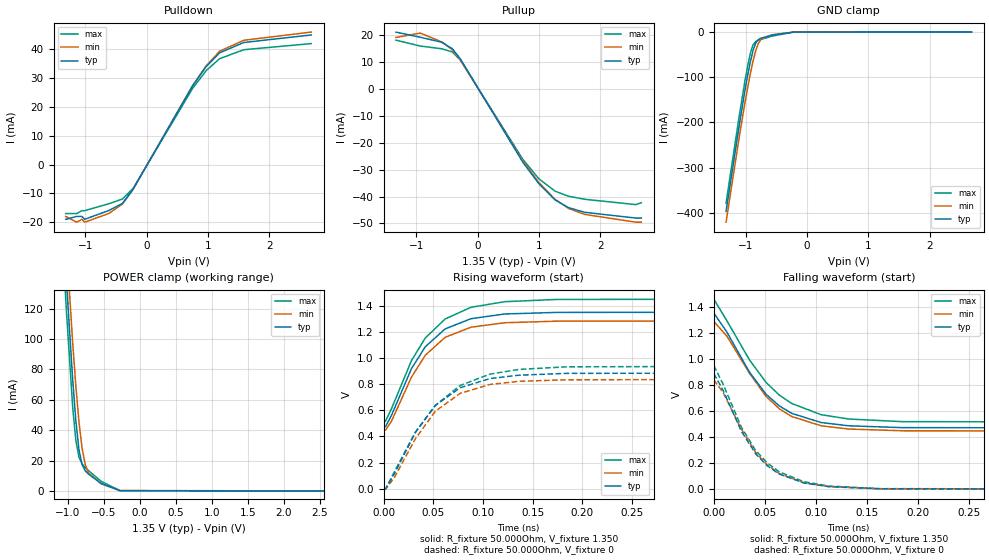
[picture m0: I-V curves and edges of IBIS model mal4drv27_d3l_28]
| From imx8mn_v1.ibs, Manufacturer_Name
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[Model] mal4drv27_d3l_28
Model_type   I/O
Polarity   Non-Inverting
Enable   Active-High
C_comp   1.534pF   1.526pF   1.541pF
C_comp_pullup   672.952fF   657.747fF   679.061fF
C_comp_pulldown 805.206fF   796.471fF   820.214fF
Vinh = 805.000mV
Vinl = 545.000mV
Vmeas = 675.000mV
Vref = 675.000mV
Rref = 50Ohms
Cref = 0pF
[Model Spec]
Vinh   805.000mV   772.000mV   855.000mV
Vinl   545.000mV   512.000mV   595.000mV
Vmeas   675.000mV   642.000mV   725.000mV
Vref   675.000mV   642.000mV   725.000mV
D_overshoot_ampl_h 0.4 NA   NA
D_overshoot_ampl_l 0.4 NA   NA
D_overshoot_area_l 110.000m NA   NA
D_overshoot_area_h 110.000m NA   NA
|[Receiver Thresholds]
|Vth = 675.000mV
|Vth_min = 642.000mV
|Vth_max = 725.000mV
|Vinh_ac = 150.000mV
|Vinh_dc = 100.000mV
|Vinl_ac = -150.000mV
|Vinl_dc = -100.000mV
|Tslew_ac = 5.000ns
|Threshold_sensitivity = 0.5
|Reference_supply Pullup_ref
[Temperature Range]   25.000   125.000   -40.000
[Voltage Range]   1.350V   1.283V   1.450V
[GND Clamp Reference]   0.00V   0.00V   0.00V
|[C Comp Corner]
|| variable   typ   min   max
|C_comp 1.541pF   1.526pF   1.534pF
|C_comp_pullup 679.061fF   657.747fF   672.952fF
|C_comp_pulldown 805.206fF   820.214fF   796.471fF
[Pulldown Reference]   0.00V   0.00V   0.00V
[POWER Clamp Reference]   1.350V   1.283V   1.450V
[Pullup Reference]   1.350V   1.283V   1.450V
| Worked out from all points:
|   slope of the pulldown table from 0 to 0.203 V, typ, clamps not added: 26.2 ohm
|   slope of the pullup table from 0 to 0.203 V, typ, clamps not added: 25.8 ohm
|   GND clamp passes 1 mA (typ) near -0.34 V on its own axis
|   POWER clamp passes 1 mA (typ) near -0.37 V on its own axis
|   rising waveform, R_fixture 50.000Ohm, V_fixture 1.350: 20-80 % time 40.8ps typ, 40.3ps min, 43.2ps max; typ from 0.465 V to 1.35 V
|   rising waveform, R_fixture 50.000Ohm, V_fixture 0: 20-80 % time 48ps typ, 46.9ps min, 54.3ps max; typ from 0 V to 0.885 V
|   falling waveform, R_fixture 50.000Ohm, V_fixture 1.350: 20-80 % time 47.9ps typ, 47.3ps min, 52.8ps max; typ from 1.35 V to 0.469 V
|   falling waveform, R_fixture 50.000Ohm, V_fixture 0: 20-80 % time 40.7ps typ, 41.3ps min, 42.4ps max; typ from 0.887 V to 0 V
[GND Clamp]
-1.318V   -397mA     -421mA     -379mA
-1.099V   -203mA     -229mA     -182mA
-1.011V   -130mA     -157mA     -109mA
-966.7mV  -96.76mA   -124mA     -75.62mA
-922.7mV  -66.15mA   -92.44mA   -47.23mA
-878.8mV  -40.87mA   -64.33mA   -28.32mA
-834.8mV  -24.17mA   -41.16mA   -20.75mA
-790.9mV  -16.5mA    -24.84mA   -17.97mA
-747mV    -13.39mA   -15.69mA   -16.02mA
-571.2mV  -6.876mA   -6.005mA   -9.023mA
-219.7mV  -49.34uA   -80.18uA   -119uA
2.68V     51.21nA    1.31uA     23.01nA
[Power Clamp]
-1.33V    409mA      430mA      393.3mA
-1.111V   214mA      236.6mA    194.7mA
-1.023V   140mA      164.6mA    120.2mA
-934.8mV  73.93mA    98.06mA    55.78mA
-890.9mV  46.71mA    69.56mA    33.54mA
-847mV    27.2mA     45.54mA    22.2mA
-803mV    17.25mA    27.9mA     17.76mA
-759.1mV  13.27mA    17.3mA     15.42mA
-715.2mV  11.13mA    11.9mA     13.45mA
-539.4mV  4.955mA    4.74mA     6.349mA
-275.8mV  101uA      270.7uA    142.8uA
2.668V    -162nA     -1.898uA   -65.08nA
[Pulldown]
-1.318V   -19mA      -18mA      -17mA
-1.142V   -18mA      -20mA      -17mA
-1.054V   -18mA      -19mA      -16mA
-1.011V   -19mA      -20mA      -16mA
-615.2mV  -15.94mA   -16.96mA   -13.59mA
-395.5mV  -13.48mA   -13.72mA   -11.96mA
-219.7mV  -8.487mA   -8.449mA   -8.219mA
747mV     27.29mA    27.39mA    26.42mA
966.7mV   33.95mA    34.22mA    32.56mA
1.186V    38.77mA    39.33mA    36.76mA
1.582V    42.39mA    43.16mA    39.88mA
2.68V     45mA       46mA       42mA
[Pullup]
-1.33V    21mA       19mA       18mA
-934.8mV  19.09mA    20.63mA    15.83mA
-583.3mV  17.23mA    17.37mA    14.8mA
-407.6mV  14.77mA    14.35mA    13.61mA
-275.8mV  10.89mA    10.56mA    10.47mA
734.8mV   -27.19mA   -26.69mA   -26.12mA
998.5mV   -35.28mA   -34.76mA   -33.41mA
1.262V    -41.24mA   -41.05mA   -38.01mA
1.482V    -44.12mA   -44.44mA   -39.9mA
1.746V    -45.85mA   -46.64mA   -41.02mA
2.58V     -48mA      -49.52mA   -43mA
2.668V    -48mA      -49.52mA   -42.28mA
[Ramp]
R_load=50.000Ohm
dV/dt_r   529.800mV/45.500ps  502.199mV/45.000ps  562.200mV/49.500ps
dV/dt_f   529.800mV/45.500ps  502.199mV/45.000ps  562.200mV/49.000ps
[Rising waveform]
R_fixture=50.000Ohm
V_fixture=1.350
V_fixture_min=1.283
V_fixture_max=1.450
0s        465mV      441mV      506mV
2ps       476mV      450mV      518mV
8ps       563mV      518mV      614mV
28ps      918mV      853mV      979mV
42ps      1.086V     1.021V     1.153V
62ps      1.222V     1.158V     1.298V
88ps      1.3V       1.235V     1.387V
122ps     1.336V     1.269V     1.43V
174ps     1.348V     1.281V     1.447V
470ps     1.35V      1.283V     1.45V
[Rising waveform]
R_fixture=50.000Ohm
V_fixture=0
0s        -21.58uV   -3.15mV    -739.6uV
2ps       -21.58uV   -3.15mV    -739.6uV
11ps      117mV      88.59mV    133mV
32ps      431mV      383mV      433mV
52ps      636mV      592mV      637mV
77ps      772mV      729mV      789mV
107ps     842mV      797mV      876mV
136ps     868mV      821mV      912mV
184ps     882mV      833mV      932mV
471ps     885mV      836mV      938mV
[Falling waveform]
R_fixture=50.000Ohm
V_fixture=1.350
V_fixture_min=1.283
V_fixture_max=1.450
0s        1.352V     1.287V     1.458V
13ps      1.202V     1.172V     1.289V
35ps      896mV      888mV      990mV
51ps      729mV      713mV      820mV
64ps      639mV      617mV      722mV
76ps      582mV      558mV      658mV
105ps     511mV      486mV      571mV
132ps     486mV      461mV      538mV
184ps     472mV      448mV      518mV
470ps     469mV      445mV      514mV
[Falling waveform]
R_fixture=50.000Ohm
V_fixture=0
0s        887mV      838mV      948mV
9ps       759mV      743mV      807mV
27ps      444mV      461mV      475mV
41ps      271mV      282mV      296mV
52ps      181mV      188mV      203mV
64ps      116mV      120mV      133mV
88ps      48.2mV     48.41mV    57.09mV
113ps     19.14mV    19.14mV    23.73mV
162ps     3.15mV     3.058mV    4.146mV
469ps     14.03uV    17.61uV    15.29uV
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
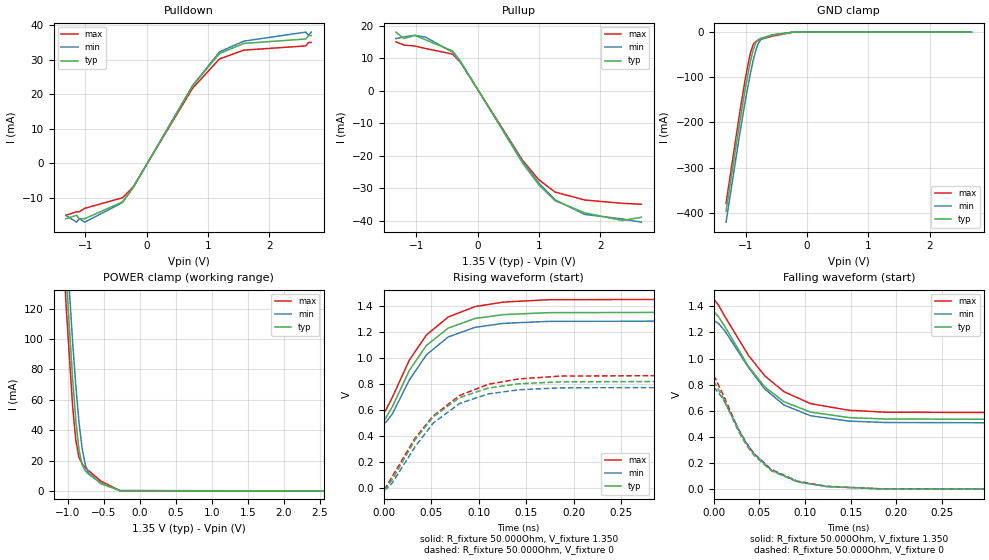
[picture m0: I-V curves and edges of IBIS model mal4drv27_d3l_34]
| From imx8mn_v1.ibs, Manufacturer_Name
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[Model] mal4drv27_d3l_34
Model_type   I/O
Polarity   Non-Inverting
Enable   Active-High
C_comp   1.534pF   1.526pF   1.541pF
C_comp_pullup   672.952fF   657.747fF   679.061fF
C_comp_pulldown 805.206fF   796.471fF   820.214fF
Vinh = 805.000mV
Vinl = 545.000mV
Vmeas = 675.000mV
Vref = 675.000mV
Rref = 50Ohms
Cref = 0pF
[Model Spec]
Vinh   805.000mV   772.000mV   855.000mV
Vinl   545.000mV   512.000mV   595.000mV
Vmeas   675.000mV   642.000mV   725.000mV
Vref   675.000mV   642.000mV   725.000mV
D_overshoot_ampl_h 0.4 NA   NA
D_overshoot_ampl_l 0.4 NA   NA
D_overshoot_area_l 110.000m NA   NA
D_overshoot_area_h 110.000m NA   NA
|[Receiver Thresholds]
|Vth = 675.000mV
|Vth_min = 642.000mV
|Vth_max = 725.000mV
|Vinh_ac = 150.000mV
|Vinh_dc = 100.000mV
|Vinl_ac = -150.000mV
|Vinl_dc = -100.000mV
|Tslew_ac = 5.000ns
|Threshold_sensitivity = 0.5
|Reference_supply Pullup_ref
[Temperature Range]   25.000   125.000   -40.000
[Voltage Range]   1.350V   1.283V   1.450V
[GND Clamp Reference]   0.00V   0.00V   0.00V
|[C Comp Corner]
|| variable   typ   min   max
|C_comp 1.541pF   1.526pF   1.534pF
|C_comp_pullup 679.061fF   657.747fF   672.952fF
|C_comp_pulldown 805.206fF   820.214fF   796.471fF
[Pulldown Reference]   0.00V   0.00V   0.00V
[POWER Clamp Reference]   1.350V   1.283V   1.450V
[Pullup Reference]   1.350V   1.283V   1.450V
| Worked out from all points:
|   slope of the pulldown table from 0 to 0.203 V, typ, clamps not added: 31.9 ohm
|   slope of the pullup table from 0 to 0.203 V, typ, clamps not added: 31.3 ohm
|   GND clamp passes 1 mA (typ) near -0.34 V on its own axis
|   POWER clamp passes 1 mA (typ) near -0.37 V on its own axis
|   rising waveform, R_fixture 50.000Ohm, V_fixture 1.350: 20-80 % time 45.5ps typ, 45.3ps min, 47.7ps max; typ from 0.527 V to 1.35 V
|   rising waveform, R_fixture 50.000Ohm, V_fixture 0: 20-80 % time 54.1ps typ, 52.9ps min, 60.7ps max; typ from -0.004 V to 0.822 V
|   falling waveform, R_fixture 50.000Ohm, V_fixture 1.350: 20-80 % time 54.1ps typ, 53ps min, 58.7ps max; typ from 1.36 V to 0.532 V
|   falling waveform, R_fixture 50.000Ohm, V_fixture 0: 20-80 % time 45.5ps typ, 46ps min, 46.7ps max; typ from 0.826 V to 0 V
[GND Clamp]
-1.318V   -397mA     -421mA     -379mA
-1.099V   -203mA     -229mA     -182mA
-1.011V   -130mA     -157mA     -109mA
-966.7mV  -96.76mA   -124mA     -75.62mA
-922.7mV  -66.15mA   -92.44mA   -47.23mA
-878.8mV  -40.87mA   -64.33mA   -28.32mA
-834.8mV  -24.17mA   -41.16mA   -20.75mA
-790.9mV  -16.5mA    -24.84mA   -17.97mA
-747mV    -13.39mA   -15.69mA   -16.02mA
-571.2mV  -6.876mA   -6.005mA   -9.023mA
-219.7mV  -49.34uA   -80.18uA   -119uA
2.68V     51.21nA    1.31uA     23.01nA
[Power Clamp]
-1.33V    409mA      430mA      393.3mA
-1.111V   214mA      236.6mA    194.7mA
-1.023V   140mA      164.6mA    120.2mA
-934.8mV  73.93mA    98.06mA    55.78mA
-890.9mV  46.71mA    69.56mA    33.54mA
-847mV    27.2mA     45.54mA    22.2mA
-803mV    17.25mA    27.9mA     17.76mA
-759.1mV  13.27mA    17.3mA     15.42mA
-715.2mV  11.13mA    11.9mA     13.45mA
-539.4mV  4.955mA    4.74mA     6.349mA
-275.8mV  101uA      270.7uA    142.8uA
2.668V    -162nA     -1.898uA   -65.08nA
[Pulldown]
-1.318V   -16mA      -15mA      -15mA
-1.142V   -15mA      -17mA      -14mA
-1.099V   -16mA      -16mA      -14mA
-1.011V   -16mA      -17mA      -13mA
-395.5mV  -11.14mA   -11.34mA   -9.931mA
-219.7mV  -6.979mA   -6.949mA   -6.77mA
747mV     22.43mA    22.51mA    21.75mA
1.186V    31.8mA     32.28mA    30.23mA
1.582V    34.72mA    35.38mA    32.78mA
2.592V    36mA       38mA       34mA
2.636V    37mA       37mA       35mA
2.68V     37mA       38mA       35mA
[Pullup]
-1.33V    18mA       16mA       15mA
-1.199V   16mA       16.52mA    14mA
-1.023V   17mA       17mA       13.72mA
-847mV    15.61mA    16.44mA    12.94mA
-407.6mV  12.19mA    11.82mA    11.23mA
-275.8mV  8.959mA    8.681mA    8.62mA
734.8mV   -22.36mA   -21.89mA   -21.49mA
998.5mV   -29mA      -28.5mA    -27.48mA
1.262V    -33.89mA   -33.62mA   -31.24mA
1.746V    -37.65mA   -38.14mA   -33.69mA
2.361V    -40mA      -39.52mA   -34.72mA
2.668V    -39mA      -40.52mA   -35mA
[Ramp]
R_load=50.000Ohm
dV/dt_r   492.000mV/50.500ps  465.898mV/50.000ps  520.800mV/55.500ps
dV/dt_f   492.000mV/51.000ps  465.899mV/50.500ps  520.800mV/53.500ps
[Rising waveform]
R_fixture=50.000Ohm
V_fixture=1.350
V_fixture_min=1.283
V_fixture_max=1.450
0s        527mV      503mV      582mV
2ps       536mV      503mV      594mV
9ps       623mV      568mV      695mV
27ps      903mV      830mV      982mV
45ps      1.095V     1.023V     1.175V
68ps      1.228V     1.16V      1.313V
96ps      1.301V     1.233V     1.392V
126ps     1.331V     1.264V     1.427V
174ps     1.346V     1.279V     1.445V
470ps     1.35V      1.283V     1.45V
[Rising waveform]
R_fixture=50.000Ohm
V_fixture=0
0s        -3.876mV   -3.515mV   -6.368mV
3ps       3.836mV    -3.515mV   14.72mV
9ps       66.86mV    40.56mV    90.27mV
33ps      371mV      318mV      384mV
52ps      547mV      499mV      554mV
80ps      696mV      651mV      712mV
110ps     768mV      723mV      797mV
142ps     801mV      755mV      838mV
186ps     816mV      770mV      860mV
471ps     822mV      775mV      869mV
[Falling waveform]
R_fixture=50.000Ohm
V_fixture=1.350
V_fixture_min=1.283
V_fixture_max=1.450
0s        1.357V     1.288V     1.455V
5ps       1.322V     1.27V      1.41V
12ps      1.246V     1.213V     1.324V
38ps      940mV      932mV      1.024V
56ps      782mV      766mV      867mV
77ps      669mV      644mV      746mV
106ps     590mV      562mV      655mV
148ps     548mV      521mV      604mV
189ps     537mV      510mV      589mV
470ps     532mV      505mV      583mV
[Falling waveform]
R_fixture=50.000Ohm
V_fixture=0
0s        826mV      781mV      872mV
10ps      702mV      694mV      727mV
27ps      443mV      462mV      457mV
36ps      335mV      352mV      349mV
44ps      260mV      273mV      273mV
63ps      141mV      147mV      151mV
92ps      54.91mV    56.83mV    60.65mV
124ps     19.38mV    19.7mV     21.96mV
181ps     3.038mV    2.943mV    3.504mV
469ps     13.3uV     16.64uV    14.35uV
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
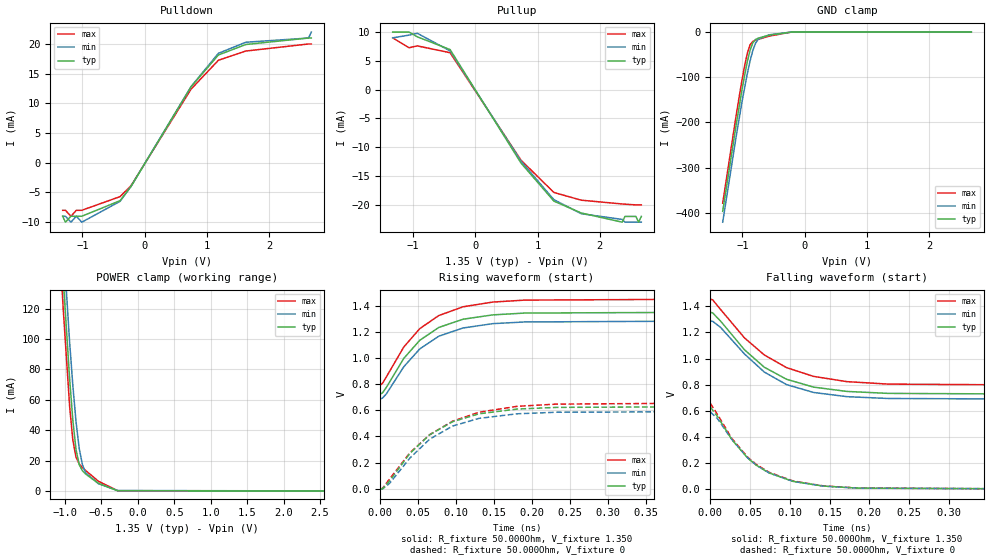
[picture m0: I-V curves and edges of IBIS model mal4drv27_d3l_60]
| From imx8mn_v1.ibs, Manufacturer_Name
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[Model] mal4drv27_d3l_60
Model_type   I/O
Polarity   Non-Inverting
Enable   Active-High
C_comp   1.534pF   1.526pF   1.541pF
C_comp_pullup   672.952fF   657.747fF   679.061fF
C_comp_pulldown 805.206fF   796.471fF   820.214fF
Vinh = 805.000mV
Vinl = 545.000mV
Vmeas = 675.000mV
Vref = 675.000mV
Rref = 50Ohms
Cref = 0pF
[Model Spec]
Vinh   805.000mV   772.000mV   855.000mV
Vinl   545.000mV   512.000mV   595.000mV
Vmeas   675.000mV   642.000mV   725.000mV
Vref   675.000mV   642.000mV   725.000mV
D_overshoot_ampl_h 0.4 NA   NA
D_overshoot_ampl_l 0.4 NA   NA
D_overshoot_area_l 110.000m NA   NA
D_overshoot_area_h 110.000m NA   NA
|[Receiver Thresholds]
|Vth = 675.000mV
|Vth_min = 642.000mV
|Vth_max = 725.000mV
|Vinh_ac = 150.000mV
|Vinh_dc = 100.000mV
|Vinl_ac = -150.000mV
|Vinl_dc = -100.000mV
|Tslew_ac = 5.000ns
|Threshold_sensitivity = 0.5
|Reference_supply Pullup_ref
[Temperature Range]   25.000   125.000   -40.000
[Voltage Range]   1.350V   1.283V   1.450V
[GND Clamp Reference]   0.00V   0.00V   0.00V
|[C Comp Corner]
|| variable   typ   min   max
|C_comp 1.541pF   1.526pF   1.534pF
|C_comp_pullup 679.061fF   657.747fF   672.952fF
|C_comp_pulldown 805.206fF   820.214fF   796.471fF
[Pulldown Reference]   0.00V   0.00V   0.00V
[POWER Clamp Reference]   1.350V   1.283V   1.450V
[Pullup Reference]   1.350V   1.283V   1.450V
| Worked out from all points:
|   slope of the pulldown table from 0 to 0.203 V, typ, clamps not added: 55.9 ohm
|   slope of the pullup table from 0 to 0.203 V, typ, clamps not added: 54.9 ohm
|   GND clamp passes 1 mA (typ) near -0.34 V on its own axis
|   POWER clamp passes 1 mA (typ) near -0.37 V on its own axis
|   rising waveform, R_fixture 50.000Ohm, V_fixture 1.350: 20-80 % time 59.4ps typ, 59.4ps min, 60.8ps max; typ from 0.723 V to 1.35 V
|   rising waveform, R_fixture 50.000Ohm, V_fixture 0: 20-80 % time 71ps typ, 69.2ps min, 79.1ps max; typ from -0.001 V to 0.628 V
|   falling waveform, R_fixture 50.000Ohm, V_fixture 1.350: 20-80 % time 71.1ps typ, 69.1ps min, 77.3ps max; typ from 1.35 V to 0.726 V
|   falling waveform, R_fixture 50.000Ohm, V_fixture 0: 20-80 % time 59.1ps typ, 59.1ps min, 60.2ps max; typ from 0.629 V to 0 V
[GND Clamp]
-1.318V   -397mA     -421mA     -379mA
-1.099V   -203mA     -229mA     -182mA
-1.011V   -130mA     -157mA     -109mA
-966.7mV  -96.76mA   -124mA     -75.62mA
-922.7mV  -66.15mA   -92.44mA   -47.23mA
-878.8mV  -40.87mA   -64.33mA   -28.32mA
-834.8mV  -24.17mA   -41.16mA   -20.75mA
-790.9mV  -16.5mA    -24.84mA   -17.97mA
-747mV    -13.39mA   -15.69mA   -16.02mA
-571.2mV  -6.876mA   -6.005mA   -9.023mA
-219.7mV  -49.34uA   -80.18uA   -119uA
2.68V     51.21nA    1.31uA     23.01nA
[Power Clamp]
-1.33V    409mA      430mA      393.3mA
-1.111V   214mA      236.6mA    194.7mA
-1.023V   140mA      164.6mA    120.2mA
-934.8mV  73.93mA    98.06mA    55.78mA
-890.9mV  46.71mA    69.56mA    33.54mA
-847mV    27.2mA     45.54mA    22.2mA
-803mV    17.25mA    27.9mA     17.76mA
-759.1mV  13.27mA    17.3mA     15.42mA
-715.2mV  11.13mA    11.9mA     13.45mA
-539.4mV  4.955mA    4.74mA     6.349mA
-275.8mV  101uA      270.7uA    142.8uA
2.668V    -162nA     -1.898uA   -65.08nA
[Pulldown]
-1.318V   -9mA       -9mA       -8mA
-1.274V   -10mA      -9mA       -8mA
-1.186V   -9mA       -10mA      -9mA
-1.099V   -9mA       -9mA       -8mA
-1.011V   -9mA       -10mA      -8mA
-395.5mV  -6.38mA    -6.489mA   -5.695mA
-219.7mV  -3.981mA   -3.966mA   -3.865mA
747mV     12.79mA    12.84mA    12.41mA
1.186V    18.15mA    18.43mA    17.26mA
1.626V    19.91mA    20.29mA    18.81mA
2.636V    21mA       21mA       20mA
2.68V     21mA       22mA       20mA
[Pullup]
-1.33V    10mA       9mA        9mA
-1.067V   10mA       9.476mA    7.277mA
-934.8mV  9.18mA     9.795mA    7.605mA
-407.6mV  6.966mA    6.74mA     6.42mA
734.8mV   -12.75mA   -12.45mA   -12.26mA
1.262V    -19.34mA   -19.09mA   -17.84mA
1.702V    -21.4mA    -21.53mA   -19.18mA
2.361V    -23mA      -22.52mA   -19.84mA
2.405V    -22mA      -23mA      -19.87mA
2.58V     -22mA      -23mA      -20mA
2.624V    -23mA      -23mA      -20mA
2.668V    -22mA      -23mA      -20mA
[Ramp]
R_load=50.000Ohm
dV/dt_r   375.600mV/66.000ps  355.498mV/65.500ps  393.300mV/71.000ps
dV/dt_f   375.600mV/66.000ps  355.498mV/65.000ps  393.300mV/69.500ps
[Rising waveform]
R_fixture=50.000Ohm
V_fixture=1.350
V_fixture_min=1.283
V_fixture_max=1.450
0s        723mV      685mV      792mV
3ps       734mV      694mV      807mV
8ps       775mV      725mV      855mV
31ps      997mV      933mV      1.084V
52ps      1.135V     1.069V     1.224V
77ps      1.233V     1.166V     1.324V
109ps     1.296V     1.229V     1.391V
148ps     1.329V     1.262V     1.427V
190ps     1.343V     1.275V     1.442V
470ps     1.35V      1.283V     1.45V
[Rising waveform]
R_fixture=50.000Ohm
V_fixture=0
0s        -959.1uV   -806uV     -3.165mV
3ps       -959.1uV   -806uV     3.463mV
12ps      58.2mV     39.59mV    73.09mV
39ps      270mV      235mV      275mV
65ps      413mV      379mV      413mV
95ps      512mV      479mV      516mV
130ps     573mV      538mV      585mV
180ps     609mV      573mV      630mV
232ps     622mV      585mV      647mV
472ps     628mV      590mV      656mV
[Falling waveform]
R_fixture=50.000Ohm
V_fixture=1.350
V_fixture_min=1.283
V_fixture_max=1.450
0s        1.354V     1.285V     1.455V
3ps       1.349V     1.285V     1.449V
13ps      1.286V     1.238V     1.375V
43ps      1.067V     1.035V     1.158V
68ps      933mV      896mV      1.027V
96ps      841mV      800mV      930mV
130ps     781mV      740mV      863mV
172ps     748mV      708mV      823mV
224ps     733mV      694mV      804mV
471ps     726mV      688mV      795mV
[Falling waveform]
R_fixture=50.000Ohm
V_fixture=0
0s        629mV      591mV      658mV
9ps       557mV      540mV      572mV
27ps      381mV      381mV      389mV
47ps      238mV      239mV      245mV
58ps      183mV      183mV      189mV
74ps      124mV      124mV      129mV
104ps     59.82mV    59.49mV    63.03mV
142ps     23.94mV    23.33mV    25.22mV
185ps     8.191mV    7.985mV    8.853mV
469ps     19.34uV    22.16uV    19.89uV
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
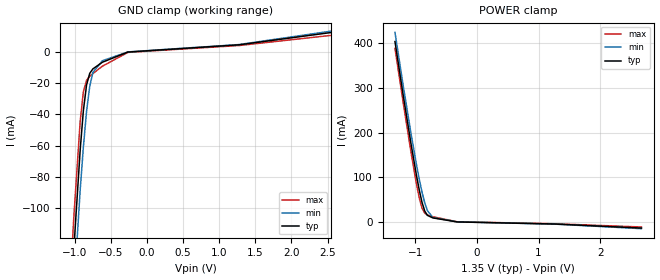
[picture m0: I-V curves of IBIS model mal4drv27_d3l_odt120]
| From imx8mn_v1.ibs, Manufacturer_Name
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[Model] mal4drv27_d3l_odt120
Model_type   Input
Polarity   Non-Inverting
Enable   Active-High
C_comp   1.576pF   1.527pF   1.608pF
C_comp_power_clamp   705.785fF   664.403fF   721.358fF
C_comp_gnd_clamp 804.044fF   799.743fF   804.337fF
Vinh = 805.000mV
Vinl = 545.000mV
[Model Spec]
D_overshoot_ampl_h 0.4 NA   NA
D_overshoot_ampl_l 0.4 NA   NA
D_overshoot_area_l 110.000m NA   NA
D_overshoot_area_h 110.000m NA   NA
|[Receiver Thresholds]
|Vth = 675.000mV
|Vth_min = 642.000mV
|Vth_max = 725.000mV
|Vinh_ac = 150.000mV
|Vinh_dc = 100.000mV
|Vinl_ac = -150.000mV
|Vinl_dc = -100.000mV
|Tslew_ac = 5.000ns
|Threshold_sensitivity = 0.5
|Reference_supply Power_clamp_ref
[Temperature Range]   25.000   125.000   -40.000
[Voltage Range]   1.350V   1.283V   1.450V
[GND Clamp Reference]   0.00V   0.00V   0.00V
|[C Comp Corner]
|| variable   typ   min   max
|C_comp 1.576pF   1.527pF   1.608pF
|C_comp_pullup 705.785fF   664.403fF   721.358fF
|C_comp_pulldown 799.743fF   804.337fF   804.044fF
[POWER Clamp Reference]   1.350V   1.283V   1.450V
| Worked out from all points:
|   GND clamp passes 1 mA (typ) near -0.38 V on its own axis
|   POWER clamp passes 1 mA (typ) near -0.41 V on its own axis
[GND Clamp]
-1.318V   -391.2mA   -414.4mA   -374.1mA
-1.099V   -198.7mA   -224mA     -178.3mA
-1.011V   -126.3mA   -153.6mA   -105.8mA
-922.7mV  -62.55mA   -88.29mA   -44.18mA
-878.8mV  -37.54mA   -60.91mA   -25.48mA
-834.8mV  -21.09mA   -38.03mA   -18.12mA
-790.9mV  -13.68mA   -21.98mA   -15.54mA
-747mV    -10.82mA   -13.11mA   -13.8mA
-615.2mV  -6.544mA   -5.581mA   -9.094mA
-263.6mV  -42.75uA   49.31uA    -264.2uA
1.274V    4.587mA    4.769mA    4.143mA
2.68V     13.28mA    14.23mA    11.3mA
[Power Clamp]
-1.33V    403.7mA    424.2mA    388.5mA
-1.199V   285.6mA    307.2mA    268.9mA
-1.067V   172.4mA    195.6mA    153.1mA
-978.8mV  102mA      126.3mA    82.8mA
-934.8mV  70.53mA    94.75mA    52.8mA
-890.9mV  43.56mA    66.34mA    30.78mA
-847mV    24.3mA     42.58mA    19.65mA
-803mV    14.61mA    25.2mA     15.42mA
-715.2mV  8.99mA     9.7mA      11.56mA
-319.7mV  -27.07uA   139.7uA    301.6uA
1.262V    -4.734mA   -4.93mA    -4.158mA
2.668V    -13.76mA   -15.08mA   -11.35mA
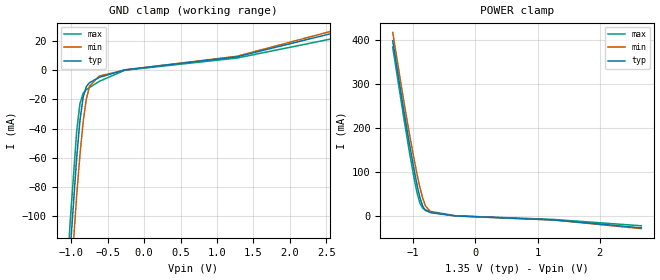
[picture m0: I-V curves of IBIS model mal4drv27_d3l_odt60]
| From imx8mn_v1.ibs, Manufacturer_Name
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[Model] mal4drv27_d3l_odt60
Model_type   Input
Polarity   Non-Inverting
Enable   Active-High
C_comp   1.610pF   1.544pF   1.666pF
C_comp_power_clamp   734.783fF   683.510fF   762.736fF
C_comp_gnd_clamp 795.146fF   794.164fF   808.504fF
Vinh = 805.000mV
Vinl = 545.000mV
[Model Spec]
D_overshoot_ampl_h 0.4 NA   NA
D_overshoot_ampl_l 0.4 NA   NA
D_overshoot_area_l 110.000m NA   NA
D_overshoot_area_h 110.000m NA   NA
|[Receiver Thresholds]
|Vth = 675.000mV
|Vth_min = 642.000mV
|Vth_max = 725.000mV
|Vinh_ac = 150.000mV
|Vinh_dc = 100.000mV
|Vinl_ac = -150.000mV
|Vinl_dc = -100.000mV
|Tslew_ac = 5.000ns
|Threshold_sensitivity = 0.5
|Reference_supply Power_clamp_ref
[Temperature Range]   25.000   125.000   -40.000
[Voltage Range]   1.350V   1.283V   1.450V
[GND Clamp Reference]   0.00V   0.00V   0.00V
|[C Comp Corner]
|| variable   typ   min   max
|C_comp 1.610pF   1.544pF   1.666pF
|C_comp_pullup 734.783fF   683.510fF   762.736fF
|C_comp_pulldown 795.146fF   794.164fF   808.504fF
[POWER Clamp Reference]   1.350V   1.283V   1.450V
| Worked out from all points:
|   GND clamp passes 1 mA (typ) near -0.41 V on its own axis
|   POWER clamp passes 1 mA (typ) near -0.45 V on its own axis
[GND Clamp]
-1.318V   -385.6mA   -408.7mA   -369.2mA
-1.099V   -194.5mA   -219.8mA   -174.6mA
-1.011V   -122.6mA   -149.1mA   -102.6mA
-922.7mV  -59.41mA   -85.31mA   -41.48mA
-878.8mV  -34.62mA   -58.07mA   -22.97mA
-834.8mV  -18.41mA   -35.42mA   -15.8mA
-790.9mV  -11.24mA   -19.61mA   -13.41mA
-747mV    -8.612mA   -10.97mA   -11.87mA
-615.2mV  -4.993mA   -4.105mA   -7.721mA
-263.6mV  187.6uA    123.8uA    -94.83uA
1.274V    9.126mA    9.508mA    8.276mA
2.68V     26.42mA    28.13mA    22.52mA
[Power Clamp]
-1.33V    398.6mA    417.8mA    384.4mA
-1.155V   242.8mA    264.1mA    226mA
-1.067V   168.9mA    191.4mA    149.8mA
-978.8mV  99.02mA    123.1mA    79.89mA
-934.8mV  67.46mA    91.71mA    50.08mA
-890.9mV  40.72mA    63.42mA    28.26mA
-847mV    21.69mA    39.9mA     17.33mA
-803mV    12.23mA    22.76mA    13.31mA
-715.2mV  7.068mA    7.701mA    9.851mA
-319.7mV  -241.4uA   -233uA     126.4uA
1.262V    -9.43mA    -9.512mA   -8.29mA
2.668V    -27.42mA   -29.22mA   -22.67mA
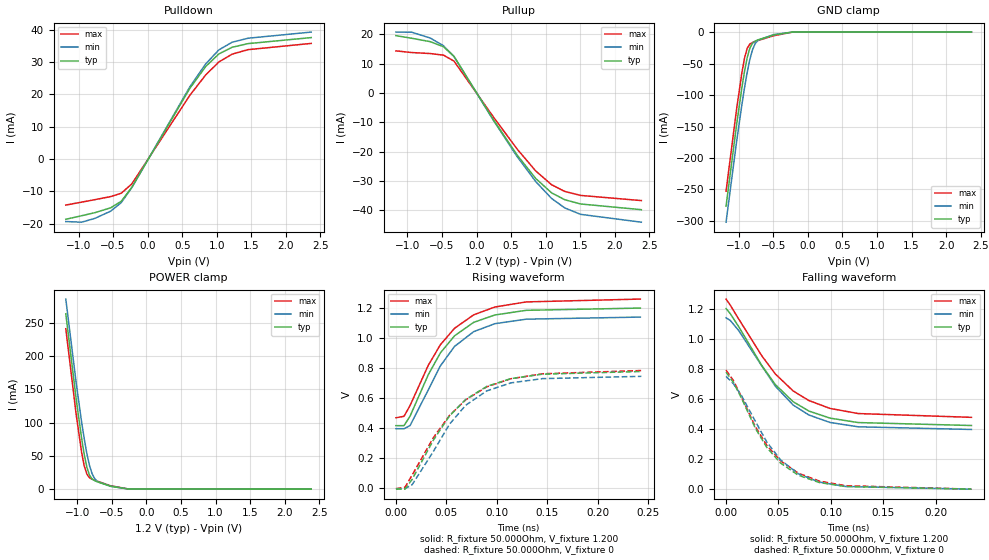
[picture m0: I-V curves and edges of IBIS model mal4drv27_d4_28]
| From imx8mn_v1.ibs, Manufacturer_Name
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[Model] mal4drv27_d4_28
Model_type   I/O
Polarity   Non-Inverting
Enable   Active-High
C_comp   1.537pF   1.528pF   1.543pF
C_comp_pullup   676.913fF   661.750fF   681.847fF
C_comp_pulldown 805.500fF   796.656fF   821.186fF
Vinh = 829.000mV
Vinl = 714.000mV
Vmeas = 771.000mV
Vref = 771.000mV
Rref = 50Ohms
Cref = 0pF
[Model Spec]
Vinh   829.000mV   790.000mV   868.000mV
Vinl   714.000mV   675.000mV   753.000mV
Vmeas   771.000mV   733.000mV   810.000mV
Vref   771.000mV   733.000mV   810.000mV
D_overshoot_ampl_h 0.24 NA   NA
D_overshoot_ampl_l 0.24 NA   NA
D_overshoot_area_l 300.000m NA   NA
D_overshoot_area_h 300.000m NA   NA
|[Receiver Thresholds]
|Vth = 771.000mV
|Vth_min = 733.000mV
|Vth_max = 810.000mV
|Vinh_ac = 68.000mV
|Vinh_dc = 68.000mV
|Vinl_ac = -68.000mV
|Vinl_dc = -68.000mV
|Tslew_ac = 5.000ns
|Threshold_sensitivity = 0.5
|Reference_supply Pullup_ref
[Temperature Range]   25.000   125.000   -40.000
[Voltage Range]   1.200V   1.140V   1.260V
[GND Clamp Reference]   0.00V   0.00V   0.00V
|[C Comp Corner]
|| variable   typ   min   max
|C_comp 1.543pF   1.528pF   1.537pF
|C_comp_pullup 681.847fF   661.750fF   676.913fF
|C_comp_pulldown 805.500fF   821.186fF   796.656fF
[Pulldown Reference]   0.00V   0.00V   0.00V
[POWER Clamp Reference]   1.200V   1.140V   1.260V
[Pullup Reference]   1.200V   1.140V   1.260V
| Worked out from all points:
|   slope of the pulldown table from 0 to 0.18 V, typ, clamps not added: 26.7 ohm
|   slope of the pullup table from 0 to 0.18 V, typ, clamps not added: 26.4 ohm
|   GND clamp passes 1 mA (typ) near -0.34 V on its own axis
|   POWER clamp passes 1 mA (typ) near -0.37 V on its own axis
|   rising waveform, R_fixture 50.000Ohm, V_fixture 1.200: 20-80 % time 42.6ps typ, 40.7ps min, 45.4ps max; typ from 0.417 V to 1.2 V
|   rising waveform, R_fixture 50.000Ohm, V_fixture 0: 20-80 % time 51.1ps typ, 48ps min, 55.3ps max; typ from -0.007 V to 0.777 V
|   falling waveform, R_fixture 50.000Ohm, V_fixture 1.200: 20-80 % time 49.4ps typ, 48.3ps min, 53.3ps max; typ from 1.2 V to 0.424 V
|   falling waveform, R_fixture 50.000Ohm, V_fixture 0: 20-80 % time 41.3ps typ, 42.3ps min, 43.5ps max; typ from 0.779 V to 0 V
[GND Clamp]
-1.184V   -276.6mA   -302mA     -252.8mA
-1.031V   -146.8mA   -173.7mA   -122mA
-954.6mV  -88mA      -115mA     -64.4mA
-916.4mV  -62.15mA   -88.25mA   -41.23mA
-878.2mV  -40.64mA   -64.09mA   -25.82mA
-840mV    -25.66mA   -43.68mA   -19.12mA
-801.8mV  -17.83mA   -28.3mA    -16.59mA
-763.6mV  -14.37mA   -18.53mA   -15mA
-725.5mV  -12.44mA   -13.25mA   -13.58mA
-496.4mV  -4.591mA   -4.004mA   -5.798mA
-229.1mV  -67.51uA   -103.3uA   -163.9uA
2.367V    58.34nA    819.4nA    21.13nA
[Power Clamp]
-1.167V   263.1mA    285.3mA    240.8mA
-1.015V   133.8mA    158mA      110.6mA
-938.2mV  76.29mA    100.8mA    55.23mA
-900mV    51.9mA     75.31mA    34.8mA
-861.8mV  32.79mA    53.07mA    22.5mA
-823.6mV  20.9mA     35.29mA    17.2mA
-785.5mV  15.3mA     22.9mA     14.92mA
-747.3mV  12.67mA    15.53mA    13.31mA
-709.1mV  10.94mA    11.56mA    11.83mA
-518.2mV  4.347mA    4.291mA    5.122mA
-250.9mV  45.88uA    163.5uA    55.72uA
2.384V    -40.52nA   -814.5nA   -9.286nA
[Pulldown]
-1.184V   -18.6mA    -19.3mA    -14.2mA
-954.6mV  -17.5mA    -19.5mA    -13.3mA
-763.6mV  -16.56mA   -18.32mA   -12.53mA
-534.5mV  -15.05mA   -16.09mA   -11.58mA
-381.8mV  -13.03mA   -13.45mA   -10.54mA
-229.1mV  -8.718mA   -8.815mA   -7.673mA
610.9mV   21.91mA    22.36mA    19.75mA
840mV     28.65mA    29.46mA    26.05mA
1.031V    32.55mA    33.8mA     30.07mA
1.222V    34.6mA     36.16mA    32.47mA
1.451V    35.73mA    37.4mA     33.86mA
2.367V    37.6mA     39.3mA     35.8mA
[Pullup]
-1.167V   19.5mA     20.71mA    14.31mA
-938.2mV  18.61mA    20.66mA    13.74mA
-670.9mV  17.45mA    18.69mA    13.4mA
-480mV    15.73mA    16.07mA    12.86mA
-327.3mV  12.44mA    12.43mA    10.84mA
245.5mV   -9.235mA   -9.426mA   -8.282mA
589.1mV   -21.26mA   -21.79mA   -19.22mA
856.4mV   -29.19mA   -30.24mA   -26.62mA
1.085V    -34.06mA   -35.97mA   -31.3mA
1.276V    -36.41mA   -39.2mA    -33.58mA
1.505V    -37.85mA   -41.39mA   -34.94mA
2.384V    -39.8mA    -44.06mA   -36.7mA
[Ramp]
R_load=50.000Ohm
dV/dt_r   466.560mV/48.000ps  446.729mV/45.500ps  470.430mV/51.500ps
dV/dt_f   466.560mV/46.000ps  446.729mV/46.500ps  470.430mV/50.000ps
[Rising waveform]
R_fixture=50.000Ohm
V_fixture=1.200
V_fixture_min=1.140
V_fixture_max=1.260
0s        416.6mV    396.1mV    468.9mV
8ps       416.6mV    396.1mV    478.8mV
14ps      479.8mV    417.2mV    550.7mV
32ps      755.6mV    654.3mV    818mV
44ps      900.9mV    814.5mV    955.5mV
58ps      1.015V     944.3mV    1.065V
77ps      1.105V     1.043V     1.155V
98ps      1.154V     1.096V     1.207V
129ps     1.185V     1.126V     1.241V
242ps     1.2V       1.14V      1.26V
[Rising waveform]
R_fixture=50.000Ohm
V_fixture=0
0s        -6.648mV   -3.359mV   -3.395mV
9ps       -6.648mV   -3.359mV   6.056mV
16ps      57.89mV    22.63mV    86.32mV
37ps      319mV      243.7mV    336.1mV
53ps      481.3mV    425.6mV    483.8mV
69ps      590.7mV    552.2mV    588.1mV
90ps      678.4mV    648.4mV    675.2mV
114ps     730.1mV    701.7mV    729.4mV
145ps     759.5mV    729.8mV    762.2mV
243ps     777.4mV    745.2mV    783.9mV
[Falling waveform]
R_fixture=50.000Ohm
V_fixture=1.200
V_fixture_min=1.140
V_fixture_max=1.260
0s        1.202V     1.14V      1.265V
4ps       1.168V     1.123V     1.225V
12ps      1.082V     1.056V     1.133V
34ps      823.8mV    821.2mV    888.5mV
47ps      696.1mV    685.2mV    766.6mV
64ps      582mV      559.8mV    653.5mV
79ps      519.8mV    493.5mV    589.8mV
99ps      473mV      444.2mV    537.7mV
126ps     443.3mV    415.1mV    503.3mV
234ps     423.7mV    397.4mV    478mV
[Falling waveform]
R_fixture=50.000Ohm
V_fixture=0
0s        779.2mV    750.5mV    792.5mV
7ps       710.4mV    702mV      722.9mV
15ps      602mV      619.7mV    609.8mV
28ps      404.9mV    450.9mV    415.2mV
39ps      276.3mV    312.5mV    290.6mV
52ps      173.6mV    194.6mV    188.5mV
69ps      92.73mV    102.1mV    106.3mV
89ps      44.36mV    47.19mV    53.89mV
114ps     17.6mV     18.01mV    23.25mV
234ps     202.2uV    220.9uV    376.6uV
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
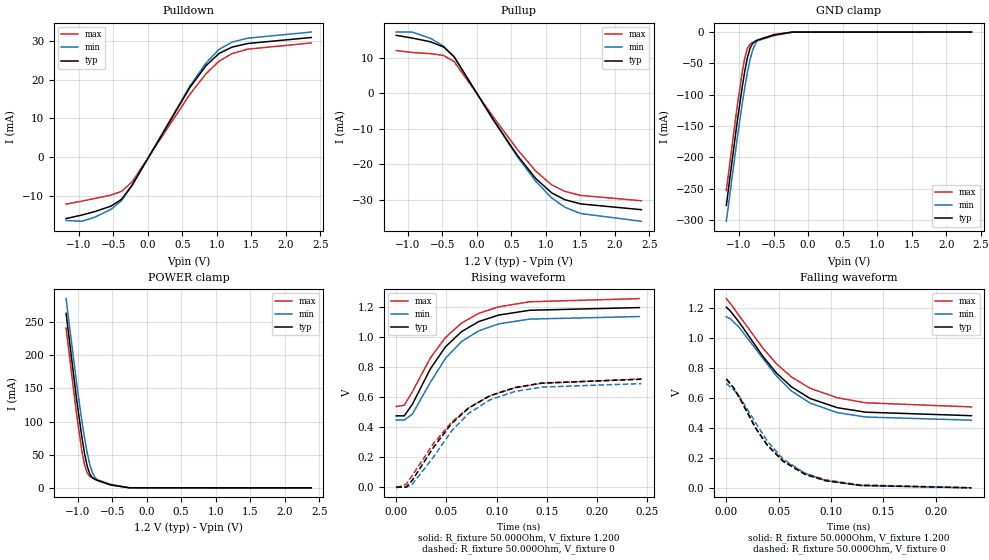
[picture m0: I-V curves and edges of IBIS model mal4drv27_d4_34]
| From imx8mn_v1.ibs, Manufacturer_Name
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[Model] mal4drv27_d4_34
Model_type   I/O
Polarity   Non-Inverting
Enable   Active-High
C_comp   1.537pF   1.528pF   1.543pF
C_comp_pullup   676.913fF   661.750fF   681.847fF
C_comp_pulldown 805.500fF   796.656fF   821.186fF
Vinh = 852.000mV
Vinl = 737.000mV
Vmeas = 795.000mV
Vref = 795.000mV
Rref = 50Ohms
Cref = 0pF
[Model Spec]
Vinh   852.000mV   812.000mV   892.000mV
Vinl   737.000mV   697.000mV   777.000mV
Vmeas   795.000mV   755.000mV   834.000mV
Vref   795.000mV   755.000mV   834.000mV
D_overshoot_ampl_h 0.24 NA   NA
D_overshoot_ampl_l 0.24 NA   NA
D_overshoot_area_l 300.000m NA   NA
D_overshoot_area_h 300.000m NA   NA
|[Receiver Thresholds]
|Vth = 795.000mV
|Vth_min = 755.000mV
|Vth_max = 834.000mV
|Vinh_ac = 68.000mV
|Vinh_dc = 68.000mV
|Vinl_ac = -68.000mV
|Vinl_dc = -68.000mV
|Tslew_ac = 5.000ns
|Threshold_sensitivity = 0.5
|Reference_supply Pullup_ref
[Temperature Range]   25.000   125.000   -40.000
[Voltage Range]   1.200V   1.140V   1.260V
[GND Clamp Reference]   0.00V   0.00V   0.00V
|[C Comp Corner]
|| variable   typ   min   max
|C_comp 1.543pF   1.528pF   1.537pF
|C_comp_pullup 681.847fF   661.750fF   676.913fF
|C_comp_pulldown 805.500fF   821.186fF   796.656fF
[Pulldown Reference]   0.00V   0.00V   0.00V
[POWER Clamp Reference]   1.200V   1.140V   1.260V
[Pullup Reference]   1.200V   1.140V   1.260V
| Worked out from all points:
|   slope of the pulldown table from 0 to 0.18 V, typ, clamps not added: 32.5 ohm
|   slope of the pullup table from 0 to 0.18 V, typ, clamps not added: 32.1 ohm
|   GND clamp passes 1 mA (typ) near -0.34 V on its own axis
|   POWER clamp passes 1 mA (typ) near -0.37 V on its own axis
|   rising waveform, R_fixture 50.000Ohm, V_fixture 1.200: 20-80 % time 47.2ps typ, 45.7ps min, 49.9ps max; typ from 0.475 V to 1.2 V
|   rising waveform, R_fixture 50.000Ohm, V_fixture 0: 20-80 % time 57.1ps typ, 54.2ps min, 61.5ps max; typ from -0.002 V to 0.72 V
|   falling waveform, R_fixture 50.000Ohm, V_fixture 1.200: 20-80 % time 55.3ps typ, 53.7ps min, 58.9ps max; typ from 1.21 V to 0.481 V
|   falling waveform, R_fixture 50.000Ohm, V_fixture 0: 20-80 % time 45.9ps typ, 46.5ps min, 48.2ps max; typ from 0.725 V to 0 V
[GND Clamp]
-1.184V   -276.6mA   -302mA     -252.8mA
-1.031V   -146.8mA   -173.7mA   -122mA
-954.6mV  -88mA      -115mA     -64.4mA
-916.4mV  -62.15mA   -88.25mA   -41.23mA
-878.2mV  -40.64mA   -64.09mA   -25.82mA
-840mV    -25.66mA   -43.68mA   -19.12mA
-801.8mV  -17.83mA   -28.3mA    -16.59mA
-763.6mV  -14.37mA   -18.53mA   -15mA
-725.5mV  -12.44mA   -13.25mA   -13.58mA
-496.4mV  -4.591mA   -4.004mA   -5.798mA
-229.1mV  -67.51uA   -103.3uA   -163.9uA
2.367V    58.34nA    819.4nA    21.13nA
[Power Clamp]
-1.167V   263.1mA    285.3mA    240.8mA
-1.015V   133.8mA    158mA      110.6mA
-938.2mV  76.29mA    100.8mA    55.23mA
-900mV    51.9mA     75.31mA    34.8mA
-861.8mV  32.79mA    53.07mA    22.5mA
-823.6mV  20.9mA     35.29mA    17.2mA
-785.5mV  15.3mA     22.9mA     14.92mA
-747.3mV  12.67mA    15.53mA    13.31mA
-709.1mV  10.94mA    11.56mA    11.83mA
-518.2mV  4.347mA    4.291mA    5.122mA
-250.9mV  45.88uA    163.5uA    55.72uA
2.384V    -40.52nA   -814.5nA   -9.286nA
[Pulldown]
-1.184V   -15.7mA    -16.2mA    -12mA
-954.6mV  -14.8mA    -16.4mA    -11.22mA
-763.6mV  -13.89mA   -15.32mA   -10.53mA
-534.5mV  -12.52mA   -13.36mA   -9.672mA
-381.8mV  -10.77mA   -11.11mA   -8.742mA
-229.1mV  -7.168mA   -7.249mA   -6.322mA
610.9mV   18mA       18.37mA    16.25mA
840mV     23.52mA    24.19mA    21.43mA
1.031V    26.7mA     27.73mA    24.72mA
1.222V    28.34mA    29.63mA    26.68mA
1.451V    29.26mA    30.63mA    27.81mA
2.367V    30.8mA     32.2mA     29.4mA
[Pullup]
-1.167V   16.3mA     17.21mA    12.01mA
-938.2mV  15.54mA    17.22mA    11.49mA
-670.9mV  14.49mA    15.47mA    11.14mA
-480mV    13.01mA    13.25mA    10.64mA
-327.3mV  10.24mA    10.22mA    8.928mA
245.5mV   -7.594mA   -7.729mA   -6.813mA
589.1mV   -17.48mA   -17.86mA   -15.81mA
856.4mV   -23.99mA   -24.76mA   -21.89mA
1.085V    -27.98mA   -29.41mA   -25.72mA
1.276V    -29.9mA    -32.02mA   -27.57mA
1.505V    -31.08mA   -33.78mA   -28.69mA
2.384V    -32.7mA    -35.96mA   -30.2mA
[Ramp]
R_load=50.000Ohm
dV/dt_r   432.360mV/53.000ps  414.358mV/51.000ps  433.800mV/57.000ps
dV/dt_f   432.360mV/51.500ps  414.359mV/51.000ps  433.800mV/55.000ps
[Rising waveform]
R_fixture=50.000Ohm
V_fixture=1.200
V_fixture_min=1.140
V_fixture_max=1.260
0s        474.5mV    446.8mV    536.8mV
8ps       474.5mV    446.8mV    545.6mV
16ps      551.1mV    485.1mV    634.7mV
34ps      789mV      698.8mV    862.2mV
49ps      936.1mV    859.1mV    998.9mV
65ps      1.038V     971.8mV    1.095V
82ps      1.105V     1.043V     1.16V
102ps     1.149V     1.09V      1.204V
133ps     1.181V     1.122V     1.238V
242ps     1.199V     1.139V     1.259V
[Rising waveform]
R_fixture=50.000Ohm
V_fixture=0
0s        -1.823mV   -3.092mV   -7.009mV
10ps      -1.823mV   -3.092mV   17.45mV
16ps      43.41mV    17.04mV    75.9mV
37ps      262.8mV    198.4mV    288.5mV
55ps      422.4mV    372.5mV    431.3mV
72ps      526.3mV    490.3mV    528mV
93ps      608.8mV    580.6mV    607mV
118ps     663.9mV    637.6mV    661.6mV
145ps     693.6mV    667.1mV    692.9mV
244ps     719.5mV    690.2mV    721.4mV
[Falling waveform]
R_fixture=50.000Ohm
V_fixture=1.200
V_fixture_min=1.140
V_fixture_max=1.260
0s        1.205V     1.141V     1.262V
4ps       1.178V     1.127V     1.228V
13ps      1.097V     1.064V     1.141V
35ps      876mV      862.1mV    931mV
48ps      764.6mV    744.9mV    826.4mV
62ps      674.3mV    647mV      740.5mV
80ps      596mV      565.3mV    663.8mV
106ps     534.6mV    501.8mV    600.9mV
133ps     504.9mV    472.7mV    567.4mV
234ps     481.4mV    451.5mV    539.9mV
[Falling waveform]
R_fixture=50.000Ohm
V_fixture=0
0s        724.7mV    696mV      728.1mV
7ps       667.3mV    654.4mV    666.2mV
13ps      598.3mV    603.3mV    590.5mV
28ps      400mV      433.8mV    396.2mV
39ps      285.7mV    313.7mV    287.9mV
54ps      178mV      193.1mV    184.7mV
75ps      90.15mV    96.61mV    98.03mV
95ps      47.13mV    49.26mV    53.45mV
128ps     16.17mV    16.2mV     20.02mV
234ps     483.6uV    492.3uV    749.1uV
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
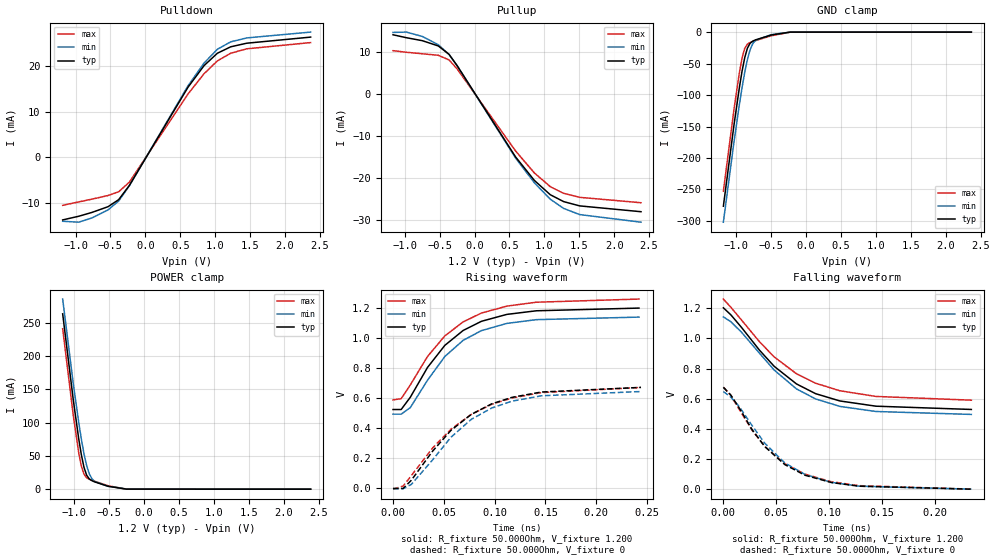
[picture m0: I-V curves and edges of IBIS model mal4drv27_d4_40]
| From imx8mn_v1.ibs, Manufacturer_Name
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[Model] mal4drv27_d4_40
Model_type   I/O
Polarity   Non-Inverting
Enable   Active-High
C_comp   1.537pF   1.528pF   1.543pF
C_comp_pullup   676.913fF   661.750fF   681.847fF
C_comp_pulldown 805.500fF   796.656fF   821.186fF
Vinh = 668.000mV
Vinl = 532.000mV
Vmeas = 600.000mV
Vref = 600.000mV
Rref = 50Ohms
Cref = 0pF
[Model Spec]
Vinh   668.000mV   638.000mV   698.000mV
Vinl   532.000mV   502.000mV   562.000mV
Vmeas   600.000mV   570.000mV   640.000mV
Vref   600.000mV   570.000mV   640.000mV
D_overshoot_ampl_h 0.24 NA   NA
D_overshoot_ampl_l 0.24 NA   NA
D_overshoot_area_l 300.000m NA   NA
D_overshoot_area_h 300.000m NA   NA
|[Receiver Thresholds]
|Vth = 600.000mV
|Vth_min = 570.000mV
|Vth_max = 640.000mV
|Vinh_ac = 68.000mV
|Vinh_dc = 68.000mV
|Vinl_ac = -68.000mV
|Vinl_dc = -68.000mV
|Tslew_ac = 5.000ns
|Threshold_sensitivity = 0.5
|Reference_supply Pullup_ref
[Temperature Range]   25.000   125.000   -40.000
[Voltage Range]   1.200V   1.140V   1.260V
[GND Clamp Reference]   0.00V   0.00V   0.00V
|[C Comp Corner]
|| variable   typ   min   max
|C_comp 1.543pF   1.528pF   1.537pF
|C_comp_pullup 681.847fF   661.750fF   676.913fF
|C_comp_pulldown 805.500fF   821.186fF   796.656fF
[Pulldown Reference]   0.00V   0.00V   0.00V
[POWER Clamp Reference]   1.200V   1.140V   1.260V
[Pullup Reference]   1.200V   1.140V   1.260V
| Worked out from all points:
|   slope of the pulldown table from 0 to 0.18 V, typ, clamps not added: 37.9 ohm
|   slope of the pullup table from 0 to 0.18 V, typ, clamps not added: 37.5 ohm
|   GND clamp passes 1 mA (typ) near -0.34 V on its own axis
|   POWER clamp passes 1 mA (typ) near -0.37 V on its own axis
|   rising waveform, R_fixture 50.000Ohm, V_fixture 1.200: 20-80 % time 51.1ps typ, 49.5ps min, 53.5ps max; typ from 0.524 V to 1.2 V
|   rising waveform, R_fixture 50.000Ohm, V_fixture 0: 20-80 % time 62ps typ, 59ps min, 66.3ps max; typ from -0.002 V to 0.671 V
|   falling waveform, R_fixture 50.000Ohm, V_fixture 1.200: 20-80 % time 59.9ps typ, 58.2ps min, 63.3ps max; typ from 1.2 V to 0.529 V
|   falling waveform, R_fixture 50.000Ohm, V_fixture 0: 20-80 % time 49.6ps typ, 49.9ps min, 51.8ps max; typ from 0.676 V to 0.001 V
[GND Clamp]
-1.184V   -276.6mA   -302mA     -252.8mA
-1.031V   -146.8mA   -173.7mA   -122mA
-954.6mV  -88mA      -115mA     -64.4mA
-916.4mV  -62.15mA   -88.25mA   -41.23mA
-878.2mV  -40.64mA   -64.09mA   -25.82mA
-840mV    -25.66mA   -43.68mA   -19.12mA
-801.8mV  -17.83mA   -28.3mA    -16.59mA
-763.6mV  -14.37mA   -18.53mA   -15mA
-725.5mV  -12.44mA   -13.25mA   -13.58mA
-496.4mV  -4.591mA   -4.004mA   -5.798mA
-229.1mV  -67.51uA   -103.3uA   -163.9uA
2.367V    58.34nA    819.4nA    21.13nA
[Power Clamp]
-1.167V   263.1mA    285.3mA    240.8mA
-1.015V   133.8mA    158mA      110.6mA
-938.2mV  76.29mA    100.8mA    55.23mA
-900mV    51.9mA     75.31mA    34.8mA
-861.8mV  32.79mA    53.07mA    22.5mA
-823.6mV  20.9mA     35.29mA    17.2mA
-785.5mV  15.3mA     22.9mA     14.92mA
-747.3mV  12.67mA    15.53mA    13.31mA
-709.1mV  10.94mA    11.56mA    11.83mA
-518.2mV  4.347mA    4.291mA    5.122mA
-250.9mV  45.88uA    163.5uA    55.72uA
2.384V    -40.52nA   -814.5nA   -9.286nA
[Pulldown]
-1.184V   -13.7mA    -14mA      -10.5mA
-954.6mV  -12.9mA    -14.2mA    -9.75mA
-763.6mV  -12.05mA   -13.26mA   -9.14mA
-534.5mV  -10.8mA    -11.51mA   -8.352mA
-381.8mV  -9.254mA   -9.542mA   -7.522mA
-229.1mV  -6.14mA    -6.208mA   -5.418mA
610.9mV   15.41mA    15.72mA    13.92mA
840mV     20.14mA    20.7mA     18.36mA
1.031V    22.86mA    23.73mA    21.18mA
1.222V    24.27mA    25.36mA    22.86mA
1.451V    25.06mA    26.22mA    23.83mA
2.367V    26.4mA     27.5mA     25.2mA
[Pullup]
-1.167V   14.2mA     14.76mA    10.41mA
-976.4mV  13.5mA     14.84mA    10.03mA
-747.3mV  12.79mA    13.8mA     9.667mA
-518.2mV  11.53mA    11.82mA    9.308mA
-365.4mV  9.545mA    9.509mA    8.202mA
-250.9mV  6.868mA    6.894mA    6.099mA
589.1mV   -14.96mA   -15.22mA   -13.54mA
856.4mV   -20.53mA   -21.09mA   -18.74mA
1.085V    -23.95mA   -25.02mA   -22.03mA
1.276V    -25.59mA   -27.21mA   -23.62mA
1.505V    -26.61mA   -28.68mA   -24.57mA
2.384V    -28mA      -30.5mA    -25.86mA
[Ramp]
R_load=50.000Ohm
dV/dt_r   404.070mV/57.500ps  387.448mV/55.500ps  403.740mV/61.500ps
dV/dt_f   404.070mV/56.000ps  387.448mV/55.500ps  403.740mV/59.000ps
[Rising waveform]
R_fixture=50.000Ohm
V_fixture=1.200
V_fixture_min=1.140
V_fixture_max=1.260
0s        523.9mV    493.1mV    588mV
8ps       523.9mV    493.1mV    595.9mV
17ps      605.6mV    536.7mV    687.7mV
34ps      804.5mV    719.5mV    877.5mV
51ps      951mV      877mV      1.014V
69ps      1.05V      984.4mV    1.107V
87ps      1.111V     1.049V     1.166V
112ps     1.157V     1.097V     1.212V
141ps     1.181V     1.122V     1.238V
242ps     1.199V     1.139V     1.259V
[Rising waveform]
R_fixture=50.000Ohm
V_fixture=0
0s        -1.671mV   -2.475mV   -6.1mV
10ps      -1.671mV   -2.475mV   14.86mV
18ps      53.15mV    25.64mV    83.93mV
39ps      247.2mV    189.1mV    268.7mV
57ps      385.5mV    339.4mV    392.7mV
77ps      491.6mV    458.5mV    491.6mV
97ps      561.4mV    533.6mV    557.8mV
117ps     604.9mV    579.4mV    600.6mV
146ps     640.4mV    615.3mV    636.6mV
244ps     671.3mV    643.8mV    670.7mV
[Falling waveform]
R_fixture=50.000Ohm
V_fixture=1.200
V_fixture_min=1.140
V_fixture_max=1.260
0s        1.203V     1.143V     1.261V
7ps       1.157V     1.111V     1.207V
17ps      1.074V     1.042V     1.123V
34ps      922.9mV    902.8mV    978.8mV
48ps      814.8mV    790.2mV    877mV
69ps      698.4mV    665.4mV    765.9mV
87ps      634mV      599.1mV    703.2mV
110ps     585.5mV    549.5mV    653.1mV
144ps     550.9mV    515.7mV    615.5mV
234ps     529.2mV    496.3mV    590.8mV
[Falling waveform]
R_fixture=50.000Ohm
V_fixture=0
0s        675.6mV    647.9mV    677.6mV
7ps       625mV      611.3mV    622.8mV
15ps      538.5mV    547.8mV    529.3mV
27ps      397mV      423.5mV    392.2mV
39ps      283.7mV    305.8mV    284.7mV
58ps      163.5mV    174.5mV    169.5mV
77ps      93.24mV    98.67mV    100.3mV
102ps     44.76mV    45.89mV    50.24mV
128ps     20.5mV     20.69mV    24.17mV
234ps     861.6uV    848.8uV    1.177mV
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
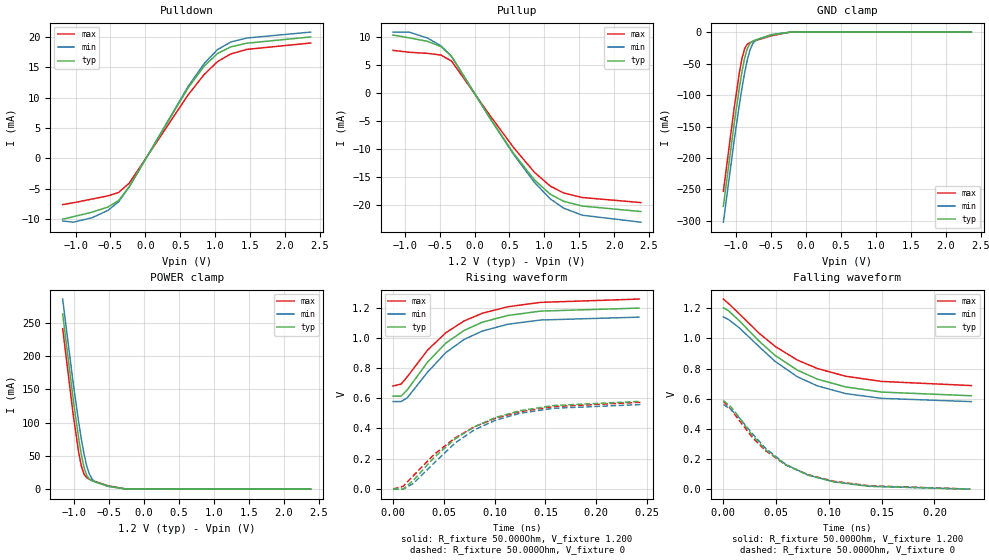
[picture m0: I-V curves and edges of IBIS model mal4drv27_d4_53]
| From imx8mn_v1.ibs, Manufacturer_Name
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[Model] mal4drv27_d4_53
Model_type   I/O
Polarity   Non-Inverting
Enable   Active-High
C_comp   1.537pF   1.528pF   1.543pF
C_comp_pullup   676.913fF   661.750fF   681.847fF
C_comp_pulldown 805.500fF   796.656fF   821.186fF
Vinh = 668.000mV
Vinl = 532.000mV
Vmeas = 600.000mV
Vref = 600.000mV
Rref = 50Ohms
Cref = 0pF
[Model Spec]
Vinh   668.000mV   638.000mV   698.000mV
Vinl   532.000mV   502.000mV   562.000mV
Vmeas   600.000mV   570.000mV   640.000mV
Vref   600.000mV   570.000mV   640.000mV
D_overshoot_ampl_h 0.24 NA   NA
D_overshoot_ampl_l 0.24 NA   NA
D_overshoot_area_l 300.000m NA   NA
D_overshoot_area_h 300.000m NA   NA
|[Receiver Thresholds]
|Vth = 600.000mV
|Vth_min = 570.000mV
|Vth_max = 640.000mV
|Vinh_ac = 68.000mV
|Vinh_dc = 68.000mV
|Vinl_ac = -68.000mV
|Vinl_dc = -68.000mV
|Tslew_ac = 5.000ns
|Threshold_sensitivity = 0.5
|Reference_supply Pullup_ref
[Temperature Range]   25.000   125.000   -40.000
[Voltage Range]   1.200V   1.140V   1.260V
[GND Clamp Reference]   0.00V   0.00V   0.00V
|[C Comp Corner]
|| variable   typ   min   max
|C_comp 1.543pF   1.528pF   1.537pF
|C_comp_pullup 681.847fF   661.750fF   676.913fF
|C_comp_pulldown 805.500fF   821.186fF   796.656fF
[Pulldown Reference]   0.00V   0.00V   0.00V
[POWER Clamp Reference]   1.200V   1.140V   1.260V
[Pullup Reference]   1.200V   1.140V   1.260V
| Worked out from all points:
|   slope of the pulldown table from 0 to 0.18 V, typ, clamps not added: 50.4 ohm
|   slope of the pullup table from 0 to 0.18 V, typ, clamps not added: 50 ohm
|   GND clamp passes 1 mA (typ) near -0.34 V on its own axis
|   POWER clamp passes 1 mA (typ) near -0.37 V on its own axis
|   rising waveform, R_fixture 50.000Ohm, V_fixture 1.200: 20-80 % time 57.3ps typ, 55.9ps min, 59.8ps max; typ from 0.614 V to 1.2 V
|   rising waveform, R_fixture 50.000Ohm, V_fixture 0: 20-80 % time 69.1ps typ, 65.7ps min, 73.3ps max; typ from -0.003 V to 0.58 V
|   falling waveform, R_fixture 50.000Ohm, V_fixture 1.200: 20-80 % time 67.1ps typ, 64.7ps min, 70.8ps max; typ from 1.2 V to 0.62 V
|   falling waveform, R_fixture 50.000Ohm, V_fixture 0: 20-80 % time 55.8ps typ, 55.4ps min, 58.3ps max; typ from 0.588 V to 0.002 V
[GND Clamp]
-1.184V   -276.6mA   -302mA     -252.8mA
-1.031V   -146.8mA   -173.7mA   -122mA
-954.6mV  -88mA      -115mA     -64.4mA
-916.4mV  -62.15mA   -88.25mA   -41.23mA
-878.2mV  -40.64mA   -64.09mA   -25.82mA
-840mV    -25.66mA   -43.68mA   -19.12mA
-801.8mV  -17.83mA   -28.3mA    -16.59mA
-763.6mV  -14.37mA   -18.53mA   -15mA
-725.5mV  -12.44mA   -13.25mA   -13.58mA
-496.4mV  -4.591mA   -4.004mA   -5.798mA
-229.1mV  -67.51uA   -103.3uA   -163.9uA
2.367V    58.34nA    819.4nA    21.13nA
[Power Clamp]
-1.167V   263.1mA    285.3mA    240.8mA
-1.015V   133.8mA    158mA      110.6mA
-938.2mV  76.29mA    100.8mA    55.23mA
-900mV    51.9mA     75.31mA    34.8mA
-861.8mV  32.79mA    53.07mA    22.5mA
-823.6mV  20.9mA     35.29mA    17.2mA
-785.5mV  15.3mA     22.9mA     14.92mA
-747.3mV  12.67mA    15.53mA    13.31mA
-709.1mV  10.94mA    11.56mA    11.83mA
-518.2mV  4.347mA    4.291mA    5.122mA
-250.9mV  45.88uA    163.5uA    55.72uA
2.384V    -40.52nA   -814.5nA   -9.286nA
[Pulldown]
-1.184V   -10mA      -10.3mA    -7.6mA
-1.031V   -9.6mA     -10.5mA    -7.3mA
-763.6mV  -8.85mA    -9.77mA    -6.69mA
-534.5mV  -8.008mA   -8.548mA   -6.162mA
-381.8mV  -6.913mA   -7.127mA   -5.59mA
-229.1mV  -4.612mA   -4.663mA   -4.059mA
610.9mV   11.59mA    11.83mA    10.44mA
840mV     15.17mA    15.59mA    13.79mA
1.031V    17.26mA    17.9mA     15.92mA
1.222V    18.36mA    19.16mA    17.2mA
1.451V    18.97mA    19.82mA    17.95mA
2.367V    20mA       20.8mA     19mA
[Pullup]
-1.167V   10.4mA     10.91mA    7.657mA
-938.2mV  9.9mA      10.92mA    7.323mA
-670.9mV  9.262mA    9.85mA     7.12mA
-480mV    8.335mA    8.46mA     6.82mA
-327.3mV  6.576mA    6.54mA     5.729mA
207.3mV   -4.135mA   -4.197mA   -3.706mA
550.9mV   -10.57mA   -10.75mA   -9.548mA
856.4mV   -15.43mA   -15.87mA   -14.08mA
1.085V    -18.02mA   -18.84mA   -16.57mA
1.276V    -19.27mA   -20.5mA    -17.79mA
1.544V    -20.12mA   -21.76mA   -18.6mA
2.384V    -21.1mA    -23mA      -19.5mA
[Ramp]
R_load=50.000Ohm
dV/dt_r   350.520mV/64.500ps  337.228mV/62.500ps  347.070mV/69.000ps
dV/dt_f   350.520mV/63.000ps  337.228mV/61.500ps  347.070mV/66.500ps
[Rising waveform]
R_fixture=50.000Ohm
V_fixture=1.200
V_fixture_min=1.140
V_fixture_max=1.260
0s        613.9mV    578mV      681.3mV
8ps       613.9mV    578mV      693.9mV
14ps      655.1mV    603mV      742.5mV
34ps      839.7mV    773mV      919.4mV
52ps      966.2mV    903.2mV    1.035V
70ps      1.05V      990.5mV    1.113V
88ps      1.105V     1.046V     1.164V
113ps     1.149V     1.091V     1.207V
145ps     1.178V     1.119V     1.236V
242ps     1.198V     1.138V     1.258V
[Rising waveform]
R_fixture=50.000Ohm
V_fixture=0
0s        -2.567mV   -3.279mV   -1.886mV
10ps      -2.567mV   -3.279mV   15.72mV
20ps      54.83mV    34.95mV    86.18mV
40ps      204mV      167.6mV    224.3mV
61ps      329.8mV    302.7mV    336.5mV
80ps      410.6mV    390.2mV    410.3mV
101ps     472.6mV    454.7mV    467.7mV
125ps     517.4mV    500.3mV    510.5mV
158ps     551.8mV    533.5mV    544.5mV
244ps     579.5mV    558.3mV    573.5mV
[Falling waveform]
R_fixture=50.000Ohm
V_fixture=1.200
V_fixture_min=1.140
V_fixture_max=1.260
0s        1.202V     1.142V     1.26V
5ps       1.182V     1.124V     1.23V
15ps      1.117V     1.07V      1.163V
34ps      980.6mV    943.9mV    1.033V
49ps      887mV      847.7mV    946.9mV
70ps      790mV      746mV      856.7mV
89ps      730.1mV    685.6mV    800.5mV
116ps     678.2mV    634.1mV    749mV
150ps     644.3mV    602.8mV    714.8mV
235ps     620mV      581.1mV    687.4mV
[Falling waveform]
R_fixture=50.000Ohm
V_fixture=0
0s        588.3mV    562.4mV    581.8mV
7ps       547.1mV    530.3mV    532.7mV
13ps      495.1mV    490.8mV    475.6mV
27ps      362.2mV    373mV      348.6mV
40ps      263mV      272.1mV    256.7mV
59ps      162.7mV    166.5mV    162.8mV
80ps      94.87mV    95.92mV    98.09mV
104ps     51.13mV    50.77mV    54.62mV
138ps     21.27mV    20.64mV    24.14mV
234ps     1.816mV    1.697mV    2.252mV
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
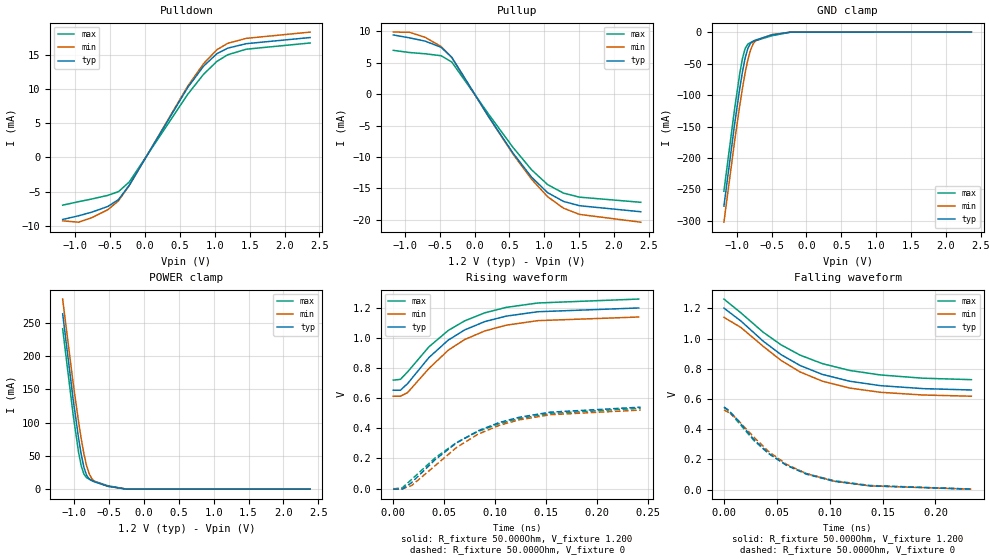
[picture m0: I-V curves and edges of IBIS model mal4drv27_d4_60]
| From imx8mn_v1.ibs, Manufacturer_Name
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[Model] mal4drv27_d4_60
Model_type   I/O
Polarity   Non-Inverting
Enable   Active-High
C_comp   1.537pF   1.528pF   1.543pF
C_comp_pullup   676.913fF   661.750fF   681.847fF
C_comp_pulldown 805.500fF   796.656fF   821.186fF
Vinh = 924.000mV
Vinl = 809.000mV
Vmeas = 867.000mV
Vref = 867.000mV
Rref = 50Ohms
Cref = 0pF
[Model Spec]
Vinh   924.000mV   881.000mV   968.000mV
Vinl   809.000mV   766.000mV   853.000mV
Vmeas   867.000mV   823.000mV   910.000mV
Vref   867.000mV   823.000mV   910.000mV
D_overshoot_ampl_h 0.24 NA   NA
D_overshoot_ampl_l 0.24 NA   NA
D_overshoot_area_l 300.000m NA   NA
D_overshoot_area_h 300.000m NA   NA
|[Receiver Thresholds]
|Vth = 867.000mV
|Vth_min = 823.000mV
|Vth_max = 910.000mV
|Vinh_ac = 68.000mV
|Vinh_dc = 68.000mV
|Vinl_ac = -68.000mV
|Vinl_dc = -68.000mV
|Tslew_ac = 5.000ns
|Threshold_sensitivity = 0.5
|Reference_supply Pullup_ref
[Temperature Range]   25.000   125.000   -40.000
[Voltage Range]   1.200V   1.140V   1.260V
[GND Clamp Reference]   0.00V   0.00V   0.00V
|[C Comp Corner]
|| variable   typ   min   max
|C_comp 1.543pF   1.528pF   1.537pF
|C_comp_pullup 681.847fF   661.750fF   676.913fF
|C_comp_pulldown 805.500fF   821.186fF   796.656fF
[Pulldown Reference]   0.00V   0.00V   0.00V
[POWER Clamp Reference]   1.200V   1.140V   1.260V
[Pullup Reference]   1.200V   1.140V   1.260V
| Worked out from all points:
|   slope of the pulldown table from 0 to 0.18 V, typ, clamps not added: 56.9 ohm
|   slope of the pullup table from 0 to 0.18 V, typ, clamps not added: 56.4 ohm
|   GND clamp passes 1 mA (typ) near -0.34 V on its own axis
|   POWER clamp passes 1 mA (typ) near -0.37 V on its own axis
|   rising waveform, R_fixture 50.000Ohm, V_fixture 1.200: 20-80 % time 60.6ps typ, 59.3ps min, 62.5ps max; typ from 0.652 V to 1.2 V
|   rising waveform, R_fixture 50.000Ohm, V_fixture 0: 20-80 % time 73ps typ, 69.4ps min, 77ps max; typ from -0.003 V to 0.54 V
|   falling waveform, R_fixture 50.000Ohm, V_fixture 1.200: 20-80 % time 71.2ps typ, 68.5ps min, 74.2ps max; typ from 1.2 V to 0.66 V
|   falling waveform, R_fixture 50.000Ohm, V_fixture 0: 20-80 % time 58.9ps typ, 58.6ps min, 61.2ps max; typ from 0.547 V to 0.002 V
[GND Clamp]
-1.184V   -276.6mA   -302mA     -252.8mA
-1.031V   -146.8mA   -173.7mA   -122mA
-954.6mV  -88mA      -115mA     -64.4mA
-916.4mV  -62.15mA   -88.25mA   -41.23mA
-878.2mV  -40.64mA   -64.09mA   -25.82mA
-840mV    -25.66mA   -43.68mA   -19.12mA
-801.8mV  -17.83mA   -28.3mA    -16.59mA
-763.6mV  -14.37mA   -18.53mA   -15mA
-725.5mV  -12.44mA   -13.25mA   -13.58mA
-496.4mV  -4.591mA   -4.004mA   -5.798mA
-229.1mV  -67.51uA   -103.3uA   -163.9uA
2.367V    58.34nA    819.4nA    21.13nA
[Power Clamp]
-1.167V   263.1mA    285.3mA    240.8mA
-1.015V   133.8mA    158mA      110.6mA
-938.2mV  76.29mA    100.8mA    55.23mA
-900mV    51.9mA     75.31mA    34.8mA
-861.8mV  32.79mA    53.07mA    22.5mA
-823.6mV  20.9mA     35.29mA    17.2mA
-785.5mV  15.3mA     22.9mA     14.92mA
-747.3mV  12.67mA    15.53mA    13.31mA
-709.1mV  10.94mA    11.56mA    11.83mA
-518.2mV  4.347mA    4.291mA    5.122mA
-250.9mV  45.88uA    163.5uA    55.72uA
2.384V    -40.52nA   -814.5nA   -9.286nA
[Pulldown]
-1.184V   -9.1mA     -9.3mA     -7mA
-954.6mV  -8.56mA    -9.5mA     -6.49mA
-763.6mV  -8.02mA    -8.83mA    -6.09mA
-534.5mV  -7.188mA   -7.668mA   -5.562mA
-381.8mV  -6.166mA   -6.353mA   -5.011mA
-229.1mV  -4.089mA   -4.135mA   -3.609mA
610.9mV   10.27mA    10.47mA    9.273mA
840mV     13.42mA    13.79mA    12.23mA
1.031V    15.24mA    15.82mA    14.11mA
1.184V    16.04mA    16.75mA    15.07mA
1.451V    16.7mA     17.48mA    15.89mA
2.367V    17.6mA     18.4mA     16.8mA
[Pullup]
-1.167V   9.4mA      9.857mA    6.957mA
-938.2mV  8.95mA     9.837mA    6.613mA
-709.1mV  8.42mA     9.023mA    6.411mA
-480mV    7.435mA    7.557mA    6.096mA
-327.3mV  5.843mA    5.813mA    5.096mA
207.3mV   -3.669mA   -3.721mA   -3.29mA
550.9mV   -9.376mA   -9.533mA   -8.476mA
818.2mV   -13.21mA   -13.54mA   -12.04mA
1.047V    -15.66mA   -16.3mA    -14.38mA
1.276V    -17.06mA   -18.14mA   -15.74mA
1.505V    -17.74mA   -19.12mA   -16.38mA
2.384V    -18.7mA    -20.36mA   -17.2mA
[Ramp]
R_load=50.000Ohm
dV/dt_r   327.720mV/69.000ps  315.748mV/66.500ps  323.610mV/72.500ps
dV/dt_f   327.720mV/67.000ps  315.748mV/66.000ps  323.610mV/70.000ps
[Rising waveform]
R_fixture=50.000Ohm
V_fixture=1.200
V_fixture_min=1.140
V_fixture_max=1.260
0s        652.5mV    612.7mV    719.5mV
7ps       652.5mV    612.7mV    724.7mV
14ps      696.3mV    636.6mV    773.7mV
35ps      869.2mV    796.8mV    940.1mV
54ps      985.1mV    917.9mV    1.049V
70ps      1.052V     988.5mV    1.112V
90ps      1.108V     1.046V     1.166V
111ps     1.144V     1.084V     1.202V
142ps     1.173V     1.114V     1.231V
241ps     1.198V     1.138V     1.257V
[Rising waveform]
R_fixture=50.000Ohm
V_fixture=0
0s        -3.462mV   -191uV     -3.178mV
9ps       -3.462mV   -191uV     6.393mV
18ps      40.2mV     20.38mV    60.79mV
41ps      191.4mV    151.7mV    203.5mV
62ps      303.1mV    272.5mV    304.7mV
83ps      382.7mV    360.4mV    378.6mV
104ps     438.2mV    419.4mV    430.9mV
123ps     472.4mV    455.3mV    463.8mV
154ps     507.1mV    490.1mV    498.4mV
243ps     540.3mV    521.2mV    533.2mV
[Falling waveform]
R_fixture=50.000Ohm
V_fixture=1.200
V_fixture_min=1.140
V_fixture_max=1.260
0s        1.202V     1.141V     1.262V
16ps      1.117V     1.074V     1.171V
37ps      983.9mV    949.6mV    1.043V
54ps      894mV      855.5mV    958.7mV
72ps      822mV      779.1mV    890.6mV
93ps      763mV      718.2mV    834.3mV
119ps     717.4mV    672.2mV    788.9mV
148ps     688.2mV    644.2mV    759.1mV
188ps     668.6mV    626.3mV    737.6mV
234ps     659.6mV    618.2mV    727.9mV
[Falling waveform]
R_fixture=50.000Ohm
V_fixture=0
0s        547mV      526.5mV    544.3mV
4ps       527.8mV    512.4mV    523.2mV
11ps      477.3mV    476.4mV    467.2mV
28ps      333.5mV    349.4mV    327.6mV
42ps      240.9mV    253.1mV    239.5mV
59ps      160.8mV    167.9mV    162.8mV
78ps      101.7mV    105.6mV    105.4mV
104ps     54.53mV    55.41mV    58.39mV
138ps     24.08mV    23.88mV    26.74mV
234ps     2.309mV    2.26mV     2.92mV
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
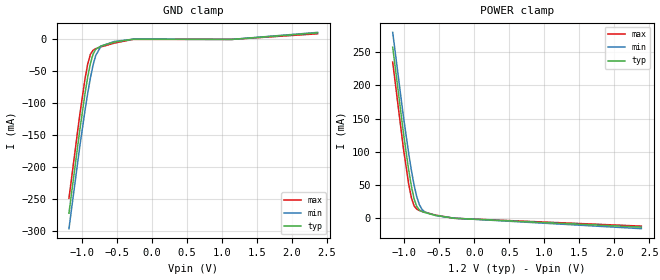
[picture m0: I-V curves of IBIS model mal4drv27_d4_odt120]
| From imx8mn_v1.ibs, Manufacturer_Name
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[Model] mal4drv27_d4_odt120
Model_type   Input
Polarity   Non-Inverting
Enable   Active-High
C_comp   1.658pF   1.580pF   1.670pF
C_comp_power_clamp   720.279fF   671.803fF   727.867fF
C_comp_gnd_clamp 857.536fF   853.525fF   863.984fF
Vinh = 771.000mV
Vinl = 656.000mV
[Model Spec]
D_overshoot_ampl_h 0.24 NA   NA
D_overshoot_ampl_l 0.24 NA   NA
D_overshoot_area_l 300.000m NA   NA
D_overshoot_area_h 300.000m NA   NA
|[Receiver Thresholds]
|Vth = 714.000mV
|Vth_min = 678.000mV
|Vth_max = 749.000mV
|Vinh_ac = 68.000mV
|Vinh_dc = 68.000mV
|Vinl_ac = -68.000mV
|Vinl_dc = -68.000mV
|Tslew_ac = 5.000ns
|Threshold_sensitivity = 0.5
|Reference_supply Power_clamp_ref
[Temperature Range]   25.000   125.000   -40.000
[Voltage Range]   1.200V   1.140V   1.260V
[GND Clamp Reference]   0.00V   0.00V   0.00V
|[C Comp Corner]
|| variable   typ   min   max
|C_comp 1.658pF   1.580pF   1.670pF
|C_comp_pullup 727.867fF   671.803fF   720.279fF
|C_comp_pulldown 857.536fF   853.525fF   863.984fF
[POWER Clamp Reference]   1.200V   1.140V   1.260V
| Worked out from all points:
|   GND clamp passes 1 mA (typ) near -0.40 V on its own axis
|   POWER clamp passes 1 mA (typ) near -0.38 V on its own axis
[GND Clamp]
-1.184V   -272.9mA   -297.1mA   -249.6mA
-1.031V   -143.6mA   -169.6mA   -119.3mA
-954.6mV  -85.05mA   -111.3mA   -61.95mA
-916.4mV  -59.33mA   -84.68mA   -38.91mA
-878.2mV  -37.95mA   -60.71mA   -23.6mA
-840mV    -23.12mA   -40.48mA   -17.02mA
-801.8mV  -15.43mA   -25.28mA   -14.6mA
-725.5mV  -10.3mA    -10.61mA   -11.8mA
-534.5mV  -4.267mA   -3.254mA   -5.757mA
-267.3mV  326.5uA    320.6uA    68.99uA
1.145V    204.3nA    43.58uA    3.407nA
2.367V    10.33mA    10.99mA    8.816mA
[Power Clamp]
-1.167V   257.5mA    279.8mA    235mA
-1.015V   129.3mA    153.9mA    105.9mA
-938.2mV  72.46mA    97.33mA    51.06mA
-900mV    48.36mA    72.12mA    30.92mA
-861.8mV  29.55mA    50.16mA    18.91mA
-823.6mV  17.97mA    32.66mA    13.89mA
-785.5mV  12.66mA    20.54mA    11.89mA
-747.3mV  10.31mA    13.44mA    10.57mA
-709.1mV  8.873mA    9.725mA    9.389mA
-556.4mV  4.533mA    4.425mA    5.072mA
-289.1mV  219.5uA    391.6uA    224.6uA
2.384V    -13.12mA   -15.39mA   -11.56mA
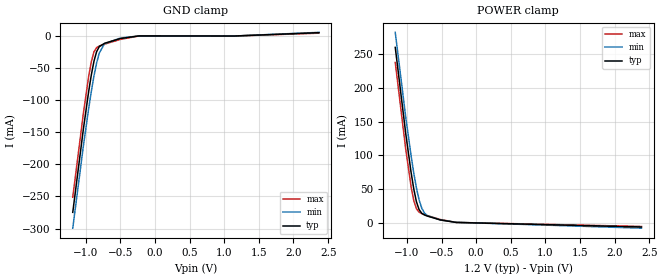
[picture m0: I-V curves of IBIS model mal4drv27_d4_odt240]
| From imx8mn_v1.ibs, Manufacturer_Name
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[Model] mal4drv27_d4_odt240
Model_type   Input
Polarity   Non-Inverting
Enable   Active-High
C_comp   1.603pF   1.547pF   1.610pF
C_comp_power_clamp   697.797fF   657.097fF   701.123fF
C_comp_gnd_clamp 836.271fF   835.733fF   839.335fF
Vinh = 720.000mV
Vinl = 605.000mV
[Model Spec]
D_overshoot_ampl_h 0.24 NA   NA
D_overshoot_ampl_l 0.24 NA   NA
D_overshoot_area_l 300.000m NA   NA
D_overshoot_area_h 300.000m NA   NA
|[Receiver Thresholds]
|Vth = 663.000mV
|Vth_min = 630.000mV
|Vth_max = 696.000mV
|Vinh_ac = 68.000mV
|Vinh_dc = 68.000mV
|Vinl_ac = -68.000mV
|Vinl_dc = -68.000mV
|Tslew_ac = 5.000ns
|Threshold_sensitivity = 0.5
|Reference_supply Power_clamp_ref
[Temperature Range]   25.000   125.000   -40.000
[Voltage Range]   1.200V   1.140V   1.260V
[GND Clamp Reference]   0.00V   0.00V   0.00V
|[C Comp Corner]
|| variable   typ   min   max
|C_comp 1.603pF   1.547pF   1.610pF
|C_comp_pullup 701.123fF   657.097fF   697.797fF
|C_comp_pulldown 836.271fF   839.335fF   835.733fF
[POWER Clamp Reference]   1.200V   1.140V   1.260V
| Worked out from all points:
|   GND clamp passes 1 mA (typ) near -0.37 V on its own axis
|   POWER clamp passes 1 mA (typ) near -0.38 V on its own axis
[GND Clamp]
-1.184V   -274.7mA   -299.3mA   -251.2mA
-1.031V   -145.1mA   -171.5mA   -120.7mA
-954.6mV  -86.5mA    -113mA     -63.18mA
-916.4mV  -60.73mA   -86.32mA   -40.07mA
-878.2mV  -39.28mA   -62.27mA   -24.7mA
-840mV    -24.38mA   -41.95mA   -18.07mA
-801.8mV  -16.61mA   -26.68mA   -15.6mA
-725.5mV  -11.37mA   -11.84mA   -12.68mA
-496.4mV  -3.908mA   -3.162mA   -5.228mA
-229.1mV  155.1uA    118.7uA    63.8uA
1.145V    127.6nA    22.79uA    7.645nA
2.367V    5.212mA    5.68mA     4.438mA
[Power Clamp]
-1.167V   260.1mA    282.4mA    237.7mA
-1.015V   131.4mA    155.7mA    108.1mA
-938.2mV  74.21mA    98.91mA    53.02mA
-900mV    49.97mA    73.55mA    32.74mA
-861.8mV  31.02mA    51.46mA    20.59mA
-823.6mV  19.3mA     33.83mA    15.43mA
-785.5mV  13.85mA    21.59mA    13.3mA
-747.3mV  11.37mA    14.35mA    11.84mA
-709.1mV  9.794mA    10.52mA    10.52mA
-518.2mV  3.922mA    3.88mA     4.562mA
-289.1mV  183.1uA    365.2uA    214uA
2.384V    -6.616mA   -8.289mA   -5.797mA
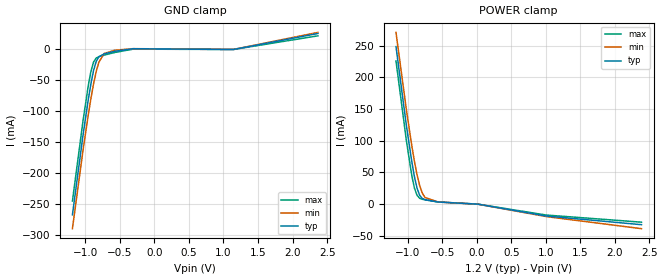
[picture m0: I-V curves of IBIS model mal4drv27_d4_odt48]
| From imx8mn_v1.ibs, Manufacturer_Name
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[Model] mal4drv27_d4_odt48
Model_type   Input
Polarity   Non-Inverting
Enable   Active-High
C_comp   1.833pF   1.652pF   1.875pF
C_comp_power_clamp   783.945fF   677.388fF   792.722fF
C_comp_gnd_clamp 940.207fF   903.925fF   970.295fF
Vinh = 879.000mV
Vinl = 764.000mV
[Model Spec]
D_overshoot_ampl_h 0.24 NA   NA
D_overshoot_ampl_l 0.24 NA   NA
D_overshoot_area_l 300.000m NA   NA
D_overshoot_area_h 300.000m NA   NA
|[Receiver Thresholds]
|Vth = 821.000mV
|Vth_min = 780.000mV
|Vth_max = 862.000mV
|Vinh_ac = 68.000mV
|Vinh_dc = 68.000mV
|Vinl_ac = -68.000mV
|Vinl_dc = -68.000mV
|Tslew_ac = 5.000ns
|Threshold_sensitivity = 0.5
|Reference_supply Power_clamp_ref
[Temperature Range]   25.000   125.000   -40.000
[Voltage Range]   1.200V   1.140V   1.260V
[GND Clamp Reference]   0.00V   0.00V   0.00V
|[C Comp Corner]
|| variable   typ   min   max
|C_comp 1.833pF   1.652pF   1.875pF
|C_comp_pullup 792.722fF   677.388fF   783.945fF
|C_comp_pulldown 940.207fF   903.925fF   970.295fF
[POWER Clamp Reference]   1.200V   1.140V   1.260V
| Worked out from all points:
|   GND clamp passes 1 mA (typ) near -0.18 V on its own axis
|   POWER clamp passes 1 mA (typ) near -0.40 V on its own axis
[GND Clamp]
-1.184V   -267.1mA   -289.5mA   -245mA
-1.031V   -138.7mA   -163.1mA   -115.4mA
-954.6mV  -80.63mA   -105.4mA   -58.32mA
-916.4mV  -55.1mA    -79.13mA   -35.43mA
-878.2mV  -33.93mA   -55.45mA   -20.29mA
-840mV    -19.29mA   -35.51mA   -13.88mA
-801.8mV  -11.81mA   -20.61mA   -11.63mA
-725.5mV  -7.09mA    -6.5mA     -9.16mA
-572.7mV  -2.938mA   -1.188mA   -4.898mA
-305.5mV  1.223mA    1.327mA    568uA
1.145V    477.3nA    109.4uA    9.398nA
2.367V    25.84mA    27.61mA    22.04mA
[Power Clamp]
-1.167V   248.9mA    271.3mA    226.1mA
-1.015V   122.5mA    147.6mA    98.72mA
-938.2mV  66.58mA    91.91mA    44.72mA
-900mV    42.94mA    67.18mA    25.01mA
-861.8mV  24.57mA    45.68mA    13.43mA
-823.6mV  13.44mA    28.61mA    8.848mA
-785.5mV  8.584mA    16.9mA     7.284mA
-747.3mV  6.689mA    10.2mA     6.405mA
-556.4mV  3.007mA    3.015mA    3.091mA
16.36mV   -369.1uA   -421.8uA   -328.8uA
1.009V    -19.19mA   -20.07mA   -17.6mA
2.384V    -32.86mA   -39.13mA   -28.89mA
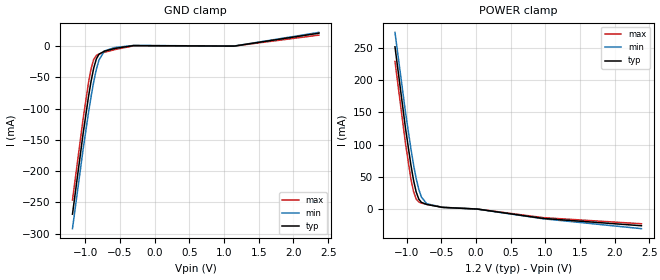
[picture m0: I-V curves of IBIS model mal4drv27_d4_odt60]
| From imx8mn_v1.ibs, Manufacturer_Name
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[Model] mal4drv27_d4_odt60
Model_type   Input
Polarity   Non-Inverting
Enable   Active-High
C_comp   1.773pF   1.632pF   1.802pF
C_comp_power_clamp   762.641fF   681.576fF   772.961fF
C_comp_gnd_clamp 909.435fF   885.776fF   931.184fF
Vinh = 848.000mV
Vinl = 733.000mV
[Model Spec]
D_overshoot_ampl_h 0.24 NA   NA
D_overshoot_ampl_l 0.24 NA   NA
D_overshoot_area_l 300.000m NA   NA
D_overshoot_area_h 300.000m NA   NA
|[Receiver Thresholds]
|Vth = 791.000mV
|Vth_min = 751.000mV
|Vth_max = 830.000mV
|Vinh_ac = 68.000mV
|Vinh_dc = 68.000mV
|Vinl_ac = -68.000mV
|Vinl_dc = -68.000mV
|Tslew_ac = 5.000ns
|Threshold_sensitivity = 0.5
|Reference_supply Power_clamp_ref
[Temperature Range]   25.000   125.000   -40.000
[Voltage Range]   1.200V   1.140V   1.260V
[GND Clamp Reference]   0.00V   0.00V   0.00V
|[C Comp Corner]
|| variable   typ   min   max
|C_comp 1.773pF   1.632pF   1.802pF
|C_comp_pullup 772.961fF   681.576fF   762.641fF
|C_comp_pulldown 909.435fF   885.776fF   931.184fF
[POWER Clamp Reference]   1.200V   1.140V   1.260V
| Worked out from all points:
|   GND clamp passes 1 mA (typ) near -0.45 V on its own axis
|   POWER clamp passes 1 mA (typ) near -0.39 V on its own axis
[GND Clamp]
-1.184V   -269mA     -292.2mA   -246.5mA
-1.031V   -140.3mA   -165.4mA   -116.6mA
-954.6mV  -82.06mA   -107.6mA   -59.47mA
-916.4mV  -56.5mA    -81.07mA   -36.53mA
-878.2mV  -35.27mA   -57.31mA   -21.34mA
-840mV    -20.56mA   -37.26mA   -14.87mA
-801.8mV  -13.01mA   -22.26mA   -12.57mA
-725.5mV  -8.16mA    -7.95mA    -9.99mA
-572.7mV  -3.734mA   -2.234mA   -5.528mA
-305.5mV  829uA      1.022mA    278uA
1.145V    408.8nA    86.68uA    5.098nA
2.367V    20.63mA    21.93mA    17.6mA
[Power Clamp]
-1.167V   251.9mA    274.3mA    229.2mA
-1.015V   125mA      149.8mA    101.2mA
-938.2mV  68.66mA    93.87mA    46.93mA
-900mV    44.85mA    68.96mA    27.07mA
-861.8mV  26.34mA    47.29mA    15.34mA
-823.6mV  15.05mA    30.07mA    10.61mA
-785.5mV  10.04mA    18.21mA    8.9mA
-709.1mV  6.83mA     7.915mA    6.971mA
-480mV    2.23mA     2.331mA    2.427mA
16.36mV   -294.6uA   -335.1uA   -262.5uA
970.9mV   -14.95mA   -15.47mA   -13.7mA
2.384V    -26.27mA   -30.8mA    -23.18mA
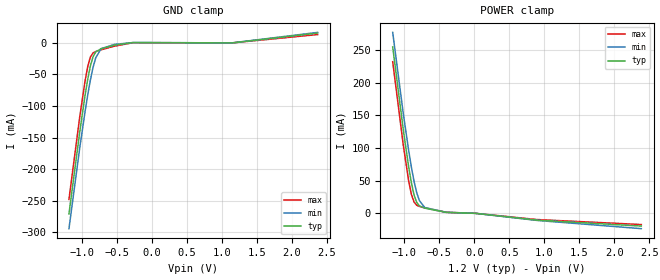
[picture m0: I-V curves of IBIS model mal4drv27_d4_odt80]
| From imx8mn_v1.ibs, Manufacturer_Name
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[Model] mal4drv27_d4_odt80
Model_type   Input
Polarity   Non-Inverting
Enable   Active-High
C_comp   1.718pF   1.600pF   1.743pF
C_comp_power_clamp   741.333fF   667.334fF   747.410fF
C_comp_gnd_clamp 888.264fF   871.674fF   903.141fF
Vinh = 813.000mV
Vinl = 698.000mV
[Model Spec]
D_overshoot_ampl_h 0.24 NA   NA
D_overshoot_ampl_l 0.24 NA   NA
D_overshoot_area_l 300.000m NA   NA
D_overshoot_area_h 300.000m NA   NA
|[Receiver Thresholds]
|Vth = 756.000mV
|Vth_min = 718.000mV
|Vth_max = 793.000mV
|Vinh_ac = 68.000mV
|Vinh_dc = 68.000mV
|Vinl_ac = -68.000mV
|Vinl_dc = -68.000mV
|Tslew_ac = 5.000ns
|Threshold_sensitivity = 0.5
|Reference_supply Power_clamp_ref
[Temperature Range]   25.000   125.000   -40.000
[Voltage Range]   1.200V   1.140V   1.260V
[GND Clamp Reference]   0.00V   0.00V   0.00V
|[C Comp Corner]
|| variable   typ   min   max
|C_comp 1.718pF   1.600pF   1.743pF
|C_comp_pullup 747.410fF   667.334fF   741.333fF
|C_comp_pulldown 888.264fF   871.674fF   903.141fF
[POWER Clamp Reference]   1.200V   1.140V   1.260V
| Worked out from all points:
|   GND clamp passes 1 mA (typ) near -0.42 V on its own axis
|   POWER clamp passes 1 mA (typ) near -0.39 V on its own axis
[GND Clamp]
-1.184V   -271mA     -294.4mA   -248.1mA
-1.031V   -141.9mA   -167.3mA   -118mA
-954.6mV  -83.57mA   -109.3mA   -60.71mA
-916.4mV  -57.95mA   -82.79mA   -37.72mA
-878.2mV  -36.64mA   -58.89mA   -22.47mA
-840mV    -21.87mA   -38.75mA   -15.95mA
-801.8mV  -14.24mA   -23.67mA   -13.58mA
-725.5mV  -9.26mA    -9.19mA    -10.9mA
-534.5mV  -3.54mA    -2.33mA    -5.13mA
-267.3mV  614uA      558.8uA    354uA
1.145V    313.1nA    66.25uA    891pA
2.367V    15.55mA    16.67mA    13.25mA
[Power Clamp]
-1.167V   254.5mA    276.8mA    231.9mA
-1.015V   126.9mA    151.7mA    103.4mA
-938.2mV  70.39mA    95.4mA     48.86mA
-900mV    46.45mA    70.36mA    28.86mA
-861.8mV  27.78mA    48.55mA    16.99mA
-823.6mV  16.36mA    31.2mA     12.13mA
-785.5mV  11.21mA    19.22mA    10.29mA
-709.1mV  7.738mA    8.691mA    8.087mA
-403.6mV  1.221mA    1.413mA    1.409mA
16.36mV   -222.1uA   -254.7uA   -197.7uA
894.5mV   -10.64mA   -11.09mA   -9.721mA
2.384V    -19.7mA    -23.67mA   -17.38mA
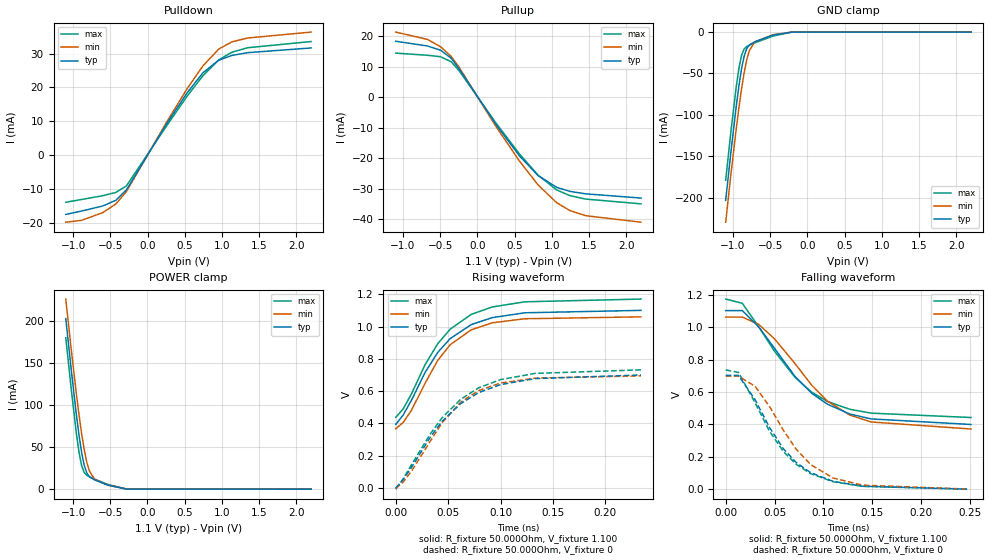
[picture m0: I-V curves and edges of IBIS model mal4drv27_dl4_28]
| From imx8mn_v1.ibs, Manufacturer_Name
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[Model] mal4drv27_dl4_28
Model_type   I/O
Polarity   Non-Inverting
Enable   Active-High
C_comp   1.539pF   1.529pF   1.545pF
C_comp_pullup   679.378fF   664.447fF   683.692fF
C_comp_pulldown 805.519fF   796.861fF   822.151fF
Vinh = 413.000mV
Vinl = 293.000mV
Vmeas = 353.000mV
Vref = 353.000mV
Rref = 50Ohms
Cref = 5pF
[Model Spec]
Vinh   413.000mV   400.000mV   435.000mV
Vinl   293.000mV   280.000mV   315.000mV
Vmeas   353.000mV   340.000mV   375.000mV
Vref   353.000mV   340.000mV   375.000mV
D_overshoot_ampl_h 0.3 NA   NA
D_overshoot_ampl_l 0.3 NA   NA
D_overshoot_area_l 100.000m NA   NA
D_overshoot_area_h 100.000m NA   NA
|[Receiver Thresholds]
|Vth = 353.000mV
|Vth_min = 340.000mV
|Vth_max = 375.000mV
|Vinh_ac = 600.000mV
|Vinh_dc = 600.000mV
|Vinl_ac = -600.000mV
|Vinl_dc = -600.000mV
|Tslew_ac = 5.000ns
|Threshold_sensitivity = 0.5
|Reference_supply Pullup_ref
[Temperature Range]   25.000   125.000   -40.000
[Voltage Range]   1.100V   1.060V   1.170V
[GND Clamp Reference]   0.00V   0.00V   0.00V
|[C Comp Corner]
|| variable   typ   min   max
|C_comp 1.545pF   1.529pF   1.539pF
|C_comp_pullup 683.692fF   664.447fF   679.378fF
|C_comp_pulldown 805.519fF   822.151fF   796.861fF
[Pulldown Reference]   0.00V   0.00V   0.00V
[POWER Clamp Reference]   1.100V   1.060V   1.170V
[Pullup Reference]   1.100V   1.060V   1.170V
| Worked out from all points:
|   slope of the pulldown table from 0 to 0.165 V, typ, clamps not added: 27.5 ohm
|   slope of the pullup table from 0 to 0.165 V, typ, clamps not added: 27.5 ohm
|   GND clamp passes 1 mA (typ) near -0.34 V on its own axis
|   POWER clamp passes 1 mA (typ) near -0.37 V on its own axis
|   rising waveform, R_fixture 50.000Ohm, V_fixture 1.100: 20-80 % time 43.9ps typ, 40.7ps min, 44ps max; typ from 0.394 V to 1.1 V
|   rising waveform, R_fixture 50.000Ohm, V_fixture 0: 20-80 % time 54.1ps typ, 48.2ps min, 54.6ps max; typ from 0 V to 0.7 V
|   falling waveform, R_fixture 50.000Ohm, V_fixture 1.100: 20-80 % time 60.7ps typ, 61ps min, 59.4ps max; typ from 1.1 V to 0.4 V
|   falling waveform, R_fixture 50.000Ohm, V_fixture 0: 20-80 % time 47.8ps typ, 49.6ps min, 47.9ps max; typ from 0.702 V to 0.001 V
[GND Clamp]
-1.099V   -203.4mA   -229.8mA   -179.1mA
-1.028V   -144.6mA   -171.6mA   -119.9mA
-957.3mV  -89.96mA   -117.2mA   -66.34mA
-921.8mV  -65.62mA   -92.07mA   -44.23mA
-886.4mV  -44.77mA   -69.12mA   -28.39mA
-850.9mV  -29.17mA   -49.17mA   -20.45mA
-815.5mV  -19.93mA   -33.26mA   -17.37mA
-780mV    -15.54mA   -22.17mA   -15.71mA
-709.1mV  -11.77mA   -11.95mA   -13.05mA
-460.9mV  -3.594mA   -3.176mA   -4.769mA
-212.7mV  -39.63uA   -70.42uA   -94.27uA
2.198V    74.25nA    840.4nA    20.58nA
[Power Clamp]
-1.098V   203.2mA    226.4mA    180.4mA
-1.027V   144mA      168.2mA    120.9mA
-956.4mV  89.16mA    113.9mA    66.8mA
-920.9mV  64.74mA    88.96mA    44.41mA
-885.5mV  43.86mA    66.33mA    28.14mA
-850mV    28.29mA    46.87mA    19.77mA
-814.5mV  19.12mA    31.59mA    16.46mA
-779.1mV  14.74mA    21.12mA    14.69mA
-708.2mV  10.9mA     11.5mA     11.88mA
-530.9mV  4.726mA    4.702mA    5.575mA
-282.7mV  125.9uA    313.7uA    153.4uA
2.199V    -42.87nA   -857.3nA   -9.404nA
[Pulldown]
-1.099V   -17.6mA    -19.9mA    -14mA
-886.4mV  -16.6mA    -19.35mA   -13.18mA
-602.7mV  -15.11mA   -17.07mA   -12.06mA
-425.5mV  -13.4mA    -14.5mA    -11.08mA
-283.6mV  -10.32mA   -10.82mA   -9.149mA
248.2mV   8.941mA    9.439mA    8.36mA
531.8mV   18.41mA    19.62mA    17.42mA
744.5mV   24.35mA    26.39mA    23.48mA
957.3mV   28.09mA    31.37mA    28.17mA
1.135V    29.49mA    33.52mA    30.45mA
1.347V    30.31mA    34.65mA    31.77mA
2.198V    31.7mA     36.4mA     33.6mA
[Pullup]
-1.098V   18.3mA     21.3mA     14.4mA
-672.7mV  16.75mA    18.91mA    13.71mA
-495.5mV  15.36mA    16.51mA    13.22mA
-353.6mV  12.78mA    13.34mA    11.6mA
-247.3mV  9.301mA    9.807mA    8.682mA
249.1mV   -8.956mA   -9.618mA   -8.509mA
568.2mV   -19.35mA   -21.07mA   -18.74mA
816.4mV   -25.75mA   -28.81mA   -25.6mA
1.065V    -29.58mA   -34.62mA   -30.44mA
1.242V    -30.9mA    -37.19mA   -32.3mA
1.455V    -31.72mA   -38.88mA   -33.43mA
2.199V    -33.1mA    -41.01mA   -35mA
[Ramp]
R_load=50.000Ohm
dV/dt_r   421.230mV/50.000ps  416.219mV/45.000ps  438.720mV/50.000ps
dV/dt_f   421.260mV/55.500ps  416.219mV/56.500ps  438.720mV/55.000ps
[Rising waveform]
R_fixture=50.000Ohm
V_fixture=1.100
V_fixture_min=1.060
V_fixture_max=1.170
0s        394.4mV    367.5mV    437.5mV
7ps       451.2mV    405.3mV    489.1mV
15ps      543.6mV    481.8mV    582.9mV
28ps      715.4mV    648.7mV    763.8mV
40ps      839.3mV    789.7mV    893mV
52ps      925.5mV    887.6mV    983.9mV
72ps      1.012V     979.6mV    1.075V
92ps      1.055V     1.023V     1.121V
123ps     1.085V     1.048V     1.153V
234ps     1.1V       1.06V      1.17V
[Rising waveform]
R_fixture=50.000Ohm
V_fixture=0
0s        -417.7uV   -3.544mV   -6.712mV
7ps       52.26mV    37mV       56.68mV
15ps      127.3mV    104.1mV    144.2mV
33ps      315.8mV    290.5mV    335.1mV
44ps      411.6mV    402.6mV    433.7mV
62ps      523.3mV    532mV      550mV
79ps      590.8mV    603.2mV    620.2mV
100ps     640.4mV    650.5mV    671.4mV
133ps     677.7mV    680.6mV    709.9mV
234ps     700.1mV    694.8mV    731.8mV
[Falling waveform]
R_fixture=50.000Ohm
V_fixture=1.100
V_fixture_min=1.060
V_fixture_max=1.170
0s        1.102V     1.062V     1.173V
17ps      1.102V     1.062V     1.147V
34ps      1V         1.016V     999.9mV
50ps      869mV      927.6mV    851.2mV
71ps      695.6mV    774.6mV    689.9mV
88ps      592.2mV    642.2mV    598.9mV
104ps     525mV      544mV      541.8mV
127ps     464.1mV    457.6mV    493.4mV
149ps     433.7mV    415mV      469.4mV
251ps     399.6mV    371.6mV    442.5mV
[Falling waveform]
R_fixture=50.000Ohm
V_fixture=0
0s        702.5mV    697.7mV    735.9mV
13ps      702.5mV    697.7mV    721mV
30ps      553.7mV    635.8mV    534.9mV
45ps      379.6mV    509.3mV    356.9mV
59ps      250.3mV    364.5mV    233.1mV
72ps      165.6mV    248.2mV    154.8mV
87ps      102.1mV    152.3mV    96.01mV
110ps     48.95mV    69.21mV    46.46mV
140ps     18.92mV    25.48mV    17.88mV
247ps     778.6uV    1.257mV    649.3uV
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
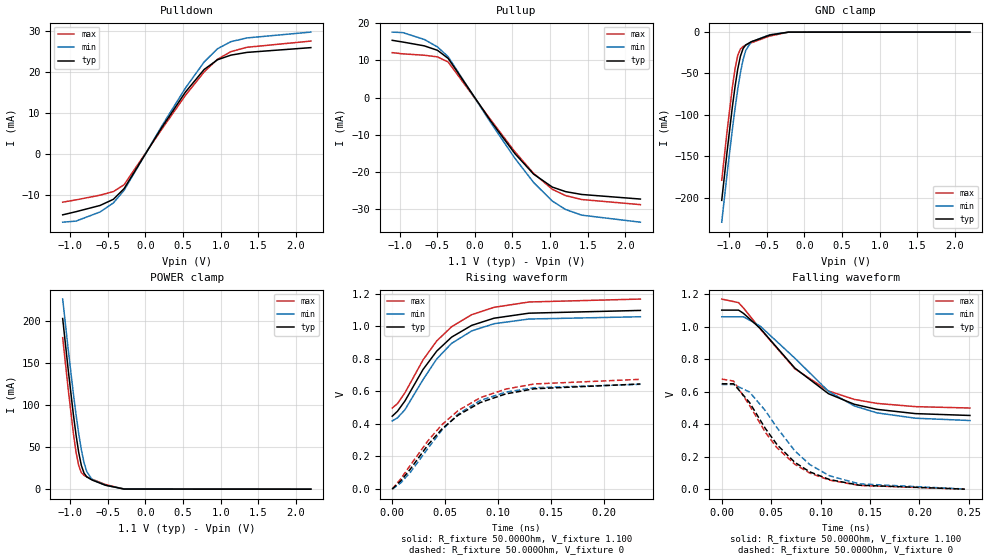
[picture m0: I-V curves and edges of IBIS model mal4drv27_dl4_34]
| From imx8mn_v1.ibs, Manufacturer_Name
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[Model] mal4drv27_dl4_34
Model_type   I/O
Polarity   Non-Inverting
Enable   Active-High
C_comp   1.539pF   1.529pF   1.545pF
C_comp_pullup   679.378fF   664.447fF   683.692fF
C_comp_pulldown 805.519fF   796.861fF   822.151fF
Vinh = 387.000mV
Vinl = 267.000mV
Vmeas = 327.000mV
Vref = 327.000mV
Rref = 50Ohms
Cref = 5pF
[Model Spec]
Vinh   387.000mV   375.000mV   408.000mV
Vinl   267.000mV   255.000mV   288.000mV
Vmeas   327.000mV   315.000mV   348.000mV
Vref   327.000mV   315.000mV   348.000mV
D_overshoot_ampl_h 0.3 NA   NA
D_overshoot_ampl_l 0.3 NA   NA
D_overshoot_area_l 100.000m NA   NA
D_overshoot_area_h 100.000m NA   NA
|[Receiver Thresholds]
|Vth = 327.000mV
|Vth_min = 315.000mV
|Vth_max = 348.000mV
|Vinh_ac = 600.000mV
|Vinh_dc = 600.000mV
|Vinl_ac = -600.000mV
|Vinl_dc = -600.000mV
|Tslew_ac = 5.000ns
|Threshold_sensitivity = 0.5
|Reference_supply Pullup_ref
[Temperature Range]   25.000   125.000   -40.000
[Voltage Range]   1.100V   1.060V   1.170V
[GND Clamp Reference]   0.00V   0.00V   0.00V
|[C Comp Corner]
|| variable   typ   min   max
|C_comp 1.545pF   1.529pF   1.539pF
|C_comp_pullup 683.692fF   664.447fF   679.378fF
|C_comp_pulldown 805.519fF   822.151fF   796.861fF
[Pulldown Reference]   0.00V   0.00V   0.00V
[POWER Clamp Reference]   1.100V   1.060V   1.170V
[Pullup Reference]   1.100V   1.060V   1.170V
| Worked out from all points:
|   slope of the pulldown table from 0 to 0.165 V, typ, clamps not added: 33.5 ohm
|   slope of the pullup table from 0 to 0.165 V, typ, clamps not added: 33.5 ohm
|   GND clamp passes 1 mA (typ) near -0.34 V on its own axis
|   POWER clamp passes 1 mA (typ) near -0.37 V on its own axis
|   rising waveform, R_fixture 50.000Ohm, V_fixture 1.100: 20-80 % time 48.3ps typ, 45.4ps min, 48.5ps max; typ from 0.447 V to 1.1 V
|   rising waveform, R_fixture 50.000Ohm, V_fixture 0: 20-80 % time 60.3ps typ, 54ps min, 60.3ps max; typ from -0.002 V to 0.646 V
|   falling waveform, R_fixture 50.000Ohm, V_fixture 1.100: 20-80 % time 67.7ps typ, 67.9ps min, 65.8ps max; typ from 1.1 V to 0.455 V
|   falling waveform, R_fixture 50.000Ohm, V_fixture 0: 20-80 % time 52.7ps typ, 53.9ps min, 52.7ps max; typ from 0.65 V to 0.001 V
[GND Clamp]
-1.099V   -203.4mA   -229.8mA   -179.1mA
-1.028V   -144.6mA   -171.6mA   -119.9mA
-957.3mV  -89.96mA   -117.2mA   -66.34mA
-921.8mV  -65.62mA   -92.07mA   -44.23mA
-886.4mV  -44.77mA   -69.12mA   -28.39mA
-850.9mV  -29.17mA   -49.17mA   -20.45mA
-815.5mV  -19.93mA   -33.26mA   -17.37mA
-780mV    -15.54mA   -22.17mA   -15.71mA
-709.1mV  -11.77mA   -11.95mA   -13.05mA
-460.9mV  -3.594mA   -3.176mA   -4.769mA
-212.7mV  -39.63uA   -70.42uA   -94.27uA
2.198V    74.25nA    840.4nA    20.58nA
[Power Clamp]
-1.098V   203.2mA    226.4mA    180.4mA
-1.027V   144mA      168.2mA    120.9mA
-956.4mV  89.16mA    113.9mA    66.8mA
-920.9mV  64.74mA    88.96mA    44.41mA
-885.5mV  43.86mA    66.33mA    28.14mA
-850mV    28.29mA    46.87mA    19.77mA
-814.5mV  19.12mA    31.59mA    16.46mA
-779.1mV  14.74mA    21.12mA    14.69mA
-708.2mV  10.9mA     11.5mA     11.88mA
-530.9mV  4.726mA    4.702mA    5.575mA
-282.7mV  125.9uA    313.7uA    153.4uA
2.199V    -42.87nA   -857.3nA   -9.404nA
[Pulldown]
-1.099V   -14.9mA    -16.7mA    -11.8mA
-921.8mV  -14.13mA   -16.43mA   -11.24mA
-602.7mV  -12.61mA   -14.2mA    -10.09mA
-425.5mV  -11.1mA    -11.99mA   -9.21mA
-283.6mV  -8.499mA   -8.905mA   -7.553mA
212.7mV   6.321mA    6.665mA    5.912mA
531.8mV   15.13mA    16.12mA    14.33mA
780mV     20.65mA    22.48mA    20.06mA
957.3mV   23.03mA    25.72mA    23.15mA
1.135V    24.16mA    27.45mA    25.01mA
1.347V    24.83mA    28.37mA    26.08mA
2.198V    26mA       29.8mA     27.6mA
[Pullup]
-1.098V   15.4mA     17.61mA    12.1mA
-956.4mV  14.94mA    17.47mA    11.77mA
-672.7mV  13.92mA    15.64mA    11.4mA
-495.5mV  12.71mA    13.62mA    10.95mA
-353.6mV  10.53mA    10.97mA    9.562mA
213.6mV   -6.345mA   -6.786mA   -6.02mA
532.7mV   -15.03mA   -16.28mA   -14.52mA
780.9mV   -20.52mA   -22.76mA   -20.32mA
1.029V    -23.99mA   -27.74mA   -24.58mA
1.206V    -25.21mA   -30.01mA   -26.29mA
1.419V    -25.97mA   -31.52mA   -27.32mA
2.199V    -27.2mA    -33.41mA   -28.7mA
[Ramp]
R_load=50.000Ohm
dV/dt_r   389.280mV/55.000ps  386.068mV/50.500ps  404.760mV/55.500ps
dV/dt_f   389.280mV/61.500ps  386.069mV/62.500ps  404.760mV/61.000ps
[Rising waveform]
R_fixture=50.000Ohm
V_fixture=1.100
V_fixture_min=1.060
V_fixture_max=1.170
0s        446.8mV    417.5mV    497.2mV
5ps       477.8mV    437.2mV    524.6mV
12ps      540.7mV    486.9mV    591.1mV
29ps      734.4mV    671.7mV    793.4mV
42ps      848.4mV    799.9mV    911mV
56ps      934.4mV    895.9mV    998.5mV
75ps      1.007V     972.9mV    1.073V
96ps      1.051V     1.017V     1.118V
129ps     1.082V     1.046V     1.151V
234ps     1.099V     1.06V      1.169V
[Rising waveform]
R_fixture=50.000Ohm
V_fixture=0
0s        -1.683mV   -2.801mV   -2.855mV
8ps       47.69mV    35.67mV    60.36mV
17ps      120.1mV    100.2mV    143.9mV
34ps      272.7mV    251.1mV    297.9mV
47ps      369.2mV    362.3mV    395.5mV
62ps      452.4mV    459.4mV    480.7mV
83ps      531mV      543.7mV    561mV
107ps     584.3mV    595.4mV    614mV
134ps     616mV      622.6mV    645.8mV
234ps     645.5mV    643.6mV    674.1mV
[Falling waveform]
R_fixture=50.000Ohm
V_fixture=1.100
V_fixture_min=1.060
V_fixture_max=1.170
0s        1.103V     1.062V     1.171V
17ps      1.103V     1.062V     1.149V
22ps      1.083V     1.062V     1.116V
39ps      989.9mV    1.004V     986.9mV
74ps      745.8mV    806.8mV    741.7mV
108ps     588.4mV    603.1mV    605.4mV
134ps     523.6mV    513.5mV    553.6mV
157ps     492.2mV    470.6mV    528.8mV
196ps     466mV      437.7mV    508.9mV
251ps     454.6mV    423.5mV    500.5mV
[Falling waveform]
R_fixture=50.000Ohm
V_fixture=0
0s        649.6mV    645.6mV    678.5mV
12ps      649.6mV    645.6mV    666.3mV
28ps      535.2mV    599.4mV    518mV
44ps      375.7mV    485.2mV    352.1mV
56ps      274.4mV    378.2mV    254.8mV
74ps      165.6mV    236.2mV    153.8mV
89ps      107.8mV    152.9mV    100.3mV
109ps     60.23mV    83.36mV    56.59mV
139ps     25.53mV    33.84mV    24.04mV
246ps     1.23mV     1.846mV    1.078mV
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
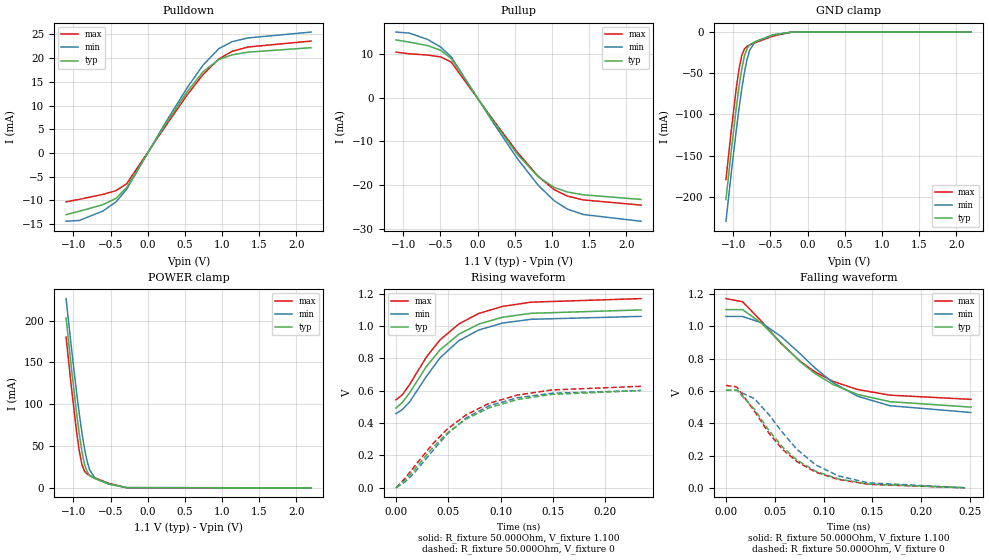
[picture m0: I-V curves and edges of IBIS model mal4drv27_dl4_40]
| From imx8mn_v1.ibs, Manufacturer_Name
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[Model] mal4drv27_dl4_40
Model_type   I/O
Polarity   Non-Inverting
Enable   Active-High
C_comp   1.539pF   1.529pF   1.545pF
C_comp_pullup   679.378fF   664.447fF   683.692fF
C_comp_pulldown 805.519fF   796.861fF   822.151fF
Vinh = 366.000mV
Vinl = 246.000mV
Vmeas = 306.000mV
Vref = 306.000mV
Rref = 50Ohms
Cref = 5pF
[Model Spec]
Vinh   366.000mV   354.000mV   385.000mV
Vinl   246.000mV   234.000mV   265.000mV
Vmeas   306.000mV   294.000mV   325.000mV
Vref   306.000mV   294.000mV   325.000mV
D_overshoot_ampl_h 0.3 NA   NA
D_overshoot_ampl_l 0.3 NA   NA
D_overshoot_area_l 100.000m NA   NA
D_overshoot_area_h 100.000m NA   NA
|[Receiver Thresholds]
|Vth = 306.000mV
|Vth_min = 294.000mV
|Vth_max = 325.000mV
|Vinh_ac = 600.000mV
|Vinh_dc = 600.000mV
|Vinl_ac = -600.000mV
|Vinl_dc = -600.000mV
|Tslew_ac = 5.000ns
|Threshold_sensitivity = 0.5
|Reference_supply Pullup_ref
[Temperature Range]   25.000   125.000   -40.000
[Voltage Range]   1.100V   1.060V   1.170V
[GND Clamp Reference]   0.00V   0.00V   0.00V
|[C Comp Corner]
|| variable   typ   min   max
|C_comp 1.545pF   1.529pF   1.539pF
|C_comp_pullup 683.692fF   664.447fF   679.378fF
|C_comp_pulldown 805.519fF   822.151fF   796.861fF
[Pulldown Reference]   0.00V   0.00V   0.00V
[POWER Clamp Reference]   1.100V   1.060V   1.170V
[Pullup Reference]   1.100V   1.060V   1.170V
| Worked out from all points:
|   slope of the pulldown table from 0 to 0.165 V, typ, clamps not added: 39.1 ohm
|   slope of the pullup table from 0 to 0.165 V, typ, clamps not added: 39.1 ohm
|   GND clamp passes 1 mA (typ) near -0.34 V on its own axis
|   POWER clamp passes 1 mA (typ) near -0.37 V on its own axis
|   rising waveform, R_fixture 50.000Ohm, V_fixture 1.100: 20-80 % time 52.1ps typ, 49ps min, 52.1ps max; typ from 0.492 V to 1.1 V
|   rising waveform, R_fixture 50.000Ohm, V_fixture 0: 20-80 % time 64.9ps typ, 58.7ps min, 64.8ps max; typ from -0.001 V to 0.6 V
|   falling waveform, R_fixture 50.000Ohm, V_fixture 1.100: 20-80 % time 73.2ps typ, 73.1ps min, 70.8ps max; typ from 1.1 V to 0.5 V
|   falling waveform, R_fixture 50.000Ohm, V_fixture 0: 20-80 % time 56.4ps typ, 57.6ps min, 56.3ps max; typ from 0.605 V to 0.002 V
[GND Clamp]
-1.099V   -203.4mA   -229.8mA   -179.1mA
-1.028V   -144.6mA   -171.6mA   -119.9mA
-957.3mV  -89.96mA   -117.2mA   -66.34mA
-921.8mV  -65.62mA   -92.07mA   -44.23mA
-886.4mV  -44.77mA   -69.12mA   -28.39mA
-850.9mV  -29.17mA   -49.17mA   -20.45mA
-815.5mV  -19.93mA   -33.26mA   -17.37mA
-780mV    -15.54mA   -22.17mA   -15.71mA
-709.1mV  -11.77mA   -11.95mA   -13.05mA
-460.9mV  -3.594mA   -3.176mA   -4.769mA
-212.7mV  -39.63uA   -70.42uA   -94.27uA
2.198V    74.25nA    840.4nA    20.58nA
[Power Clamp]
-1.098V   203.2mA    226.4mA    180.4mA
-1.027V   144mA      168.2mA    120.9mA
-956.4mV  89.16mA    113.9mA    66.8mA
-920.9mV  64.74mA    88.96mA    44.41mA
-885.5mV  43.86mA    66.33mA    28.14mA
-850mV    28.29mA    46.87mA    19.77mA
-814.5mV  19.12mA    31.59mA    16.46mA
-779.1mV  14.74mA    21.12mA    14.69mA
-708.2mV  10.9mA     11.5mA     11.88mA
-530.9mV  4.726mA    4.702mA    5.575mA
-282.7mV  125.9uA    313.7uA    153.4uA
2.199V    -42.87nA   -857.3nA   -9.404nA
[Pulldown]
-1.099V   -13mA      -14.4mA    -10.3mA
-921.8mV  -12.29mA   -14.23mA   -9.78mA
-602.7mV  -10.9mA    -12.24mA   -8.726mA
-425.5mV  -9.548mA   -10.3mA    -7.94mA
-283.6mV  -7.285mA   -7.629mA   -6.482mA
212.7mV   5.412mA    5.704mA    5.063mA
531.8mV   12.95mA    13.79mA    12.27mA
744.5mV   17.12mA    18.54mA    16.55mA
957.3mV   19.72mA    22mA       19.83mA
1.135V    20.69mA    23.47mA    21.42mA
1.347V    21.26mA    24.25mA    22.34mA
2.198V    22.2mA     25.5mA     23.6mA
[Pullup]
-1.098V   13.3mA     15.11mA    10.5mA
-920.9mV  12.81mA    14.87mA    10.13mA
-672.7mV  12mA       13.42mA    9.829mA
-495.5mV  10.92mA    11.65mA    9.411mA
-353.6mV  9.019mA    9.37mA     8.2mA
213.6mV   -5.431mA   -5.787mA   -5.154mA
532.7mV   -12.87mA   -13.87mA   -12.43mA
816.4mV   -18.12mA   -20.07mA   -18.02mA
1.029V    -20.53mA   -23.58mA   -21.05mA
1.206V    -21.58mA   -25.49mA   -22.51mA
1.419V    -22.23mA   -26.75mA   -23.4mA
2.199V    -23.3mA    -28.31mA   -24.6mA
[Ramp]
R_load=50.000Ohm
dV/dt_r   362.910mV/60.000ps  360.988mV/55.000ps  376.830mV/60.000ps
dV/dt_f   362.910mV/67.000ps  360.988mV/67.500ps  376.830mV/65.000ps
[Rising waveform]
R_fixture=50.000Ohm
V_fixture=1.100
V_fixture_min=1.060
V_fixture_max=1.170
0s        491.6mV    456.4mV    542.8mV
6ps       526.1mV    482.4mV    573.5mV
13ps      585.8mV    529.6mV    637.3mV
29ps      748.4mV    687.2mV    807.6mV
42ps      851.5mV    802.1mV    913.2mV
60ps      948.4mV    908.8mV    1.012V
79ps      1.011V     974.9mV    1.077V
102ps     1.054V     1.018V     1.121V
129ps     1.078V     1.041V     1.147V
234ps     1.099V     1.059V     1.169V
[Rising waveform]
R_fixture=50.000Ohm
V_fixture=0
0s        -862.9uV   -1.614mV   -1.879mV
8ps       42.26mV    31.22mV    52.54mV
18ps      112.9mV    94.35mV    134mV
35ps      246.8mV    226.9mV    269.8mV
49ps      337.5mV    331.5mV    361.6mV
67ps      423.5mV    430.6mV    449.8mV
89ps      493.7mV    506mV      521.4mV
116ps     544.7mV    555.8mV    572.2mV
149ps     576.4mV    583.2mV    604mV
234ps     600.2mV    600.4mV    626.4mV
[Falling waveform]
R_fixture=50.000Ohm
V_fixture=1.100
V_fixture_min=1.060
V_fixture_max=1.170
0s        1.102V     1.06V      1.17V
17ps      1.102V     1.06V      1.151V
36ps      1.02V      1.022V     1.032V
57ps      893.4mV    933.3mV    890mV
76ps      780.4mV    829.6mV    783.5mV
91ps      708.7mV    742.9mV    718.2mV
110ps     638.7mV    649.9mV    658.3mV
135ps     577.9mV    566.8mV    608.6mV
168ps     533.6mV    508.6mV    573.9mV
251ps     500.1mV    466.8mV    547.9mV
[Falling waveform]
R_fixture=50.000Ohm
V_fixture=0
0s        605mV      603.9mV    634.1mV
11ps      605mV      603.9mV    624.8mV
29ps      488.5mV    552.6mV    477.1mV
44ps      356.3mV    453.8mV    339.2mV
58ps      253mV      342.8mV    239.1mV
73ps      172mV      237.9mV    162.7mV
92ps      103.9mV    143mV      98.47mV
115ps     56.47mV    75.64mV    53.68mV
146ps     24.73mV    32.1mV     23.47mV
245ps     1.824mV    2.515mV    1.631mV
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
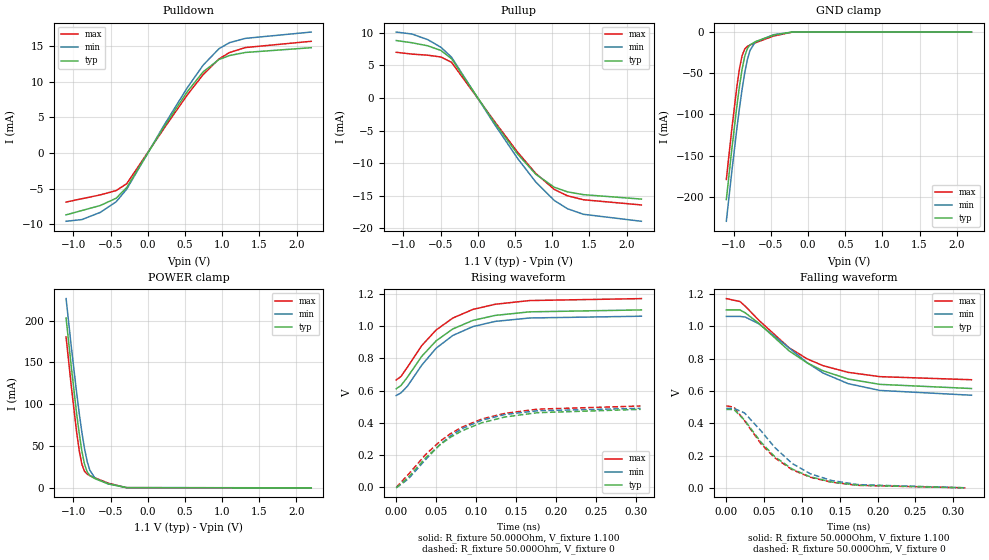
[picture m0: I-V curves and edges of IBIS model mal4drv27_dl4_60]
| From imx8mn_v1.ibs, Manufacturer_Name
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[Model] mal4drv27_dl4_60
Model_type   I/O
Polarity   Non-Inverting
Enable   Active-High
C_comp   1.539pF   1.529pF   1.545pF
C_comp_pullup   679.378fF   664.447fF   683.692fF
C_comp_pulldown 805.519fF   796.861fF   822.151fF
Vinh = 310.000mV
Vinl = 190.000mV
Vmeas = 250.000mV
Vref = 250.000mV
Rref = 50Ohms
Cref = 5pF
[Model Spec]
Vinh   310.000mV   301.000mV   326.000mV
Vinl   190.000mV   181.000mV   206.000mV
Vmeas   250.000mV   241.000mV   266.000mV
Vref   250.000mV   241.000mV   266.000mV
D_overshoot_ampl_h 0.3 NA   NA
D_overshoot_ampl_l 0.3 NA   NA
D_overshoot_area_l 100.000m NA   NA
D_overshoot_area_h 100.000m NA   NA
|[Receiver Thresholds]
|Vth = 250.000mV
|Vth_min = 241.000mV
|Vth_max = 266.000mV
|Vinh_ac = 600.000mV
|Vinh_dc = 600.000mV
|Vinl_ac = -600.000mV
|Vinl_dc = -600.000mV
|Tslew_ac = 5.000ns
|Threshold_sensitivity = 0.5
|Reference_supply Pullup_ref
[Temperature Range]   25.000   125.000   -40.000
[Voltage Range]   1.100V   1.060V   1.170V
[GND Clamp Reference]   0.00V   0.00V   0.00V
|[C Comp Corner]
|| variable   typ   min   max
|C_comp 1.545pF   1.529pF   1.539pF
|C_comp_pullup 683.692fF   664.447fF   679.378fF
|C_comp_pulldown 805.519fF   822.151fF   796.861fF
[Pulldown Reference]   0.00V   0.00V   0.00V
[POWER Clamp Reference]   1.100V   1.060V   1.170V
[Pullup Reference]   1.100V   1.060V   1.170V
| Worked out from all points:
|   slope of the pulldown table from 0 to 0.165 V, typ, clamps not added: 58.7 ohm
|   slope of the pullup table from 0 to 0.165 V, typ, clamps not added: 58.7 ohm
|   GND clamp passes 1 mA (typ) near -0.34 V on its own axis
|   POWER clamp passes 1 mA (typ) near -0.37 V on its own axis
|   rising waveform, R_fixture 50.000Ohm, V_fixture 1.100: 20-80 % time 61.7ps typ, 58.9ps min, 61.9ps max; typ from 0.611 V to 1.1 V
|   rising waveform, R_fixture 50.000Ohm, V_fixture 0: 20-80 % time 78ps typ, 70.2ps min, 77.1ps max; typ from -0.002 V to 0.484 V
|   falling waveform, R_fixture 50.000Ohm, V_fixture 1.100: 20-80 % time 87.8ps typ, 87.2ps min, 84.3ps max; typ from 1.1 V to 0.615 V
|   falling waveform, R_fixture 50.000Ohm, V_fixture 0: 20-80 % time 66.4ps typ, 66.9ps min, 66.1ps max; typ from 0.485 V to 0.001 V
[GND Clamp]
-1.099V   -203.4mA   -229.8mA   -179.1mA
-1.028V   -144.6mA   -171.6mA   -119.9mA
-957.3mV  -89.96mA   -117.2mA   -66.34mA
-921.8mV  -65.62mA   -92.07mA   -44.23mA
-886.4mV  -44.77mA   -69.12mA   -28.39mA
-850.9mV  -29.17mA   -49.17mA   -20.45mA
-815.5mV  -19.93mA   -33.26mA   -17.37mA
-780mV    -15.54mA   -22.17mA   -15.71mA
-709.1mV  -11.77mA   -11.95mA   -13.05mA
-460.9mV  -3.594mA   -3.176mA   -4.769mA
-212.7mV  -39.63uA   -70.42uA   -94.27uA
2.198V    74.25nA    840.4nA    20.58nA
[Power Clamp]
-1.098V   203.2mA    226.4mA    180.4mA
-1.027V   144mA      168.2mA    120.9mA
-956.4mV  89.16mA    113.9mA    66.8mA
-920.9mV  64.74mA    88.96mA    44.41mA
-885.5mV  43.86mA    66.33mA    28.14mA
-850mV    28.29mA    46.87mA    19.77mA
-814.5mV  19.12mA    31.59mA    16.46mA
-779.1mV  14.74mA    21.12mA    14.69mA
-708.2mV  10.9mA     11.5mA     11.88mA
-530.9mV  4.726mA    4.702mA    5.575mA
-282.7mV  125.9uA    313.7uA    153.4uA
2.199V    -42.87nA   -857.3nA   -9.404nA
[Pulldown]
-1.099V   -8.7mA     -9.6mA     -6.9mA
-886.4mV  -8.09mA    -9.36mA    -6.43mA
-638.2mV  -7.382mA   -8.347mA   -5.89mA
-425.5mV  -6.36mA    -6.859mA   -5.286mA
-283.6mV  -4.852mA   -5.081mA   -4.318mA
212.7mV   3.605mA    3.8mA      3.373mA
531.8mV   8.63mA     9.187mA    8.175mA
744.5mV   11.41mA    12.35mA    11.02mA
957.3mV   13.14mA    14.66mA    13.22mA
1.099V    13.7mA     15.51mA    14.12mA
1.312V    14.13mA    16.11mA    14.82mA
2.198V    14.8mA     17mA       15.7mA
[Pullup]
-1.098V   8.8mA      10.1mA     7mA
-885.5mV  8.46mA     9.796mA    6.719mA
-672.7mV  7.986mA    8.931mA    6.549mA
-495.5mV  7.274mA    7.762mA    6.273mA
-353.6mV  6.007mA    6.243mA    5.462mA
213.6mV   -3.618mA   -3.855mA   -3.433mA
532.7mV   -8.572mA   -9.241mA   -8.283mA
780.9mV   -11.71mA   -12.91mA   -11.59mA
1.029V    -13.69mA   -15.72mA   -14.03mA
1.206V    -14.39mA   -16.98mA   -15mA
1.419V    -14.82mA   -17.83mA   -15.6mA
2.199V    -15.5mA    -18.9mA    -16.4mA
[Ramp]
R_load=50.000Ohm
dV/dt_r   291.960mV/71.000ps  294.178mV/66.000ps  302.400mV/71.500ps
dV/dt_f   291.960mV/79.000ps  294.178mV/79.000ps  302.400mV/76.500ps
[Rising waveform]
R_fixture=50.000Ohm
V_fixture=1.100
V_fixture_min=1.060
V_fixture_max=1.170
0s        610.7mV    569.3mV    665.5mV
6ps       631.2mV    585.4mV    687.1mV
14ps      682.2mV    626.5mV    744.2mV
32ps      811.9mV    757.1mV    878.3mV
50ps      907.7mV    862.1mV    974.8mV
71ps      981.4mV    941.2mV    1.049V
96ps      1.034V     995.6mV    1.102V
124ps     1.065V     1.028V     1.134V
167ps     1.087V     1.049V     1.157V
307ps     1.099V     1.06V      1.169V
[Rising waveform]
R_fixture=50.000Ohm
V_fixture=0
0s        -2.317mV   -2.3mV     -120.3uV
15ps      62.21mV    51.68mV    79.75mV
37ps      184.2mV    173.4mV    204.7mV
55ps      265.3mV    266.7mV    286.5mV
68ps      310.7mV    319.4mV    332.7mV
82ps      350mV      363.3mV    372.5mV
107ps     400.1mV    416.3mV    423.3mV
136ps     436.1mV    451.5mV    458.7mV
177ps     462.9mV    474.9mV    484.7mV
306ps     483.5mV    489.9mV    504.1mV
[Falling waveform]
R_fixture=50.000Ohm
V_fixture=1.100
V_fixture_min=1.060
V_fixture_max=1.170
0s        1.101V     1.061V     1.171V
18ps      1.101V     1.061V     1.153V
25ps      1.083V     1.057V     1.124V
43ps      1.018V     1.015V     1.037V
83ps      847.8mV    866mV      866.6mV
107ps     772.7mV    773.7mV    797.9mV
128ps     724.2mV    710.3mV    755.9mV
161ps     673.7mV    645mV      715mV
203ps     640.5mV    603mV      688.3mV
324ps     614.8mV    573.4mV    669.2mV
[Falling waveform]
R_fixture=50.000Ohm
V_fixture=0
0s        485.2mV    491.8mV    507.3mV
10ps      485.2mV    491.8mV    499.7mV
24ps      419.8mV    464.1mV    416.4mV
46ps      281.8mV    352.2mV    272.1mV
64ps      193.2mV    250.2mV    186.2mV
87ps      117mV      151.2mV    112.8mV
111ps     68.73mV    87.72mV    66.03mV
139ps     36.64mV    45.93mV    35.49mV
174ps     16.59mV    20.51mV    16.06mV
316ps     609.7uV    854.4uV    611uV
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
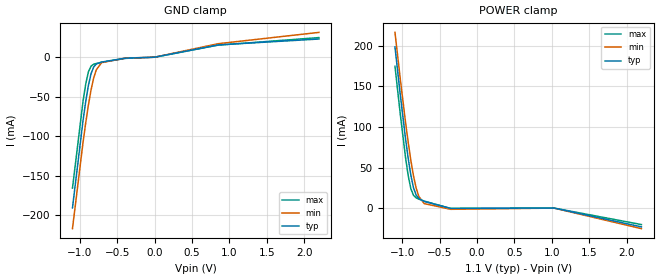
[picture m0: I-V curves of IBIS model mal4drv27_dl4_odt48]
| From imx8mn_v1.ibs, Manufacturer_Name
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[Model] mal4drv27_dl4_odt48
Model_type   Input
Polarity   Non-Inverting
Enable   Active-High
C_comp   1.465pF   1.433pF   1.472pF
C_comp_power_clamp   753.195fF   712.242fF   753.287fF
C_comp_gnd_clamp 644.966fF   634.625fF   658.991fF
Vinh = 407.000mV
Vinl = 287.000mV
[Model Spec]
D_overshoot_ampl_h 0.3 NA   NA
D_overshoot_ampl_l 0.3 NA   NA
D_overshoot_area_l 100.000m NA   NA
D_overshoot_area_h 100.000m NA   NA
|[Receiver Thresholds]
|Vth = 347.000mV
|Vth_min = 335.000mV
|Vth_max = 369.000mV
|Vinh_ac = 600.000mV
|Vinh_dc = 600.000mV
|Vinl_ac = -600.000mV
|Vinl_dc = -600.000mV
|Tslew_ac = 5.000ns
|Threshold_sensitivity = 0.5
|Reference_supply Power_clamp_ref
[Temperature Range]   25.000   125.000   -40.000
[Voltage Range]   1.100V   1.060V   1.170V
[GND Clamp Reference]   0.00V   0.00V   0.00V
|[C Comp Corner]
|| variable   typ   min   max
|C_comp 1.472pF   1.433pF   1.465pF
|C_comp_pullup 753.287fF   712.242fF   753.195fF
|C_comp_pulldown 644.966fF   658.991fF   634.625fF
[POWER Clamp Reference]   1.100V   1.060V   1.170V
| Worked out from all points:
|   GND clamp passes 1 mA (typ) near -0.37 V on its own axis
|   POWER clamp passes 1 mA (typ) near -0.45 V on its own axis
[GND Clamp]
-1.099V   -190.8mA   -217.1mA   -165.7mA
-957.3mV  -79.86mA   -107.5mA   -55.45mA
-921.8mV  -56.16mA   -83.14mA   -33.97mA
-886.4mV  -35.96mA   -60.88mA   -18.74mA
-850.9mV  -20.99mA   -41.58mA   -11.41mA
-815.5mV  -12.4mA    -26.32mA   -8.942mA
-780mV    -8.655mA   -15.87mA   -7.904mA
-709.1mV  -6.145mA   -6.873mA   -6.458mA
-390mV    -1.209mA   -1.098mA   -1.473mA
-1.5uV    -14.18uA   -12.57uA   -9.569uA
850.9mV   15.56mA    17.12mA    15.31mA
2.198V    23.04mA    31.41mA    24.83mA
[Power Clamp]
-1.098V   198.8mA    216.7mA    174.9mA
-1.027V   139.8mA    159.2mA    115.8mA
-956.4mV  85.32mA    105.5mA    62.12mA
-920.9mV  61.1mA     80.94mA    39.93mA
-885.5mV  40.38mA    58.67mA    23.88mA
-850mV    24.98mA    39.57mA    15.69mA
-814.5mV  15.96mA    24.62mA    12.59mA
-779.1mV  11.74mA    14.48mA    11.02mA
-708.2mV  8.22mA     5.545mA    8.611mA
-353.6mV  -460uA     -1.545mA   -444uA
1.029V    -8.247nA   -50.19uA   -1.049nA
2.199V    -23.23mA   -25.42mA   -20.37mA
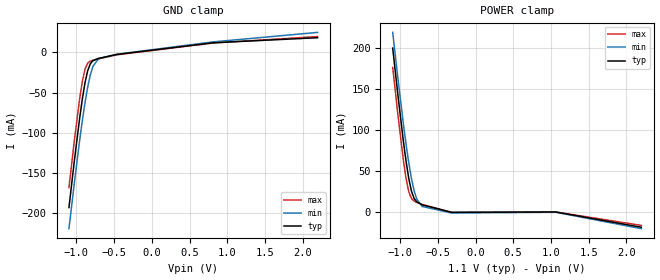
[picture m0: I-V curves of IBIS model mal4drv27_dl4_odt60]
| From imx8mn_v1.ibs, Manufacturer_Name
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[Model] mal4drv27_dl4_odt60
Model_type   Input
Polarity   Non-Inverting
Enable   Active-High
C_comp   1.483pF   1.456pF   1.490pF
C_comp_power_clamp   737.597fF   702.135fF   738.483fF
C_comp_gnd_clamp 681.283fF   671.125fF   696.225fF
Vinh = 435.000mV
Vinl = 315.000mV
[Model Spec]
D_overshoot_ampl_h 0.3 NA   NA
D_overshoot_ampl_l 0.3 NA   NA
D_overshoot_area_l 100.000m NA   NA
D_overshoot_area_h 100.000m NA   NA
|[Receiver Thresholds]
|Vth = 375.000mV
|Vth_min = 361.000mV
|Vth_max = 399.000mV
|Vinh_ac = 600.000mV
|Vinh_dc = 600.000mV
|Vinl_ac = -600.000mV
|Vinl_dc = -600.000mV
|Tslew_ac = 5.000ns
|Threshold_sensitivity = 0.5
|Reference_supply Power_clamp_ref
[Temperature Range]   25.000   125.000   -40.000
[Voltage Range]   1.100V   1.060V   1.170V
[GND Clamp Reference]   0.00V   0.00V   0.00V
|[C Comp Corner]
|| variable   typ   min   max
|C_comp 1.490pF   1.456pF   1.483pF
|C_comp_pullup 738.483fF   702.135fF   737.597fF
|C_comp_pulldown 681.283fF   696.225fF   671.125fF
[POWER Clamp Reference]   1.100V   1.060V   1.170V
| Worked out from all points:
|   GND clamp passes 1 mA (typ) near -0.36 V on its own axis
|   POWER clamp passes 1 mA (typ) near -0.44 V on its own axis
[GND Clamp]
-1.099V   -193.5mA   -219.8mA   -168.6mA
-1.028V   -135.6mA   -163mA     -110.3mA
-957.3mV  -82.07mA   -109.7mA   -57.78mA
-921.8mV  -58.25mA   -85.08mA   -36.17mA
-886.4mV  -37.9mA    -62.7mA    -20.81mA
-850.9mV  -22.81mA   -43.26mA   -13.36mA
-815.5mV  -14.08mA   -27.86mA   -10.76mA
-780mV    -10.19mA   -17.27mA   -9.588mA
-709.1mV  -7.403mA   -8.006mA   -7.89mA
-460.9mV  -2.415mA   -2.158mA   -2.906mA
815.5mV   12.12mA    13.25mA    11.85mA
2.198V    18.41mA    25.05mA    19.87mA
[Power Clamp]
-1.098V   199.6mA    218.7mA    176mA
-1.027V   140.7mA    161mA      116.7mA
-956.4mV  86.1mA     107.2mA    63.04mA
-920.9mV  61.84mA    82.54mA    40.8mA
-885.5mV  41.08mA    60.22mA    24.71mA
-850mV    25.64mA    41.04mA    16.49mA
-814.5mV  16.59mA    26.03mA    13.35mA
-779.1mV  12.35mA    15.82mA    11.74mA
-708.2mV  8.76mA     6.752mA    9.25mA
-318.2mV  -353.3uA   -1.203mA   -532.7uA
1.065V    -8.626nA   -351uA     -1.093nA
2.199V    -18.55mA   -20.29mA   -16.27mA
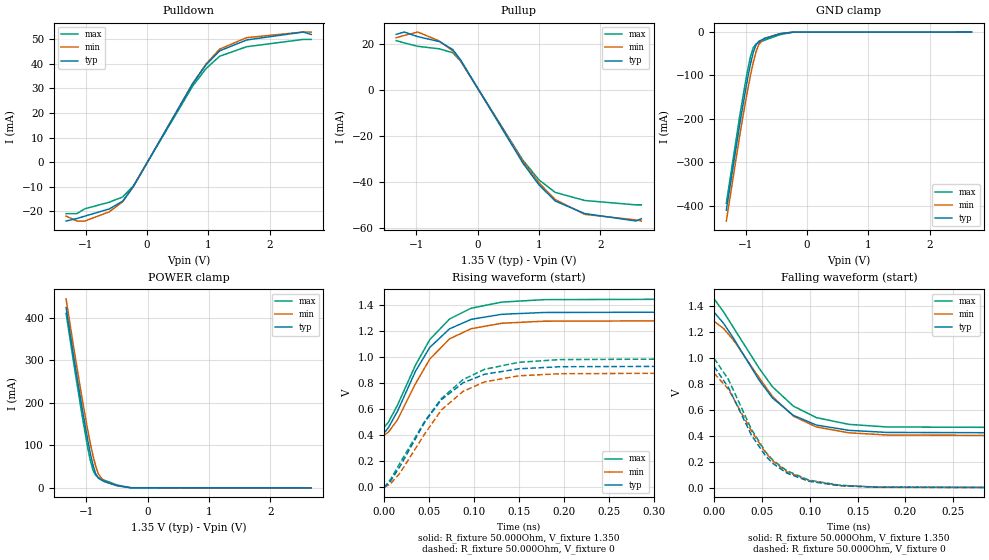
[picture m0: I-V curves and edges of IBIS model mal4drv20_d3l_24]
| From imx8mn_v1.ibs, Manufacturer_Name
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[Model] mal4drv20_d3l_24
Model_type   I/O
Polarity   Non-Inverting
Enable   Active-High
C_comp   1.688pF   1.681pF   1.696pF
C_comp_pullup   733.177fF   719.609fF   740.559fF
C_comp_pulldown 902.546fF   889.404fF   920.319fF
Vinh = 805.000mV
Vinl = 545.000mV
Vmeas = 675.000mV
Vref = 675.000mV
Rref = 50Ohms
Cref = 0pF
[Model Spec]
Vinh   805.000mV   772.000mV   855.000mV
Vinl   545.000mV   512.000mV   595.000mV
Vmeas   675.000mV   642.000mV   725.000mV
Vref   675.000mV   642.000mV   725.000mV
D_overshoot_ampl_h 0.4 NA   NA
D_overshoot_ampl_l 0.4 NA   NA
D_overshoot_area_l 110.000m NA   NA
D_overshoot_area_h 110.000m NA   NA
|[Receiver Thresholds]
|Vth = 675.000mV
|Vth_min = 642.000mV
|Vth_max = 725.000mV
|Vinh_ac = 150.000mV
|Vinh_dc = 100.000mV
|Vinl_ac = -150.000mV
|Vinl_dc = -100.000mV
|Tslew_ac = 5.000ns
|Threshold_sensitivity = 0.5
|Reference_supply Pullup_ref
[Temperature Range]   25.000   125.000   -40.000
[Voltage Range]   1.350V   1.283V   1.450V
[GND Clamp Reference]   0.00V   0.00V   0.00V
|[C Comp Corner]
|| variable   typ   min   max
|C_comp 1.696pF   1.681pF   1.688pF
|C_comp_pullup 740.559fF   719.609fF   733.177fF
|C_comp_pulldown 902.546fF   920.319fF   889.404fF
[Pulldown Reference]   0.00V   0.00V   0.00V
[POWER Clamp Reference]   1.350V   1.283V   1.450V
[Pullup Reference]   1.350V   1.283V   1.450V
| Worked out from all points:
|   slope of the pulldown table from 0 to 0.203 V, typ, clamps not added: 22.4 ohm
|   slope of the pullup table from 0 to 0.203 V, typ, clamps not added: 22 ohm
|   GND clamp passes 1 mA (typ) near -0.33 V on its own axis
|   POWER clamp passes 1 mA (typ) near -0.36 V on its own axis
|   rising waveform, R_fixture 50.000Ohm, V_fixture 1.350: 20-80 % time 46.3ps typ, 46.8ps min, 48.5ps max; typ from 0.414 V to 1.35 V
|   rising waveform, R_fixture 50.000Ohm, V_fixture 0: 20-80 % time 55.6ps typ, 56.3ps min, 62ps max; typ from -0.007 V to 0.933 V
|   falling waveform, R_fixture 50.000Ohm, V_fixture 1.350: 20-80 % time 54.2ps typ, 54.7ps min, 58.8ps max; typ from 1.35 V to 0.421 V
|   falling waveform, R_fixture 50.000Ohm, V_fixture 0: 20-80 % time 44.9ps typ, 46.6ps min, 46.1ps max; typ from 0.935 V to 0 V
[GND Clamp]
-1.318V   -410mA     -435mA     -394mA
-1.099V   -212mA     -238mA     -193mA
-1.011V   -139mA     -165mA     -119mA
-966.7mV  -104mA     -131mA     -84.77mA
-922.7mV  -73.08mA   -98.61mA   -55.67mA
-878.8mV  -47.18mA   -69.91mA   -36.06mA
-834.8mV  -29.86mA   -46.17mA   -27.79mA
-790.9mV  -21.59mA   -29.3mA    -24.32mA
-703mV    -15.41mA   -14.73mA   -19.21mA
-439.4mV  -3.973mA   -3.431mA   -5.961mA
-219.7mV  -62.42uA   -101.9uA   -153.4uA
2.68V     65.01nA    1.698uA    29.72nA
[Power Clamp]
-1.33V    424mA      444.5mA    410.3mA
-1.199V   302mA      324mA      287mA
-1.067V   186mA      208.6mA    168.5mA
-978.8mV  114mA      137.2mA    95.83mA
-934.8mV  81.28mA    104.7mA    64.68mA
-890.9mV  53.35mA    75.52mA    41.63mA
-847mV    33.16mA    50.86mA    29.5mA
-803mV    22.54mA    32.62mA    24.29mA
-715.2mV  15.14mA    15.5mA     18.5mA
-495.5mV  4.953mA    4.871mA    6.554mA
-275.8mV  132.3uA    356.2uA    190.3uA
2.668V    -205nA     -2.419uA   -83.46nA
[Pulldown]
-1.318V   -24mA      -22mA      -21mA
-1.142V   -23mA      -24mA      -21mA
-1.011V   -22mA      -24mA      -19mA
-615.2mV  -19.1mA    -20.27mA   -16.35mA
-395.5mV  -15.92mA   -16.2mA    -14.21mA
-219.7mV  -9.934mA   -9.896mA   -9.645mA
747mV     31.93mA    32.05mA    30.98mA
966.7mV   39.71mA    40.05mA    38.19mA
1.186V    45.34mA    46.03mA    43.13mA
1.626V    49.76mA    50.71mA    47.01mA
2.549V    53mA       53mA       50mA
2.68V     52mA       53mA       50mA
[Pullup]
-1.33V    24mA       22.52mA    21.28mA
-1.199V   25mA       23.52mA    20.28mA
-978.8mV  23mA       25mA       18.81mA
-627.3mV  20.87mA    21.14mA    17.71mA
-407.6mV  17.39mA    16.82mA    16.02mA
-275.8mV  12.76mA    12.33mA    12.27mA
734.8mV   -31.83mA   -31.08mA   -30.6mA
998.5mV   -41.32mA   -40.44mA   -39.15mA
1.262V    -48.31mA   -47.7mA    -44.57mA
1.746V    -53.76mA   -54.12mA   -48.1mA
2.58V     -57mA      -56.52mA   -50mA
2.668V    -56mA      -57mA      -50mA
[Ramp]
R_load=50.000Ohm
dV/dt_r   558.600mV/51.500ps  529.198mV/53.000ps  594.000mV/56.000ps
dV/dt_f   558.600mV/50.500ps  529.199mV/52.000ps  594.000mV/53.000ps
[Rising waveform]
R_fixture=50.000Ohm
V_fixture=1.350
V_fixture_min=1.283
V_fixture_max=1.450
0s        414mV      397mV      459mV
5ps       458mV      423mV      500mV
15ps      583mV      517mV      630mV
35ps      891mV      795mV      938mV
51ps      1.076V     986mV      1.136V
73ps      1.219V     1.142V     1.295V
97ps      1.292V     1.22V      1.378V
131ps     1.331V     1.262V     1.425V
178ps     1.345V     1.278V     1.444V
469ps     1.35V      1.283V     1.45V
[Rising waveform]
R_fixture=50.000Ohm
V_fixture=0
0s        -6.746mV   -2.329mV   -5.701mV
7ps       41.99mV    21.45mV    54.42mV
18ps      160mV      109mV      187mV
46ps      507mV      416mV      513mV
64ps      673mV      594mV      682mV
88ps      803mV      737mV      828mV
112ps     869mV      810mV      907mV
150ps     911mV      857mV      961mV
196ps     927mV      873mV      982mV
470ps     933mV      881mV      991mV
[Falling waveform]
R_fixture=50.000Ohm
V_fixture=1.350
V_fixture_min=1.283
V_fixture_max=1.450
0s        1.353V     1.283V     1.456V
10ps      1.267V     1.227V     1.355V
20ps      1.156V     1.141V     1.238V
47ps      831mV      850mV      923mV
61ps      693mV      704mV      779mV
83ps      558mV      552mV      629mV
107ps     484mV      469mV      541mV
141ps     443mV      424mV      489mV
181ps     427mV      407mV      469mV
469ps     421mV      400mV      461mV
[Falling waveform]
R_fixture=50.000Ohm
V_fixture=0
0s        935mV      883mV      998mV
15ps      773mV      760mV      835mV
39ps      407mV      439mV      452mV
54ps      245mV      269mV      275mV
62ps      185mV      204mV      210mV
76ps      114mV      124mV      132mV
99ps      50.66mV    55.89mV    59.98mV
131ps     16.95mV    18.34mV    20.54mV
170ps     4.502mV    5.188mV    5.701mV
469ps     11.14uV    15.9uV     12.09uV
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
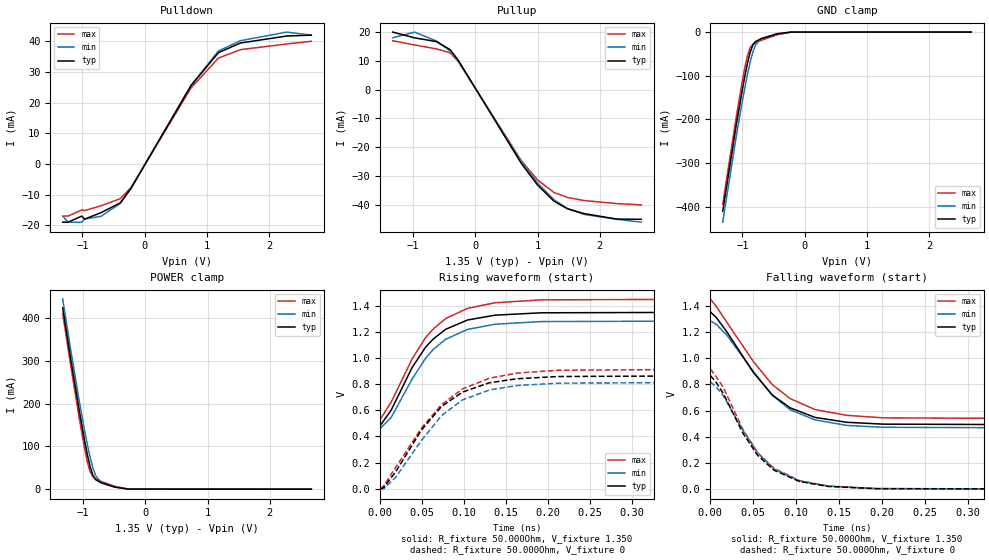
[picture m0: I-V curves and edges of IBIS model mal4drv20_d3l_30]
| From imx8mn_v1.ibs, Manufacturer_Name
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[Model] mal4drv20_d3l_30
Model_type   I/O
Polarity   Non-Inverting
Enable   Active-High
C_comp   1.688pF   1.681pF   1.696pF
C_comp_pullup   733.177fF   719.609fF   740.559fF
C_comp_pulldown 902.546fF   889.404fF   920.319fF
Vinh = 805.000mV
Vinl = 545.000mV
Vmeas = 675.000mV
Vref = 675.000mV
Rref = 50Ohms
Cref = 0pF
[Model Spec]
Vinh   805.000mV   772.000mV   855.000mV
Vinl   545.000mV   512.000mV   595.000mV
Vmeas   675.000mV   642.000mV   725.000mV
Vref   675.000mV   642.000mV   725.000mV
D_overshoot_ampl_h 0.4 NA   NA
D_overshoot_ampl_l 0.4 NA   NA
D_overshoot_area_l 110.000m NA   NA
D_overshoot_area_h 110.000m NA   NA
|[Receiver Thresholds]
|Vth = 675.000mV
|Vth_min = 642.000mV
|Vth_max = 725.000mV
|Vinh_ac = 150.000mV
|Vinh_dc = 100.000mV
|Vinl_ac = -150.000mV
|Vinl_dc = -100.000mV
|Tslew_ac = 5.000ns
|Threshold_sensitivity = 0.5
|Reference_supply Pullup_ref
[Temperature Range]   25.000   125.000   -40.000
[Voltage Range]   1.350V   1.283V   1.450V
[GND Clamp Reference]   0.00V   0.00V   0.00V
|[C Comp Corner]
|| variable   typ   min   max
|C_comp 1.696pF   1.681pF   1.688pF
|C_comp_pullup 740.559fF   719.609fF   733.177fF
|C_comp_pulldown 902.546fF   920.319fF   889.404fF
[Pulldown Reference]   0.00V   0.00V   0.00V
[POWER Clamp Reference]   1.350V   1.283V   1.450V
[Pullup Reference]   1.350V   1.283V   1.450V
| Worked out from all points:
|   slope of the pulldown table from 0 to 0.203 V, typ, clamps not added: 28 ohm
|   slope of the pullup table from 0 to 0.203 V, typ, clamps not added: 27.5 ohm
|   GND clamp passes 1 mA (typ) near -0.33 V on its own axis
|   POWER clamp passes 1 mA (typ) near -0.36 V on its own axis
|   rising waveform, R_fixture 50.000Ohm, V_fixture 1.350: 20-80 % time 51.3ps typ, 52.4ps min, 53.6ps max; typ from 0.484 V to 1.35 V
|   rising waveform, R_fixture 50.000Ohm, V_fixture 0: 20-80 % time 63ps typ, 63.6ps min, 69.9ps max; typ from -0.003 V to 0.865 V
|   falling waveform, R_fixture 50.000Ohm, V_fixture 1.350: 20-80 % time 61.2ps typ, 61.7ps min, 66.6ps max; typ from 1.35 V to 0.49 V
|   falling waveform, R_fixture 50.000Ohm, V_fixture 0: 20-80 % time 50.2ps typ, 51.5ps min, 50.8ps max; typ from 0.866 V to 0 V
[GND Clamp]
-1.318V   -410mA     -435mA     -394mA
-1.099V   -212mA     -238mA     -193mA
-1.011V   -139mA     -165mA     -119mA
-966.7mV  -104mA     -131mA     -84.77mA
-922.7mV  -73.08mA   -98.61mA   -55.67mA
-878.8mV  -47.18mA   -69.91mA   -36.06mA
-834.8mV  -29.86mA   -46.17mA   -27.79mA
-790.9mV  -21.59mA   -29.3mA    -24.32mA
-703mV    -15.41mA   -14.73mA   -19.21mA
-439.4mV  -3.973mA   -3.431mA   -5.961mA
-219.7mV  -62.42uA   -101.9uA   -153.4uA
2.68V     65.01nA    1.698uA    29.72nA
[Power Clamp]
-1.33V    424mA      444.5mA    410.3mA
-1.199V   302mA      324mA      287mA
-1.067V   186mA      208.6mA    168.5mA
-978.8mV  114mA      137.2mA    95.83mA
-934.8mV  81.28mA    104.7mA    64.68mA
-890.9mV  53.35mA    75.52mA    41.63mA
-847mV    33.16mA    50.86mA    29.5mA
-803mV    22.54mA    32.62mA    24.29mA
-715.2mV  15.14mA    15.5mA     18.5mA
-495.5mV  4.953mA    4.871mA    6.554mA
-275.8mV  132.3uA    356.2uA    190.3uA
2.668V    -205nA     -2.419uA   -83.46nA
[Pulldown]
-1.318V   -19mA      -17mA      -17mA
-1.23V    -19mA      -19mA      -17mA
-1.011V   -17mA      -19mA      -15mA
-966.7mV  -18mA      -18mA      -15.22mA
-703mV    -15.91mA   -17.08mA   -13.64mA
-395.5mV  -12.75mA   -12.97mA   -11.37mA
-219.7mV  -7.958mA   -7.927mA   -7.726mA
747mV     25.57mA    25.67mA    24.81mA
1.186V    36.29mA    36.84mA    34.52mA
1.538V    39.43mA    40.19mA    37.26mA
2.285V    41.72mA    43mA       39.13mA
2.68V     42mA       42mA       40mA
[Pullup]
-1.33V    20mA       18mA       17mA
-978.8mV  18mA       20mA       15.54mA
-627.3mV  16.7mA     16.92mA    14.17mA
-407.6mV  13.92mA    13.47mA    12.82mA
-275.8mV  10.22mA    9.875mA    9.829mA
734.8mV   -25.49mA   -24.89mA   -24.51mA
998.5mV   -33.08mA   -32.38mA   -31.34mA
1.262V    -38.67mA   -38.18mA   -35.66mA
1.482V    -41.37mA   -41.28mA   -37.43mA
1.746V    -43.01mA   -43.29mA   -38.48mA
2.273V    -44.92mA   -45mA      -39.54mA
2.668V    -45mA      -46mA      -40mA
[Ramp]
R_load=50.000Ohm
dV/dt_r   517.500mV/58.500ps  489.898mV/59.500ps  549.000mV/63.000ps
dV/dt_f   517.500mV/56.500ps  489.898mV/57.500ps  549.000mV/60.000ps
[Rising waveform]
R_fixture=50.000Ohm
V_fixture=1.350
V_fixture_min=1.283
V_fixture_max=1.450
0s        484mV      462mV      531mV
13ps      601mV      545mV      662mV
38ps      927mV      839mV      993mV
54ps      1.082V     997mV      1.156V
63ps      1.144V     1.064V     1.221V
78ps      1.219V     1.143V     1.301V
104ps     1.29V      1.218V     1.379V
137ps     1.327V     1.258V     1.422V
192ps     1.345V     1.278V     1.444V
469ps     1.35V      1.283V     1.45V
[Rising waveform]
R_fixture=50.000Ohm
V_fixture=0
0s        -3.182mV   -579.9uV   -1.632mV
4ps       9.032mV    -579.9uV   21.64mV
18ps      126mV      84.47mV    159mV
49ps      448mV      369mV      463mV
73ps      629mV      559mV      643mV
98ps      739mV      679mV      763mV
130ps     810mV      755mV      845mV
163ps     841mV      789mV      884mV
212ps     858mV      807mV      906mV
471ps     865mV      815mV      916mV
[Falling waveform]
R_fixture=50.000Ohm
V_fixture=1.350
V_fixture_min=1.283
V_fixture_max=1.450
0s        1.353V     1.284V     1.45V
7ps       1.309V     1.257V     1.394V
19ps      1.203V     1.177V     1.276V
50ps      891mV      899mV      974mV
72ps      719mV      716mV      798mV
93ps      620mV      605mV      690mV
122ps     547mV      528mV      607mV
159ps     510mV      486mV      563mV
201ps     496mV      472mV      544mV
469ps     490mV      465mV      536mV
[Falling waveform]
R_fixture=50.000Ohm
V_fixture=0
0s        866mV      818mV      917mV
6ps       823mV      786mV      867mV
15ps      731mV      714mV      777mV
38ps      427mV      449mV      455mV
55ps      259mV      277mV      279mV
74ps      145mV      155mV      159mV
104ps     57.99mV    61.08mV    64.62mV
137ps     21.01mV    22.63mV    24.1mV
193ps     3.852mV    4.085mV    4.565mV
469ps     12.94uV    18.33uV    13.83uV
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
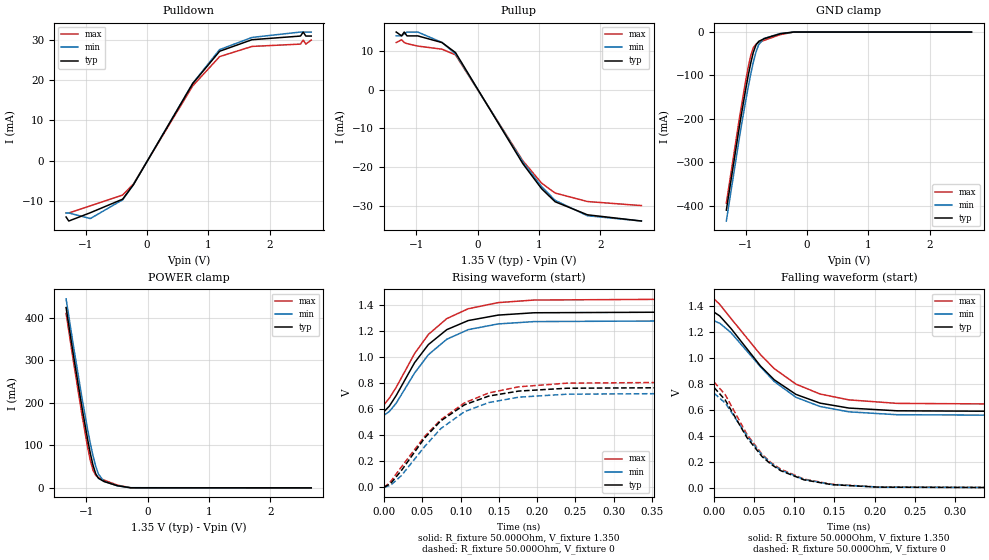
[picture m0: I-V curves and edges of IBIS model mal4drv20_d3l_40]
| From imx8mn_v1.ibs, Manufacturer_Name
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[Model] mal4drv20_d3l_40
Model_type   I/O
Polarity   Non-Inverting
Enable   Active-High
C_comp   1.688pF   1.681pF   1.696pF
C_comp_pullup   733.177fF   719.609fF   740.559fF
C_comp_pulldown 902.546fF   889.404fF   920.319fF
Vinh = 805.000mV
Vinl = 545.000mV
Vmeas = 675.000mV
Vref = 675.000mV
Rref = 50Ohms
Cref = 0pF
[Model Spec]
Vinh   805.000mV   772.000mV   855.000mV
Vinl   545.000mV   512.000mV   595.000mV
Vmeas   675.000mV   642.000mV   725.000mV
Vref   675.000mV   642.000mV   725.000mV
D_overshoot_ampl_h 0.4 NA   NA
D_overshoot_ampl_l 0.4 NA   NA
D_overshoot_area_l 110.000m NA   NA
D_overshoot_area_h 110.000m NA   NA
|[Receiver Thresholds]
|Vth = 675.000mV
|Vth_min = 642.000mV
|Vth_max = 725.000mV
|Vinh_ac = 150.000mV
|Vinh_dc = 100.000mV
|Vinl_ac = -150.000mV
|Vinl_dc = -100.000mV
|Tslew_ac = 5.000ns
|Threshold_sensitivity = 0.5
|Reference_supply Pullup_ref
[Temperature Range]   25.000   125.000   -40.000
[Voltage Range]   1.350V   1.283V   1.450V
[GND Clamp Reference]   0.00V   0.00V   0.00V
|[C Comp Corner]
|| variable   typ   min   max
|C_comp 1.696pF   1.681pF   1.688pF
|C_comp_pullup 740.559fF   719.609fF   733.177fF
|C_comp_pulldown 902.546fF   920.319fF   889.404fF
[Pulldown Reference]   0.00V   0.00V   0.00V
[POWER Clamp Reference]   1.350V   1.283V   1.450V
[Pullup Reference]   1.350V   1.283V   1.450V
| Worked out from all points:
|   slope of the pulldown table from 0 to 0.203 V, typ, clamps not added: 37.3 ohm
|   slope of the pullup table from 0 to 0.203 V, typ, clamps not added: 36.6 ohm
|   GND clamp passes 1 mA (typ) near -0.33 V on its own axis
|   POWER clamp passes 1 mA (typ) near -0.36 V on its own axis
|   rising waveform, R_fixture 50.000Ohm, V_fixture 1.350: 20-80 % time 58.8ps typ, 59.9ps min, 60.5ps max; typ from 0.581 V to 1.35 V
|   rising waveform, R_fixture 50.000Ohm, V_fixture 0: 20-80 % time 73ps typ, 73.6ps min, 81.6ps max; typ from -0.001 V to 0.769 V
|   falling waveform, R_fixture 50.000Ohm, V_fixture 1.350: 20-80 % time 71.5ps typ, 71.1ps min, 77.8ps max; typ from 1.35 V to 0.585 V
|   falling waveform, R_fixture 50.000Ohm, V_fixture 0: 20-80 % time 57.2ps typ, 58.6ps min, 57.7ps max; typ from 0.771 V to 0 V
[GND Clamp]
-1.318V   -410mA     -435mA     -394mA
-1.099V   -212mA     -238mA     -193mA
-1.011V   -139mA     -165mA     -119mA
-966.7mV  -104mA     -131mA     -84.77mA
-922.7mV  -73.08mA   -98.61mA   -55.67mA
-878.8mV  -47.18mA   -69.91mA   -36.06mA
-834.8mV  -29.86mA   -46.17mA   -27.79mA
-790.9mV  -21.59mA   -29.3mA    -24.32mA
-703mV    -15.41mA   -14.73mA   -19.21mA
-439.4mV  -3.973mA   -3.431mA   -5.961mA
-219.7mV  -62.42uA   -101.9uA   -153.4uA
2.68V     65.01nA    1.698uA    29.72nA
[Power Clamp]
-1.33V    424mA      444.5mA    410.3mA
-1.199V   302mA      324mA      287mA
-1.067V   186mA      208.6mA    168.5mA
-978.8mV  114mA      137.2mA    95.83mA
-934.8mV  81.28mA    104.7mA    64.68mA
-890.9mV  53.35mA    75.52mA    41.63mA
-847mV    33.16mA    50.86mA    29.5mA
-803mV    22.54mA    32.62mA    24.29mA
-715.2mV  15.14mA    15.5mA     18.5mA
-495.5mV  4.953mA    4.871mA    6.554mA
-275.8mV  132.3uA    356.2uA    190.3uA
2.668V    -205nA     -2.419uA   -83.46nA
[Pulldown]
-1.318V   -14mA      -13mA      -13mA
-1.274V   -15mA      -13mA      -13mA
-922.7mV  -12.94mA   -14.39mA   -11.23mA
-395.5mV  -9.567mA   -9.725mA   -8.534mA
-219.7mV  -5.969mA   -5.946mA   -5.795mA
747mV     19.18mA    19.25mA    18.61mA
1.186V    27.22mA    27.63mA    25.89mA
1.714V    30.09mA    30.66mA    28.42mA
2.505V    31mA       32mA       29mA
2.549V    32mA       32mA       30mA
2.592V    31mA       32mA       29mA
2.68V     31mA       32mA       30mA
[Pullup]
-1.33V    15mA       14mA       12.28mA
-1.242V   14mA       14mA       13mA
-1.199V   15mA       14.52mA    12.28mA
-1.155V   14mA       15mA       12mA
-978.8mV  14mA       15mA       11.36mA
-583.3mV  12.27mA    12.3mA     10.55mA
-363.6mV  9.689mA    9.323mA    9.086mA
734.8mV   -19.12mA   -18.67mA   -18.38mA
1.042V    -25.64mA   -25.11mA   -24.2mA
1.262V    -29.01mA   -28.64mA   -26.75mA
1.789V    -32.39mA   -32.64mA   -28.95mA
2.668V    -34mA      -34mA      -30mA
[Ramp]
R_load=50.000Ohm
dV/dt_r   460.200mV/66.500ps  435.598mV/67.500ps  486.300mV/71.500ps
dV/dt_f   460.200mV/66.000ps  435.598mV/66.000ps  486.300mV/68.500ps
[Rising waveform]
R_fixture=50.000Ohm
V_fixture=1.350
V_fixture_min=1.283
V_fixture_max=1.450
0s        581mV      554mV      635mV
7ps       624mV      582mV      685mV
16ps      706mV      647mV      769mV
40ps      959mV      879mV      1.029V
58ps      1.098V     1.02V      1.176V
82ps      1.213V     1.139V     1.298V
110ps     1.283V     1.213V     1.374V
149ps     1.325V     1.257V     1.421V
196ps     1.343V     1.275V     1.441V
469ps     1.35V      1.283V     1.45V
[Rising waveform]
R_fixture=50.000Ohm
V_fixture=0
0s        -1.252mV   -2.589mV   -5.137mV
9ps       30.35mV    15.92mV    45.69mV
23ps      130mV      90.62mV    158mV
53ps      378mV      312mV      390mV
74ps      510mV      450mV      519mV
105ps     634mV      581mV      649mV
137ps     702mV      652mV      726mV
176ps     740mV      693mV      773mV
239ps     762mV      716mV      801mV
472ps     769mV      724mV      811mV
[Falling waveform]
R_fixture=50.000Ohm
V_fixture=1.350
V_fixture_min=1.283
V_fixture_max=1.450
0s        1.35V      1.283V     1.452V
7ps       1.321V     1.265V     1.41V
21ps      1.225V     1.193V     1.302V
58ps      935mV      929mV      1.022V
75ps      830mV      817mV      916mV
102ps     718mV      696mV      797mV
132ps     651mV      625mV      721mV
168ps     613mV      584mV      676mV
228ps     592mV      562mV      649mV
470ps     585mV      555mV      640mV
[Falling waveform]
R_fixture=50.000Ohm
V_fixture=0
0s        771mV      727mV      813mV
14ps      674mV      651mV      715mV
41ps      386mV      400mV      410mV
60ps      239mV      250mV      256mV
71ps      181mV      189mV      194mV
83ps      132mV      137mV      144mV
112ps     61.58mV    64.65mV    67.61mV
147ps     24.37mV    25.23mV    27.73mV
205ps     5.292mV    5.542mV    6.124mV
469ps     17.44uV    23.53uV    18.97uV
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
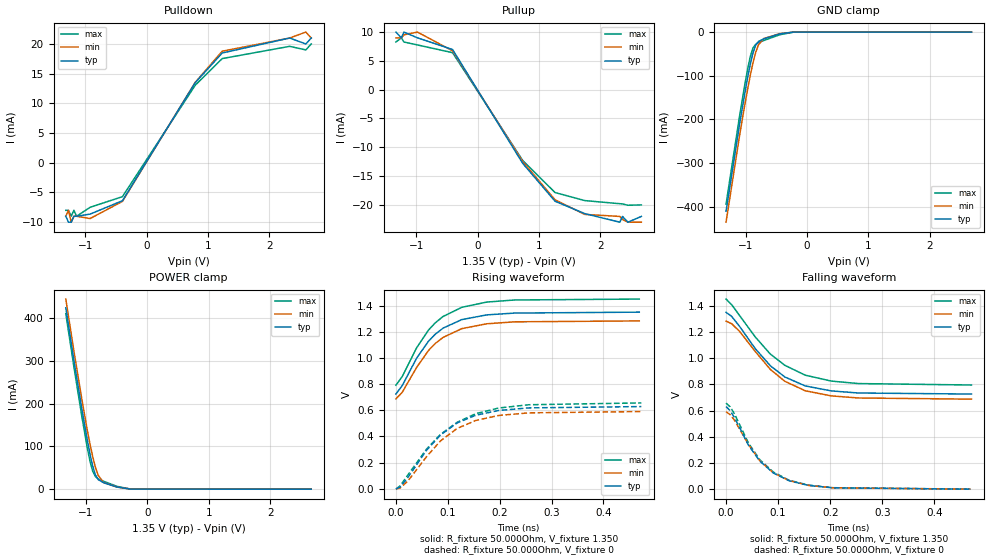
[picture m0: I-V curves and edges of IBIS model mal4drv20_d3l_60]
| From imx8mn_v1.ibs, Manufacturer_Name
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[Model] mal4drv20_d3l_60
Model_type   I/O
Polarity   Non-Inverting
Enable   Active-High
C_comp   1.688pF   1.681pF   1.696pF
C_comp_pullup   733.177fF   719.609fF   740.559fF
C_comp_pulldown 902.546fF   889.404fF   920.319fF
Vinh = 805.000mV
Vinl = 545.000mV
Vmeas = 675.000mV
Vref = 675.000mV
Rref = 50Ohms
Cref = 0pF
[Model Spec]
Vinh   805.000mV   772.000mV   855.000mV
Vinl   545.000mV   512.000mV   595.000mV
Vmeas   675.000mV   642.000mV   725.000mV
Vref   675.000mV   642.000mV   725.000mV
D_overshoot_ampl_h 0.4 NA   NA
D_overshoot_ampl_l 0.4 NA   NA
D_overshoot_area_l 110.000m NA   NA
D_overshoot_area_h 110.000m NA   NA
|[Receiver Thresholds]
|Vth = 675.000mV
|Vth_min = 642.000mV
|Vth_max = 725.000mV
|Vinh_ac = 150.000mV
|Vinh_dc = 100.000mV
|Vinl_ac = -150.000mV
|Vinl_dc = -100.000mV
|Tslew_ac = 5.000ns
|Threshold_sensitivity = 0.5
|Reference_supply Pullup_ref
[Temperature Range]   25.000   125.000   -40.000
[Voltage Range]   1.350V   1.283V   1.450V
[GND Clamp Reference]   0.00V   0.00V   0.00V
|[C Comp Corner]
|| variable   typ   min   max
|C_comp 1.696pF   1.681pF   1.688pF
|C_comp_pullup 740.559fF   719.609fF   733.177fF
|C_comp_pulldown 902.546fF   920.319fF   889.404fF
[Pulldown Reference]   0.00V   0.00V   0.00V
[POWER Clamp Reference]   1.350V   1.283V   1.450V
[Pullup Reference]   1.350V   1.283V   1.450V
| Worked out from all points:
|   slope of the pulldown table from 0 to 0.203 V, typ, clamps not added: 55.8 ohm
|   slope of the pullup table from 0 to 0.203 V, typ, clamps not added: 54.8 ohm
|   GND clamp passes 1 mA (typ) near -0.33 V on its own axis
|   POWER clamp passes 1 mA (typ) near -0.36 V on its own axis
|   rising waveform, R_fixture 50.000Ohm, V_fixture 1.350: 20-80 % time 69.6ps typ, 70.9ps min, 71ps max; typ from 0.724 V to 1.35 V
|   rising waveform, R_fixture 50.000Ohm, V_fixture 0: 20-80 % time 87.6ps typ, 88.2ps min, 98.1ps max; typ from -0.001 V to 0.628 V
|   falling waveform, R_fixture 50.000Ohm, V_fixture 1.350: 20-80 % time 86ps typ, 85.5ps min, 93.5ps max; typ from 1.35 V to 0.726 V
|   falling waveform, R_fixture 50.000Ohm, V_fixture 0: 20-80 % time 68.1ps typ, 69.1ps min, 68.6ps max; typ from 0.631 V to 0 V
[GND Clamp]
-1.318V   -410mA     -435mA     -394mA
-1.099V   -212mA     -238mA     -193mA
-1.011V   -139mA     -165mA     -119mA
-966.7mV  -104mA     -131mA     -84.77mA
-922.7mV  -73.08mA   -98.61mA   -55.67mA
-878.8mV  -47.18mA   -69.91mA   -36.06mA
-834.8mV  -29.86mA   -46.17mA   -27.79mA
-790.9mV  -21.59mA   -29.3mA    -24.32mA
-703mV    -15.41mA   -14.73mA   -19.21mA
-439.4mV  -3.973mA   -3.431mA   -5.961mA
-219.7mV  -62.42uA   -101.9uA   -153.4uA
2.68V     65.01nA    1.698uA    29.72nA
[Power Clamp]
-1.33V    424mA      444.5mA    410.3mA
-1.199V   302mA      324mA      287mA
-1.067V   186mA      208.6mA    168.5mA
-978.8mV  114mA      137.2mA    95.83mA
-934.8mV  81.28mA    104.7mA    64.68mA
-890.9mV  53.35mA    75.52mA    41.63mA
-847mV    33.16mA    50.86mA    29.5mA
-803mV    22.54mA    32.62mA    24.29mA
-715.2mV  15.14mA    15.5mA     18.5mA
-495.5mV  4.953mA    4.871mA    6.554mA
-275.8mV  132.3uA    356.2uA    190.3uA
2.668V    -205nA     -2.419uA   -83.46nA
[Pulldown]
-1.318V   -9mA       -9mA       -8mA
-1.274V   -10mA      -8mA       -8mA
-1.23V    -10mA      -10mA      -9mA
-1.186V   -9mA       -9mA       -8mA
-1.142V   -9mA       -9mA       -9mA
-922.7mV  -8.64mA    -9.39mA    -7.5mA
-395.5mV  -6.388mA   -6.499mA   -5.7mA
790.9mV   13.49mA    13.55mA    13.06mA
1.23V     18.48mA    18.78mA    17.54mA
2.329V    21mA       21mA       19.6mA
2.592V    20mA       22mA       19mA
2.68V     21mA       21mA       20mA
[Pullup]
-1.33V    10mA       9mA        8.276mA
-1.242V   9mA        9mA        9mA
-1.199V   10mA       9.524mA    8.276mA
-978.8mV  9mA        10mA       7.768mA
-407.6mV  6.975mA    6.749mA    6.426mA
734.8mV   -12.78mA   -12.47mA   -12.28mA
1.262V    -19.36mA   -19.11mA   -17.85mA
1.746V    -21.51mA   -21.65mA   -19.25mA
2.317V    -23mA      -22mA      -19.79mA
2.361V    -22mA      -22.52mA   -19.83mA
2.449V    -23mA      -23mA      -20.06mA
2.668V    -22mA      -23mA      -20mA
[Ramp]
R_load=50.000Ohm
dV/dt_r   375.600mV/79.500ps  356.097mV/80.500ps  393.600mV/85.500ps
dV/dt_f   375.600mV/78.000ps  356.098mV/78.000ps  393.600mV/81.500ps
[Rising waveform]
R_fixture=50.000Ohm
V_fixture=1.350
V_fixture_min=1.283
V_fixture_max=1.450
0s        724mV      687mV      791mV
12ps      787mV      736mV      857mV
40ps      999mV      928mV      1.078V
63ps      1.129V     1.058V     1.214V
76ps      1.182V     1.111V     1.269V
91ps      1.228V     1.157V     1.317V
127ps     1.293V     1.224V     1.387V
175ps     1.329V     1.261V     1.427V
229ps     1.343V     1.276V     1.443V
469ps     1.35V      1.283V     1.45V
[Rising waveform]
R_fixture=50.000Ohm
V_fixture=0
0s        -1.027mV   -1.79mV    -3.423mV
8ps       12.73mV    5.149mV    21.92mV
23ps      85.36mV    58.57mV    105mV
59ps      294mV      245mV      303mV
86ps      411mV      366mV      416mV
118ps     503mV      461mV      508mV
154ps     562mV      522mV      574mV
198ps     598mV      560mV      617mV
256ps     618mV      580mV      642mV
473ps     628mV      590mV      656mV
[Falling waveform]
R_fixture=50.000Ohm
V_fixture=1.350
V_fixture_min=1.283
V_fixture_max=1.450
0s        1.35V      1.283V     1.451V
11ps      1.318V     1.262V     1.407V
26ps      1.242V     1.204V     1.325V
56ps      1.073V     1.051V     1.162V
85ps      942mV      914mV      1.031V
113ps     856mV      823mV      945mV
152ps     788mV      751mV      870mV
202ps     750mV      712mV      825mV
254ps     734mV      696mV      806mV
471ps     726mV      687mV      795mV
[Falling waveform]
R_fixture=50.000Ohm
V_fixture=0
0s        631mV      591mV      657mV
8ps       598mV      568mV      628mV
16ps      548mV      527mV      576mV
43ps      336mV      341mV      352mV
65ps      213mV      216mV      224mV
91ps      123mV      124mV      130mV
121ps     64.26mV    65.53mV    68.33mV
158ps     28.7mV     28.92mV    31.17mV
205ps     10.25mV    10.42mV    11.26mV
469ps     31.1uV     50.6uV     43.61uV
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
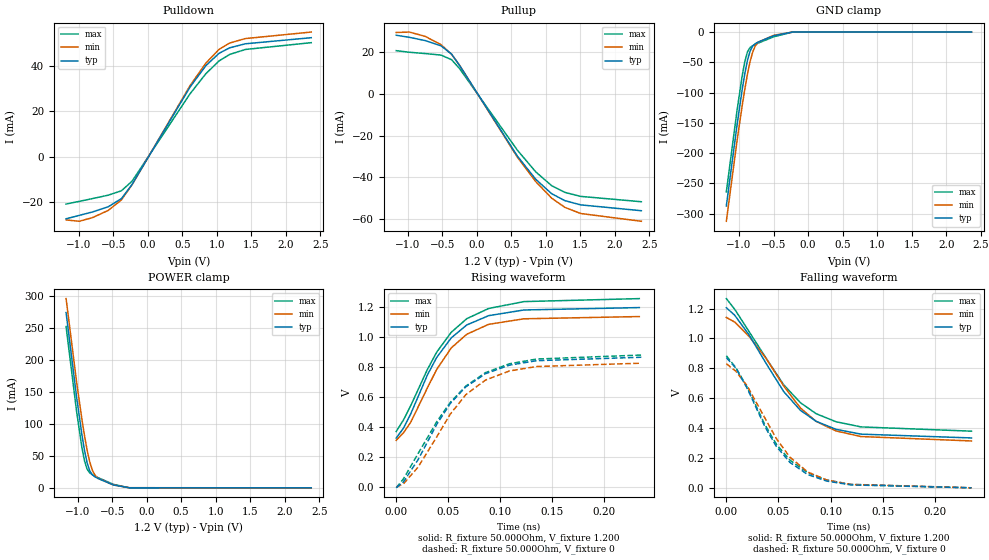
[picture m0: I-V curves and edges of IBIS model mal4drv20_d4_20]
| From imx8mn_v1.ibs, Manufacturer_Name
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[Model] mal4drv20_d4_20
Model_type   I/O
Polarity   Non-Inverting
Enable   Active-High
C_comp   1.691pF   1.683pF   1.699pF
C_comp_pullup   737.671fF   724.063fF   743.649fF
C_comp_pulldown 903.204fF   890.383fF   921.747fF
Vinh = 829.000mV
Vinl = 714.000mV
Vmeas = 771.000mV
Vref = 771.000mV
Rref = 50Ohms
Cref = 0pF
[Model Spec]
Vinh   829.000mV   790.000mV   868.000mV
Vinl   714.000mV   675.000mV   753.000mV
Vmeas   771.000mV   733.000mV   810.000mV
Vref   771.000mV   733.000mV   810.000mV
D_overshoot_ampl_h 0.24 NA   NA
D_overshoot_ampl_l 0.24 NA   NA
D_overshoot_area_l 300.000m NA   NA
D_overshoot_area_h 300.000m NA   NA
|[Receiver Thresholds]
|Vth = 771.000mV
|Vth_min = 733.000mV
|Vth_max = 810.000mV
|Vinh_ac = 68.000mV
|Vinh_dc = 68.000mV
|Vinl_ac = -68.000mV
|Vinl_dc = -68.000mV
|Tslew_ac = 5.000ns
|Threshold_sensitivity = 0.5
|Reference_supply Pullup_ref
[Temperature Range]   25.000   125.000   -40.000
[Voltage Range]   1.200V   1.140V   1.260V
[GND Clamp Reference]   0.00V   0.00V   0.00V
|[C Comp Corner]
|| variable   typ   min   max
|C_comp 1.699pF   1.683pF   1.691pF
|C_comp_pullup 743.649fF   724.063fF   737.671fF
|C_comp_pulldown 903.204fF   921.747fF   890.383fF
[Pulldown Reference]   0.00V   0.00V   0.00V
[POWER Clamp Reference]   1.200V   1.140V   1.260V
[Pullup Reference]   1.200V   1.140V   1.260V
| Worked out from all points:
|   slope of the pulldown table from 0 to 0.18 V, typ, clamps not added: 19 ohm
|   slope of the pullup table from 0 to 0.18 V, typ, clamps not added: 18.8 ohm
|   GND clamp passes 1 mA (typ) near -0.33 V on its own axis
|   POWER clamp passes 1 mA (typ) near -0.36 V on its own axis
|   rising waveform, R_fixture 50.000Ohm, V_fixture 1.200: 20-80 % time 42.4ps typ, 41.7ps min, 45.6ps max; typ from 0.326 V to 1.2 V
|   rising waveform, R_fixture 50.000Ohm, V_fixture 0: 20-80 % time 51.1ps typ, 50.1ps min, 55.6ps max; typ from -0.006 V to 0.867 V
|   falling waveform, R_fixture 50.000Ohm, V_fixture 1.200: 20-80 % time 51.6ps typ, 53.2ps min, 55.5ps max; typ from 1.21 V to 0.334 V
|   falling waveform, R_fixture 50.000Ohm, V_fixture 0: 20-80 % time 42.6ps typ, 44.8ps min, 44.9ps max; typ from 0.872 V to 0 V
[GND Clamp]
-1.184V   -287.4mA   -312.7mA   -264.2mA
-1.031V   -155.3mA   -181.5mA   -131.2mA
-954.6mV  -95.39mA   -121.7mA   -72.46mA
-916.4mV  -69mA      -94.39mA   -48.75mA
-878.2mV  -46.95mA   -69.72mA   -32.79mA
-840mV    -31.44mA   -48.8mA    -25.56mA
-801.8mV  -23.08mA   -32.94mA   -22.5mA
-763.6mV  -19.1mA    -22.7mA    -20.38mA
-725.5mV  -16.66mA   -16.96mA   -18.44mA
-496.4mV  -6.091mA   -5.301mA   -7.811mA
-229.1mV  -85.34uA   -131.6uA   -211.4uA
2.367V    74.27nA    1.057uA    27.11nA
[Power Clamp]
-1.167V   274.5mA    296.4mA    252.6mA
-1.015V   142.4mA    166mA      119.9mA
-938.2mV  83.72mA    107.6mA    63.18mA
-900mV    58.71mA    81.52mA    42.14mA
-861.8mV  39mA       58.71mA    29.24mA
-823.6mV  26.53mA    40.39mA    23.35mA
-785.5mV  20.35mA    27.47mA    20.48mA
-747.3mV  17.16mA    19.6mA     18.3mA
-709.1mV  14.88mA    15.15mA    16.26mA
-480mV    4.411mA    4.49mA     5.397mA
-250.9mV  59.97uA    214.6uA    73.54uA
2.384V    -51.61nA   -1.045uA   -11.93nA
[Pulldown]
-1.184V   -27.4mA    -27.9mA    -20.9mA
-992.7mV  -25.9mA    -28.5mA    -19.7mA
-801.8mV  -24.38mA   -26.89mA   -18.48mA
-572.7mV  -22.07mA   -23.69mA   -16.96mA
-381.8mV  -18.48mA   -19.04mA   -15.02mA
-229.1mV  -12.26mA   -12.4mA    -10.82mA
610.9mV   30.77mA    31.39mA    27.8mA
840mV     40.23mA    41.35mA    36.68mA
1.031V    45.69mA    47.43mA    42.32mA
1.184V    48.12mA    50.23mA    45.19mA
1.413V    49.91mA    52.22mA    47.41mA
2.367V    52.6mA     55.1mA     50.4mA
[Pullup]
-1.167V   28.1mA     29.41mA    20.71mA
-976.4mV  27.1mA     29.63mA    19.95mA
-747.3mV  25.54mA    27.55mA    19.32mA
-518.2mV  23.02mA    23.59mA    18.59mA
-365.4mV  19.07mA    18.98mA    16.38mA
-250.9mV  13.71mA    13.76mA    12.18mA
589.1mV   -29.88mA   -30.39mA   -27.04mA
856.4mV   -41.02mA   -42.12mA   -37.45mA
1.085V    -47.86mA   -50mA      -44.02mA
1.276V    -51.17mA   -54.39mA   -47.21mA
1.505V    -53.2mA    -57.34mA   -49.13mA
2.384V    -56mA      -61.06mA   -51.7mA
[Ramp]
R_load=50.000Ohm
dV/dt_r   520.590mV/47.500ps  496.889mV/47.000ps  529.620mV/51.500ps
dV/dt_f   520.590mV/48.000ps  496.889mV/50.000ps  529.620mV/51.000ps
[Rising waveform]
R_fixture=50.000Ohm
V_fixture=1.200
V_fixture_min=1.140
V_fixture_max=1.260
0s        326.3mV    311.2mV    370.4mV
7ps       392.9mV    361.4mV    447.6mV
14ps      488.6mV    432.2mV    543.6mV
30ps      748mV      661.7mV    784.9mV
39ps      865.7mV    785.9mV    901.2mV
53ps      996.7mV    929.3mV    1.034V
68ps      1.083V     1.021V     1.125V
89ps      1.145V     1.087V     1.193V
123ps     1.183V     1.124V     1.239V
234ps     1.199V     1.139V     1.259V
[Rising waveform]
R_fixture=50.000Ohm
V_fixture=0
0s        -5.895mV   -2.336mV   -6.391mV
7ps       33.44mV    20.75mV    53.93mV
21ps      181.3mV    131.6mV    221.8mV
39ps      417.7mV    334.2mV    435.5mV
52ps      557.2mV    486.1mV    564.3mV
67ps      669mV      616.6mV    673.9mV
86ps      757.3mV    714.6mV    764.1mV
109ps     814.1mV    775.1mV    823.2mV
135ps     843.9mV    804.7mV    854.7mV
236ps     866.9mV    827.2mV    881.7mV
[Falling waveform]
R_fixture=50.000Ohm
V_fixture=1.200
V_fixture_min=1.140
V_fixture_max=1.260
0s        1.206V     1.141V     1.267V
8ps       1.156V     1.11V      1.196V
22ps      1.022V     1.012V     1.044V
38ps      834.6mV    867.5mV    869.7mV
55ps      644.6mV    682.1mV    690mV
71ps      519.2mV    534.9mV    570.3mV
86ps      446.1mV    445.6mV    497.1mV
105ps     392.4mV    381.5mV    443.1mV
129ps     359.8mV    343.7mV    408.3mV
235ps     334.4mV    314.3mV    379.7mV
[Falling waveform]
R_fixture=50.000Ohm
V_fixture=0
0s        871.8mV    831mV      884.4mV
9ps       803.4mV    781.5mV    806.1mV
20ps      666.3mV    682.3mV    674mV
37ps      409.5mV    467.3mV    422.3mV
48ps      276.9mV    329.4mV    292.2mV
61ps      170.6mV    205.3mV    185.4mV
78ps      89.34mV    106.6mV    101.7mV
96ps      46.21mV    53.38mV    53.26mV
119ps     20.14mV    22.83mV    23.99mV
235ps     460.4uV    722uV      560.9uV
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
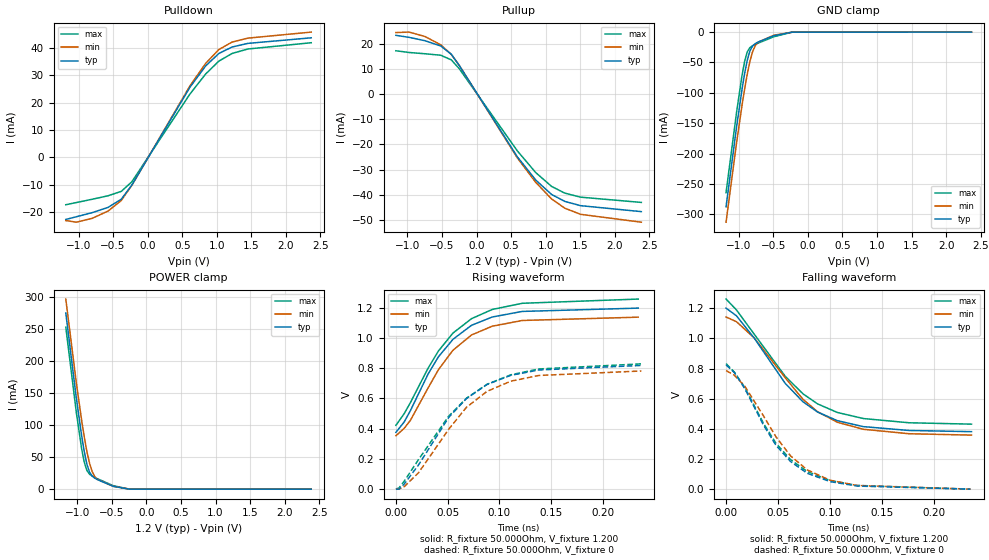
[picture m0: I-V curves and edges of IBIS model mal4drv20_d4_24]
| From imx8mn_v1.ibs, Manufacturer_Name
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[Model] mal4drv20_d4_24
Model_type   I/O
Polarity   Non-Inverting
Enable   Active-High
C_comp   1.691pF   1.683pF   1.699pF
C_comp_pullup   737.671fF   724.063fF   743.649fF
C_comp_pulldown 903.204fF   890.383fF   921.747fF
Vinh = 852.000mV
Vinl = 737.000mV
Vmeas = 795.000mV
Vref = 795.000mV
Rref = 50Ohms
Cref = 0pF
[Model Spec]
Vinh   852.000mV   812.000mV   892.000mV
Vinl   737.000mV   697.000mV   777.000mV
Vmeas   795.000mV   755.000mV   834.000mV
Vref   795.000mV   755.000mV   834.000mV
D_overshoot_ampl_h 0.24 NA   NA
D_overshoot_ampl_l 0.24 NA   NA
D_overshoot_area_l 300.000m NA   NA
D_overshoot_area_h 300.000m NA   NA
|[Receiver Thresholds]
|Vth = 795.000mV
|Vth_min = 755.000mV
|Vth_max = 834.000mV
|Vinh_ac = 68.000mV
|Vinh_dc = 68.000mV
|Vinl_ac = -68.000mV
|Vinl_dc = -68.000mV
|Tslew_ac = 5.000ns
|Threshold_sensitivity = 0.5
|Reference_supply Pullup_ref
[Temperature Range]   25.000   125.000   -40.000
[Voltage Range]   1.200V   1.140V   1.260V
[GND Clamp Reference]   0.00V   0.00V   0.00V
|[C Comp Corner]
|| variable   typ   min   max
|C_comp 1.699pF   1.683pF   1.691pF
|C_comp_pullup 743.649fF   724.063fF   737.671fF
|C_comp_pulldown 903.204fF   921.747fF   890.383fF
[Pulldown Reference]   0.00V   0.00V   0.00V
[POWER Clamp Reference]   1.200V   1.140V   1.260V
[Pullup Reference]   1.200V   1.140V   1.260V
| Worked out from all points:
|   slope of the pulldown table from 0 to 0.18 V, typ, clamps not added: 22.8 ohm
|   slope of the pullup table from 0 to 0.18 V, typ, clamps not added: 22.6 ohm
|   GND clamp passes 1 mA (typ) near -0.33 V on its own axis
|   POWER clamp passes 1 mA (typ) near -0.36 V on its own axis
|   rising waveform, R_fixture 50.000Ohm, V_fixture 1.200: 20-80 % time 46.5ps typ, 46.1ps min, 49.7ps max; typ from 0.376 V to 1.2 V
|   rising waveform, R_fixture 50.000Ohm, V_fixture 0: 20-80 % time 56.8ps typ, 55.5ps min, 61.2ps max; typ from -0.002 V to 0.819 V
|   falling waveform, R_fixture 50.000Ohm, V_fixture 1.200: 20-80 % time 56.9ps typ, 58.2ps min, 60.9ps max; typ from 1.2 V to 0.382 V
|   falling waveform, R_fixture 50.000Ohm, V_fixture 0: 20-80 % time 46.6ps typ, 48.4ps min, 48.6ps max; typ from 0.825 V to 0.001 V
[GND Clamp]
-1.184V   -287.4mA   -312.7mA   -264.2mA
-1.031V   -155.3mA   -181.5mA   -131.2mA
-954.6mV  -95.39mA   -121.7mA   -72.46mA
-916.4mV  -69mA      -94.39mA   -48.75mA
-878.2mV  -46.95mA   -69.72mA   -32.79mA
-840mV    -31.44mA   -48.8mA    -25.56mA
-801.8mV  -23.08mA   -32.94mA   -22.5mA
-763.6mV  -19.1mA    -22.7mA    -20.38mA
-725.5mV  -16.66mA   -16.96mA   -18.44mA
-496.4mV  -6.091mA   -5.301mA   -7.811mA
-229.1mV  -85.34uA   -131.6uA   -211.4uA
2.367V    74.27nA    1.057uA    27.11nA
[Power Clamp]
-1.167V   274.5mA    296.4mA    252.6mA
-1.015V   142.4mA    166mA      119.9mA
-938.2mV  83.72mA    107.6mA    63.18mA
-900mV    58.71mA    81.52mA    42.14mA
-861.8mV  39mA       58.71mA    29.24mA
-823.6mV  26.53mA    40.39mA    23.35mA
-785.5mV  20.35mA    27.47mA    20.48mA
-747.3mV  17.16mA    19.6mA     18.3mA
-709.1mV  14.88mA    15.15mA    16.26mA
-480mV    4.411mA    4.49mA     5.397mA
-250.9mV  59.97uA    214.6uA    73.54uA
2.384V    -51.61nA   -1.045uA   -11.93nA
[Pulldown]
-1.184V   -22.8mA    -23.2mA    -17.4mA
-1.031V   -21.8mA    -23.8mA    -16.6mA
-801.8mV  -20.3mA    -22.38mA   -15.39mA
-572.7mV  -18.38mA   -19.72mA   -14.12mA
-381.8mV  -15.39mA   -15.86mA   -12.51mA
-229.1mV  -10.21mA   -10.32mA   -9.009mA
610.9mV   25.63mA    26.14mA    23.15mA
840mV     33.51mA    34.44mA    30.55mA
1.031V    38.06mA    39.51mA    35.26mA
1.222V    40.43mA    42.24mA    38.07mA
1.451V    41.76mA    43.69mA    39.7mA
2.367V    43.8mA     45.9mA     42mA
[Pullup]
-1.167V   23.4mA     24.51mA    17.26mA
-976.4mV  22.6mA     24.69mA    16.58mA
-747.3mV  21.26mA    22.94mA    16.08mA
-518.2mV  19.16mA    19.63mA    15.48mA
-365.4mV  15.88mA    15.8mA     13.64mA
-250.9mV  11.42mA    11.46mA    10.14mA
589.1mV   -24.88mA   -25.31mA   -22.52mA
856.4mV   -34.16mA   -35.08mA   -31.19mA
1.085V    -39.87mA   -41.65mA   -36.67mA
1.276V    -42.63mA   -45.32mA   -39.34mA
1.505V    -44.33mA   -47.78mA   -40.95mA
2.384V    -46.7mA    -50.9mA    -43.04mA
[Ramp]
R_load=50.000Ohm
dV/dt_r   492.450mV/53.000ps  470.458mV/52.000ps  498.810mV/56.500ps
dV/dt_f   492.450mV/53.000ps  470.459mV/55.000ps  498.810mV/56.000ps
[Rising waveform]
R_fixture=50.000Ohm
V_fixture=1.200
V_fixture_min=1.140
V_fixture_max=1.260
0s        375.6mV    352.7mV    421.9mV
8ps       444.2mV    402mV      499.4mV
14ps      519.5mV    455mV      572.8mV
31ps      761.1mV    668.8mV    799.8mV
41ps      875.5mV    790.3mV    914.2mV
55ps      991.8mV    919.2mV    1.033V
73ps      1.085V     1.021V     1.129V
93ps      1.14V      1.079V     1.19V
122ps     1.177V     1.117V     1.231V
234ps     1.199V     1.139V     1.259V
[Rising waveform]
R_fixture=50.000Ohm
V_fixture=0
0s        -1.52mV    -226.7uV   -565uV
3ps       -1.52mV    -226.7uV   6.812mV
8ps       32.57mV    15.02mV    51.31mV
22ps      160.9mV    108.8mV    196.5mV
51ps      474.8mV    396.1mV    482.9mV
68ps      598.6mV    540.7mV    600.9mV
88ps      692.8mV    647.2mV    694mV
111ps     753.4mV    714.7mV    756.8mV
138ps     788.7mV    752.4mV    795.5mV
237ps     819mV      782.1mV    829.4mV
[Falling waveform]
R_fixture=50.000Ohm
V_fixture=1.200
V_fixture_min=1.140
V_fixture_max=1.260
0s        1.201V     1.142V     1.261V
10ps      1.15V      1.111V     1.189V
27ps      1.003V     1.004V     1.029V
57ps      701.2mV    738.4mV    748mV
74ps      579.8mV    596mV      632.8mV
88ps      512.1mV    514.2mV    566.1mV
107ps     454.9mV    444.3mV    509.3mV
132ps     415.3mV    397.7mV    469mV
176ps     389.8mV    368.2mV    440.9mV
236ps     382mV      359.1mV    431.8mV
[Falling waveform]
R_fixture=50.000Ohm
V_fixture=0
0s        824.7mV    786.8mV    833.5mV
8ps       774mV      756.5mV    776.4mV
18ps      667.8mV    683.5mV    674.3mV
36ps      426.1mV    486.5mV    437mV
48ps      291.7mV    347.9mV    305.1mV
62ps      184mV      221.6mV    196.7mV
78ps      106.4mV    128.9mV    118.1mV
100ps     50.74mV    59.89mV    58.49mV
126ps     21.29mV    24.92mV    25.67mV
235ps     724uV      998.5uV    928.7uV
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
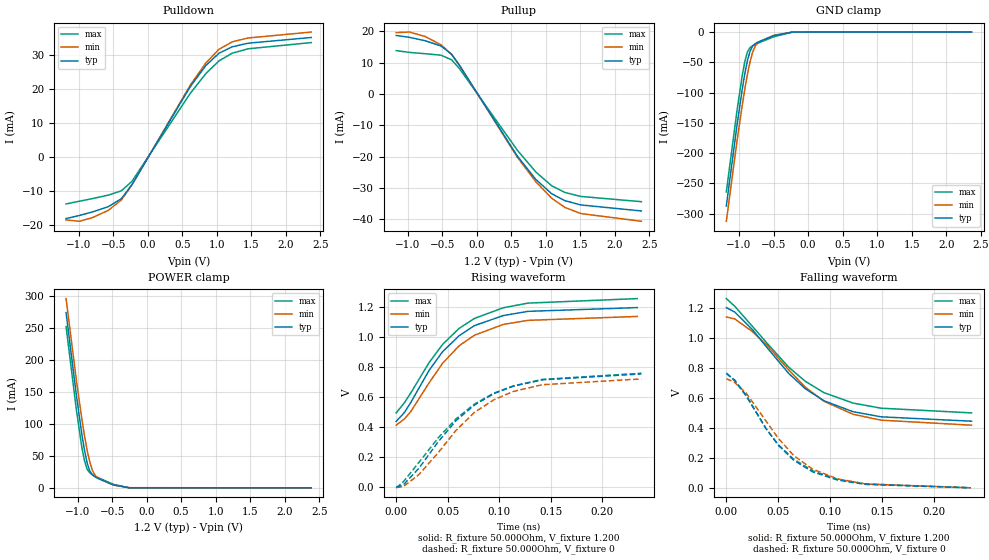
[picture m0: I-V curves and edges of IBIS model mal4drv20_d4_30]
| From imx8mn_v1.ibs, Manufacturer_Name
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[Model] mal4drv20_d4_30
Model_type   I/O
Polarity   Non-Inverting
Enable   Active-High
C_comp   1.691pF   1.683pF   1.699pF
C_comp_pullup   737.671fF   724.063fF   743.649fF
C_comp_pulldown 903.204fF   890.383fF   921.747fF
Vinh = 883.000mV
Vinl = 768.000mV
Vmeas = 825.000mV
Vref = 825.000mV
Rref = 50Ohms
Cref = 0pF
[Model Spec]
Vinh   883.000mV   841.000mV   924.000mV
Vinl   768.000mV   726.000mV   809.000mV
Vmeas   825.000mV   784.000mV   866.000mV
Vref   825.000mV   784.000mV   866.000mV
D_overshoot_ampl_h 0.24 NA   NA
D_overshoot_ampl_l 0.24 NA   NA
D_overshoot_area_l 300.000m NA   NA
D_overshoot_area_h 300.000m NA   NA
|[Receiver Thresholds]
|Vth = 825.000mV
|Vth_min = 784.000mV
|Vth_max = 866.000mV
|Vinh_ac = 68.000mV
|Vinh_dc = 68.000mV
|Vinl_ac = -68.000mV
|Vinl_dc = -68.000mV
|Tslew_ac = 5.000ns
|Threshold_sensitivity = 0.5
|Reference_supply Pullup_ref
[Temperature Range]   25.000   125.000   -40.000
[Voltage Range]   1.200V   1.140V   1.260V
[GND Clamp Reference]   0.00V   0.00V   0.00V
|[C Comp Corner]
|| variable   typ   min   max
|C_comp 1.699pF   1.683pF   1.691pF
|C_comp_pullup 743.649fF   724.063fF   737.671fF
|C_comp_pulldown 903.204fF   921.747fF   890.383fF
[Pulldown Reference]   0.00V   0.00V   0.00V
[POWER Clamp Reference]   1.200V   1.140V   1.260V
[Pullup Reference]   1.200V   1.140V   1.260V
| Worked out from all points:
|   slope of the pulldown table from 0 to 0.18 V, typ, clamps not added: 28.5 ohm
|   slope of the pullup table from 0 to 0.18 V, typ, clamps not added: 28.2 ohm
|   GND clamp passes 1 mA (typ) near -0.33 V on its own axis
|   POWER clamp passes 1 mA (typ) near -0.36 V on its own axis
|   rising waveform, R_fixture 50.000Ohm, V_fixture 1.200: 20-80 % time 52ps typ, 51.6ps min, 54.8ps max; typ from 0.439 V to 1.2 V
|   rising waveform, R_fixture 50.000Ohm, V_fixture 0: 20-80 % time 64.1ps typ, 62.9ps min, 68.9ps max; typ from 0 V to 0.756 V
|   falling waveform, R_fixture 50.000Ohm, V_fixture 1.200: 20-80 % time 64.5ps typ, 65.1ps min, 68.4ps max; typ from 1.2 V to 0.445 V
|   falling waveform, R_fixture 50.000Ohm, V_fixture 0: 20-80 % time 51.6ps typ, 53.1ps min, 53.6ps max; typ from 0.763 V to 0.001 V
[GND Clamp]
-1.184V   -287.4mA   -312.7mA   -264.2mA
-1.031V   -155.3mA   -181.5mA   -131.2mA
-954.6mV  -95.39mA   -121.7mA   -72.46mA
-916.4mV  -69mA      -94.39mA   -48.75mA
-878.2mV  -46.95mA   -69.72mA   -32.79mA
-840mV    -31.44mA   -48.8mA    -25.56mA
-801.8mV  -23.08mA   -32.94mA   -22.5mA
-763.6mV  -19.1mA    -22.7mA    -20.38mA
-725.5mV  -16.66mA   -16.96mA   -18.44mA
-496.4mV  -6.091mA   -5.301mA   -7.811mA
-229.1mV  -85.34uA   -131.6uA   -211.4uA
2.367V    74.27nA    1.057uA    27.11nA
[Power Clamp]
-1.167V   274.5mA    296.4mA    252.6mA
-1.015V   142.4mA    166mA      119.9mA
-938.2mV  83.72mA    107.6mA    63.18mA
-900mV    58.71mA    81.52mA    42.14mA
-861.8mV  39mA       58.71mA    29.24mA
-823.6mV  26.53mA    40.39mA    23.35mA
-785.5mV  20.35mA    27.47mA    20.48mA
-747.3mV  17.16mA    19.6mA     18.3mA
-709.1mV  14.88mA    15.15mA    16.26mA
-480mV    4.411mA    4.49mA     5.397mA
-250.9mV  59.97uA    214.6uA    73.54uA
2.384V    -51.61nA   -1.045uA   -11.93nA
[Pulldown]
-1.184V   -18.2mA    -18.6mA    -13.9mA
-992.7mV  -17.3mA    -19mA      -13.1mA
-801.8mV  -16.25mA   -17.92mA   -12.32mA
-572.7mV  -14.71mA   -15.79mA   -11.3mA
-381.8mV  -12.32mA   -12.7mA    -10.02mA
-229.1mV  -8.176mA   -8.266mA   -7.215mA
610.9mV   20.52mA    20.94mA    18.54mA
840mV     26.83mA    27.58mA    24.46mA
1.031V    30.47mA    31.63mA    28.22mA
1.222V    32.35mA    33.8mA     30.47mA
1.451V    33.41mA    34.95mA    31.77mA
2.367V    35.1mA     36.7mA     33.6mA
[Pullup]
-1.167V   18.7mA     19.61mA    13.86mA
-976.4mV  18.1mA     19.79mA    13.28mA
-747.3mV  17.01mA    18.36mA    12.87mA
-518.2mV  15.34mA    15.72mA    12.39mA
-365.4mV  12.71mA    12.66mA    10.92mA
-250.9mV  9.145mA    9.177mA    8.121mA
589.1mV   -19.92mA   -20.27mA   -18.03mA
856.4mV   -27.35mA   -28.09mA   -24.97mA
1.085V    -31.91mA   -33.34mA   -29.35mA
1.276V    -34.11mA   -36.26mA   -31.48mA
1.505V    -35.47mA   -38.23mA   -32.76mA
2.384V    -37.4mA    -40.7mA    -34.44mA
[Ramp]
R_load=50.000Ohm
dV/dt_r   455.460mV/59.500ps  435.718mV/59.000ps  458.700mV/64.000ps
dV/dt_f   455.460mV/59.000ps  435.718mV/61.000ps  458.700mV/62.000ps
[Rising waveform]
R_fixture=50.000Ohm
V_fixture=1.200
V_fixture_min=1.140
V_fixture_max=1.260
0s        439.2mV    413.7mV    496.2mV
8ps       498.7mV    455.8mV    563.4mV
14ps      563.8mV    503.3mV    627.2mV
32ps      780.3mV    696.9mV    831.8mV
45ps      903.7mV    826.6mV    952.3mV
61ps      1.01V      943mV      1.059V
76ps      1.078V     1.014V     1.126V
104ps     1.145V     1.086V     1.197V
128ps     1.173V     1.113V     1.228V
234ps     1.198V     1.139V     1.258V
[Rising waveform]
R_fixture=50.000Ohm
V_fixture=0
0s        -124.6uV   -2.601mV   -4.033mV
7ps       16.36mV    4.469mV    36.7mV
22ps      126.2mV    84.28mV    164.9mV
41ps      304.9mV    232.4mV    331.2mV
58ps      443.9mV    378.8mV    455.5mV
76ps      548.5mV    499.6mV    554.4mV
95ps      624.7mV    584mV      628.2mV
114ps     674.7mV    639.6mV    676.1mV
142ps     716.4mV    683.9mV    719.1mV
238ps     755.5mV    722.3mV    760.3mV
[Falling waveform]
R_fixture=50.000Ohm
V_fixture=1.200
V_fixture_min=1.140
V_fixture_max=1.260
0s        1.202V     1.14V      1.262V
8ps       1.173V     1.127V     1.212V
25ps      1.056V     1.043V     1.078V
40ps      929mV      944.9mV    958.6mV
60ps      763.8mV    787.6mV    805.3mV
76ps      661.9mV    672mV      711.2mV
94ps      581.2mV    578.2mV    635.3mV
122ps     508.6mV    491.3mV    566mV
149ps     474.3mV    452.1mV    531.8mV
236ps     445.2mV    418.7mV    500.6mV
[Falling waveform]
R_fixture=50.000Ohm
V_fixture=0
0s        762.7mV    728.4mV    767.3mV
8ps       720.3mV    703.4mV    713.5mV
19ps      618.1mV    632.5mV    614.4mV
38ps      398.8mV    448.7mV    398mV
50ps      285.1mV    331.1mV    289mV
65ps      184.6mV    215.6mV    191.1mV
83ps      108mV      126.1mV    115.5mV
107ps     53.13mV    60.68mV    58.64mV
134ps     24mV       26.93mV    27.58mV
235ps     1.289mV    1.611mV    1.647mV
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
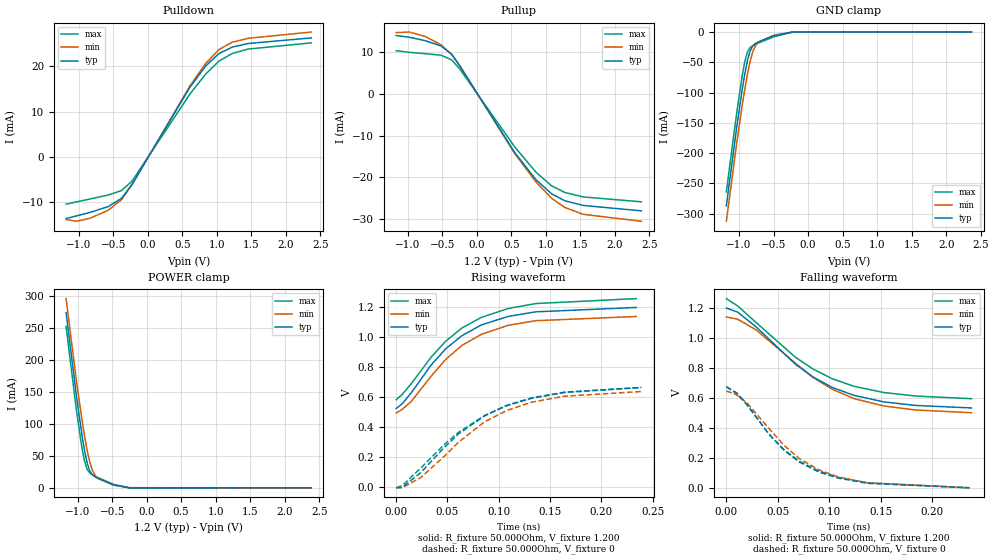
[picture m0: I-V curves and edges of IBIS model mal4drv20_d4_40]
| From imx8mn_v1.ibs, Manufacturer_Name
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[Model] mal4drv20_d4_40
Model_type   I/O
Polarity   Non-Inverting
Enable   Active-High
C_comp   1.691pF   1.683pF   1.699pF
C_comp_pullup   737.671fF   724.063fF   743.649fF
C_comp_pulldown 903.204fF   890.383fF   921.747fF
Vinh = 668.000mV
Vinl = 532.000mV
Vmeas = 600.000mV
Vref = 600.000mV
Rref = 50Ohms
Cref = 0pF
[Model Spec]
Vinh   668.000mV   638.000mV   698.000mV
Vinl   532.000mV   502.000mV   562.000mV
Vmeas   600.000mV   570.000mV   640.000mV
Vref   600.000mV   570.000mV   640.000mV
D_overshoot_ampl_h 0.24 NA   NA
D_overshoot_ampl_l 0.24 NA   NA
D_overshoot_area_l 300.000m NA   NA
D_overshoot_area_h 300.000m NA   NA
|[Receiver Thresholds]
|Vth = 600.000mV
|Vth_min = 570.000mV
|Vth_max = 640.000mV
|Vinh_ac = 68.000mV
|Vinh_dc = 68.000mV
|Vinl_ac = -68.000mV
|Vinl_dc = -68.000mV
|Tslew_ac = 5.000ns
|Threshold_sensitivity = 0.5
|Reference_supply Pullup_ref
[Temperature Range]   25.000   125.000   -40.000
[Voltage Range]   1.200V   1.140V   1.260V
[GND Clamp Reference]   0.00V   0.00V   0.00V
|[C Comp Corner]
|| variable   typ   min   max
|C_comp 1.699pF   1.683pF   1.691pF
|C_comp_pullup 743.649fF   724.063fF   737.671fF
|C_comp_pulldown 903.204fF   921.747fF   890.383fF
[Pulldown Reference]   0.00V   0.00V   0.00V
[POWER Clamp Reference]   1.200V   1.140V   1.260V
[Pullup Reference]   1.200V   1.140V   1.260V
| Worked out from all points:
|   slope of the pulldown table from 0 to 0.18 V, typ, clamps not added: 38 ohm
|   slope of the pullup table from 0 to 0.18 V, typ, clamps not added: 37.6 ohm
|   GND clamp passes 1 mA (typ) near -0.33 V on its own axis
|   POWER clamp passes 1 mA (typ) near -0.36 V on its own axis
|   rising waveform, R_fixture 50.000Ohm, V_fixture 1.200: 20-80 % time 59.6ps typ, 58.9ps min, 62.1ps max; typ from 0.525 V to 1.2 V
|   rising waveform, R_fixture 50.000Ohm, V_fixture 0: 20-80 % time 74.1ps typ, 72.3ps min, 78.7ps max; typ from -0.003 V to 0.665 V
|   falling waveform, R_fixture 50.000Ohm, V_fixture 1.200: 20-80 % time 73.8ps typ, 74.3ps min, 78ps max; typ from 1.2 V to 0.535 V
|   falling waveform, R_fixture 50.000Ohm, V_fixture 0: 20-80 % time 58.5ps typ, 59.8ps min, 60.6ps max; typ from 0.676 V to 0.003 V
[GND Clamp]
-1.184V   -287.4mA   -312.7mA   -264.2mA
-1.031V   -155.3mA   -181.5mA   -131.2mA
-954.6mV  -95.39mA   -121.7mA   -72.46mA
-916.4mV  -69mA      -94.39mA   -48.75mA
-878.2mV  -46.95mA   -69.72mA   -32.79mA
-840mV    -31.44mA   -48.8mA    -25.56mA
-801.8mV  -23.08mA   -32.94mA   -22.5mA
-763.6mV  -19.1mA    -22.7mA    -20.38mA
-725.5mV  -16.66mA   -16.96mA   -18.44mA
-496.4mV  -6.091mA   -5.301mA   -7.811mA
-229.1mV  -85.34uA   -131.6uA   -211.4uA
2.367V    74.27nA    1.057uA    27.11nA
[Power Clamp]
-1.167V   274.5mA    296.4mA    252.6mA
-1.015V   142.4mA    166mA      119.9mA
-938.2mV  83.72mA    107.6mA    63.18mA
-900mV    58.71mA    81.52mA    42.14mA
-861.8mV  39mA       58.71mA    29.24mA
-823.6mV  26.53mA    40.39mA    23.35mA
-785.5mV  20.35mA    27.47mA    20.48mA
-747.3mV  17.16mA    19.6mA     18.3mA
-709.1mV  14.88mA    15.15mA    16.26mA
-480mV    4.411mA    4.49mA     5.397mA
-250.9mV  59.97uA    214.6uA    73.54uA
2.384V    -51.61nA   -1.045uA   -11.93nA
[Pulldown]
-1.184V   -13.7mA    -13.9mA    -10.5mA
-1.031V   -13.1mA    -14.3mA    -10mA
-840mV    -12.35mA   -13.65mA   -9.37mA
-572.7mV  -11.04mA   -11.85mA   -8.48mA
-381.8mV  -9.241mA   -9.528mA   -7.515mA
-229.1mV  -6.132mA   -6.2mA     -5.412mA
610.9mV   15.39mA    15.7mA     13.9mA
840mV     20.12mA    20.69mA    18.34mA
1.031V    22.85mA    23.72mA    21.17mA
1.222V    24.26mA    25.35mA    22.85mA
1.451V    25.06mA    26.21mA    23.83mA
2.367V    26.3mA     27.6mA     25.2mA
[Pullup]
-1.167V   14mA       14.71mA    10.36mA
-976.4mV  13.6mA     14.84mA    9.974mA
-747.3mV  12.77mA    13.78mA    9.659mA
-518.2mV  11.51mA    11.8mA     9.295mA
-365.4mV  9.535mA    9.493mA    8.189mA
-250.9mV  6.86mA     6.885mA    6.092mA
550.9mV   -14.06mA   -14.3mA    -12.71mA
856.4mV   -20.52mA   -21.07mA   -18.73mA
1.085V    -23.94mA   -25mA      -22.02mA
1.276V    -25.59mA   -27.2mA    -23.61mA
1.544V    -26.71mA   -28.84mA   -24.67mA
2.384V    -28mA      -30.5mA    -25.84mA
[Ramp]
R_load=50.000Ohm
dV/dt_r   403.890mV/69.000ps  387.238mV/67.500ps  403.560mV/73.000ps
dV/dt_f   403.890mV/68.500ps  387.238mV/69.000ps  403.560mV/72.000ps
[Rising waveform]
R_fixture=50.000Ohm
V_fixture=1.200
V_fixture_min=1.140
V_fixture_max=1.260
0s        525.1mV    494.8mV    583.2mV
6ps       556.9mV    519.1mV    619.2mV
15ps      632.4mV    574.3mV    692.9mV
34ps      813.6mV    739.4mV    865.9mV
48ps      920.4mV    849.4mV    970.9mV
64ps      1.009V     944.4mV    1.06V
83ps      1.081V     1.018V     1.131V
109ps     1.137V     1.078V     1.19V
136ps     1.168V     1.109V     1.223V
234ps     1.197V     1.137V     1.256V
[Rising waveform]
R_fixture=50.000Ohm
V_fixture=0
0s        -3.175mV   -1.879mV   -2.559mV
6ps       301.2uV    -1.879mV   12.46mV
24ps      98.45mV    65.39mV    128.9mV
47ps      266.7mV    207.3mV    286.4mV
61ps      357.2mV    301.9mV    367.2mV
86ps      475.4mV    435.5mV    477.4mV
108ps     546.5mV    512.2mV    544.1mV
132ps     595.3mV    566.8mV    592.4mV
164ps     633.2mV    606.4mV    631.2mV
239ps     665.1mV    637.7mV    664.3mV
[Falling waveform]
R_fixture=50.000Ohm
V_fixture=1.200
V_fixture_min=1.140
V_fixture_max=1.260
0s        1.2V       1.141V     1.263V
11ps      1.173V     1.126V     1.214V
29ps      1.074V     1.054V     1.103V
67ps      826.3mV    833.6mV    872.7mV
84ps      741.7mV    738.5mV    794.3mV
103ps     670.9mV    658.8mV    728.5mV
124ps     618.5mV    596.8mV    678.7mV
153ps     575mV      547.7mV    637.3mV
184ps     551.3mV    521mV      613.9mV
238ps     534.7mV    502.9mV    596.4mV
[Falling waveform]
R_fixture=50.000Ohm
V_fixture=0
0s        675.6mV    647.5mV    676.2mV
10ps      635.6mV    622.3mV    629.7mV
20ps      558.5mV    568.5mV    556.2mV
41ps      363.1mV    401.1mV    363mV
56ps      253.2mV    285.7mV    256.8mV
71ps      173.8mV    196.7mV    179.9mV
90ps      107.6mV    121.8mV    114.1mV
109ps     66.97mV    73.95mV    72.09mV
137ps     32.47mV    35.93mV    36.25mV
236ps     2.63mV     2.927mV    3.312mV
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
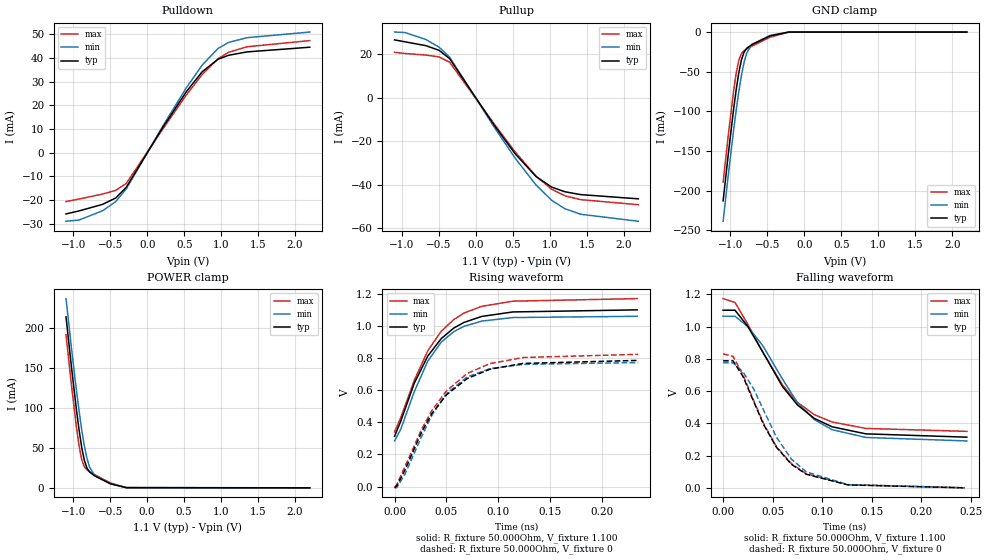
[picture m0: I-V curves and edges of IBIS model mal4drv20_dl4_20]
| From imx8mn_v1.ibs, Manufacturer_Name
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[Model] mal4drv20_dl4_20
Model_type   I/O
Polarity   Non-Inverting
Enable   Active-High
C_comp   1.694pF   1.685pF   1.701pF
C_comp_pullup   740.500fF   727.408fF   745.615fF
C_comp_pulldown 903.226fF   891.311fF   923.097fF
Vinh = 453.000mV
Vinl = 333.000mV
Vmeas = 393.000mV
Vref = 393.000mV
Rref = 50Ohms
Cref = 5pF
[Model Spec]
Vinh   453.000mV   439.000mV   478.000mV
Vinl   333.000mV   319.000mV   358.000mV
Vmeas   393.000mV   379.000mV   418.000mV
Vref   393.000mV   379.000mV   418.000mV
D_overshoot_ampl_h 0.3 NA   NA
D_overshoot_ampl_l 0.3 NA   NA
D_overshoot_area_l 100.000m NA   NA
D_overshoot_area_h 100.000m NA   NA
|[Receiver Thresholds]
|Vth = 393.000mV
|Vth_min = 379.000mV
|Vth_max = 418.000mV
|Vinh_ac = 600.000mV
|Vinh_dc = 600.000mV
|Vinl_ac = -600.000mV
|Vinl_dc = -600.000mV
|Tslew_ac = 5.000ns
|Threshold_sensitivity = 0.5
|Reference_supply Pullup_ref
[Temperature Range]   25.000   125.000   -40.000
[Voltage Range]   1.100V   1.060V   1.170V
[GND Clamp Reference]   0.00V   0.00V   0.00V
|[C Comp Corner]
|| variable   typ   min   max
|C_comp 1.701pF   1.685pF   1.694pF
|C_comp_pullup 745.615fF   727.408fF   740.500fF
|C_comp_pulldown 903.226fF   923.097fF   891.311fF
[Pulldown Reference]   0.00V   0.00V   0.00V
[POWER Clamp Reference]   1.100V   1.060V   1.170V
[Pullup Reference]   1.100V   1.060V   1.170V
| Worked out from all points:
|   slope of the pulldown table from 0 to 0.165 V, typ, clamps not added: 19.6 ohm
|   slope of the pullup table from 0 to 0.165 V, typ, clamps not added: 19.6 ohm
|   GND clamp passes 1 mA (typ) near -0.33 V on its own axis
|   POWER clamp passes 1 mA (typ) near -0.36 V on its own axis
|   rising waveform, R_fixture 50.000Ohm, V_fixture 1.100: 20-80 % time 39.1ps typ, 35.1ps min, 40.2ps max; typ from 0.313 V to 1.1 V
|   rising waveform, R_fixture 50.000Ohm, V_fixture 0: 20-80 % time 46.2ps typ, 40.4ps min, 47.5ps max; typ from -0.008 V to 0.786 V
|   falling waveform, R_fixture 50.000Ohm, V_fixture 1.100: 20-80 % time 51.7ps typ, 50.8ps min, 52.6ps max; typ from 1.1 V to 0.314 V
|   falling waveform, R_fixture 50.000Ohm, V_fixture 0: 20-80 % time 42.2ps typ, 42.4ps min, 43.4ps max; typ from 0.787 V to 0 V
[GND Clamp]
-1.099V   -213mA     -238.8mA   -189.3mA
-1.028V   -153mA     -179.5mA   -129.1mA
-957.3mV  -97.39mA   -123.9mA   -74.45mA
-921.8mV  -72.55mA   -98.33mA   -51.84mA
-886.4mV  -51.19mA   -74.9mA    -35.5mA
-850.9mV  -35.09mA   -54.48mA   -27.05mA
-815.5mV  -25.37mA   -38.12mA   -23.48mA
-780mV    -20.49mA   -26.59mA   -21.33mA
-709.1mV  -15.78mA   -15.51mA   -17.7mA
-460.9mV  -4.751mA   -4.194mA   -6.404mA
-212.7mV  -50.02uA   -89.63uA   -120.8uA
2.198V    95.2nA     1.084uA    26.44nA
[Power Clamp]
-1.098V   213.3mA    236.1mA    191mA
-1.027V   152.9mA    176.5mA    130.3mA
-956.4mV  96.88mA    121mA      75.05mA
-920.9mV  71.89mA    95.56mA    52.08mA
-885.5mV  50.44mA    72.4mA     35.26mA
-850mV    34.32mA    52.42mA    26.32mA
-814.5mV  24.6mA     36.64mA    22.47mA
-779.1mV  19.69mA    25.68mA    20.17mA
-708.2mV  14.83mA    15.14mA    16.3mA
-495.5mV  4.984mA    5.083mA    6.064mA
-282.7mV  164.9uA    413uA      201.8uA
2.199V    -54.52nA   -1.101uA   -12.05nA
[Pulldown]
-1.099V   -25.8mA    -28.9mA    -20.6mA
-921.8mV  -24.53mA   -28.37mA   -19.5mA
-602.7mV  -21.75mA   -24.44mA   -17.42mA
-425.5mV  -19.06mA   -20.56mA   -15.85mA
-283.6mV  -14.54mA   -15.23mA   -12.94mA
212.7mV   10.81mA    11.39mA    10.11mA
531.8mV   25.87mA    27.54mA    24.51mA
744.5mV   34.2mA     37.02mA    33.05mA
957.3mV   39.42mA    43.96mA    39.63mA
1.099V    41.09mA    46.51mA    42.34mA
1.347V    42.52mA    48.51mA    44.68mA
2.198V    44.5mA     50.9mA     47.3mA
[Pullup]
-1.098V   26.6mA     30.21mA    20.9mA
-956.4mV  25.72mA    29.96mA    20.35mA
-672.7mV  23.94mA    26.78mA    19.63mA
-495.5mV  21.8mA     23.26mA    18.79mA
-353.6mV  18.01mA    18.71mA    16.37mA
249.1mV   -12.59mA   -13.42mA   -11.96mA
532.7mV   -25.7mA    -27.7mA    -24.83mA
816.4mV   -36.2mA    -40.09mA   -36.01mA
1.029V    -41.05mA   -47.13mA   -42.06mA
1.206V    -43.15mA   -50.95mA   -45mA
1.419V    -44.46mA   -53.48mA   -46.78mA
2.199V    -46.4mA    -56.71mA   -49.1mA
[Ramp]
R_load=50.000Ohm
dV/dt_r   471.870mV/43.500ps  462.749mV/38.500ps  493.440mV/45.000ps
dV/dt_f   471.870mV/48.000ps  462.749mV/47.000ps  493.440mV/49.500ps
[Rising waveform]
R_fixture=50.000Ohm
V_fixture=1.100
V_fixture_min=1.060
V_fixture_max=1.170
0s        312.8mV    284.7mV    340.1mV
6ps       407.8mV    357.5mV    429.8mV
19ps      643.6mV    590.8mV    661.6mV
32ps      812mV      780.6mV    845.1mV
45ps      921.3mV    899.4mV    966.9mV
57ps      986.2mV    964mV      1.039V
67ps      1.022V     997.6mV    1.08V
84ps      1.059V     1.03V      1.122V
114ps     1.087V     1.052V     1.154V
234ps     1.1V       1.06V      1.17V
[Rising waveform]
R_fixture=50.000Ohm
V_fixture=0
0s        -7.544mV   -7.025mV   -2.433mV
2ps       2.588mV    -7.025mV   10.4mV
10ps      102.7mV    77.18mV    124.2mV
26ps      338.6mV    310.7mV    355.9mV
36ps      455.2mV    444.7mV    473.7mV
50ps      570.9mV    578.5mV    595.8mV
70ps      672.4mV    682.5mV    704.1mV
92ps      730.9mV    733.9mV    765.6mV
124ps     766.7mV    760.7mV    803.3mV
235ps     785.5mV    772mV      823.3mV
[Falling waveform]
R_fixture=50.000Ohm
V_fixture=1.100
V_fixture_min=1.060
V_fixture_max=1.170
0s        1.101V     1.064V     1.173V
12ps      1.101V     1.064V     1.149V
25ps      1V         999mV      1.013V
40ps      842.1mV    881.4mV    841.8mV
60ps      627.2mV    673mV      636.8mV
75ps      514.3mV    529mV      530.5mV
92ps      430.7mV    423.3mV    453.8mV
110ps     378.6mV    360.6mV    408.5mV
144ps     335mV      312.6mV    368.5mV
246ps     314.3mV    291mV      350.2mV
[Falling waveform]
R_fixture=50.000Ohm
V_fixture=0
0s        787.3mV    775mV      831.3mV
10ps      787.3mV    775mV      814.7mV
20ps      691.5mV    719.7mV    700.4mV
31ps      533mV      611.6mV    539.4mV
41ps      391.1mV    479.7mV    396.2mV
54ps      250.4mV    312.3mV    253.8mV
69ps      145.7mV    177.6mV    149.9mV
84ps      84.54mV    99.07mV    87mV
126ps     18.47mV    20.04mV    19.94mV
244ps     398.9uV    549.1uV    376.4uV
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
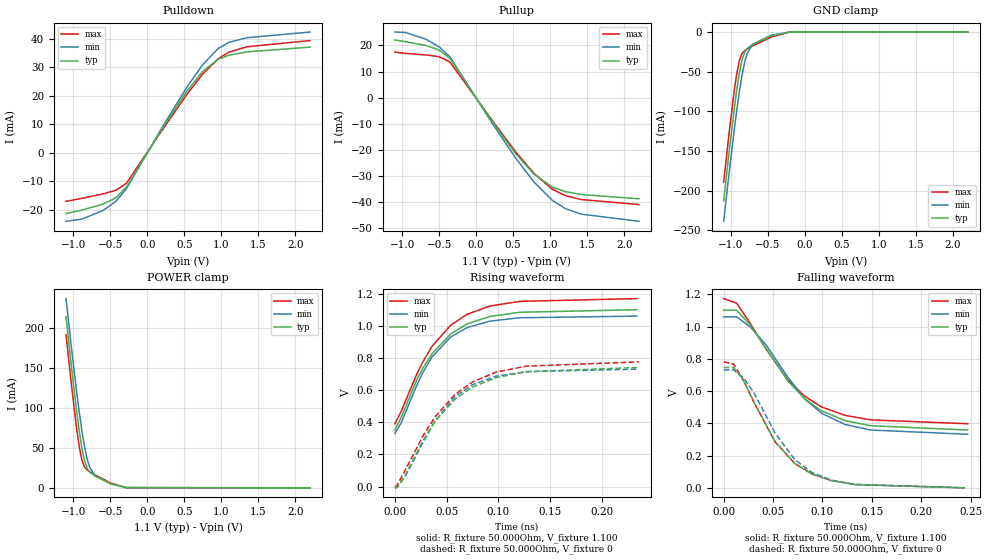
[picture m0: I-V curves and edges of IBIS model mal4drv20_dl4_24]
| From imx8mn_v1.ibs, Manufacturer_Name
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[Model] mal4drv20_dl4_24
Model_type   I/O
Polarity   Non-Inverting
Enable   Active-High
C_comp   1.694pF   1.685pF   1.701pF
C_comp_pullup   740.500fF   727.408fF   745.615fF
C_comp_pulldown 903.226fF   891.311fF   923.097fF
Vinh = 432.000mV
Vinl = 312.000mV
Vmeas = 372.000mV
Vref = 372.000mV
Rref = 50Ohms
Cref = 5pF
[Model Spec]
Vinh   432.000mV   418.000mV   455.000mV
Vinl   312.000mV   298.000mV   335.000mV
Vmeas   372.000mV   358.000mV   395.000mV
Vref   372.000mV   358.000mV   395.000mV
D_overshoot_ampl_h 0.3 NA   NA
D_overshoot_ampl_l 0.3 NA   NA
D_overshoot_area_l 100.000m NA   NA
D_overshoot_area_h 100.000m NA   NA
|[Receiver Thresholds]
|Vth = 372.000mV
|Vth_min = 358.000mV
|Vth_max = 395.000mV
|Vinh_ac = 600.000mV
|Vinh_dc = 600.000mV
|Vinl_ac = -600.000mV
|Vinl_dc = -600.000mV
|Tslew_ac = 5.000ns
|Threshold_sensitivity = 0.5
|Reference_supply Pullup_ref
[Temperature Range]   25.000   125.000   -40.000
[Voltage Range]   1.100V   1.060V   1.170V
[GND Clamp Reference]   0.00V   0.00V   0.00V
|[C Comp Corner]
|| variable   typ   min   max
|C_comp 1.701pF   1.685pF   1.694pF
|C_comp_pullup 745.615fF   727.408fF   740.500fF
|C_comp_pulldown 903.226fF   923.097fF   891.311fF
[Pulldown Reference]   0.00V   0.00V   0.00V
[POWER Clamp Reference]   1.100V   1.060V   1.170V
[Pullup Reference]   1.100V   1.060V   1.170V
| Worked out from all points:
|   slope of the pulldown table from 0 to 0.165 V, typ, clamps not added: 23.5 ohm
|   slope of the pullup table from 0 to 0.165 V, typ, clamps not added: 23.5 ohm
|   GND clamp passes 1 mA (typ) near -0.33 V on its own axis
|   POWER clamp passes 1 mA (typ) near -0.36 V on its own axis
|   rising waveform, R_fixture 50.000Ohm, V_fixture 1.100: 20-80 % time 43.8ps typ, 39.7ps min, 44.7ps max; typ from 0.351 V to 1.1 V
|   rising waveform, R_fixture 50.000Ohm, V_fixture 0: 20-80 % time 52.3ps typ, 46ps min, 53.5ps max; typ from -0.008 V to 0.741 V
|   falling waveform, R_fixture 50.000Ohm, V_fixture 1.100: 20-80 % time 57.8ps typ, 56ps min, 58.4ps max; typ from 1.1 V to 0.359 V
|   falling waveform, R_fixture 50.000Ohm, V_fixture 0: 20-80 % time 46.6ps typ, 46.1ps min, 47.4ps max; typ from 0.747 V to 0.001 V
[GND Clamp]
-1.099V   -213mA     -238.8mA   -189.3mA
-1.028V   -153mA     -179.5mA   -129.1mA
-957.3mV  -97.39mA   -123.9mA   -74.45mA
-921.8mV  -72.55mA   -98.33mA   -51.84mA
-886.4mV  -51.19mA   -74.9mA    -35.5mA
-850.9mV  -35.09mA   -54.48mA   -27.05mA
-815.5mV  -25.37mA   -38.12mA   -23.48mA
-780mV    -20.49mA   -26.59mA   -21.33mA
-709.1mV  -15.78mA   -15.51mA   -17.7mA
-460.9mV  -4.751mA   -4.194mA   -6.404mA
-212.7mV  -50.02uA   -89.63uA   -120.8uA
2.198V    95.2nA     1.084uA    26.44nA
[Power Clamp]
-1.098V   213.3mA    236.1mA    191mA
-1.027V   152.9mA    176.5mA    130.3mA
-956.4mV  96.88mA    121mA      75.05mA
-920.9mV  71.89mA    95.56mA    52.08mA
-885.5mV  50.44mA    72.4mA     35.26mA
-850mV    34.32mA    52.42mA    26.32mA
-814.5mV  24.6mA     36.64mA    22.47mA
-779.1mV  19.69mA    25.68mA    20.17mA
-708.2mV  14.83mA    15.14mA    16.3mA
-495.5mV  4.984mA    5.083mA    6.064mA
-282.7mV  164.9uA    413uA      201.8uA
2.199V    -54.52nA   -1.101uA   -12.05nA
[Pulldown]
-1.099V   -21.4mA    -24.1mA    -17.1mA
-886.4mV  -20.19mA   -23.35mA   -16.04mA
-602.7mV  -18.11mA   -20.34mA   -14.51mA
-425.5mV  -15.87mA   -17.12mA   -13.2mA
-283.6mV  -12.11mA   -12.68mA   -10.77mA
212.7mV   8.998mA    9.482mA    8.419mA
531.8mV   21.54mA    22.93mA    20.41mA
744.5mV   28.48mA    30.83mA    27.53mA
957.3mV   32.84mA    36.62mA    33.01mA
1.099V    34.24mA    38.75mA    35.28mA
1.347V    35.43mA    40.42mA    37.23mA
2.198V    37.1mA     42.4mA     39.4mA
[Pullup]
-1.098V   22.1mA     25.11mA    17.4mA
-956.4mV  21.42mA    24.96mA    16.94mA
-672.7mV  19.93mA    22.29mA    16.35mA
-495.5mV  18.15mA    19.37mA    15.65mA
-353.6mV  14.99mA    15.58mA    13.63mA
213.6mV   -9.03mA    -9.621mA   -8.571mA
532.7mV   -21.4mA    -23.07mA   -20.68mA
780.9mV   -29.24mA   -32.23mA   -28.96mA
1.029V    -34.2mA    -39.26mA   -35.04mA
1.206V    -35.95mA   -42.45mA   -37.49mA
1.419V    -37.05mA   -44.57mA   -38.98mA
2.199V    -38.7mA    -47.3mA    -40.9mA
[Ramp]
R_load=50.000Ohm
dV/dt_r   445.500mV/49.000ps  438.178mV/44.000ps  464.910mV/50.000ps
dV/dt_f   445.500mV/53.500ps  438.179mV/52.000ps  464.910mV/54.000ps
[Rising waveform]
R_fixture=50.000Ohm
V_fixture=1.100
V_fixture_min=1.060
V_fixture_max=1.170
0s        350.7mV    330.1mV    389.4mV
6ps       428.6mV    394.6mV    466.5mV
21ps      661.1mV    626.8mV    695.8mV
27ps      735.2mV    708.3mV    775mV
36ps      826.2mV    805.9mV    872.3mV
54ps      948.9mV    930.1mV    1.004V
70ps      1.012V     988.8mV    1.072V
92ps      1.058V     1.029V     1.123V
121ps     1.084V     1.05V      1.152V
234ps     1.1V       1.06V      1.169V
[Rising waveform]
R_fixture=50.000Ohm
V_fixture=0
0s        -8.185mV   -7.108mV   -3.446mV
2ps       -8.185mV   -7.108mV   6.552mV
10ps      71.41mV    62.51mV    101.3mV
27ps      283.3mV    271.2mV    312.5mV
39ps      407.3mV    408.9mV    434.3mV
58ps      541.8mV    557.9mV    572mV
75ps      618.1mV    633mV      650.4mV
98ps      677.6mV    686.4mV    711.8mV
127ps     714.5mV    714.2mV    748.6mV
236ps     740.7mV    730.7mV    775.4mV
[Falling waveform]
R_fixture=50.000Ohm
V_fixture=1.100
V_fixture_min=1.060
V_fixture_max=1.170
0s        1.102V     1.061V     1.174V
13ps      1.102V     1.061V     1.146V
27ps      1.01V      998.3mV    1.019V
43ps      864mV      885.9mV    860.4mV
65ps      663.2mV    686.1mV    669.8mV
82ps      552.9mV    551.6mV    568.9mV
99ps      478mV      463.4mV    502.2mV
123ps     417.2mV    393.1mV    449.8mV
149ps     385.8mV    359mV      421.9mV
247ps     358.9mV    332.7mV    398mV
[Falling waveform]
R_fixture=50.000Ohm
V_fixture=0
0s        746.8mV    732.4mV    782.1mV
10ps      746.8mV    732.4mV    768mV
20ps      666mV      683.4mV    668.5mV
31ps      528mV      586mV      526.3mV
52ps      288mV      340.7mV    285.8mV
72ps      151.2mV    175.2mV    151.8mV
89ps      86.96mV    97.16mV    87.84mV
109ps     44.6mV     48.14mV    46.54mV
133ps     20.72mV    21.3mV     21.54mV
244ps     633.2uV    781.9uV    658.1uV
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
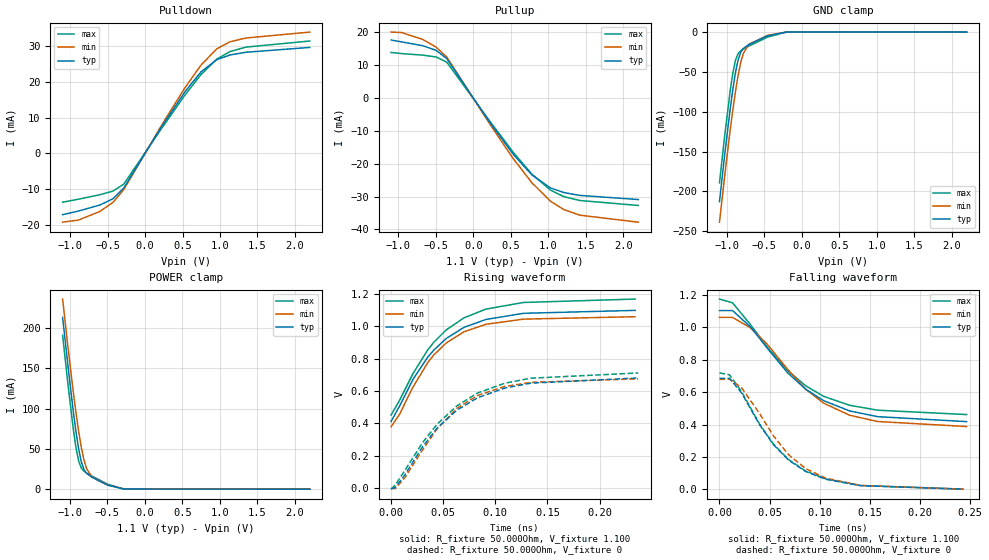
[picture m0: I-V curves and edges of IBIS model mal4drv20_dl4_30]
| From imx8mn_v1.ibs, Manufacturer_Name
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[Model] mal4drv20_dl4_30
Model_type   I/O
Polarity   Non-Inverting
Enable   Active-High
C_comp   1.694pF   1.685pF   1.701pF
C_comp_pullup   740.500fF   727.408fF   745.615fF
C_comp_pulldown 903.226fF   891.311fF   923.097fF
Vinh = 404.000mV
Vinl = 284.000mV
Vmeas = 344.000mV
Vref = 344.000mV
Rref = 50Ohms
Cref = 5pF
[Model Spec]
Vinh   404.000mV   391.000mV   426.000mV
Vinl   284.000mV   271.000mV   306.000mV
Vmeas   344.000mV   331.000mV   366.000mV
Vref   344.000mV   331.000mV   366.000mV
D_overshoot_ampl_h 0.3 NA   NA
D_overshoot_ampl_l 0.3 NA   NA
D_overshoot_area_l 100.000m NA   NA
D_overshoot_area_h 100.000m NA   NA
|[Receiver Thresholds]
|Vth = 344.000mV
|Vth_min = 331.000mV
|Vth_max = 366.000mV
|Vinh_ac = 600.000mV
|Vinh_dc = 600.000mV
|Vinl_ac = -600.000mV
|Vinl_dc = -600.000mV
|Tslew_ac = 5.000ns
|Threshold_sensitivity = 0.5
|Reference_supply Pullup_ref
[Temperature Range]   25.000   125.000   -40.000
[Voltage Range]   1.100V   1.060V   1.170V
[GND Clamp Reference]   0.00V   0.00V   0.00V
|[C Comp Corner]
|| variable   typ   min   max
|C_comp 1.701pF   1.685pF   1.694pF
|C_comp_pullup 745.615fF   727.408fF   740.500fF
|C_comp_pulldown 903.226fF   923.097fF   891.311fF
[Pulldown Reference]   0.00V   0.00V   0.00V
[POWER Clamp Reference]   1.100V   1.060V   1.170V
[Pullup Reference]   1.100V   1.060V   1.170V
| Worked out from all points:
|   slope of the pulldown table from 0 to 0.165 V, typ, clamps not added: 29.4 ohm
|   slope of the pullup table from 0 to 0.165 V, typ, clamps not added: 29.4 ohm
|   GND clamp passes 1 mA (typ) near -0.33 V on its own axis
|   POWER clamp passes 1 mA (typ) near -0.36 V on its own axis
|   rising waveform, R_fixture 50.000Ohm, V_fixture 1.100: 20-80 % time 49.6ps typ, 45.6ps min, 50.8ps max; typ from 0.412 V to 1.1 V
|   rising waveform, R_fixture 50.000Ohm, V_fixture 0: 20-80 % time 60.2ps typ, 53.2ps min, 61.3ps max; typ from -0.003 V to 0.682 V
|   falling waveform, R_fixture 50.000Ohm, V_fixture 1.100: 20-80 % time 65.8ps typ, 63.5ps min, 65.9ps max; typ from 1.1 V to 0.418 V
|   falling waveform, R_fixture 50.000Ohm, V_fixture 0: 20-80 % time 52.1ps typ, 51.3ps min, 52.9ps max; typ from 0.686 V to 0.001 V
[GND Clamp]
-1.099V   -213mA     -238.8mA   -189.3mA
-1.028V   -153mA     -179.5mA   -129.1mA
-957.3mV  -97.39mA   -123.9mA   -74.45mA
-921.8mV  -72.55mA   -98.33mA   -51.84mA
-886.4mV  -51.19mA   -74.9mA    -35.5mA
-850.9mV  -35.09mA   -54.48mA   -27.05mA
-815.5mV  -25.37mA   -38.12mA   -23.48mA
-780mV    -20.49mA   -26.59mA   -21.33mA
-709.1mV  -15.78mA   -15.51mA   -17.7mA
-460.9mV  -4.751mA   -4.194mA   -6.404mA
-212.7mV  -50.02uA   -89.63uA   -120.8uA
2.198V    95.2nA     1.084uA    26.44nA
[Power Clamp]
-1.098V   213.3mA    236.1mA    191mA
-1.027V   152.9mA    176.5mA    130.3mA
-956.4mV  96.88mA    121mA      75.05mA
-920.9mV  71.89mA    95.56mA    52.08mA
-885.5mV  50.44mA    72.4mA     35.26mA
-850mV    34.32mA    52.42mA    26.32mA
-814.5mV  24.6mA     36.64mA    22.47mA
-779.1mV  19.69mA    25.68mA    20.17mA
-708.2mV  14.83mA    15.14mA    16.3mA
-495.5mV  4.984mA    5.083mA    6.064mA
-282.7mV  164.9uA    413uA      201.8uA
2.199V    -54.52nA   -1.101uA   -12.05nA
[Pulldown]
-1.099V   -17.2mA    -19.3mA    -13.7mA
-886.4mV  -16.17mA   -18.69mA   -12.84mA
-602.7mV  -14.49mA   -16.29mA   -11.61mA
-425.5mV  -12.7mA    -13.71mA   -10.56mA
-283.6mV  -9.697mA   -10.16mA   -8.628mA
212.7mV   7.207mA    7.596mA    6.743mA
531.8mV   17.25mA    18.37mA    16.34mA
744.5mV   22.81mA    24.69mA    22.04mA
957.3mV   26.28mA    29.32mA    26.43mA
1.135V    27.59mA    31.29mA    28.55mA
1.347V    28.35mA    32.34mA    29.79mA
2.198V    29.7mA     34mA       31.5mA
[Pullup]
-1.098V   17.7mA     20.11mA    13.9mA
-956.4mV  17.12mA    19.98mA    13.56mA
-672.7mV  15.95mA    17.84mA    13.08mA
-495.5mV  14.53mA    15.51mA    12.52mA
-353.6mV  12mA       12.47mA    10.92mA
213.6mV   -7.232mA   -7.706mA   -6.864mA
532.7mV   -17.14mA   -18.47mA   -16.56mA
780.9mV   -23.41mA   -25.81mA   -23.18mA
1.029V    -27.37mA   -31.42mA   -28.04mA
1.206V    -28.77mA   -33.96mA   -30.01mA
1.419V    -29.64mA   -35.66mA   -31.19mA
2.199V    -30.9mA    -37.8mA    -32.7mA
[Ramp]
R_load=50.000Ohm
dV/dt_r   410.850mV/56.500ps  405.868mV/50.500ps  427.770mV/57.500ps
dV/dt_f   410.850mV/60.000ps  405.868mV/59.000ps  427.770mV/61.000ps
[Rising waveform]
R_fixture=50.000Ohm
V_fixture=1.100
V_fixture_min=1.060
V_fixture_max=1.170
0s        412.4mV    379.8mV    452.3mV
8ps       505.8mV    455.2mV    541mV
21ps      672.4mV    624.8mV    708.3mV
35ps      808.2mV    774.1mV    853.1mV
41ps      853.8mV    823.4mV    901.9mV
53ps      926mV      898.3mV    979.1mV
70ps      994.3mV    966.8mV    1.053V
91ps      1.043V     1.013V     1.107V
127ps     1.081V     1.045V     1.148V
234ps     1.099V     1.06V      1.169V
[Rising waveform]
R_fixture=50.000Ohm
V_fixture=0
0s        -2.867mV   -2.481mV   -5.98mV
4ps       3.573mV    -2.481mV   18.7mV
13ps      80.39mV    63mV       107.6mV
30ps      254mV      234.4mV    279.9mV
44ps      370.5mV    365.8mV    394.6mV
63ps      482mV      493mV      508.5mV
83ps      559mV      573.5mV    588.6mV
109ps     618.8mV    628.8mV    648.8mV
134ps     649.3mV    654.1mV    679.9mV
237ps     681.5mV    676.1mV    712.2mV
[Falling waveform]
R_fixture=50.000Ohm
V_fixture=1.100
V_fixture_min=1.060
V_fixture_max=1.170
0s        1.104V     1.062V     1.175V
13ps      1.104V     1.062V     1.152V
31ps      1.003V     997.4mV    1.017V
48ps      870mV      894.1mV    876.7mV
68ps      720.5mV    742mV      733.9mV
86ps      619.1mV    619.1mV    640mV
104ps     548mV      532.7mV    574.5mV
130ps     484.3mV    457.8mV    519.2mV
158ps     448.9mV    418.9mV    488.7mV
247ps     418.2mV    387.9mV    461.8mV
[Falling waveform]
R_fixture=50.000Ohm
V_fixture=0
0s        686.1mV    679.8mV    719.1mV
10ps      686.1mV    679.8mV    707.4mV
22ps      596.3mV    628.3mV    604.2mV
40ps      400.1mV    468.9mV    403.6mV
54ps      275.5mV    329.7mV    278.2mV
69ps      181.2mV    214mV      184.1mV
86ps      110.8mV    128.6mV    113.6mV
106ps     62.39mV    69.53mV    64.58mV
141ps     22.62mV    23.97mV    23.78mV
244ps     1.129mV    1.262mV    1.201mV
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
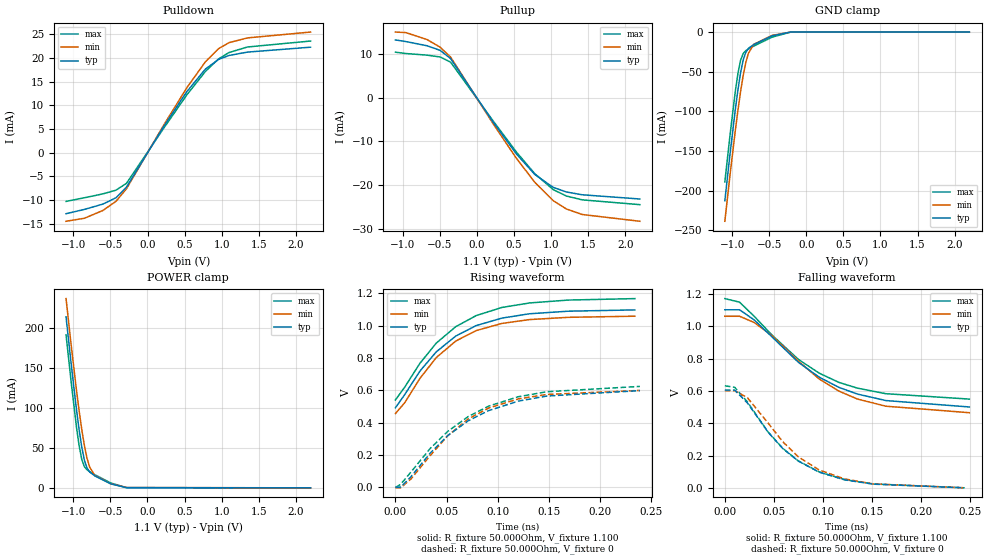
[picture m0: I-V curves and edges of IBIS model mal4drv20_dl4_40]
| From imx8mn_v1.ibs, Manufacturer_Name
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[Model] mal4drv20_dl4_40
Model_type   I/O
Polarity   Non-Inverting
Enable   Active-High
C_comp   1.694pF   1.685pF   1.701pF
C_comp_pullup   740.500fF   727.408fF   745.615fF
C_comp_pulldown 903.226fF   891.311fF   923.097fF
Vinh = 366.000mV
Vinl = 246.000mV
Vmeas = 306.000mV
Vref = 306.000mV
Rref = 50Ohms
Cref = 5pF
[Model Spec]
Vinh   366.000mV   354.000mV   385.000mV
Vinl   246.000mV   234.000mV   265.000mV
Vmeas   306.000mV   294.000mV   325.000mV
Vref   306.000mV   294.000mV   325.000mV
D_overshoot_ampl_h 0.3 NA   NA
D_overshoot_ampl_l 0.3 NA   NA
D_overshoot_area_l 100.000m NA   NA
D_overshoot_area_h 100.000m NA   NA
|[Receiver Thresholds]
|Vth = 306.000mV
|Vth_min = 294.000mV
|Vth_max = 325.000mV
|Vinh_ac = 600.000mV
|Vinh_dc = 600.000mV
|Vinl_ac = -600.000mV
|Vinl_dc = -600.000mV
|Tslew_ac = 5.000ns
|Threshold_sensitivity = 0.5
|Reference_supply Pullup_ref
[Temperature Range]   25.000   125.000   -40.000
[Voltage Range]   1.100V   1.060V   1.170V
[GND Clamp Reference]   0.00V   0.00V   0.00V
|[C Comp Corner]
|| variable   typ   min   max
|C_comp 1.701pF   1.685pF   1.694pF
|C_comp_pullup 745.615fF   727.408fF   740.500fF
|C_comp_pulldown 903.226fF   923.097fF   891.311fF
[Pulldown Reference]   0.00V   0.00V   0.00V
[POWER Clamp Reference]   1.100V   1.060V   1.170V
[Pullup Reference]   1.100V   1.060V   1.170V
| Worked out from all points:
|   slope of the pulldown table from 0 to 0.165 V, typ, clamps not added: 39.2 ohm
|   slope of the pullup table from 0 to 0.165 V, typ, clamps not added: 39.2 ohm
|   GND clamp passes 1 mA (typ) near -0.33 V on its own axis
|   POWER clamp passes 1 mA (typ) near -0.36 V on its own axis
|   rising waveform, R_fixture 50.000Ohm, V_fixture 1.100: 20-80 % time 57.6ps typ, 53.6ps min, 58.6ps max; typ from 0.492 V to 1.1 V
|   rising waveform, R_fixture 50.000Ohm, V_fixture 0: 20-80 % time 70.5ps typ, 62.9ps min, 71.1ps max; typ from 0 V to 0.598 V
|   falling waveform, R_fixture 50.000Ohm, V_fixture 1.100: 20-80 % time 76.1ps typ, 73.1ps min, 75.8ps max; typ from 1.1 V to 0.502 V
|   falling waveform, R_fixture 50.000Ohm, V_fixture 0: 20-80 % time 59.6ps typ, 58.5ps min, 60.1ps max; typ from 0.606 V to 0.002 V
[GND Clamp]
-1.099V   -213mA     -238.8mA   -189.3mA
-1.028V   -153mA     -179.5mA   -129.1mA
-957.3mV  -97.39mA   -123.9mA   -74.45mA
-921.8mV  -72.55mA   -98.33mA   -51.84mA
-886.4mV  -51.19mA   -74.9mA    -35.5mA
-850.9mV  -35.09mA   -54.48mA   -27.05mA
-815.5mV  -25.37mA   -38.12mA   -23.48mA
-780mV    -20.49mA   -26.59mA   -21.33mA
-709.1mV  -15.78mA   -15.51mA   -17.7mA
-460.9mV  -4.751mA   -4.194mA   -6.404mA
-212.7mV  -50.02uA   -89.63uA   -120.8uA
2.198V    95.2nA     1.084uA    26.44nA
[Power Clamp]
-1.098V   213.3mA    236.1mA    191mA
-1.027V   152.9mA    176.5mA    130.3mA
-956.4mV  96.88mA    121mA      75.05mA
-920.9mV  71.89mA    95.56mA    52.08mA
-885.5mV  50.44mA    72.4mA     35.26mA
-850mV    34.32mA    52.42mA    26.32mA
-814.5mV  24.6mA     36.64mA    22.47mA
-779.1mV  19.69mA    25.68mA    20.17mA
-708.2mV  14.83mA    15.14mA    16.3mA
-495.5mV  4.984mA    5.083mA    6.064mA
-282.7mV  164.9uA    413uA      201.8uA
2.199V    -54.52nA   -1.101uA   -12.05nA
[Pulldown]
-1.099V   -12.9mA    -14.5mA    -10.3mA
-850.9mV  -11.99mA   -13.86mA   -9.53mA
-602.7mV  -10.87mA   -12.22mA   -8.71mA
-425.5mV  -9.53mA    -10.28mA   -7.927mA
-283.6mV  -7.274mA   -7.619mA   -6.472mA
212.7mV   5.406mA    5.697mA    5.057mA
531.8mV   12.94mA    13.77mA    12.26mA
780mV     17.67mA    19.21mA    17.17mA
957.3mV   19.71mA    21.99mA    19.82mA
1.099V    20.55mA    23.26mA    21.17mA
1.347V    21.26mA    24.26mA    22.34mA
2.198V    22.3mA     25.5mA     23.6mA
[Pullup]
-1.098V   13.3mA     15.11mA    10.49mA
-956.4mV  12.92mA    14.98mA    10.18mA
-672.7mV  11.97mA    13.39mA    9.809mA
-495.5mV  10.91mA    11.64mA    9.394mA
-353.6mV  9.007mA    9.363mA    8.189mA
213.6mV   -5.425mA   -5.78mA    -5.149mA
532.7mV   -12.85mA   -13.86mA   -12.42mA
780.9mV   -17.56mA   -19.36mA   -17.39mA
1.029V    -20.53mA   -23.57mA   -21.04mA
1.206V    -21.58mA   -25.48mA   -22.51mA
1.419V    -22.23mA   -26.75mA   -23.39mA
2.199V    -23.2mA    -28.31mA   -24.5mA
[Ramp]
R_load=50.000Ohm
dV/dt_r   362.730mV/66.000ps  360.808mV/60.000ps  376.650mV/66.500ps
dV/dt_f   362.730mV/70.500ps  360.808mV/67.500ps  376.650mV/70.500ps
[Rising waveform]
R_fixture=50.000Ohm
V_fixture=1.100
V_fixture_min=1.060
V_fixture_max=1.170
0s        491.8mV    456mV      540.2mV
9ps       572.7mV    522.6mV    618.9mV
24ps      719.5mV    674.3mV    767.8mV
40ps      838.7mV    803.1mV    892.8mV
59ps      936mV      905.3mV    994.3mV
79ps      1.001V     970mV      1.063V
104ps     1.047V     1.014V     1.113V
131ps     1.074V     1.038V     1.141V
169ps     1.09V      1.052V     1.159V
234ps     1.098V     1.059V     1.168V
[Rising waveform]
R_fixture=50.000Ohm
V_fixture=0
0s        -179.9uV   -4.438mV   -2.045mV
5ps       -179.9uV   -4.438mV   16.61mV
15ps      63.3mV     49.4mV     92.32mV
34ps      210.9mV    195.6mV    239.6mV
51ps      318.7mV    317.6mV    344.8mV
71ps      410.3mV    421.9mV    436.5mV
91ps      473.7mV    489.7mV    501.6mV
120ps     532.7mV    546.5mV    559.9mV
148ps     564.3mV    574.2mV    591mV
239ps     597.9mV    599.1mV    624mV
[Falling waveform]
R_fixture=50.000Ohm
V_fixture=1.100
V_fixture_min=1.060
V_fixture_max=1.170
0s        1.102V     1.062V     1.171V
15ps      1.102V     1.062V     1.149V
30ps      1.039V     1.023V     1.061V
48ps      934.9mV    941.8mV    946mV
75ps      777mV      784.6mV    795.1mV
96ps      686.3mV    674.9mV    710.9mV
116ps     623.2mV    600.3mV    653.9mV
135ps     581.5mV    550.7mV    618mV
164ps     541.4mV    506.4mV    583.7mV
249ps     501.8mV    466.4mV    550.4mV
[Falling waveform]
R_fixture=50.000Ohm
V_fixture=0
0s        605.8mV    602.3mV    632.3mV
10ps      605.8mV    602.3mV    623.3mV
23ps      526.5mV    559.1mV    533mV
44ps      346.6mV    402.6mV    347.7mV
59ps      244.9mV    287.1mV    246.1mV
75ps      167.1mV    192.9mV    168.1mV
96ps      99.31mV    112.8mV    100.8mV
122ps     51.64mV    57.13mV    53.29mV
151ps     25.12mV    26.7mV     26.43mV
244ps     2.344mV    2.403mV    2.629mV
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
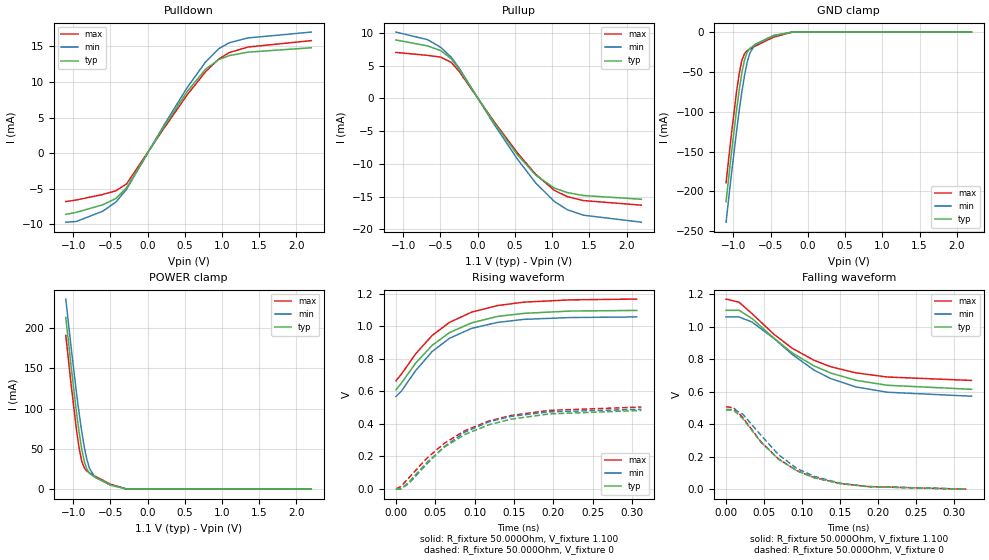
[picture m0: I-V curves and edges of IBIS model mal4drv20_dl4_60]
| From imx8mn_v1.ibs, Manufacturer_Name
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[Model] mal4drv20_dl4_60
Model_type   I/O
Polarity   Non-Inverting
Enable   Active-High
C_comp   1.694pF   1.685pF   1.701pF
C_comp_pullup   740.500fF   727.408fF   745.615fF
C_comp_pulldown 903.226fF   891.311fF   923.097fF
Vinh = 310.000mV
Vinl = 190.000mV
Vmeas = 250.000mV
Vref = 250.000mV
Rref = 50Ohms
Cref = 5pF
[Model Spec]
Vinh   310.000mV   301.000mV   326.000mV
Vinl   190.000mV   181.000mV   206.000mV
Vmeas   250.000mV   241.000mV   266.000mV
Vref   250.000mV   241.000mV   266.000mV
D_overshoot_ampl_h 0.3 NA   NA
D_overshoot_ampl_l 0.3 NA   NA
D_overshoot_area_l 100.000m NA   NA
D_overshoot_area_h 100.000m NA   NA
|[Receiver Thresholds]
|Vth = 250.000mV
|Vth_min = 241.000mV
|Vth_max = 266.000mV
|Vinh_ac = 600.000mV
|Vinh_dc = 600.000mV
|Vinl_ac = -600.000mV
|Vinl_dc = -600.000mV
|Tslew_ac = 5.000ns
|Threshold_sensitivity = 0.5
|Reference_supply Pullup_ref
[Temperature Range]   25.000   125.000   -40.000
[Voltage Range]   1.100V   1.060V   1.170V
[GND Clamp Reference]   0.00V   0.00V   0.00V
|[C Comp Corner]
|| variable   typ   min   max
|C_comp 1.701pF   1.685pF   1.694pF
|C_comp_pullup 745.615fF   727.408fF   740.500fF
|C_comp_pulldown 903.226fF   923.097fF   891.311fF
[Pulldown Reference]   0.00V   0.00V   0.00V
[POWER Clamp Reference]   1.100V   1.060V   1.170V
[Pullup Reference]   1.100V   1.060V   1.170V
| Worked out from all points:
|   slope of the pulldown table from 0 to 0.165 V, typ, clamps not added: 58.6 ohm
|   slope of the pullup table from 0 to 0.165 V, typ, clamps not added: 58.6 ohm
|   GND clamp passes 1 mA (typ) near -0.33 V on its own axis
|   POWER clamp passes 1 mA (typ) near -0.36 V on its own axis
|   rising waveform, R_fixture 50.000Ohm, V_fixture 1.100: 20-80 % time 69.4ps typ, 65.3ps min, 70.2ps max; typ from 0.609 V to 1.1 V
|   rising waveform, R_fixture 50.000Ohm, V_fixture 0: 20-80 % time 86.2ps typ, 77.1ps min, 86.7ps max; typ from -0.003 V to 0.482 V
|   falling waveform, R_fixture 50.000Ohm, V_fixture 1.100: 20-80 % time 93.4ps typ, 89.1ps min, 91.8ps max; typ from 1.1 V to 0.616 V
|   falling waveform, R_fixture 50.000Ohm, V_fixture 0: 20-80 % time 71.1ps typ, 69.9ps min, 71.6ps max; typ from 0.487 V to 0.001 V
[GND Clamp]
-1.099V   -213mA     -238.8mA   -189.3mA
-1.028V   -153mA     -179.5mA   -129.1mA
-957.3mV  -97.39mA   -123.9mA   -74.45mA
-921.8mV  -72.55mA   -98.33mA   -51.84mA
-886.4mV  -51.19mA   -74.9mA    -35.5mA
-850.9mV  -35.09mA   -54.48mA   -27.05mA
-815.5mV  -25.37mA   -38.12mA   -23.48mA
-780mV    -20.49mA   -26.59mA   -21.33mA
-709.1mV  -15.78mA   -15.51mA   -17.7mA
-460.9mV  -4.751mA   -4.194mA   -6.404mA
-212.7mV  -50.02uA   -89.63uA   -120.8uA
2.198V    95.2nA     1.084uA    26.44nA
[Power Clamp]
-1.098V   213.3mA    236.1mA    191mA
-1.027V   152.9mA    176.5mA    130.3mA
-956.4mV  96.88mA    121mA      75.05mA
-920.9mV  71.89mA    95.56mA    52.08mA
-885.5mV  50.44mA    72.4mA     35.26mA
-850mV    34.32mA    52.42mA    26.32mA
-814.5mV  24.6mA     36.64mA    22.47mA
-779.1mV  19.69mA    25.68mA    20.17mA
-708.2mV  14.83mA    15.14mA    16.3mA
-495.5mV  4.984mA    5.083mA    6.064mA
-282.7mV  164.9uA    413uA      201.8uA
2.199V    -54.52nA   -1.101uA   -12.05nA
[Pulldown]
-1.099V   -8.6mA     -9.7mA     -6.8mA
-957.3mV  -8.31mA    -9.6mA     -6.58mA
-602.7mV  -7.26mA    -8.156mA   -5.81mA
-425.5mV  -6.365mA   -6.868mA   -5.287mA
-283.6mV  -4.86mA    -5.092mA   -4.323mA
212.7mV   3.612mA    3.807mA    3.379mA
531.8mV   8.645mA    9.204mA    8.189mA
780mV     11.8mA     12.83mA    11.46mA
957.3mV   13.15mA    14.68mA    13.23mA
1.099V    13.7mA     15.51mA    14.13mA
1.347V    14.18mA    16.18mA    14.9mA
2.198V    14.8mA     17mA       15.8mA
[Pullup]
-1.098V   8.9mA      10.1mA     6.997mA
-672.7mV  7.99mA     8.946mA    6.549mA
-495.5mV  7.276mA    7.768mA    6.276mA
-353.6mV  6.017mA    6.253mA    5.468mA
-247.3mV  4.371mA    4.584mA    4.082mA
213.6mV   -3.625mA   -3.862mA   -3.439mA
532.7mV   -8.586mA   -9.257mA   -8.297mA
780.9mV   -11.72mA   -12.93mA   -11.61mA
1.029V    -13.69mA   -15.73mA   -14.04mA
1.206V    -14.39mA   -17mA      -15.01mA
1.419V    -14.83mA   -17.83mA   -15.6mA
2.199V    -15.4mA    -18.9mA    -16.3mA
[Ramp]
R_load=50.000Ohm
dV/dt_r   292.260mV/79.000ps  294.477mV/73.000ps  302.670mV/80.000ps
dV/dt_f   292.260mV/84.500ps  294.477mV/82.000ps  302.670mV/83.500ps
[Rising waveform]
R_fixture=50.000Ohm
V_fixture=1.100
V_fixture_min=1.060
V_fixture_max=1.170
0s        609.4mV    568.2mV    664.8mV
7ps       650.9mV    602mV      706.3mV
25ps      773.8mV    727.6mV    830.7mV
46ps      883.6mV    845.4mV    944.5mV
68ps      961.8mV    926.8mV    1.025V
96ps      1.022V     988mV      1.088V
129ps     1.062V     1.025V     1.129V
163ps     1.081V     1.044V     1.15V
221ps     1.095V     1.055V     1.164V
306ps     1.099V     1.059V     1.169V
[Rising waveform]
R_fixture=50.000Ohm
V_fixture=0
0s        -2.813mV   -2.337mV   -488.5uV
6ps       -2.813mV   -2.337mV   12.63mV
17ps      43.9mV     34.88mV    69.78mV
39ps      160.7mV    151.2mV    186.6mV
61ps      254.5mV    258.2mV    278.1mV
88ps      335.2mV    349.9mV    358.9mV
118ps     393.8mV    412mV      417.1mV
146ps     428.4mV    445.6mV    451.1mV
195ps     461.1mV    473.9mV    482.8mV
312ps     482.4mV    489.6mV    503.4mV
[Falling waveform]
R_fixture=50.000Ohm
V_fixture=1.100
V_fixture_min=1.060
V_fixture_max=1.170
0s        1.102V     1.061V     1.171V
17ps      1.102V     1.061V     1.152V
34ps      1.052V     1.03V      1.082V
63ps      930.5mV    929mV      954.3mV
87ps      840.2mV    830.6mV    868.4mV
116ps     759.2mV    733.1mV    793.8mV
138ps     715.3mV    681.3mV    754mV
171ps     671.1mV    630.2mV    716.8mV
212ps     640.5mV    597.7mV    691.3mV
323ps     615.7mV    573.1mV    670.2mV
[Falling waveform]
R_fixture=50.000Ohm
V_fixture=0
0s        487.3mV    491.6mV    508.5mV
10ps      487.3mV    491.6mV    502mV
22ps      435mV      463.1mV    442.2mV
46ps      290.6mV    332.8mV    291.6mV
69ps      185.8mV    213.3mV    186.9mV
93ps      114.7mV    129.2mV    115.6mV
116ps     71.57mV    79.67mV    72.16mV
151ps     34.63mV    37.33mV    35.03mV
187ps     16.27mV    17.07mV    16.94mV
316ps     1.037mV    1.056mV    1.102mV
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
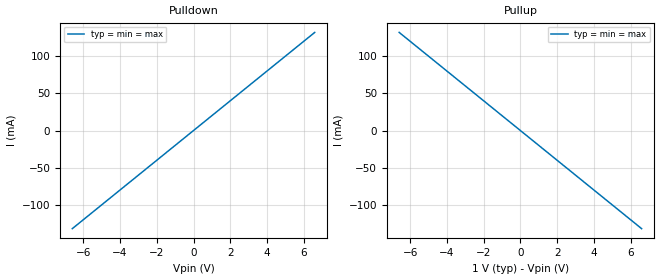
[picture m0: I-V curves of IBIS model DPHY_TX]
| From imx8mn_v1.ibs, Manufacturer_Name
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[Model] DPHY_TX
Model_type Output
C_comp 0p 0p 0p
Cref = 0
Vref = 0.5
Rref = 50
Vmeas = 0.5
[Temperature_Range] 25 125 0
[Voltage Range] 1.0 1.0 1.0
[Algorithmic Model]
Executable Windows_cl16.00.40219.01_64 DPHY_TX_x64.dll DPHY_TX.ami
Executable Windows_cl16.00.40219.01_32 DPHY_TX.dll DPHY_TX.ami
[End Algorithmic Model]
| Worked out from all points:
|   slope of the pulldown table from 0 to 0.15 V, typ, clamps not added: 50 ohm
|   slope of the pullup table from 0 to 0.15 V, typ, clamps not added: 50 ohm
[Pulldown]
-6.6V     -132mA     -132mA     -132mA
0V        0A         0A         0A
6.6V      132mA      132mA      132mA
[Pullup]
-6.6V     132mA      132mA      132mA
0V        0A         0A         0A
6.6V      -132mA     -132mA     -132mA
[GND Clamp]
-6.6V     0A         0A         0A
0V        0A         0A         0A
6.6V      0A         0A         0A
[Power Clamp]
-6.6V     0A         0A         0A
0V        0A         0A         0A
6.6V      0A         0A         0A
[Ramp]
dV/dt_r 1.0/5p 1.0/5p 1.0/5p
dV/dt_f 1.0/5p 1.0/5p 1.0/5p
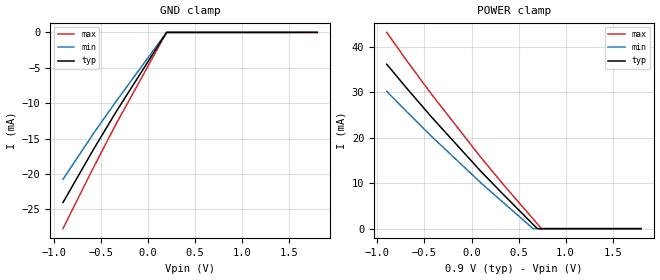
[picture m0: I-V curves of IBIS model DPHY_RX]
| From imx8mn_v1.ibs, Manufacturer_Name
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[Model]   DPHY_RX
Model_type   Input
Vinl = 0.13
Vinh = 0.27
|   typ   min   max
C_comp   1pF   1pF   1pF
[Voltage Range]   0.9   0.855   0.945
[Temperature Range]   25   -40   85
[Power Clamp Reference]   0.9   0.855   0.945
[GND Clamp Reference]   0   0   0
[GND Clamp]
|   Voltage   I(typ)   I(min)   I(max)
-900.9mV  -24.03mA   -20.76mA   -27.73mA
-582.8mV  -16.67mA   -14.4mA    -19.25mA
-340.6mV  -11.31mA   -9.82mA    -13.04mA
200mV     -3.304uA   -4.015uA   -427.4nA
1.802V    0A         0A         0A
[POWER Clamp]
|   Voltage   I(typ)   I(min)   I(max)
-900.9mV  36.21mA    30.24mA    43.22mA
-688.3mV  30.92mA    25.75mA    37mA
-427.5mV  24.64mA    20.37mA    29.67mA
102.6mV   12.55mA    10.04mA    15.62mA
342mV     7.457mA    5.669mA    9.639mA
655.2mV   930uA      0A         2.137mA
700.2mV   0A         0A         1.067mA
745.2mV   0A         0A         0A
1.802V    0A         0A         0A
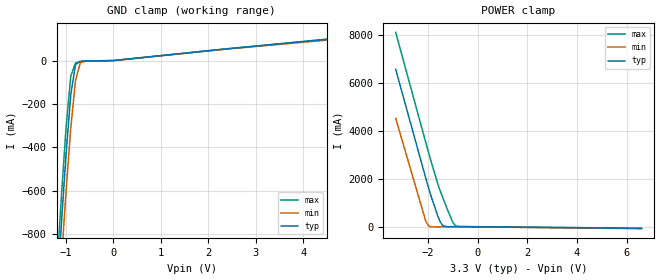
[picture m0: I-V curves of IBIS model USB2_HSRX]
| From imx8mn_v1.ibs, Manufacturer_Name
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[Model] USB2_HSRX
Model_type   Input
Polarity   Non-Inverting
Enable   Active-High
C_comp   8.346pF   8.035pF   8.838pF
Vinh = 150.000mV
Vinl = -150.000mV
[Model Spec]
[Receiver Thresholds]
Vcross_low = 0
Vcross_high = 500mv
Vdiff_ac = 150mv
Vdiff_dc = 100mv
Tdiffslew_ac = 1200ps
[Temperature Range]   25.000   125.000   -40.000
[Voltage Range]   3.300V   2.790V   3.630V
[GND Clamp Reference]   0.00V   0.00V   0.00V
[POWER Clamp Reference]   3.300V   2.790V   3.630V
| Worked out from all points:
|   GND clamp passes 1 mA (typ) near -0.51 V on its own axis
|   POWER clamp passes 1 mA (typ) near -0.51 V on its own axis
[GND Clamp]
-3.3V     -9.043A    -9.157A    -8.963A
-1.2V     -1.11A     -1.28A     -986.1mA
-1.1V     -761.7mA   -934.6mA   -635mA
-1V       -434mA     -606.1mA   -311.5mA
-900mV    -158.3mA   -310.5mA   -72.59mA
-800mV    -18.52mA   -91.77mA   -10.69mA
-700mV    -2.749mA   -10.65mA   -5.624mA
-600mV    -1.534mA   -1.333mA   -3.325mA
1.971fV   0A         0A         0A
2.3V      52.38mA    51.18mA    51.98mA
6.6V      140.5mA    135.1mA    143.5mA
[Power Clamp]
-3.3V     6.566A     4.518A     8.108A
-2.1V     2.062A     261.5mA    3.556A
-2V       1.7A       58.33mA    3.183A
-1.9V     1.346A     -13.31mA   2.813A
-1.6V     419.4mA    -17.82mA   1.769A
-1.5V     188.5mA    -16.36mA   1.475A
-1.4V     28.52mA    -14.9mA    1.199A
-1.2V     -5.874mA   -11.95mA   666.7mA
-1V       -3.573mA   -8.988mA   181.6mA
-900mV    -2.631mA   -7.522mA   39.28mA
-800mV    -1.929mA   -6.099mA   2.896mA
6.6V      -76.17mA   -87.51mA   -67.53mA
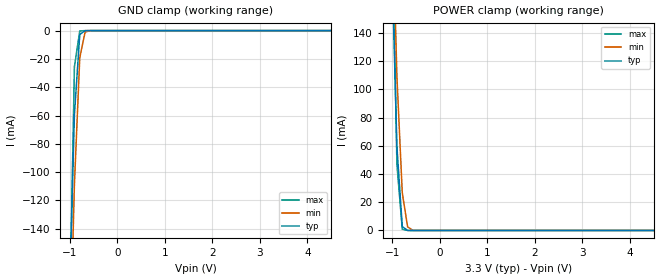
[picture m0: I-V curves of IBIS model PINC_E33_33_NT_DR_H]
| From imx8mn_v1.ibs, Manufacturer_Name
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[Model] PINC_E33_33_NT_DR_H
Model_type Input
Vinl  =  0.99
Vinh  =  2.31
| Capacitance   typ   min   max
C_comp   8.44875397035e-13   8.24333084942e-13   8.53044968395e-13
| Variables   typ   min   max
[GND Clamp Reference]   0   0   0
[POWER Clamp Reference]   3.3   3   3.6
[Pulldown Reference]   0   0   0
[Pullup Reference]   3.3   3   3.6
[Temperature Range]   25   125   -40
[Voltage Range]   3.3   3   3.6
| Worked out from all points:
|   GND clamp passes 1 mA (typ) near -0.71 V on its own axis
|   POWER clamp passes 1 mA (typ) near -0.71 V on its own axis
[GND Clamp]
| Voltage   I(typ)   I(min)   I(max)
-3.3V     -6.977A    -6.284A    -7.761A
-1.012V   -197.9mA   -250.9mA   -222.8mA
-900mV    -59.34mA   -108.6mA   -25.52mA
-787.5mV  -2.762mA   -19.05mA   -223.6uA
-675mV    -55.21uA   -1.001mA   -30.59uA
-562.5mV  -9.766uA   -43.8uA    -17.22uA
6.6V      0A         0A         0A
[POWER Clamp]
| Voltage   I(typ)   I(min)   I(max)
-3.3V     6.977A     6.284A     7.765A
-1.012V   197.7mA    246.7mA    240.8mA
-900mV    59.47mA    109mA      46.99mA
-787.5mV  2.764mA    26.73mA    875.9uA
-675mV    38.48uA    2.517mA    15.31uA
-562.5mV  787.5nA    56.29uA    4.385uA
6.6V      0A         0A         0A
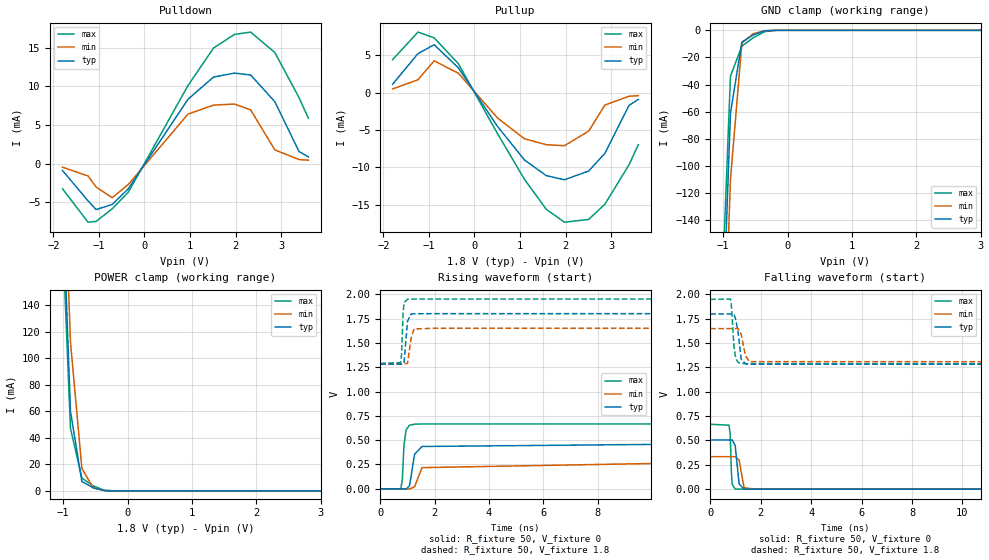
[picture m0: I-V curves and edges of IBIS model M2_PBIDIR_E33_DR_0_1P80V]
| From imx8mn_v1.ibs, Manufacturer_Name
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[Model] M2_PBIDIR_E33_DR_0_1P80V
Model_type I/O
Vinl  =  0.54
Vinh  =  1.26
Vmeas =  0.9
| Capacitance   typ   min   max
C_comp   8.99140471561e-13   8.21462742958e-13   9.40633374847e-13
| Variables   typ   min   max
[GND Clamp Reference]   0   0   0
[POWER Clamp Reference]   1.8   1.65   1.95
[Pulldown Reference]   0   0   0
[Pullup Reference]   1.8   1.65   1.95
[Temperature Range]   25   125   -40
[Voltage Range]   1.8   1.65   1.95
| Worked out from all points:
|   slope of the pulldown table from 0 to 0.27 V, typ, clamps not added: 109 ohm
|   slope of the pullup table from 0 to 0.27 V, typ, clamps not added: 110 ohm
|   GND clamp passes 1 mA (typ) near -0.39 V on its own axis
|   POWER clamp passes 1 mA (typ) near -0.43 V on its own axis
|   falling waveform, R_fixture 50, V_fixture 0: 20-80 % time 111ps typ, 115ps min, 51.1ps max; typ from 0.505 V to 0 V
|   falling waveform, R_fixture 50, V_fixture 1.8: 20-80 % time 139ps typ, 174ps min, 101ps max; typ from 1.8 V to 1.28 V
|   rising waveform, R_fixture 50, V_fixture 0: 20-80 % time 224ps typ, 536ps min, 82.2ps max; typ from 0 V to 0.492 V
|   rising waveform, R_fixture 50, V_fixture 1.8: 20-80 % time 69.7ps typ, 78.1ps min, 51.4ps max; typ from 1.28 V to 1.8 V
[GND Clamp]
| Voltage   I(typ)   I(min)   I(max)
-1.8V     -1.562A    -1.614A    -1.516A
-1.064V   -296mA     -355.2mA   -250.4mA
-886.4mV  -61.18mA   -109.9mA   -33.74mA
-709.1mV  -8.602mA   -9.384mA   -11.67mA
-531.8mV  -3.4mA     -2.481mA   -5.473mA
-354.5mV  -361.2uA   -272.6uA   -975.8uA
-177.3mV  -1.362uA   -3.436uA   -2.724uA
3.6V      0A         0A         0A
[POWER Clamp]
| Voltage   I(typ)   I(min)   I(max)
-1.8V     1.563A     1.607A     1.521A
-1.064V   296.1mA    350.6mA    257.7mA
-886.4mV  60.03mA    112.2mA    47.22mA
-709.1mV  7.094mA    16.96mA    9.663mA
-531.8mV  2.299mA    2.209mA    3.776mA
-354.5mV  136.5uA    326.9uA    430.1uA
-177.3mV  338.8nA    11.95uA    535.8nA
3.6V      0A         0A         0A
[Pulldown]
| Voltage   I(typ)   I(min)   I(max)
-1.8V     -907.9uA   -480.6uA   -3.27mA
-1.241V   -4.822mA   -1.6mA     -7.583mA
-1.064V   -5.953mA   -3.021mA   -7.483mA
-709.1mV  -5.289mA   -4.421mA   -5.854mA
-354.5mV  -3.257mA   -2.701mA   -3.696mA
956.3mV   8.318mA    6.398mA    10.09mA
1.519V    11.19mA    7.562mA    14.95mA
1.977V    11.7mA     7.693mA    16.7mA
2.332V    11.45mA    6.945mA    17mA
2.864V    8.001mA    1.765mA    14.36mA
3.395V    1.564mA    518.9uA    8.539mA
3.6V      868.9uA    436.5uA    5.864mA
[Pullup]
| Voltage   I(typ)   I(min)   I(max)
-1.8V     1.123mA    505.2uA    4.414mA
-1.241V   5.233mA    1.734mA    8.115mA
-886.4mV  6.422mA    4.267mA    7.345mA
-354.5mV  3.331mA    2.605mA    3.881mA
506.2mV   -4.515mA   -3.386mA   -5.491mA
1.097V    -9.001mA   -6.169mA   -11.59mA
1.575V    -11.1mA    -6.962mA   -15.6mA
1.977V    -11.66mA   -7.099mA   -17.34mA
2.509V    -10.49mA   -5.15mA    -16.97mA
2.864V    -8.13mA    -1.661mA   -14.94mA
3.395V    -1.708mA   -477.2uA   -9.663mA
3.6V      -899.4uA   -397.7uA   -6.967mA
[Ramp]
dV/dt_r   0.295342/0.224144n  0.194516/0.53575n  0.399949/82.1832p
dV/dt_f   0.311098/0.138924n  0.220378/0.173511n  0.396442/0.101357n
R_load = 50
[Falling Waveform]
R_fixture = 50
V_fixture = 0
V_fixture_min = 0
V_fixture_max = 0
| Time   V(typ)   V(min)   V(max)
0s        505mV      333.7mV    666.6mV
745.2ps   505mV      333.7mV    657.3mV
786.9ps   504.9mV    333.7mV    571.8mV
838.4ps   505.2mV    333.7mV    170.9mV
870.2ps   505.3mV    333.7mV    48.99mV
987.7ps   448.1mV    333.9mV    1.415mV
1.144ns   52.7mV     299.4mV    298uV
1.34ns    434.6uV    14.55mV    98.54uV
1.743ns   83.7uV     226.9uV    39.26uV
333.3ns   251.3nV    1.176uV    236.6nV
[Falling Waveform]
R_fixture = 50
V_fixture = 1.8
V_fixture_min = 1.65
V_fixture_max = 1.95
| Time   V(typ)   V(min)   V(max)
0s        1.8V       1.65V      1.95V
803.8ps   1.8V       1.65V      1.953V
836.8ps   1.8V       1.65V      1.886V
938.9ps   1.799V     1.65V      1.467V
1.008ns   1.745V     1.65V      1.341V
1.106ns   1.607V     1.65V      1.301V
1.225ns   1.337V     1.591V     1.292V
1.392ns   1.289V     1.373V     1.29V
1.553ns   1.284V     1.31V      1.289V
333.3ns   1.282V     1.283V     1.289V
[Rising Waveform]
R_fixture = 50
V_fixture = 0
V_fixture_min = 0
V_fixture_max = 0
| Time   V(typ)   V(min)   V(max)
0s        154.7nV    1.146uV    177nV
755.6ps   -66.11uV   222.4nV    -114.5uV
812.2ps   -114.3uV   153.1nV    96.18mV
871.9ps   -1.175mV   -48.55uV   449.3mV
950.9ps   -3.663mV   -141.3uV   606.3mV
1.076ns   30.44mV    -1.861mV   653.3mV
1.262ns   354.5mV    20.66mV    664mV
1.536ns   435mV      217.6mV    666.3mV
19.73ns   480.4mV    308.8mV    666.6mV
333.3ns   492.2mV    324.2mV    666.6mV
[Rising Waveform]
R_fixture = 50
V_fixture = 1.8
V_fixture_min = 1.65
V_fixture_max = 1.95
| Time   V(typ)   V(min)   V(max)
0s        1.282V     1.283V     1.289V
747.6ps   1.281V     1.283V     1.297V
783.6ps   1.281V     1.283V     1.381V
836.2ps   1.283V     1.283V     1.786V
873.7ps   1.294V     1.283V     1.912V
1.003ns   1.723V     1.29V      1.949V
1.139ns   1.797V     1.552V     1.95V
1.244ns   1.799V     1.643V     1.95V
1.965ns   1.8V       1.65V      1.95V
333.3ns   1.8V       1.65V      1.95V
[Add Submodel]
| Submodel Name Mode
M2_PBIDIR_E33_DR_0_1P80V_T All
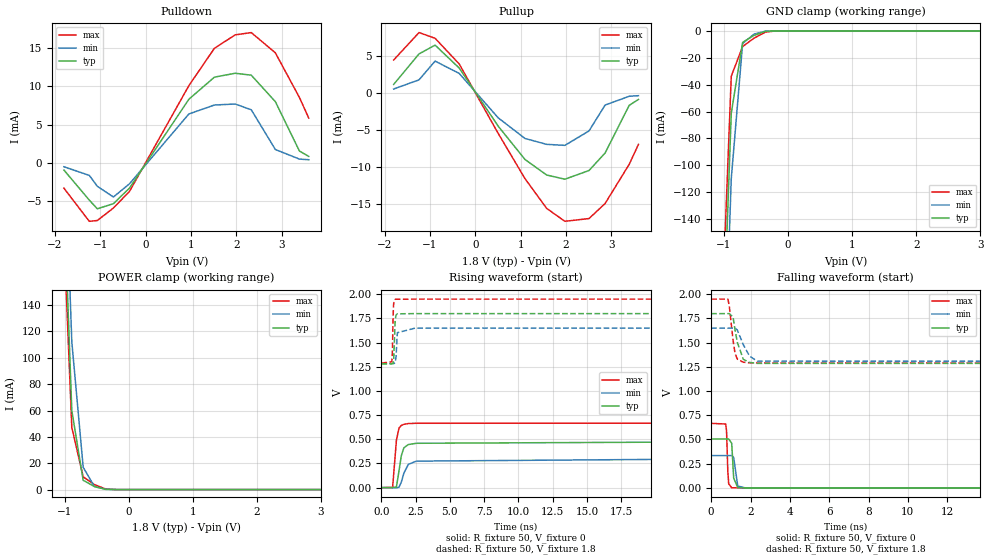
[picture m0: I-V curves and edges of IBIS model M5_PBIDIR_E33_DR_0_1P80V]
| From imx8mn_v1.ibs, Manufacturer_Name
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[Model] M5_PBIDIR_E33_DR_0_1P80V
Model_type I/O
Vinl  =  0.54
Vinh  =  1.26
Vmeas =  0.9
| Capacitance   typ   min   max
C_comp   8.99140471561e-13   8.21462742958e-13   9.40633374847e-13
| Variables   typ   min   max
[GND Clamp Reference]   0   0   0
[POWER Clamp Reference]   1.8   1.65   1.95
[Pulldown Reference]   0   0   0
[Pullup Reference]   1.8   1.65   1.95
[Temperature Range]   25   125   -40
[Voltage Range]   1.8   1.65   1.95
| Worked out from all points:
|   slope of the pulldown table from 0 to 0.27 V, typ, clamps not added: 109 ohm
|   slope of the pullup table from 0 to 0.27 V, typ, clamps not added: 110 ohm
|   GND clamp passes 1 mA (typ) near -0.39 V on its own axis
|   POWER clamp passes 1 mA (typ) near -0.43 V on its own axis
|   falling waveform, R_fixture 50, V_fixture 0: 20-80 % time 73.8ps typ, 109ps min, 63.1ps max; typ from 0.505 V to 0 V
|   falling waveform, R_fixture 50, V_fixture 1.8: 20-80 % time 313ps typ, 533ps min, 229ps max; typ from 1.8 V to 1.28 V
|   rising waveform, R_fixture 50, V_fixture 0: 20-80 % time 367ps typ, 709ps min, 233ps max; typ from 0 V to 0.492 V
|   rising waveform, R_fixture 50, V_fixture 1.8: 20-80 % time 69.6ps typ, 78.5ps min, 59.4ps max; typ from 1.28 V to 1.8 V
[GND Clamp]
| Voltage   I(typ)   I(min)   I(max)
-1.8V     -1.562A    -1.614A    -1.516A
-1.064V   -296mA     -355.2mA   -250.4mA
-886.4mV  -61.18mA   -109.9mA   -33.74mA
-709.1mV  -8.602mA   -9.384mA   -11.67mA
-531.8mV  -3.4mA     -2.481mA   -5.473mA
-354.5mV  -361.2uA   -272.6uA   -975.8uA
-177.3mV  -1.362uA   -3.436uA   -2.724uA
3.6V      0A         0A         0A
[POWER Clamp]
| Voltage   I(typ)   I(min)   I(max)
-1.8V     1.563A     1.607A     1.521A
-1.064V   296.1mA    350.6mA    257.7mA
-886.4mV  60.03mA    112.2mA    47.22mA
-709.1mV  7.094mA    16.96mA    9.663mA
-531.8mV  2.299mA    2.209mA    3.776mA
-354.5mV  136.5uA    326.9uA    430.1uA
-177.3mV  338.8nA    11.95uA    535.8nA
3.6V      0A         0A         0A
[Pulldown]
| Voltage   I(typ)   I(min)   I(max)
-1.8V     -907.9uA   -480.6uA   -3.27mA
-1.241V   -4.822mA   -1.6mA     -7.583mA
-1.064V   -5.953mA   -3.021mA   -7.483mA
-709.1mV  -5.289mA   -4.421mA   -5.854mA
-354.5mV  -3.257mA   -2.701mA   -3.696mA
956.3mV   8.318mA    6.398mA    10.09mA
1.519V    11.19mA    7.562mA    14.95mA
1.977V    11.7mA     7.693mA    16.7mA
2.332V    11.45mA    6.945mA    17mA
2.864V    8.001mA    1.765mA    14.36mA
3.395V    1.564mA    518.9uA    8.539mA
3.6V      868.9uA    436.5uA    5.864mA
[Pullup]
| Voltage   I(typ)   I(min)   I(max)
-1.8V     1.123mA    505.2uA    4.414mA
-1.241V   5.233mA    1.734mA    8.115mA
-886.4mV  6.422mA    4.267mA    7.345mA
-354.5mV  3.331mA    2.605mA    3.881mA
506.2mV   -4.515mA   -3.386mA   -5.491mA
1.097V    -9.001mA   -6.169mA   -11.59mA
1.575V    -11.1mA    -6.962mA   -15.6mA
1.977V    -11.66mA   -7.099mA   -17.34mA
2.509V    -10.49mA   -5.15mA    -16.97mA
2.864V    -8.13mA    -1.661mA   -14.94mA
3.395V    -1.708mA   -477.2uA   -9.663mA
3.6V      -899.4uA   -397.7uA   -6.967mA
[Ramp]
dV/dt_r   0.29534/0.367407n  0.19451/0.709213n  0.399949/0.232745n
dV/dt_f   0.311098/0.31288n  0.220378/0.532566n  0.396443/0.229217n
R_load = 50
[Falling Waveform]
R_fixture = 50
V_fixture = 0
V_fixture_min = 0
V_fixture_max = 0
| Time   V(typ)   V(min)   V(max)
0s        505mV      333.7mV    666.6mV
740.8ps   505mV      333.7mV    659.5mV
782.4ps   504.9mV    333.7mV    586.8mV
845.7ps   505.2mV    333.7mV    177.8mV
891.5ps   505.3mV    333.6mV    42.17mV
1.045ns   460.8mV    333.7mV    1.028mV
1.145ns   102.6mV    314.2mV    604.1uV
1.352ns   702.2uV    19.26mV    319.1uV
1.711ns   250.9uV    411uV      109.5uV
333.3ns   219.4nV    1.156uV    211.2nV
[Falling Waveform]
R_fixture = 50
V_fixture = 1.8
V_fixture_min = 1.65
V_fixture_max = 1.95
| Time   V(typ)   V(min)   V(max)
0s        1.8V       1.65V      1.95V
855.6ps   1.8V       1.65V      1.95V
920.9ps   1.8V       1.65V      1.878V
1.112ns   1.766V     1.65V      1.528V
1.214ns   1.632V     1.651V     1.39V
1.33ns    1.503V     1.631V     1.33V
1.635ns   1.328V     1.479V     1.298V
1.949ns   1.296V     1.362V     1.292V
2.336ns   1.286V     1.309V     1.29V
333.3ns   1.282V     1.283V     1.289V
[Rising Waveform]
R_fixture = 50
V_fixture = 0
V_fixture_min = 0
V_fixture_max = 0
| Time   V(typ)   V(min)   V(max)
0s        154.7nV    1.146uV    177nV
817.7ps   -198.6uV   -347.9nV   3.701mV
1.094ns   7.449mV    -2.248mV   489.6mV
1.283ns   173mV      4.037mV    617.1mV
1.448ns   328.4mV    56.71mV    642.9mV
1.641ns   412mV      150.1mV    655.3mV
1.96ns    445.4mV    240mV      662.7mV
2.546ns   458.9mV    274.3mV    666mV
41.07ns   483.9mV    313.5mV    666.6mV
333.3ns   492.2mV    324.2mV    666.6mV
[Rising Waveform]
R_fixture = 50
V_fixture = 1.8
V_fixture_min = 1.65
V_fixture_max = 1.95
| Time   V(typ)   V(min)   V(max)
0s        1.282V     1.283V     1.289V
756.5ps   1.281V     1.283V     1.301V
795.7ps   1.281V     1.283V     1.383V
856.2ps   1.288V     1.283V     1.788V
894.7ps   1.318V     1.283V     1.907V
1.004ns   1.729V     1.291V     1.948V
1.068ns   1.786V     1.355V     1.949V
1.164ns   1.798V     1.603V     1.949V
2.457ns   1.8V       1.65V      1.95V
333.3ns   1.8V       1.65V      1.95V
[Add Submodel]
| Submodel Name Mode
M5_PBIDIR_E33_DR_0_1P80V_T All
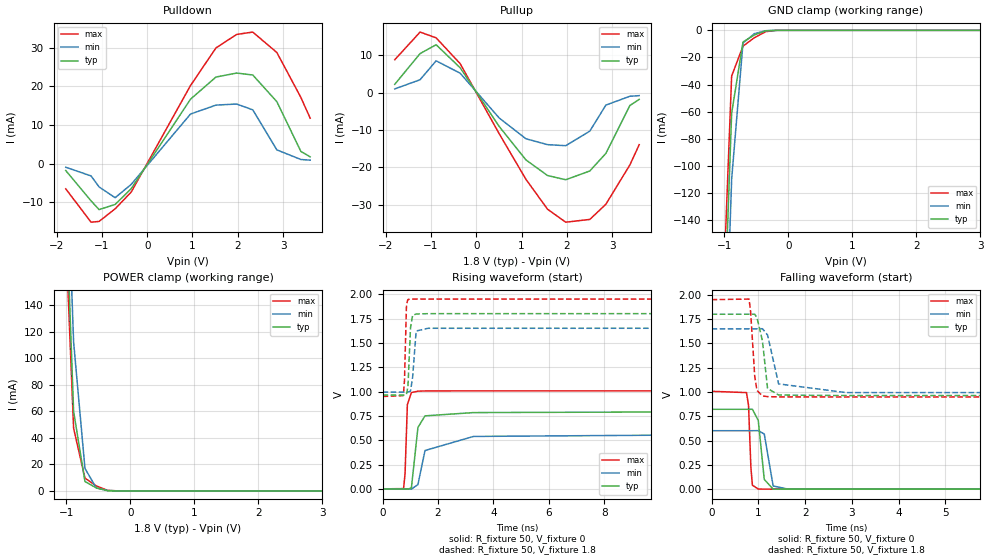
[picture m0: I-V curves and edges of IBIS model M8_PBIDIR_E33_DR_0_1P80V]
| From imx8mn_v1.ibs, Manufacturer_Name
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[Model] M8_PBIDIR_E33_DR_0_1P80V
Model_type I/O
Vinl  =  0.54
Vinh  =  1.26
Vmeas =  0.9
| Capacitance   typ   min   max
C_comp   8.99140471561e-13   8.21462742958e-13   9.40633374847e-13
| Variables   typ   min   max
[GND Clamp Reference]   0   0   0
[POWER Clamp Reference]   1.8   1.65   1.95
[Pulldown Reference]   0   0   0
[Pullup Reference]   1.8   1.65   1.95
[Temperature Range]   25   125   -40
[Voltage Range]   1.8   1.65   1.95
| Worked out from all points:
|   slope of the pulldown table from 0 to 0.27 V, typ, clamps not added: 54.5 ohm
|   slope of the pullup table from 0 to 0.27 V, typ, clamps not added: 55 ohm
|   GND clamp passes 1 mA (typ) near -0.39 V on its own axis
|   POWER clamp passes 1 mA (typ) near -0.43 V on its own axis
|   falling waveform, R_fixture 50, V_fixture 0: 20-80 % time 96ps typ, 98.7ps min, 46.5ps max; typ from 0.822 V to 0 V
|   falling waveform, R_fixture 50, V_fixture 1.8: 20-80 % time 117ps typ, 154ps min, 79.9ps max; typ from 1.8 V to 0.963 V
|   rising waveform, R_fixture 50, V_fixture 0: 20-80 % time 167ps typ, 390ps min, 63.1ps max; typ from 0 V to 0.809 V
|   rising waveform, R_fixture 50, V_fixture 1.8: 20-80 % time 71.1ps typ, 75.6ps min, 43.8ps max; typ from 0.963 V to 1.8 V
[GND Clamp]
| Voltage   I(typ)   I(min)   I(max)
-1.8V     -1.562A    -1.614A    -1.516A
-1.064V   -296mA     -355.2mA   -250.4mA
-886.4mV  -61.18mA   -109.9mA   -33.74mA
-709.1mV  -8.602mA   -9.384mA   -11.67mA
-531.8mV  -3.4mA     -2.481mA   -5.473mA
-354.5mV  -361.2uA   -272.6uA   -975.8uA
-177.3mV  -1.362uA   -3.436uA   -2.724uA
3.6V      0A         0A         0A
[POWER Clamp]
| Voltage   I(typ)   I(min)   I(max)
-1.8V     1.563A     1.607A     1.521A
-1.064V   296.1mA    350.6mA    257.7mA
-886.4mV  60.03mA    112.2mA    47.22mA
-709.1mV  7.094mA    16.96mA    9.663mA
-531.8mV  2.299mA    2.209mA    3.776mA
-354.5mV  136.5uA    326.9uA    430.1uA
-177.3mV  338.8nA    11.95uA    535.8nA
3.6V      0A         0A         0A
[Pulldown]
| Voltage   I(typ)   I(min)   I(max)
-1.8V     -1.816mA   -961.1uA   -6.54mA
-1.241V   -9.644mA   -3.2mA     -15.17mA
-1.064V   -11.91mA   -6.042mA   -14.97mA
-709.1mV  -10.58mA   -8.841mA   -11.71mA
-354.5mV  -6.515mA   -5.402mA   -7.391mA
956.3mV   16.64mA    12.8mA     20.17mA
1.519V    22.38mA    15.12mA    29.91mA
1.977V    23.4mA     15.39mA    33.4mA
2.332V    22.9mA     13.89mA    34mA
2.864V    16mA       3.53mA     28.72mA
3.395V    3.128mA    1.038mA    17.08mA
3.6V      1.738mA    873.1uA    11.73mA
[Pullup]
| Voltage   I(typ)   I(min)   I(max)
-1.8V     2.247mA    1.01mA     8.829mA
-1.241V   10.47mA    3.469mA    16.23mA
-886.4mV  12.84mA    8.534mA    14.69mA
-354.5mV  6.661mA    5.209mA    7.761mA
506.2mV   -9.031mA   -6.771mA   -10.98mA
1.097V    -18mA      -12.34mA   -23.19mA
1.575V    -22.19mA   -13.92mA   -31.21mA
1.977V    -23.32mA   -14.2mA    -34.69mA
2.509V    -20.97mA   -10.3mA    -33.95mA
2.864V    -16.26mA   -3.321mA   -29.88mA
3.395V    -3.415mA   -954.5uA   -19.33mA
3.6V      -1.799mA   -795.4uA   -13.93mA
[Ramp]
dV/dt_r   0.485482/0.167237n  0.353372/0.390449n  0.604034/63.0551p
dV/dt_f   0.502133/0.117326n  0.393712/0.154225n  0.600684/79.9462p
R_load = 50
[Falling Waveform]
R_fixture = 50
V_fixture = 0
V_fixture_min = 0
V_fixture_max = 0
| Time   V(typ)   V(min)   V(max)
0s        821.7mV    601.6mV    1.007V
747.1ps   821.7mV    601.6mV    993.5mV
790.7ps   821.7mV    601.6mV    863mV
841.4ps   822mV      601.6mV    220.7mV
873.3ps   822.1mV    601.6mV    40.96mV
998.7ps   707.2mV    602mV      1.162mV
1.127ns   100.2mV    568.1mV    376.7uV
1.317ns   573.4uV    32.77mV    100.1uV
1.638ns   106.6uV    418.1uV    31.65uV
333.3ns   210.9nV    868.7nV    168.3nV
[Falling Waveform]
R_fixture = 50
V_fixture = 1.8
V_fixture_min = 1.65
V_fixture_max = 1.95
| Time   V(typ)   V(min)   V(max)
0s        1.8V       1.65V      1.95V
801.3ps   1.8V       1.65V      1.956V
834.7ps   1.8V       1.65V      1.83V
923.2ps   1.8V       1.65V      1.162V
970ps     1.767V     1.65V      1.016V
1.088ns   1.527V     1.651V     959.1mV
1.197ns   1.037V     1.586V     952mV
1.434ns   968.4mV    1.083V     949.2mV
2.875ns   963.1mV    993.9mV    948.9mV
333.3ns   963.1mV    993.8mV    948.9mV
[Rising Waveform]
R_fixture = 50
V_fixture = 0
V_fixture_min = 0
V_fixture_max = 0
| Time   V(typ)   V(min)   V(max)
0s        107.6nV    845.2nV    117.1nV
758.2ps   -45.49uV   -44.78nV   3.023mV
811.8ps   -261uV     -107.8nV   157.6mV
895.4ps   -2.921mV   -11.09uV   866.2mV
1.04ns    8.833mV    -2.195mV   989.6mV
1.276ns   631.2mV    44.4mV     1.004V
1.531ns   750.1mV    394.2mV    1.006V
3.28ns    783.8mV    538.8mV    1.007V
18ns      797.1mV    567.2mV    1.007V
333.3ns   809.1mV    589mV      1.007V
[Rising Waveform]
R_fixture = 50
V_fixture = 1.8
V_fixture_min = 1.65
V_fixture_max = 1.95
| Time   V(typ)   V(min)   V(max)
0s        963.1mV    993.8mV    948.9mV
749.8ps   963mV      993.8mV    958.1mV
790.7ps   962.9mV    993.8mV    1.111V
863.8ps   971.6mV    993.7mV    1.897V
916.3ps   1.051V     993.5mV    1.946V
1.008ns   1.656V     1.005V     1.949V
1.085ns   1.782V     1.148V     1.95V
1.212ns   1.797V     1.622V     1.95V
1.649ns   1.8V       1.65V      1.95V
333.3ns   1.8V       1.65V      1.95V
[Add Submodel]
| Submodel Name Mode
M8_PBIDIR_E33_DR_0_1P80V_T All
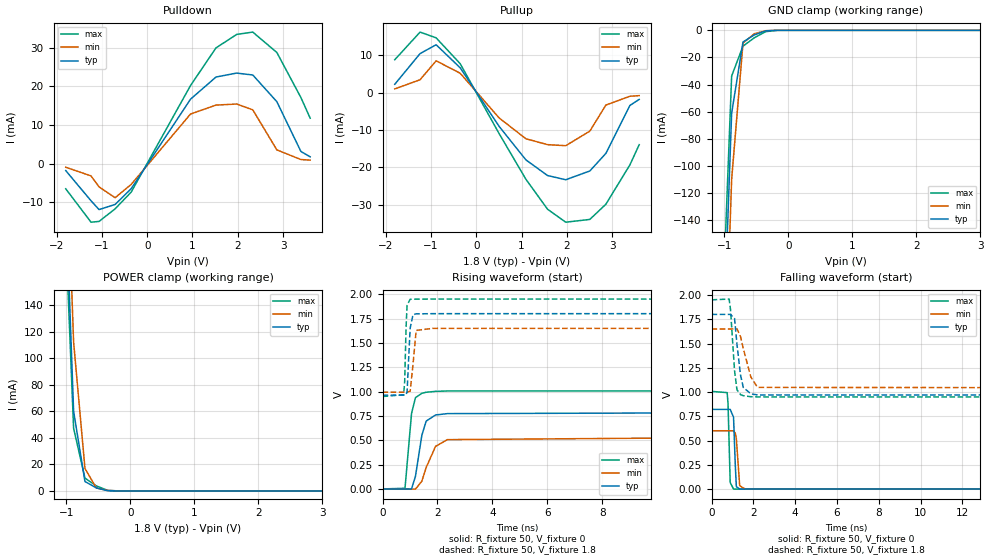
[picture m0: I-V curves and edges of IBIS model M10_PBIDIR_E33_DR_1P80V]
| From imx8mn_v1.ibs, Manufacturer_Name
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[Model] M10_PBIDIR_E33_DR_1P80V
Model_type I/O
Vinl  =  0.54
Vinh  =  1.26
Vmeas =  0.9
| Capacitance   typ   min   max
C_comp   8.99140471561e-13   8.21462742958e-13   9.40633374847e-13
| Variables   typ   min   max
[GND Clamp Reference]   0   0   0
[POWER Clamp Reference]   1.8   1.65   1.95
[Pulldown Reference]   0   0   0
[Pullup Reference]   1.8   1.65   1.95
[Temperature Range]   25   125   -40
[Voltage Range]   1.8   1.65   1.95
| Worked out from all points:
|   slope of the pulldown table from 0 to 0.27 V, typ, clamps not added: 54.5 ohm
|   slope of the pullup table from 0 to 0.27 V, typ, clamps not added: 55 ohm
|   GND clamp passes 1 mA (typ) near -0.39 V on its own axis
|   POWER clamp passes 1 mA (typ) near -0.43 V on its own axis
|   falling waveform, R_fixture 50, V_fixture 0: 20-80 % time 68ps typ, 103ps min, 65.5ps max; typ from 0.822 V to 0 V
|   falling waveform, R_fixture 50, V_fixture 1.8: 20-80 % time 256ps typ, 493ps min, 186ps max; typ from 1.8 V to 0.963 V
|   rising waveform, R_fixture 50, V_fixture 0: 20-80 % time 299ps typ, 582ps min, 183ps max; typ from 0 V to 0.809 V
|   rising waveform, R_fixture 50, V_fixture 1.8: 20-80 % time 71ps typ, 76.8ps min, 55.7ps max; typ from 0.963 V to 1.8 V
[GND Clamp]
| Voltage   I(typ)   I(min)   I(max)
-1.8V     -1.562A    -1.614A    -1.516A
-1.064V   -296mA     -355.2mA   -250.4mA
-886.4mV  -61.18mA   -109.9mA   -33.74mA
-709.1mV  -8.602mA   -9.384mA   -11.67mA
-531.8mV  -3.4mA     -2.481mA   -5.473mA
-354.5mV  -361.2uA   -272.6uA   -975.8uA
-177.3mV  -1.362uA   -3.436uA   -2.724uA
3.6V      0A         0A         0A
[POWER Clamp]
| Voltage   I(typ)   I(min)   I(max)
-1.8V     1.563A     1.607A     1.521A
-1.064V   296.1mA    350.6mA    257.7mA
-886.4mV  60.03mA    112.2mA    47.22mA
-709.1mV  7.094mA    16.96mA    9.663mA
-531.8mV  2.299mA    2.209mA    3.776mA
-354.5mV  136.5uA    326.9uA    430.1uA
-177.3mV  338.8nA    11.95uA    535.8nA
3.6V      0A         0A         0A
[Pulldown]
| Voltage   I(typ)   I(min)   I(max)
-1.8V     -1.816mA   -961.1uA   -6.54mA
-1.241V   -9.644mA   -3.2mA     -15.17mA
-1.064V   -11.91mA   -6.042mA   -14.97mA
-709.1mV  -10.58mA   -8.841mA   -11.71mA
-354.5mV  -6.515mA   -5.402mA   -7.391mA
956.3mV   16.64mA    12.8mA     20.17mA
1.519V    22.38mA    15.12mA    29.91mA
1.977V    23.4mA     15.39mA    33.4mA
2.332V    22.9mA     13.89mA    34mA
2.864V    16mA       3.53mA     28.72mA
3.395V    3.128mA    1.038mA    17.08mA
3.6V      1.738mA    873.1uA    11.73mA
[Pullup]
| Voltage   I(typ)   I(min)   I(max)
-1.8V     2.247mA    1.01mA     8.829mA
-1.241V   10.47mA    3.469mA    16.23mA
-886.4mV  12.84mA    8.534mA    14.69mA
-354.5mV  6.661mA    5.209mA    7.761mA
506.2mV   -9.031mA   -6.771mA   -10.98mA
1.097V    -18mA      -12.34mA   -23.19mA
1.575V    -22.19mA   -13.92mA   -31.21mA
1.977V    -23.32mA   -14.2mA    -34.69mA
2.509V    -20.97mA   -10.3mA    -33.95mA
2.864V    -16.26mA   -3.321mA   -29.88mA
3.395V    -3.415mA   -954.5uA   -19.33mA
3.6V      -1.799mA   -795.4uA   -13.93mA
[Ramp]
dV/dt_r   0.48548/0.299055n  0.35337/0.582106n  0.604034/0.18303n
dV/dt_f   0.502133/0.25623n  0.393712/0.492624n  0.600684/0.186468n
R_load = 50
[Falling Waveform]
R_fixture = 50
V_fixture = 0
V_fixture_min = 0
V_fixture_max = 0
| Time   V(typ)   V(min)   V(max)
0s        821.7mV    601.6mV    1.007V
745.3ps   821.7mV    601.6mV    994.6mV
786.9ps   821.7mV    601.6mV    885.4mV
891.1ps   822mV      601.6mV    68.5mV
1.052ns   740.8mV    601.2mV    1.141mV
1.134ns   252mV      576.4mV    803.5uV
1.185ns   26.62mV    521.2mV    686.3uV
1.345ns   859.8uV    35.68mV    425.3uV
1.608ns   409.5uV    714.4uV    191.1uV
333.3ns   155.9nV    853.9nV    142.1nV
[Falling Waveform]
R_fixture = 50
V_fixture = 1.8
V_fixture_min = 1.65
V_fixture_max = 1.95
| Time   V(typ)   V(min)   V(max)
0s        1.8V       1.65V      1.95V
840.6ps   1.8V       1.65V      1.958V
905.7ps   1.8V       1.65V      1.851V
1.1ns     1.757V     1.651V     1.22V
1.216ns   1.489V     1.652V     1.023V
1.384ns   1.177V     1.571V     974.2mV
1.518ns   1.048V     1.448V     962.5mV
1.88ns    981.9mV    1.154V     952.2mV
2.202ns   970.4mV    1.048V     949.9mV
333.3ns   963.1mV    993.8mV    948.9mV
[Rising Waveform]
R_fixture = 50
V_fixture = 0
V_fixture_min = 0
V_fixture_max = 0
| Time   V(typ)   V(min)   V(max)
0s        107.6nV    845.2nV    117.1nV
817.6ps   -385.6uV   -639.4nV   6.263mV
1.056ns   -13.63uV   -2.605mV   774.6mV
1.199ns   129.8mV    -1.915mV   937.3mV
1.431ns   551mV      79.39mV    982.3mV
1.589ns   696.5mV    220.3mV    993mV
1.931ns   759.5mV    437.1mV    1.002V
2.363ns   773.4mV    506.3mV    1.006V
35.41ns   800.3mV    573.2mV    1.007V
333.3ns   809.1mV    589mV      1.007V
[Rising Waveform]
R_fixture = 50
V_fixture = 1.8
V_fixture_min = 1.65
V_fixture_max = 1.95
| Time   V(typ)   V(min)   V(max)
0s        963.1mV    993.8mV    948.9mV
768.6ps   963mV      993.8mV    967.6mV
807.2ps   962.8mV    993.8mV    1.11V
856.5ps   969.3mV    993.8mV    1.66V
892.6ps   995mV      993.6mV    1.885V
1.005ns   1.65V      1.004V     1.948V
1.109ns   1.789V     1.277V     1.949V
1.224ns   1.798V     1.628V     1.949V
1.822ns   1.8V       1.649V     1.95V
333.3ns   1.8V       1.65V      1.95V
[Add Submodel]
| Submodel Name Mode
M10_PBIDIR_E33_DR_1P80V_T All
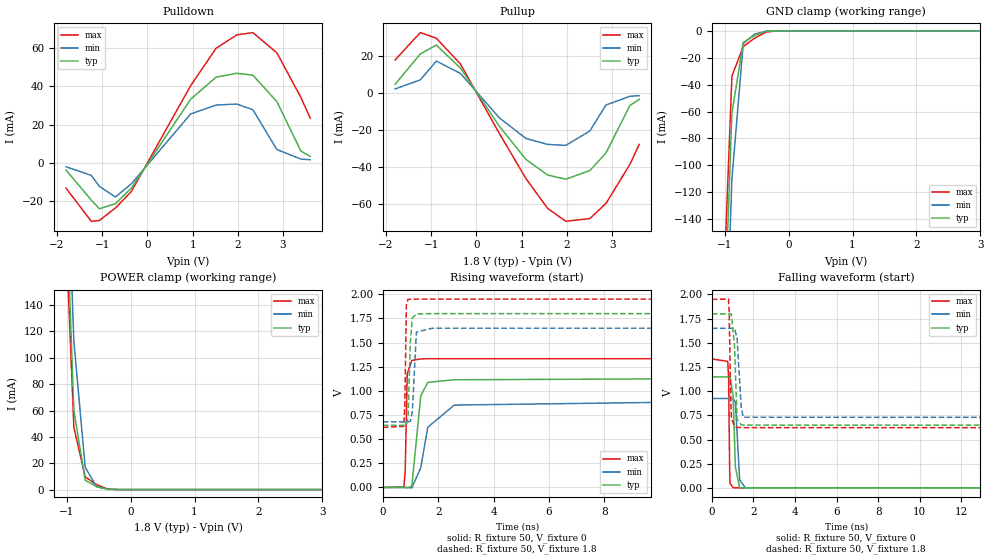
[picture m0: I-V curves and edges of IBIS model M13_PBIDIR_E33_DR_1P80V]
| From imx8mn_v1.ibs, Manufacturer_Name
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[Model] M13_PBIDIR_E33_DR_1P80V
Model_type I/O
Vinl  =  0.54
Vinh  =  1.26
Vmeas =  0.9
| Capacitance   typ   min   max
C_comp   8.99140471561e-13   8.21462742958e-13   9.40633374847e-13
| Variables   typ   min   max
[GND Clamp Reference]   0   0   0
[POWER Clamp Reference]   1.8   1.65   1.95
[Pulldown Reference]   0   0   0
[Pullup Reference]   1.8   1.65   1.95
[Temperature Range]   25   125   -40
[Voltage Range]   1.8   1.65   1.95
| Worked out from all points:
|   slope of the pulldown table from 0 to 0.27 V, typ, clamps not added: 27.3 ohm
|   slope of the pullup table from 0 to 0.27 V, typ, clamps not added: 27.5 ohm
|   GND clamp passes 1 mA (typ) near -0.39 V on its own axis
|   POWER clamp passes 1 mA (typ) near -0.43 V on its own axis
|   falling waveform, R_fixture 50, V_fixture 0: 20-80 % time 99.5ps typ, 106ps min, 41ps max; typ from 1.15 V to 0 V
|   falling waveform, R_fixture 50, V_fixture 1.8: 20-80 % time 114ps typ, 140ps min, 65.3ps max; typ from 1.8 V to 0.644 V
|   rising waveform, R_fixture 50, V_fixture 0: 20-80 % time 213ps typ, 370ps min, 50.2ps max; typ from 0 V to 1.14 V
|   rising waveform, R_fixture 50, V_fixture 1.8: 20-80 % time 72ps typ, 73.9ps min, 34ps max; typ from 0.644 V to 1.8 V
[GND Clamp]
| Voltage   I(typ)   I(min)   I(max)
-1.8V     -1.562A    -1.614A    -1.516A
-1.064V   -296mA     -355.2mA   -250.4mA
-886.4mV  -61.18mA   -109.9mA   -33.74mA
-709.1mV  -8.602mA   -9.384mA   -11.67mA
-531.8mV  -3.4mA     -2.481mA   -5.473mA
-354.5mV  -361.2uA   -272.6uA   -975.8uA
-177.3mV  -1.362uA   -3.436uA   -2.724uA
3.6V      0A         0A         0A
[POWER Clamp]
| Voltage   I(typ)   I(min)   I(max)
-1.8V     1.563A     1.607A     1.521A
-1.064V   296.1mA    350.6mA    257.7mA
-886.4mV  60.03mA    112.2mA    47.22mA
-709.1mV  7.094mA    16.96mA    9.663mA
-531.8mV  2.299mA    2.209mA    3.776mA
-354.5mV  136.5uA    326.9uA    430.1uA
-177.3mV  338.8nA    11.95uA    535.8nA
3.6V      0A         0A         0A
[Pulldown]
| Voltage   I(typ)   I(min)   I(max)
-1.8V     -3.631mA   -1.922mA   -13.08mA
-1.241V   -19.29mA   -6.401mA   -30.33mA
-1.064V   -23.81mA   -12.08mA   -29.93mA
-709.1mV  -21.16mA   -17.68mA   -23.41mA
-354.5mV  -13.03mA   -10.8mA    -14.78mA
956.3mV   33.27mA    25.59mA    40.34mA
1.519V    44.76mA    30.25mA    59.82mA
1.977V    46.8mA     30.77mA    66.8mA
2.332V    45.81mA    27.78mA    68.01mA
2.864V    32mA       7.06mA     57.44mA
3.395V    6.256mA    2.076mA    34.16mA
3.6V      3.476mA    1.746mA    23.46mA
[Pullup]
| Voltage   I(typ)   I(min)   I(max)
-1.8V     4.499mA    2.023mA    17.66mA
-1.241V   20.94mA    6.947mA    32.46mA
-886.4mV  25.7mA     17.08mA    29.38mA
-354.5mV  13.33mA    10.42mA    15.52mA
506.2mV   -18.07mA   -13.55mA   -21.96mA
1.097V    -36.02mA   -24.7mA    -46.37mA
1.575V    -44.41mA   -27.87mA   -62.42mA
1.977V    -46.67mA   -28.42mA   -69.37mA
2.509V    -41.98mA   -20.62mA   -67.9mA
2.864V    -32.55mA   -6.655mA   -59.75mA
3.395V    -6.845mA   -1.911mA   -38.65mA
3.6V      -3.602mA   -1.593mA   -27.87mA
[Ramp]
dV/dt_r   0.682551/0.212953n  0.547618/0.369793n  0.800036/50.1906p
dV/dt_f   0.693846/0.113788n  0.582686/0.140073n  0.796836/65.2552p
R_load = 50
[Falling Waveform]
R_fixture = 50
V_fixture = 0
V_fixture_min = 0
V_fixture_max = 0
| Time   V(typ)   V(min)   V(max)
0s        1.148V     924.7mV    1.333V
764.8ps   1.148V     924.7mV    1.308V
804.9ps   1.148V     924.7mV    1.134V
853.9ps   1.148V     924.7mV    218.2mV
873.1ps   1.148V     924.8mV    46.28mV
1.022ns   950mV      925mV      1.169mV
1.132ns   213mV      883.2mV    540.8uV
1.337ns   671.3uV    80.81mV    151.2uV
1.614ns   174.5uV    633.5uV    35.99uV
333.3ns   114.6nV    543nV      87.64nV
[Falling Waveform]
R_fixture = 50
V_fixture = 1.8
V_fixture_min = 1.65
V_fixture_max = 1.95
| Time   V(typ)   V(min)   V(max)
0s        1.8V       1.65V      1.95V
803.2ps   1.8V       1.65V      1.952V
834.1ps   1.8V       1.65V      1.797V
904.7ps   1.8V       1.65V      931.9mV
938.6ps   1.796V     1.65V      723.3mV
1.09ns    1.465V     1.651V     634.5mV
1.212ns   709.2mV    1.543V     626.6mV
1.408ns   653.1mV    839.3mV    623.1mV
1.507ns   649mV      730.9mV    622.5mV
333.3ns   643.6mV    678.9mV    621.9mV
[Rising Waveform]
R_fixture = 50
V_fixture = 0
V_fixture_min = 0
V_fixture_max = 0
| Time   V(typ)   V(min)   V(max)
0s        59.41nV    515.7nV    58.78nV
761.1ps   -8.159uV   -304.8nV   4.084mV
807.6ps   -561.9uV   -354.9nV   175.6mV
881ps     -4.223mV   -813.5nV   1.177V
1.046ns   12.51mV    -4.266mV   1.315V
1.368ns   947.3mV    202.9mV    1.331V
1.622ns   1.088V     623.2mV    1.333V
2.578ns   1.115V     853mV      1.333V
12.3ns    1.127V     889.8mV    1.333V
333.3ns   1.138V     912.7mV    1.333V
[Rising Waveform]
R_fixture = 50
V_fixture = 1.8
V_fixture_min = 1.65
V_fixture_max = 1.95
| Time   V(typ)   V(min)   V(max)
0s        643.6mV    678.9mV    621.9mV
753.3ps   643.5mV    678.9mV    632.6mV
793.8ps   643.3mV    678.9mV    844.5mV
849.9ps   648.3mV    678.8mV    1.892V
911ps     729.3mV    678.6mV    1.948V
991.5ps   1.497V     686mV      1.949V
1.065ns   1.753V     783.4mV    1.949V
1.212ns   1.797V     1.609V     1.95V
1.792ns   1.8V       1.649V     1.95V
333.3ns   1.8V       1.65V      1.95V
[Add Submodel]
| Submodel Name Mode
M13_PBIDIR_E33_DR_1P80V_T All
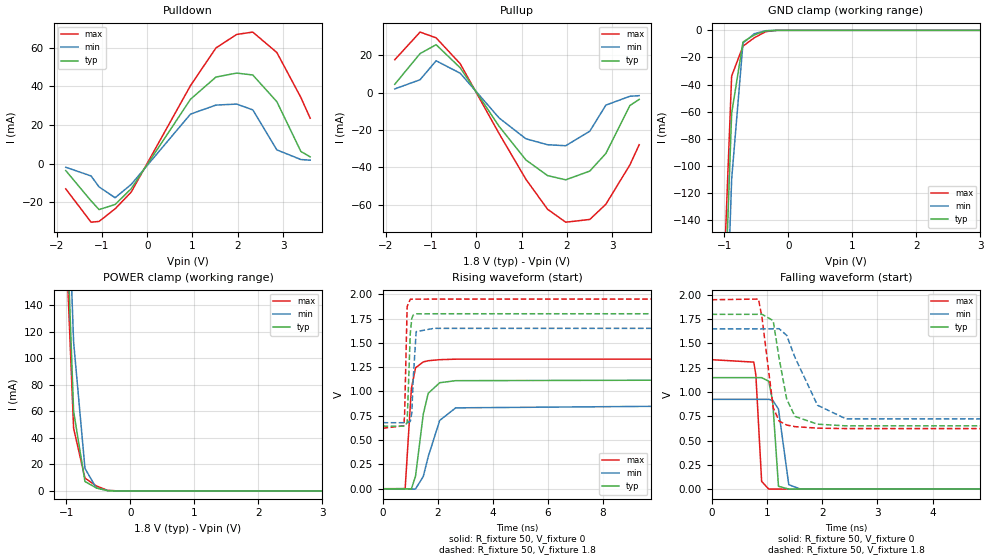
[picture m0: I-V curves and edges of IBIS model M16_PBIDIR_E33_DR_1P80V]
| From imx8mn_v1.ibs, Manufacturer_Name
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[Model] M16_PBIDIR_E33_DR_1P80V
Model_type I/O
Vinl  =  0.54
Vinh  =  1.26
Vmeas =  0.9
| Capacitance   typ   min   max
C_comp   8.99140471561e-13   8.21462742958e-13   9.40633374847e-13
| Variables   typ   min   max
[GND Clamp Reference]   0   0   0
[POWER Clamp Reference]   1.8   1.65   1.95
[Pulldown Reference]   0   0   0
[Pullup Reference]   1.8   1.65   1.95
[Temperature Range]   25   125   -40
[Voltage Range]   1.8   1.65   1.95
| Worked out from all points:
|   slope of the pulldown table from 0 to 0.27 V, typ, clamps not added: 27.3 ohm
|   slope of the pullup table from 0 to 0.27 V, typ, clamps not added: 27.5 ohm
|   GND clamp passes 1 mA (typ) near -0.39 V on its own axis
|   POWER clamp passes 1 mA (typ) near -0.43 V on its own axis
|   falling waveform, R_fixture 50, V_fixture 0: 20-80 % time 71ps typ, 109ps min, 67.1ps max; typ from 1.15 V to 0 V
|   falling waveform, R_fixture 50, V_fixture 1.8: 20-80 % time 211ps typ, 460ps min, 168ps max; typ from 1.8 V to 0.644 V
|   rising waveform, R_fixture 50, V_fixture 0: 20-80 % time 332ps typ, 605ps min, 169ps max; typ from 0 V to 1.14 V
|   rising waveform, R_fixture 50, V_fixture 1.8: 20-80 % time 72ps typ, 74ps min, 56.3ps max; typ from 0.644 V to 1.8 V
[GND Clamp]
| Voltage   I(typ)   I(min)   I(max)
-1.8V     -1.562A    -1.614A    -1.516A
-1.064V   -296mA     -355.2mA   -250.4mA
-886.4mV  -61.18mA   -109.9mA   -33.74mA
-709.1mV  -8.602mA   -9.384mA   -11.67mA
-531.8mV  -3.4mA     -2.481mA   -5.473mA
-354.5mV  -361.2uA   -272.6uA   -975.8uA
-177.3mV  -1.362uA   -3.436uA   -2.724uA
3.6V      0A         0A         0A
[POWER Clamp]
| Voltage   I(typ)   I(min)   I(max)
-1.8V     1.563A     1.607A     1.521A
-1.064V   296.1mA    350.6mA    257.7mA
-886.4mV  60.03mA    112.2mA    47.22mA
-709.1mV  7.094mA    16.96mA    9.663mA
-531.8mV  2.299mA    2.209mA    3.776mA
-354.5mV  136.5uA    326.9uA    430.1uA
-177.3mV  338.8nA    11.95uA    535.8nA
3.6V      0A         0A         0A
[Pulldown]
| Voltage   I(typ)   I(min)   I(max)
-1.8V     -3.631mA   -1.922mA   -13.08mA
-1.241V   -19.29mA   -6.401mA   -30.33mA
-1.064V   -23.81mA   -12.08mA   -29.93mA
-709.1mV  -21.16mA   -17.68mA   -23.41mA
-354.5mV  -13.03mA   -10.8mA    -14.78mA
956.3mV   33.27mA    25.59mA    40.34mA
1.519V    44.76mA    30.25mA    59.82mA
1.977V    46.8mA     30.77mA    66.8mA
2.332V    45.81mA    27.78mA    68.01mA
2.864V    32mA       7.06mA     57.44mA
3.395V    6.256mA    2.076mA    34.16mA
3.6V      3.476mA    1.746mA    23.46mA
[Pullup]
| Voltage   I(typ)   I(min)   I(max)
-1.8V     4.499mA    2.023mA    17.66mA
-1.241V   20.94mA    6.947mA    32.46mA
-886.4mV  25.7mA     17.08mA    29.38mA
-354.5mV  13.33mA    10.42mA    15.52mA
506.2mV   -18.07mA   -13.55mA   -21.96mA
1.097V    -36.02mA   -24.7mA    -46.37mA
1.575V    -44.41mA   -27.87mA   -62.42mA
1.977V    -46.67mA   -28.42mA   -69.37mA
2.509V    -41.98mA   -20.62mA   -67.9mA
2.864V    -32.55mA   -6.655mA   -59.75mA
3.395V    -6.845mA   -1.911mA   -38.65mA
3.6V      -3.602mA   -1.593mA   -27.87mA
[Ramp]
dV/dt_r   0.682547/0.331836n  0.547614/0.604524n  0.800037/0.168981n
dV/dt_f   0.693846/0.211351n  0.582686/0.460297n  0.796836/0.167913n
R_load = 50
[Falling Waveform]
R_fixture = 50
V_fixture = 0
V_fixture_min = 0
V_fixture_max = 0
| Time   V(typ)   V(min)   V(max)
0s        1.148V     924.7mV    1.333V
764.3ps   1.148V     924.7mV    1.308V
801.9ps   1.148V     924.7mV    1.174V
906.2ps   1.148V     924.7mV    79.66mV
1.034ns   1.111V     924.7mV    1.472mV
1.106ns   903.8mV    915.2mV    1.056mV
1.211ns   29.7mV     824.4mV    769.7uV
1.397ns   844.8uV    46.1mV     480uV
1.607ns   513uV      938.6uV    290.4uV
333.3ns   87.32nV    523.5nV    72.68nV
[Falling Waveform]
R_fixture = 50
V_fixture = 1.8
V_fixture_min = 1.65
V_fixture_max = 1.95
| Time   V(typ)   V(min)   V(max)
0s        1.8V       1.65V      1.95V
848.6ps   1.8V       1.65V      1.957V
912.3ps   1.8V       1.65V      1.769V
1.115ns   1.735V     1.651V     840.7mV
1.222ns   1.35V      1.652V     701mV
1.359ns   928mV      1.584V     660.3mV
1.509ns   749.2mV    1.357V     643.6mV
1.917ns   669mV      864.2mV    628.2mV
2.433ns   651.7mV    723.8mV    623.6mV
333.3ns   643.6mV    678.9mV    621.9mV
[Rising Waveform]
R_fixture = 50
V_fixture = 0
V_fixture_min = 0
V_fixture_max = 0
| Time   V(typ)   V(min)   V(max)
0s        59.41nV    515.7nV    58.78nV
820.6ps   -970.3uV   -1.938uV   1.572mV
1.047ns   -1.312mV   -4.335mV   1.03V
1.197ns   128.5mV    -2.482mV   1.243V
1.479ns   767.7mV    126.9mV    1.304V
1.657ns   980.8mV    329.1mV    1.316V
2.075ns   1.09V      702.6mV    1.327V
2.655ns   1.111V     831.6mV    1.332V
32.99ns   1.131V     898.3mV    1.333V
333.3ns   1.138V     912.7mV    1.333V
[Rising Waveform]
R_fixture = 50
V_fixture = 1.8
V_fixture_min = 1.65
V_fixture_max = 1.95
| Time   V(typ)   V(min)   V(max)
0s        643.6mV    678.9mV    621.9mV
773ps     643.5mV    678.9mV    647.2mV
802.3ps   643.2mV    678.9mV    774.5mV
892.9ps   679.9mV    678.7mV    1.874V
1.007ns   1.597V     691.9mV    1.948V
1.062ns   1.75V      775.7mV    1.949V
1.108ns   1.784V     1.103V     1.949V
1.22ns    1.798V     1.615V     1.949V
1.869ns   1.799V     1.649V     1.95V
333.3ns   1.8V       1.65V      1.95V
[Add Submodel]
| Submodel Name Mode
M16_PBIDIR_E33_DR_1P80V_T All
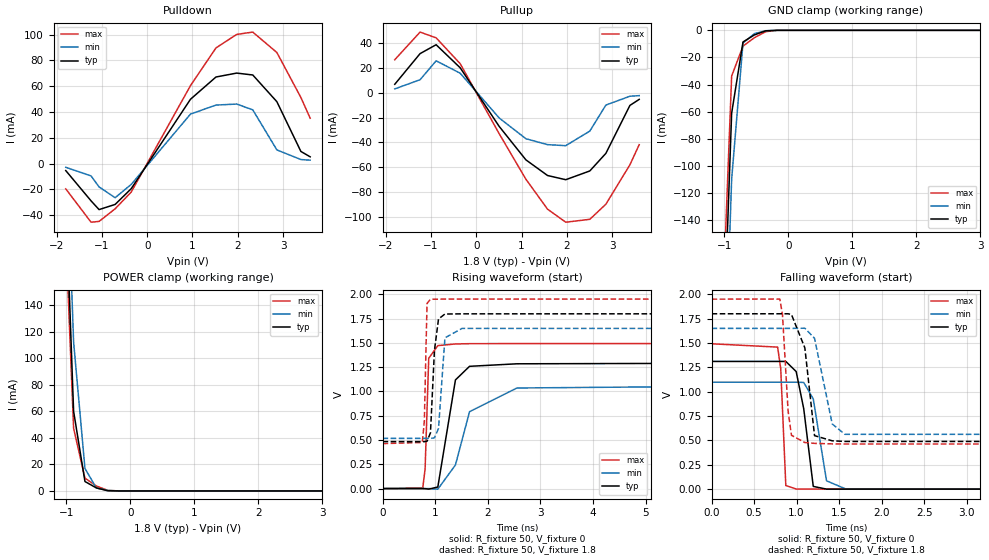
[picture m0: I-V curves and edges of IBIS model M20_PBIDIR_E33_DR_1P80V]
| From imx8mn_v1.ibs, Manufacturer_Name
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[Model] M20_PBIDIR_E33_DR_1P80V
Model_type I/O
Vinl  =  0.54
Vinh  =  1.26
Vmeas =  0.9
| Capacitance   typ   min   max
C_comp   8.99140471561e-13   8.21462742958e-13   9.40633374847e-13
| Variables   typ   min   max
[GND Clamp Reference]   0   0   0
[POWER Clamp Reference]   1.8   1.65   1.95
[Pulldown Reference]   0   0   0
[Pullup Reference]   1.8   1.65   1.95
[Temperature Range]   25   125   -40
[Voltage Range]   1.8   1.65   1.95
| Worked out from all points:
|   slope of the pulldown table from 0 to 0.27 V, typ, clamps not added: 18.2 ohm
|   slope of the pullup table from 0 to 0.27 V, typ, clamps not added: 18.3 ohm
|   GND clamp passes 1 mA (typ) near -0.39 V on its own axis
|   POWER clamp passes 1 mA (typ) near -0.43 V on its own axis
|   falling waveform, R_fixture 50, V_fixture 0: 20-80 % time 94.9ps typ, 106ps min, 37.2ps max; typ from 1.31 V to 0 V
|   falling waveform, R_fixture 50, V_fixture 1.8: 20-80 % time 102ps typ, 126ps min, 59.6ps max; typ from 1.8 V to 0.484 V
|   rising waveform, R_fixture 50, V_fixture 0: 20-80 % time 212ps typ, 339ps min, 45.5ps max; typ from 0 V to 1.3 V
|   rising waveform, R_fixture 50, V_fixture 1.8: 20-80 % time 72.1ps typ, 72.2ps min, 30.4ps max; typ from 0.484 V to 1.8 V
[GND Clamp]
| Voltage   I(typ)   I(min)   I(max)
-1.8V     -1.562A    -1.614A    -1.516A
-1.064V   -296mA     -355.2mA   -250.4mA
-886.4mV  -61.18mA   -109.9mA   -33.74mA
-709.1mV  -8.602mA   -9.384mA   -11.67mA
-531.8mV  -3.4mA     -2.481mA   -5.473mA
-354.5mV  -361.2uA   -272.6uA   -975.8uA
-177.3mV  -1.362uA   -3.436uA   -2.724uA
3.6V      0A         0A         0A
[POWER Clamp]
| Voltage   I(typ)   I(min)   I(max)
-1.8V     1.563A     1.607A     1.521A
-1.064V   296.1mA    350.6mA    257.7mA
-886.4mV  60.03mA    112.2mA    47.22mA
-709.1mV  7.094mA    16.96mA    9.663mA
-531.8mV  2.299mA    2.209mA    3.776mA
-354.5mV  136.5uA    326.9uA    430.1uA
-177.3mV  338.8nA    11.95uA    535.8nA
3.6V      0A         0A         0A
[Pulldown]
| Voltage   I(typ)   I(min)   I(max)
-1.8V     -5.447mA   -2.883mA   -19.62mA
-1.241V   -28.93mA   -9.601mA   -45.5mA
-1.064V   -35.72mA   -18.13mA   -44.9mA
-709.1mV  -31.73mA   -26.52mA   -35.12mA
-354.5mV  -19.54mA   -16.21mA   -22.17mA
956.3mV   49.91mA    38.39mA    60.51mA
1.519V    67.15mA    45.37mA    89.73mA
1.977V    70.19mA    46.16mA    100.2mA
2.332V    68.71mA    41.67mA    102mA
2.864V    48.01mA    10.59mA    86.16mA
3.395V    9.384mA    3.113mA    51.23mA
3.6V      5.213mA    2.619mA    35.18mA
[Pullup]
| Voltage   I(typ)   I(min)   I(max)
-1.8V     6.738mA    3.031mA    26.49mA
-1.241V   31.39mA    10.4mA     48.69mA
-886.4mV  38.53mA    25.6mA     44.07mA
-354.5mV  19.98mA    15.63mA    23.28mA
506.2mV   -27.09mA   -20.31mA   -32.95mA
1.097V    -54mA      -37.01mA   -69.56mA
1.575V    -66.58mA   -41.77mA   -93.63mA
1.977V    -69.95mA   -42.59mA   -104.1mA
2.509V    -62.92mA   -30.89mA   -101.8mA
2.864V    -48.77mA   -9.962mA   -89.63mA
3.395V    -10.24mA   -2.863mA   -57.98mA
3.6V      -5.395mA   -2.386mA   -41.8mA
[Ramp]
dV/dt_r   0.781734/0.211797n  0.652633/0.339152n  0.895239/45.5185p
dV/dt_f   0.789882/0.102492n  0.680105/0.126349n  0.89236/59.5741p
R_load = 50
[Falling Waveform]
R_fixture = 50
V_fixture = 0
V_fixture_min = 0
V_fixture_max = 0
| Time   V(typ)   V(min)   V(max)
0s        1.311V     1.098V     1.492V
777ps     1.311V     1.098V     1.458V
813.3ps   1.311V     1.098V     1.238V
873.2ps   1.311V     1.098V     36.94mV
995.1ps   1.207V     1.098V     1.537mV
1.084ns   824.6mV    1.095V     898.4uV
1.196ns   28.23mV    926.2mV    489.7uV
1.352ns   724.2uV    85.95mV    221.8uV
1.581ns   279.6uV    838.6uV    75.16uV
333.3ns   62.22nV    349.5nV    46.88nV
[Falling Waveform]
R_fixture = 50
V_fixture = 1.8
V_fixture_min = 1.65
V_fixture_max = 1.95
| Time   V(typ)   V(min)   V(max)
0s        1.8V       1.65V      1.95V
802.7ps   1.8V       1.65V      1.951V
833.7ps   1.8V       1.65V      1.794V
900.1ps   1.8V       1.65V      802.6mV
939.3ps   1.793V     1.65V      553.2mV
1.097ns   1.45V      1.652V     478.6mV
1.211ns   549.3mV    1.548V     469.9mV
1.419ns   496.3mV    669mV      464.9mV
1.568ns   489.9mV    562.7mV    463.7mV
333.3ns   483.5mV    516.5mV    462.7mV
[Rising Waveform]
R_fixture = 50
V_fixture = 0
V_fixture_min = 0
V_fixture_max = 0
| Time   V(typ)   V(min)   V(max)
0s        34.82nV    339nV      30.15nV
764.7ps   -11.2uV    -361.5nV   6.895mV
809.1ps   -887.8uV   -402.2nV   201.5mV
878.1ps   -5.261mV   17.24uV    1.341V
1.051ns   16.19mV    -5.949mV   1.471V
1.386ns   1.118V     243mV      1.488V
1.654ns   1.258V     791.3mV    1.491V
2.556ns   1.284V     1.035V     1.492V
9.868ns   1.294V     1.067V     1.492V
333.3ns   1.303V     1.088V     1.492V
[Rising Waveform]
R_fixture = 50
V_fixture = 1.8
V_fixture_min = 1.65
V_fixture_max = 1.95
| Time   V(typ)   V(min)   V(max)
0s        483.5mV    516.5mV    462.7mV
755.1ps   483.5mV    516.5mV    474.3mV
794.4ps   483.1mV    516.5mV    692.2mV
845.7ps   486.9mV    516.5mV    1.905V
911.1ps   573.7mV    516.2mV    1.948V
986.5ps   1.421V     522.1mV    1.949V
1.064ns   1.745V     619mV      1.949V
1.186ns   1.796V     1.551V     1.95V
1.512ns   1.798V     1.648V     1.95V
333.3ns   1.8V       1.65V      1.95V
[Add Submodel]
| Submodel Name Mode
M20_PBIDIR_E33_DR_1P80V_T All
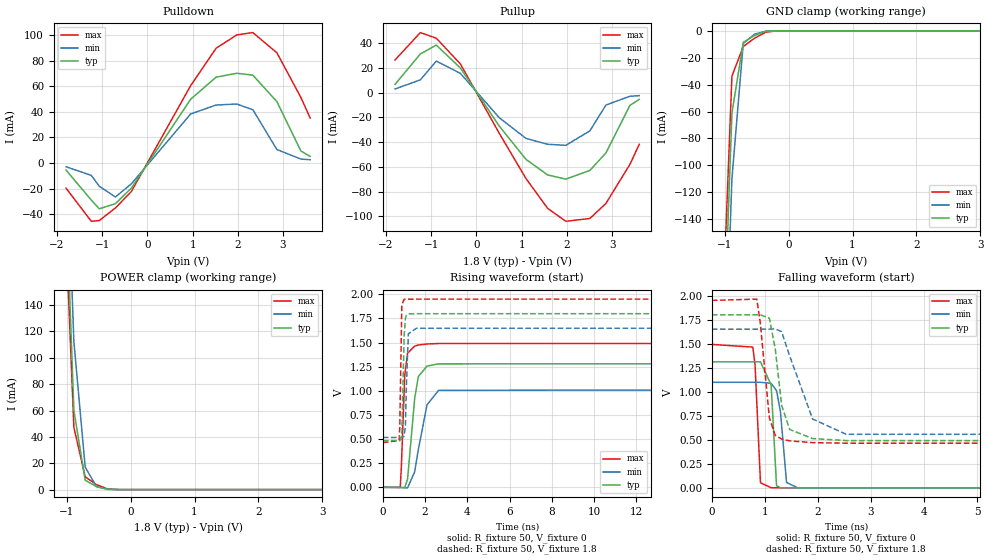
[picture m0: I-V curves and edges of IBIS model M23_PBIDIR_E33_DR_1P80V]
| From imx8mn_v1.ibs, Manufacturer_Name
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[Model] M23_PBIDIR_E33_DR_1P80V
Model_type I/O
Vinl  =  0.54
Vinh  =  1.26
Vmeas =  0.9
| Capacitance   typ   min   max
C_comp   8.99140471561e-13   8.21462742958e-13   9.40633374847e-13
| Variables   typ   min   max
[GND Clamp Reference]   0   0   0
[POWER Clamp Reference]   1.8   1.65   1.95
[Pulldown Reference]   0   0   0
[Pullup Reference]   1.8   1.65   1.95
[Temperature Range]   25   125   -40
[Voltage Range]   1.8   1.65   1.95
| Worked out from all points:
|   slope of the pulldown table from 0 to 0.27 V, typ, clamps not added: 18.2 ohm
|   slope of the pullup table from 0 to 0.27 V, typ, clamps not added: 18.3 ohm
|   GND clamp passes 1 mA (typ) near -0.39 V on its own axis
|   POWER clamp passes 1 mA (typ) near -0.43 V on its own axis
|   falling waveform, R_fixture 50, V_fixture 0: 20-80 % time 64.8ps typ, 101ps min, 63.2ps max; typ from 1.31 V to 0 V
|   falling waveform, R_fixture 50, V_fixture 1.8: 20-80 % time 178ps typ, 425ps min, 151ps max; typ from 1.8 V to 0.484 V
|   rising waveform, R_fixture 50, V_fixture 0: 20-80 % time 321ps typ, 562ps min, 154ps max; typ from 0 V to 1.3 V
|   rising waveform, R_fixture 50, V_fixture 1.8: 20-80 % time 72.2ps typ, 72.2ps min, 56.6ps max; typ from 0.484 V to 1.8 V
[GND Clamp]
| Voltage   I(typ)   I(min)   I(max)
-1.8V     -1.562A    -1.614A    -1.516A
-1.064V   -296mA     -355.2mA   -250.4mA
-886.4mV  -61.18mA   -109.9mA   -33.74mA
-709.1mV  -8.602mA   -9.384mA   -11.67mA
-531.8mV  -3.4mA     -2.481mA   -5.473mA
-354.5mV  -361.2uA   -272.6uA   -975.8uA
-177.3mV  -1.362uA   -3.436uA   -2.724uA
3.6V      0A         0A         0A
[POWER Clamp]
| Voltage   I(typ)   I(min)   I(max)
-1.8V     1.563A     1.607A     1.521A
-1.064V   296.1mA    350.6mA    257.7mA
-886.4mV  60.03mA    112.2mA    47.22mA
-709.1mV  7.094mA    16.96mA    9.663mA
-531.8mV  2.299mA    2.209mA    3.776mA
-354.5mV  136.5uA    326.9uA    430.1uA
-177.3mV  338.8nA    11.95uA    535.8nA
3.6V      0A         0A         0A
[Pulldown]
| Voltage   I(typ)   I(min)   I(max)
-1.8V     -5.447mA   -2.883mA   -19.62mA
-1.241V   -28.93mA   -9.601mA   -45.5mA
-1.064V   -35.72mA   -18.13mA   -44.9mA
-709.1mV  -31.73mA   -26.52mA   -35.12mA
-354.5mV  -19.54mA   -16.21mA   -22.17mA
956.3mV   49.91mA    38.39mA    60.51mA
1.519V    67.15mA    45.37mA    89.73mA
1.977V    70.19mA    46.16mA    100.2mA
2.332V    68.71mA    41.67mA    102mA
2.864V    48.01mA    10.59mA    86.16mA
3.395V    9.384mA    3.113mA    51.23mA
3.6V      5.213mA    2.619mA    35.18mA
[Pullup]
| Voltage   I(typ)   I(min)   I(max)
-1.8V     6.738mA    3.031mA    26.49mA
-1.241V   31.39mA    10.4mA     48.69mA
-886.4mV  38.53mA    25.6mA     44.07mA
-354.5mV  19.98mA    15.63mA    23.28mA
506.2mV   -27.09mA   -20.31mA   -32.95mA
1.097V    -54mA      -37.01mA   -69.56mA
1.575V    -66.58mA   -41.77mA   -93.63mA
1.977V    -69.95mA   -42.59mA   -104.1mA
2.509V    -62.92mA   -30.89mA   -101.8mA
2.864V    -48.77mA   -9.962mA   -89.63mA
3.395V    -10.24mA   -2.863mA   -57.98mA
3.6V      -5.395mA   -2.386mA   -41.8mA
[Ramp]
dV/dt_r   0.78173/0.320651n  0.652631/0.562174n  0.895239/0.153981n
dV/dt_f   0.789882/0.177801n  0.680105/0.424702n  0.892361/0.151285n
R_load = 50
[Falling Waveform]
R_fixture = 50
V_fixture = 0
V_fixture_min = 0
V_fixture_max = 0
| Time   V(typ)   V(min)   V(max)
0s        1.311V     1.098V     1.492V
772ps     1.311V     1.098V     1.464V
813.9ps   1.311V     1.098V     1.281V
916.2ps   1.311V     1.098V     53.5mV
1.117ns   1.071V     1.087V     1.095mV
1.219ns   21.9mV     1.011V     816.3uV
1.292ns   1.477mV    795.1mV    677.4uV
1.408ns   876.2uV    55.98mV    521.8uV
1.614ns   556.6uV    1.034mV    335.5uV
333.3ns   53.32nV    344.7nV    38.5nV
[Falling Waveform]
R_fixture = 50
V_fixture = 1.8
V_fixture_min = 1.65
V_fixture_max = 1.95
| Time   V(typ)   V(min)   V(max)
0s        1.8V       1.65V      1.95V
845.9ps   1.8V       1.65V      1.963V
909.8ps   1.8V       1.65V      1.731V
1.083ns   1.766V     1.651V     729.5mV
1.194ns   1.448V     1.653V     546.9mV
1.316ns   857.1mV    1.624V     508mV
1.466ns   607.4mV    1.373V     488.8mV
1.899ns   512.5mV    715.8mV    470.5mV
2.531ns   491.8mV    557.4mV    464.7mV
333.3ns   483.5mV    516.5mV    462.7mV
[Rising Waveform]
R_fixture = 50
V_fixture = 0
V_fixture_min = 0
V_fixture_max = 0
| Time   V(typ)   V(min)   V(max)
0s        34.82nV    339nV      30.15nV
822.2ps   -1.45mV    -3.956uV   -2.204mV
873.9ps   -4.915mV   26.44uV    198.9mV
1.036ns   -2.625mV   -5.03mV    1.159V
1.169ns   82.05mV    -5.771mV   1.389V
1.506ns   918.1mV    159.6mV    1.463V
1.678ns   1.147V     389.1mV    1.474V
2.089ns   1.256V     852.9mV    1.485V
2.638ns   1.279V     1.005V     1.49V
333.3ns   1.303V     1.088V     1.492V
[Rising Waveform]
R_fixture = 50
V_fixture = 1.8
V_fixture_min = 1.65
V_fixture_max = 1.95
| Time   V(typ)   V(min)   V(max)
0s        483.5mV    516.5mV    462.7mV
772.3ps   483.4mV    516.5mV    485.4mV
802.3ps   483mV      516.5mV    629.9mV
897.6ps   527.5mV    516.3mV    1.889V
1.007ns   1.564V     528.9mV    1.948V
1.067ns   1.748V     635.1mV    1.949V
1.107ns   1.781V     1.003V     1.949V
1.206ns   1.797V     1.591V     1.949V
1.589ns   1.799V     1.648V     1.95V
333.3ns   1.8V       1.65V      1.95V
[Add Submodel]
| Submodel Name Mode
M23_PBIDIR_E33_DR_1P80V_T All
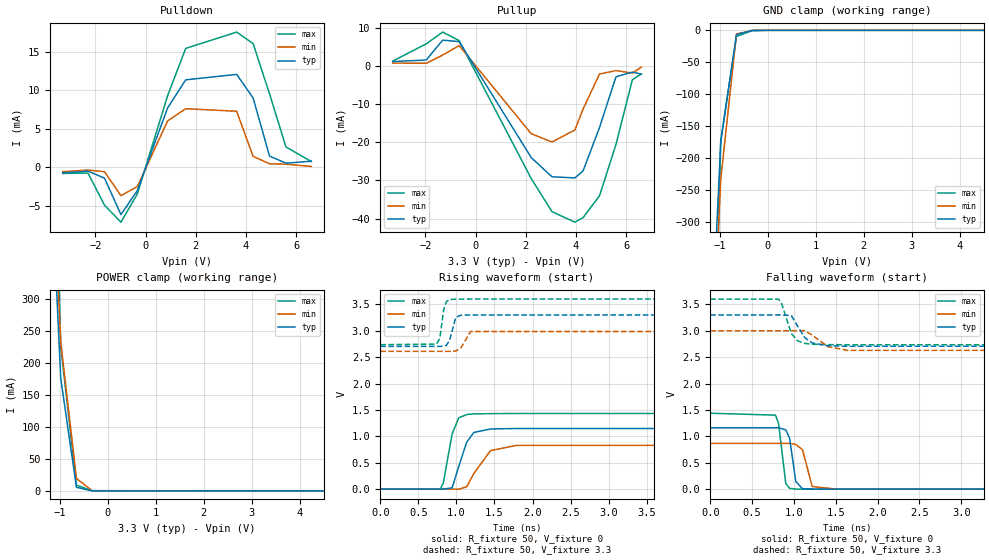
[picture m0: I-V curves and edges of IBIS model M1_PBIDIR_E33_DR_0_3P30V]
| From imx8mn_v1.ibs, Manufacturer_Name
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[Model] M1_PBIDIR_E33_DR_0_3P30V
Model_type I/O
Vinl  =  0.54
Vinh  =  1.26
Vmeas =  0.9
| Capacitance   typ   min   max
C_comp   7.43257478797e-13   6.80162949915e-13   7.72418772183e-13
| Variables   typ   min   max
[GND Clamp Reference]   0   0   0
[POWER Clamp Reference]   3.3   3   3.6
[Pulldown Reference]   0   0   0
[Pullup Reference]   3.3   3   3.6
[Temperature Range]   25   125   -40
[Voltage Range]   3.3   3   3.6
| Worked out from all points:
|   slope of the pulldown table from 0 to 0.495 V, typ, clamps not added: 110 ohm
|   slope of the pullup table from 0 to 0.495 V, typ, clamps not added: 90.3 ohm
|   falling waveform, R_fixture 50, V_fixture 0: 20-80 % time 57.8ps typ, 68.1ps min, 53.5ps max; typ from 1.16 V to 0 V
|   falling waveform, R_fixture 50, V_fixture 3.3: 20-80 % time 147ps typ, 208ps min, 115ps max; typ from 3.3 V to 2.7 V
|   rising waveform, R_fixture 50, V_fixture 0: 20-80 % time 153ps typ, 227ps min, 114ps max; typ from 0 V to 1.16 V
|   rising waveform, R_fixture 50, V_fixture 3.3: 20-80 % time 55.8ps typ, 69.4ps min, 47.2ps max; typ from 2.7 V to 3.3 V
[GND Clamp]
| Voltage   I(typ)   I(min)   I(max)
-3.3V     -7.887A    -7.417A    -8.531A
-1.309V   -700.1mA   -755mA     -1.16A
-981.8mV  -175.2mA   -233.5mA   -172.1mA
-654.5mV  -6.799mA   -5.773mA   -9.66mA
-327.3mV  -189uA     -156uA     -585.6uA
0V        -136.9nA   -148nA     -612.9nA
6.6V      0A         0A         0A
[POWER Clamp]
| Voltage   I(typ)   I(min)   I(max)
-3.3V     7.896A     7.466A     8.506A
-1.309V   700.9mA    749.4mA    1.174A
-981.8mV  175.4mA    232.7mA    224.9mA
-654.5mV  5.603mA    19.51mA    9.05mA
-327.3mV  73.82uA    354.9uA    410.8uA
-300mV    34.66uA    61.21uA    374.3uA
6.6V      0A         0A         0A
[Pulldown]
| Voltage   I(typ)   I(min)   I(max)
-3.3V     -742uA     -574.3uA   -803.9uA
-2.291V   -508.3uA   -362.4uA   -762.5uA
-1.636V   -1.416mA   -585.9uA   -4.925mA
-981.8mV  -6.147mA   -3.691mA   -7.135mA
-327.3mV  -3.029mA   -2.506mA   -3.462mA
876.6mV   7.705mA    6.01mA     9.281mA
1.598V    11.35mA    7.602mA    15.43mA
3.627V    12.06mA    7.27mA     17.55mA
4.282V    8.999mA    1.41mA     16.05mA
4.936V    1.454mA    453.5uA    9.535mA
5.591V    525uA      398.6uA    2.629mA
6.6V      785.2uA    104uA      736.5uA
[Pullup]
| Voltage   I(typ)   I(min)   I(max)
-3.3V     1.164mA    764uA      1.285mA
-1.964V   1.577mA    712uA      5.816mA
-1.309V   6.778mA    2.881mA    8.891mA
-654.5mV  6.402mA    5.355mA    6.657mA
2.217V    -24mA      -17.75mA   -29.5mA
3.042V    -29.03mA   -19.92mA   -38.17mA
3.955V    -29.33mA   -16.75mA   -40.93mA
4.282V    -27.48mA   -11.26mA   -39.72mA
4.936V    -16.1mA    -2.085mA   -34.01mA
5.591V    -2.826mA   -1.202mA   -20.54mA
6.245V    -1.59mA    -1.858mA   -3.588mA
6.6V      -2.118mA   -276.6uA   -2.072mA
[Ramp]
dV/dt_r   0.697708/0.15333n  0.51868/0.226815n  0.862818/0.113829n
dV/dt_f   0.357755/0.146811n  0.234163/0.208351n  0.51872/0.1152n
R_load = 50
[Falling Waveform]
R_fixture = 50
V_fixture = 0
V_fixture_min = 0
V_fixture_max = 0
| Time   V(typ)   V(min)   V(max)
0s        1.163V     866.9mV    1.438V
779.6ps   1.163V     866.9mV    1.402V
816.1ps   1.163V     866.9mV    1.245V
902.4ps   1.122V     866.9mV    104.4mV
948.5ps   963.4mV    866.7mV    15.7mV
1.022ns   144.4mV    848.4mV    1.534mV
1.103ns   6.926mV    743.6mV    497.1uV
1.218ns   790.4uV    49.76mV    210.6uV
1.507ns   164.4uV    534.9uV    71.89uV
333.3ns   4.35uV     5.082uV    18.22uV
[Falling Waveform]
R_fixture = 50
V_fixture = 3.3
V_fixture_min = 3
V_fixture_max = 3.6
| Time   V(typ)   V(min)   V(max)
0s        3.3V       3V         3.6V
813ps     3.3V       3V         3.597V
845.6ps   3.301V     3V         3.548V
969.8ps   3.286V     3.001V     2.945V
1.042ns   3.092V     3.001V     2.811V
1.128ns   2.872V     3.001V     2.76V
1.217ns   2.768V     2.918V     2.745V
1.404ns   2.716V     2.7V       2.737V
1.634ns   2.706V     2.629V     2.735V
333.3ns   2.704V     2.61V      2.735V
[Rising Waveform]
R_fixture = 50
V_fixture = 0
V_fixture_min = 0
V_fixture_max = 0
| Time   V(typ)   V(min)   V(max)
0s        4.336uV    5.068uV    18.21uV
788.3ps   38.12uV    2.137uV    1.057mV
827.6ps   -273.4uV   -6.082uV   113.7mV
943.6ps   24.35mV    -92.8uV    1.045V
1.03ns    425mV      -1.16mV    1.349V
1.135ns   889.7mV    43.54mV    1.413V
1.229ns   1.073V     296.3mV    1.424V
1.448ns   1.139V     729.9mV    1.43V
1.796ns   1.148V     829mV      1.433V
333.3ns   1.163V     864.5mV    1.438V
[Rising Waveform]
R_fixture = 50
V_fixture = 3.3
V_fixture_min = 3
V_fixture_max = 3.6
| Time   V(typ)   V(min)   V(max)
0s        2.704V     2.61V      2.735V
738.6ps   2.704V     2.61V      2.747V
781.8ps   2.704V     2.61V      2.854V
833.4ps   2.706V     2.61V      3.404V
868.1ps   2.723V     2.61V      3.554V
909.1ps   2.814V     2.609V     3.591V
990.9ps   3.252V     2.616V     3.599V
1.058ns   3.295V     2.671V     3.599V
1.185ns   3.299V     2.985V     3.6V
333.3ns   3.3V       3V         3.6V
[Add Submodel]
| Submodel Name Mode
M1_PBIDIR_E33_DR_0_3P30V_T All
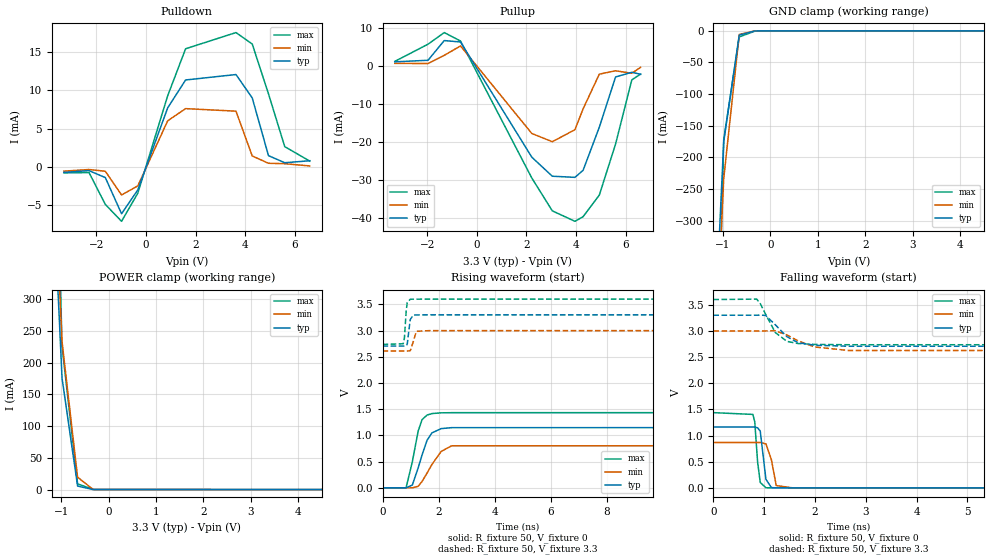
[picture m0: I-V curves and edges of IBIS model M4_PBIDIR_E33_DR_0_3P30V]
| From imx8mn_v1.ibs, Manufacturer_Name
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[Model] M4_PBIDIR_E33_DR_0_3P30V
Model_type I/O
Vinl  =  0.54
Vinh  =  1.26
Vmeas =  0.9
| Capacitance   typ   min   max
C_comp   7.43257478797e-13   6.80162949915e-13   7.72418772183e-13
| Variables   typ   min   max
[GND Clamp Reference]   0   0   0
[POWER Clamp Reference]   3.3   3   3.6
[Pulldown Reference]   0   0   0
[Pullup Reference]   3.3   3   3.6
[Temperature Range]   25   125   -40
[Voltage Range]   3.3   3   3.6
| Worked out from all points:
|   slope of the pulldown table from 0 to 0.495 V, typ, clamps not added: 110 ohm
|   slope of the pullup table from 0 to 0.495 V, typ, clamps not added: 90.3 ohm
|   falling waveform, R_fixture 50, V_fixture 0: 20-80 % time 69.8ps typ, 75.1ps min, 68ps max; typ from 1.16 V to 0 V
|   falling waveform, R_fixture 50, V_fixture 3.3: 20-80 % time 386ps typ, 565ps min, 296ps max; typ from 3.3 V to 2.7 V
|   rising waveform, R_fixture 50, V_fixture 0: 20-80 % time 422ps typ, 618ps min, 319ps max; typ from 0 V to 1.16 V
|   rising waveform, R_fixture 50, V_fixture 3.3: 20-80 % time 69.2ps typ, 79.4ps min, 63.2ps max; typ from 2.7 V to 3.3 V
[GND Clamp]
| Voltage   I(typ)   I(min)   I(max)
-3.3V     -7.887A    -7.417A    -8.531A
-1.309V   -700.1mA   -755mA     -1.16A
-981.8mV  -175.2mA   -233.5mA   -172.1mA
-654.5mV  -6.799mA   -5.773mA   -9.66mA
-327.3mV  -189uA     -156uA     -585.6uA
0V        -136.9nA   -148nA     -612.9nA
6.6V      0A         0A         0A
[POWER Clamp]
| Voltage   I(typ)   I(min)   I(max)
-3.3V     7.896A     7.466A     8.506A
-1.309V   700.9mA    749.4mA    1.174A
-981.8mV  175.4mA    232.7mA    224.9mA
-654.5mV  5.603mA    19.51mA    9.05mA
-327.3mV  73.82uA    354.9uA    410.8uA
-300mV    34.66uA    61.21uA    374.3uA
6.6V      0A         0A         0A
[Pulldown]
| Voltage   I(typ)   I(min)   I(max)
-3.3V     -742uA     -574.3uA   -803.9uA
-2.291V   -508.3uA   -362.4uA   -762.5uA
-1.636V   -1.416mA   -585.9uA   -4.925mA
-981.8mV  -6.147mA   -3.691mA   -7.135mA
-327.3mV  -3.029mA   -2.506mA   -3.462mA
876.6mV   7.705mA    6.01mA     9.281mA
1.598V    11.35mA    7.602mA    15.43mA
3.627V    12.06mA    7.27mA     17.55mA
4.282V    8.999mA    1.41mA     16.05mA
4.936V    1.454mA    453.5uA    9.535mA
5.591V    525uA      398.6uA    2.629mA
6.6V      785.2uA    104uA      736.5uA
[Pullup]
| Voltage   I(typ)   I(min)   I(max)
-3.3V     1.164mA    764uA      1.285mA
-1.964V   1.577mA    712uA      5.816mA
-1.309V   6.778mA    2.881mA    8.891mA
-654.5mV  6.402mA    5.355mA    6.657mA
2.217V    -24mA      -17.75mA   -29.5mA
3.042V    -29.03mA   -19.92mA   -38.17mA
3.955V    -29.33mA   -16.75mA   -40.93mA
4.282V    -27.48mA   -11.26mA   -39.72mA
4.936V    -16.1mA    -2.085mA   -34.01mA
5.591V    -2.826mA   -1.202mA   -20.54mA
6.245V    -1.59mA    -1.858mA   -3.588mA
6.6V      -2.118mA   -276.6uA   -2.072mA
[Ramp]
dV/dt_r   0.697707/0.422415n  0.518677/0.617538n  0.862818/0.31935n
dV/dt_f   0.357755/0.38615n  0.234163/0.564676n  0.51872/0.295766n
R_load = 50
[Falling Waveform]
R_fixture = 50
V_fixture = 0
V_fixture_min = 0
V_fixture_max = 0
| Time   V(typ)   V(min)   V(max)
0s        1.163V     866.9mV    1.438V
777.4ps   1.163V     866.9mV    1.404V
814.5ps   1.163V     866.9mV    1.264V
869.9ps   1.148V     867mV      498mV
922.3ps   1.086V     867mV      103.2mV
1.034ns   163.8mV    841.5mV    2.29mV
1.142ns   4.979mV    538.1mV    694.6uV
1.237ns   960.2uV    43.64mV    487.6uV
1.557ns   333.8uV    568.6uV    204.4uV
333.3ns   4.336uV    5.069uV    18.21uV
[Falling Waveform]
R_fixture = 50
V_fixture = 3.3
V_fixture_min = 3
V_fixture_max = 3.6
| Time   V(typ)   V(min)   V(max)
0s        3.3V       3V         3.6V
852.4ps   3.301V     3V         3.608V
923.6ps   3.302V     3V         3.522V
1.027ns   3.297V     3.001V     3.321V
1.22ns    3.117V     3.003V     2.968V
1.448ns   2.889V     2.922V     2.8V
1.667ns   2.776V     2.812V     2.759V
1.987ns   2.727V     2.694V     2.742V
2.66ns    2.707V     2.626V     2.736V
333.3ns   2.704V     2.61V      2.735V
[Rising Waveform]
R_fixture = 50
V_fixture = 0
V_fixture_min = 0
V_fixture_max = 0
| Time   V(typ)   V(min)   V(max)
0s        4.336uV    5.068uV    18.21uV
838.5ps   -509.7uV   -22.48uV   -1.708mV
1.061ns   50.24mV    -1.654mV   492.3mV
1.271ns   379.8mV    28.5mV     1.084V
1.41ns    626.7mV    120.8mV    1.301V
1.587ns   905.8mV    280.1mV    1.387V
1.763ns   1.048V     446.5mV    1.416V
2.092ns   1.129V     693.1mV    1.43V
2.459ns   1.147V     800.4mV    1.433V
333.3ns   1.163V     864.5mV    1.438V
[Rising Waveform]
R_fixture = 50
V_fixture = 3.3
V_fixture_min = 3
V_fixture_max = 3.6
| Time   V(typ)   V(min)   V(max)
0s        2.704V     2.61V      2.735V
738ps     2.704V     2.61V      2.748V
780.5ps   2.703V     2.61V      2.856V
842.2ps   2.709V     2.61V      3.368V
880.6ps   2.741V     2.61V      3.533V
987.9ps   3.21V      2.615V     3.598V
1.097ns   3.296V     2.789V     3.599V
1.205ns   3.299V     2.986V     3.599V
1.678ns   3.3V       2.999V     3.6V
333.3ns   3.3V       3V         3.6V
[Add Submodel]
| Submodel Name Mode
M4_PBIDIR_E33_DR_0_3P30V_T All
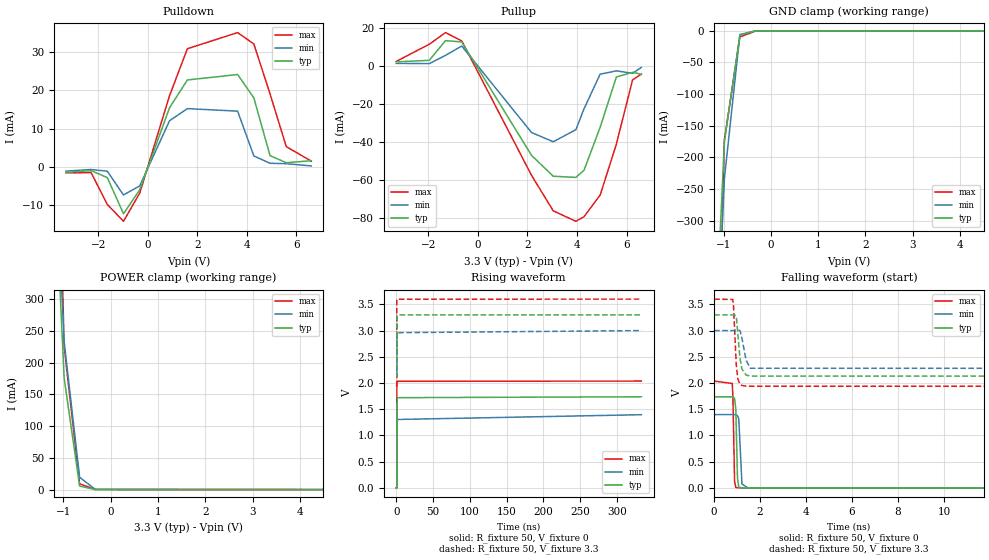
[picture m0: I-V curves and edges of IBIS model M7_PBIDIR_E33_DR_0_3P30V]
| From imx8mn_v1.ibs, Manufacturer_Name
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[Model] M7_PBIDIR_E33_DR_0_3P30V
Model_type I/O
Vinl  =  0.54
Vinh  =  1.26
Vmeas =  0.9
| Capacitance   typ   min   max
C_comp   7.43257478797e-13   6.80162949915e-13   7.72418772183e-13
| Variables   typ   min   max
[GND Clamp Reference]   0   0   0
[POWER Clamp Reference]   3.3   3   3.6
[Pulldown Reference]   0   0   0
[Pullup Reference]   3.3   3   3.6
[Temperature Range]   25   125   -40
[Voltage Range]   3.3   3   3.6
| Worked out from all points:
|   slope of the pulldown table from 0 to 0.495 V, typ, clamps not added: 55.1 ohm
|   slope of the pullup table from 0 to 0.495 V, typ, clamps not added: 45.2 ohm
|   falling waveform, R_fixture 50, V_fixture 0: 20-80 % time 53.1ps typ, 64.9ps min, 45.4ps max; typ from 1.74 V to 0 V
|   falling waveform, R_fixture 50, V_fixture 3.3: 20-80 % time 151ps typ, 218ps min, 112ps max; typ from 3.3 V to 2.12 V
|   rising waveform, R_fixture 50, V_fixture 0: 20-80 % time 127ps typ, 203ps min, 88.2ps max; typ from 0 V to 1.74 V
|   rising waveform, R_fixture 50, V_fixture 3.3: 20-80 % time 52.2ps typ, 66.3ps min, 42.6ps max; typ from 2.12 V to 3.3 V
[GND Clamp]
| Voltage   I(typ)   I(min)   I(max)
-3.3V     -7.887A    -7.417A    -8.531A
-1.309V   -700.1mA   -755mA     -1.16A
-981.8mV  -175.2mA   -233.5mA   -172.1mA
-654.5mV  -6.799mA   -5.773mA   -9.66mA
-327.3mV  -189uA     -156uA     -585.6uA
0V        -136.9nA   -148nA     -612.9nA
6.6V      0A         0A         0A
[POWER Clamp]
| Voltage   I(typ)   I(min)   I(max)
-3.3V     7.896A     7.466A     8.506A
-1.309V   700.9mA    749.4mA    1.174A
-981.8mV  175.4mA    232.7mA    224.9mA
-654.5mV  5.603mA    19.51mA    9.05mA
-327.3mV  73.82uA    354.9uA    410.8uA
-300mV    34.66uA    61.21uA    374.3uA
6.6V      0A         0A         0A
[Pulldown]
| Voltage   I(typ)   I(min)   I(max)
-3.3V     -1.484mA   -1.148mA   -1.609mA
-2.291V   -1.017mA   -725uA     -1.524mA
-1.636V   -2.832mA   -1.172mA   -9.849mA
-981.8mV  -12.29mA   -7.382mA   -14.27mA
-327.3mV  -6.057mA   -5.013mA   -6.923mA
876.6mV   15.41mA    12.02mA    18.56mA
1.598V    22.69mA    15.2mA     30.86mA
3.627V    24.12mA    14.54mA    35.09mA
4.282V    18mA       2.819mA    32.11mA
4.936V    2.907mA    907.2uA    19.07mA
5.591V    1.05mA     796.8uA    5.258mA
6.6V      1.571mA    208.9uA    1.473mA
[Pullup]
| Voltage   I(typ)   I(min)   I(max)
-3.3V     2.333mA    1.529mA    2.585mA
-1.964V   3.158mA    1.425mA    11.64mA
-1.309V   13.56mA    5.763mA    17.81mA
-654.5mV  12.85mA    10.71mA    13.41mA
2.166V    -47.07mA   -35mA      -57.62mA
3.042V    -58.06mA   -39.84mA   -76.34mA
3.955V    -58.67mA   -33.49mA   -81.86mA
4.282V    -54.95mA   -22.51mA   -79.43mA
4.936V    -32.2mA    -4.169mA   -68.02mA
5.591V    -5.653mA   -2.404mA   -41.09mA
6.245V    -3.18mA    -3.715mA   -7.177mA
6.6V      -4.237mA   -554.1uA   -4.143mA
[Ramp]
dV/dt_r   1.04199/0.126833n  0.836975/0.202769n  1.2222/88.1651p
dV/dt_f   0.70585/0.150634n  0.465301/0.217714n  0.99751/0.112446n
R_load = 50
[Falling Waveform]
R_fixture = 50
V_fixture = 0
V_fixture_min = 0
V_fixture_max = 0
| Time   V(typ)   V(min)   V(max)
0s        1.737V     1.397V     2.037V
787.9ps   1.737V     1.397V     1.991V
816.1ps   1.737V     1.397V     1.79V
892.2ps   1.704V     1.397V     122.9mV
943.9ps   1.514V     1.397V     7.932mV
1.019ns   186.1mV    1.375V     1.179mV
1.074ns   12.21mV    1.315V     657.1uV
1.213ns   893uV      73.41mV    232uV
1.466ns   201.7uV    778.5uV    71.12uV
333.3ns   3.019uV    3.752uV    12.06uV
[Falling Waveform]
R_fixture = 50
V_fixture = 3.3
V_fixture_min = 3
V_fixture_max = 3.6
| Time   V(typ)   V(min)   V(max)
0s        3.3V       3V         3.6V
812.8ps   3.3V       3V         3.594V
844.2ps   3.302V     3V         3.484V
964.5ps   3.28V      3.001V     2.346V
1.032ns   2.946V     3.002V     2.081V
1.122ns   2.49V      3.004V     1.98V
1.209ns   2.267V     2.862V     1.954V
1.391ns   2.152V     2.437V     1.94V
1.578ns   2.131V     2.282V     1.938V
333.3ns   2.124V     2.224V     1.937V
[Rising Waveform]
R_fixture = 50
V_fixture = 0
V_fixture_min = 0
V_fixture_max = 0
| Time   V(typ)   V(min)   V(max)
0s        3.009uV    3.737uV    12.05uV
785.1ps   26.57uV    2.799uV    1.336mV
824.6ps   -486.8uV   -6.082uV   164.2mV
923.5ps   4.054mV    -58.8uV    1.552V
975.9ps   241.4mV    -701.4uV   1.908V
1.096ns   1.266V     5.983mV    2.006V
1.158ns   1.56V      167.8mV    2.018V
1.366ns   1.704V     1.067V     2.03V
1.556ns   1.72V      1.304V     2.032V
333.3ns   1.737V     1.395V     2.037V
[Rising Waveform]
R_fixture = 50
V_fixture = 3.3
V_fixture_min = 3
V_fixture_max = 3.6
| Time   V(typ)   V(min)   V(max)
0s        2.124V     2.224V     1.937V
743.4ps   2.124V     2.224V     1.963V
784.5ps   2.123V     2.224V     2.179V
834.1ps   2.129V     2.224V     3.284V
860.6ps   2.149V     2.224V     3.53V
908.4ps   2.333V     2.224V     3.594V
986.8ps   3.224V     2.234V     3.598V
1.059ns   3.296V     2.354V     3.599V
1.165ns   3.299V     2.96V      3.599V
333.3ns   3.3V       3V         3.6V
[Add Submodel]
| Submodel Name Mode
M7_PBIDIR_E33_DR_0_3P30V_T All
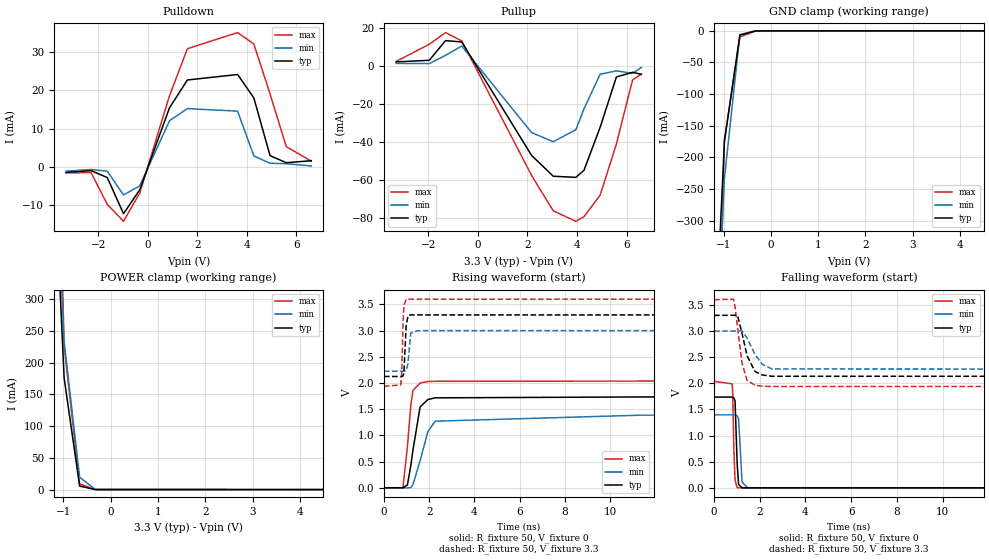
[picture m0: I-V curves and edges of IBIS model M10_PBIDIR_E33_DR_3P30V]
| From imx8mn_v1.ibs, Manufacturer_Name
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[Model] M10_PBIDIR_E33_DR_3P30V
Model_type I/O
Vinl  =  0.54
Vinh  =  1.26
Vmeas =  0.9
| Capacitance   typ   min   max
C_comp   7.43257478797e-13   6.80162949915e-13   7.72418772183e-13
| Variables   typ   min   max
[GND Clamp Reference]   0   0   0
[POWER Clamp Reference]   3.3   3   3.6
[Pulldown Reference]   0   0   0
[Pullup Reference]   3.3   3   3.6
[Temperature Range]   25   125   -40
[Voltage Range]   3.3   3   3.6
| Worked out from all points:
|   slope of the pulldown table from 0 to 0.495 V, typ, clamps not added: 55.1 ohm
|   slope of the pullup table from 0 to 0.495 V, typ, clamps not added: 45.2 ohm
|   falling waveform, R_fixture 50, V_fixture 0: 20-80 % time 70.5ps typ, 74.9ps min, 65.6ps max; typ from 1.74 V to 0 V
|   falling waveform, R_fixture 50, V_fixture 3.3: 20-80 % time 407ps typ, 606ps min, 297ps max; typ from 3.3 V to 2.12 V
|   rising waveform, R_fixture 50, V_fixture 0: 20-80 % time 342ps typ, 537ps min, 244ps max; typ from 0 V to 1.74 V
|   rising waveform, R_fixture 50, V_fixture 3.3: 20-80 % time 68.6ps typ, 78.6ps min, 61.5ps max; typ from 2.12 V to 3.3 V
[GND Clamp]
| Voltage   I(typ)   I(min)   I(max)
-3.3V     -7.887A    -7.417A    -8.531A
-1.309V   -700.1mA   -755mA     -1.16A
-981.8mV  -175.2mA   -233.5mA   -172.1mA
-654.5mV  -6.799mA   -5.773mA   -9.66mA
-327.3mV  -189uA     -156uA     -585.6uA
0V        -136.9nA   -148nA     -612.9nA
6.6V      0A         0A         0A
[POWER Clamp]
| Voltage   I(typ)   I(min)   I(max)
-3.3V     7.896A     7.466A     8.506A
-1.309V   700.9mA    749.4mA    1.174A
-981.8mV  175.4mA    232.7mA    224.9mA
-654.5mV  5.603mA    19.51mA    9.05mA
-327.3mV  73.82uA    354.9uA    410.8uA
-300mV    34.66uA    61.21uA    374.3uA
6.6V      0A         0A         0A
[Pulldown]
| Voltage   I(typ)   I(min)   I(max)
-3.3V     -1.484mA   -1.148mA   -1.609mA
-2.291V   -1.017mA   -725uA     -1.524mA
-1.636V   -2.832mA   -1.172mA   -9.849mA
-981.8mV  -12.29mA   -7.382mA   -14.27mA
-327.3mV  -6.057mA   -5.013mA   -6.923mA
876.6mV   15.41mA    12.02mA    18.56mA
1.598V    22.69mA    15.2mA     30.86mA
3.627V    24.12mA    14.54mA    35.09mA
4.282V    18mA       2.819mA    32.11mA
4.936V    2.907mA    907.2uA    19.07mA
5.591V    1.05mA     796.8uA    5.258mA
6.6V      1.571mA    208.9uA    1.473mA
[Pullup]
| Voltage   I(typ)   I(min)   I(max)
-3.3V     2.333mA    1.529mA    2.585mA
-1.964V   3.158mA    1.425mA    11.64mA
-1.309V   13.56mA    5.763mA    17.81mA
-654.5mV  12.85mA    10.71mA    13.41mA
2.166V    -47.07mA   -35mA      -57.62mA
3.042V    -58.06mA   -39.84mA   -76.34mA
3.955V    -58.67mA   -33.49mA   -81.86mA
4.282V    -54.95mA   -22.51mA   -79.43mA
4.936V    -32.2mA    -4.169mA   -68.02mA
5.591V    -5.653mA   -2.404mA   -41.09mA
6.245V    -3.18mA    -3.715mA   -7.177mA
6.6V      -4.237mA   -554.1uA   -4.143mA
[Ramp]
dV/dt_r   1.04199/0.341677n  0.836971/0.53719n  1.2222/0.243999n
dV/dt_f   0.70585/0.407262n  0.4653/0.605825n  0.99751/0.297317n
R_load = 50
[Falling Waveform]
R_fixture = 50
V_fixture = 0
V_fixture_min = 0
V_fixture_max = 0
| Time   V(typ)   V(min)   V(max)
0s        1.737V     1.397V     2.037V
787.4ps   1.737V     1.397V     1.99V
814.8ps   1.737V     1.397V     1.829V
864.3ps   1.724V     1.397V     755.7mV
917.3ps   1.665V     1.397V     152.2mV
1.011ns   458.7mV    1.379V     2.691mV
1.073ns   66.36mV    1.316V     1.156mV
1.225ns   1.207mV    107.6mV    642.9uV
1.475ns   552.1uV    974.9uV    317.2uV
333.3ns   3.009uV    3.737uV    12.05uV
[Falling Waveform]
R_fixture = 50
V_fixture = 3.3
V_fixture_min = 3
V_fixture_max = 3.6
| Time   V(typ)   V(min)   V(max)
0s        3.3V       3V         3.6V
851.5ps   3.302V     3V         3.611V
924.6ps   3.304V     3V         3.445V
1.032ns   3.289V     3.002V     3.049V
1.225ns   2.952V     3.003V     2.382V
1.446ns   2.526V     2.863V     2.056V
1.79ns    2.226V     2.551V     1.963V
2.112ns   2.16V      2.364V     1.945V
2.533ns   2.135V     2.275V     1.939V
333.3ns   2.124V     2.224V     1.937V
[Rising Waveform]
R_fixture = 50
V_fixture = 0
V_fixture_min = 0
V_fixture_max = 0
| Time   V(typ)   V(min)   V(max)
0s        3.009uV    3.737uV    12.05uV
837.6ps   -890.9uV   -21.26uV   -1.169mV
1.038ns   53.83mV    -2.183mV   787.3mV
1.189ns   431.2mV    1.648mV    1.581V
1.285ns   725.8mV    65.5mV     1.859V
1.598ns   1.542V     517.9mV    1.999V
1.94ns    1.683V     1.068V     2.027V
2.261ns   1.716V     1.27V      2.032V
11.43ns   1.733V     1.386V     2.036V
333.3ns   1.737V     1.395V     2.037V
[Rising Waveform]
R_fixture = 50
V_fixture = 3.3
V_fixture_min = 3
V_fixture_max = 3.6
| Time   V(typ)   V(min)   V(max)
0s        2.124V     2.224V     1.937V
742.8ps   2.124V     2.224V     1.963V
784.5ps   2.123V     2.224V     2.174V
843.4ps   2.134V     2.224V     3.144V
880.9ps   2.192V     2.224V     3.478V
982.7ps   3.086V     2.233V     3.598V
1.063ns   3.285V     2.374V     3.599V
1.182ns   3.299V     2.949V     3.599V
1.49ns    3.299V     2.999V     3.599V
333.3ns   3.3V       3V         3.6V
[Add Submodel]
| Submodel Name Mode
M10_PBIDIR_E33_DR_3P30V_T All
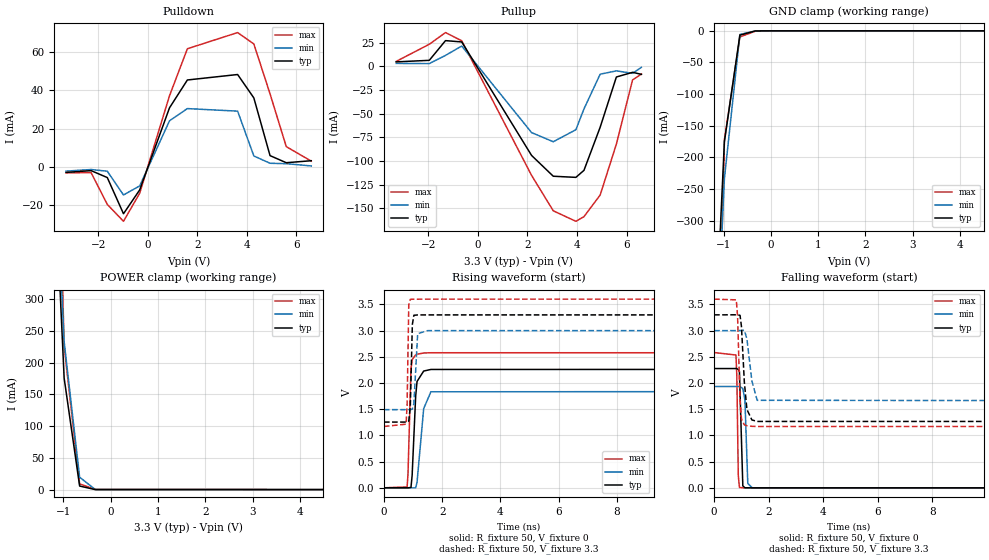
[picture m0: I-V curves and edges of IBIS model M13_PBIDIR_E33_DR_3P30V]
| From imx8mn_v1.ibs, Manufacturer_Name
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[Model] M13_PBIDIR_E33_DR_3P30V
Model_type I/O
Vinl  =  0.54
Vinh  =  1.26
Vmeas =  0.9
| Capacitance   typ   min   max
C_comp   7.43257478797e-13   6.80162949915e-13   7.72418772183e-13
| Variables   typ   min   max
[GND Clamp Reference]   0   0   0
[POWER Clamp Reference]   3.3   3   3.6
[Pulldown Reference]   0   0   0
[Pullup Reference]   3.3   3   3.6
[Temperature Range]   25   125   -40
[Voltage Range]   3.3   3   3.6
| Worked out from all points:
|   slope of the pulldown table from 0 to 0.495 V, typ, clamps not added: 27.6 ohm
|   slope of the pullup table from 0 to 0.495 V, typ, clamps not added: 22.6 ohm
|   falling waveform, R_fixture 50, V_fixture 0: 20-80 % time 50.2ps typ, 67.3ps min, 40.7ps max; typ from 2.28 V to 0 V
|   falling waveform, R_fixture 50, V_fixture 3.3: 20-80 % time 142ps typ, 257ps min, 81.9ps max; typ from 3.3 V to 1.25 V
|   rising waveform, R_fixture 50, V_fixture 0: 20-80 % time 110ps typ, 189ps min, 72.9ps max; typ from 0 V to 2.27 V
|   rising waveform, R_fixture 50, V_fixture 3.3: 20-80 % time 49.4ps typ, 66.7ps min, 36.1ps max; typ from 1.25 V to 3.3 V
[GND Clamp]
| Voltage   I(typ)   I(min)   I(max)
-3.3V     -7.887A    -7.417A    -8.531A
-1.309V   -700.1mA   -755mA     -1.16A
-981.8mV  -175.2mA   -233.5mA   -172.1mA
-654.5mV  -6.799mA   -5.773mA   -9.66mA
-327.3mV  -189uA     -156uA     -585.6uA
0V        -136.9nA   -148nA     -612.9nA
6.6V      0A         0A         0A
[POWER Clamp]
| Voltage   I(typ)   I(min)   I(max)
-3.3V     7.896A     7.466A     8.506A
-1.309V   700.9mA    749.4mA    1.174A
-981.8mV  175.4mA    232.7mA    224.9mA
-654.5mV  5.603mA    19.51mA    9.05mA
-327.3mV  73.82uA    354.9uA    410.8uA
-300mV    34.66uA    61.21uA    374.3uA
6.6V      0A         0A         0A
[Pulldown]
| Voltage   I(typ)   I(min)   I(max)
-3.3V     -2.968mA   -2.297mA   -3.218mA
-2.291V   -2.034mA   -1.45mA    -3.049mA
-1.636V   -5.663mA   -2.344mA   -19.7mA
-981.8mV  -24.59mA   -14.77mA   -28.54mA
-327.3mV  -12.11mA   -10.03mA   -13.85mA
876.6mV   30.82mA    24.04mA    37.12mA
1.598V    45.38mA    30.41mA    61.72mA
3.627V    48.24mA    29.08mA    70.18mA
4.282V    36mA       5.638mA    64.22mA
4.936V    5.814mA    1.814mA    38.14mA
5.591V    2.1mA      1.594mA    10.52mA
6.6V      3.142mA    418.6uA    2.946mA
[Pullup]
| Voltage   I(typ)   I(min)   I(max)
-3.3V     4.668mA    3.056mA    5.184mA
-1.964V   6.316mA    2.848mA    23.29mA
-1.309V   27.12mA    11.52mA    35.63mA
-654.5mV  25.73mA    21.43mA    26.93mA
2.166V    -94.13mA   -70mA      -115.2mA
3.042V    -116.1mA   -79.68mA   -152.6mA
3.955V    -117.3mA   -66.98mA   -163.7mA
4.282V    -109.9mA   -45.03mA   -158.8mA
4.936V    -64.36mA   -8.337mA   -136mA
5.591V    -11.3mA    -4.808mA   -82.14mA
6.245V    -6.357mA   -7.431mA   -14.34mA
6.6V      -8.472mA   -1.107mA   -8.283mA
[Ramp]
dV/dt_r   1.36518/0.109966n  1.15843/0.189261n  1.54885/72.876p
dV/dt_f   1.22777/0.141872n  0.905452/0.257376n  1.45798/81.9028p
R_load = 50
[Falling Waveform]
R_fixture = 50
V_fixture = 0
V_fixture_min = 0
V_fixture_max = 0
| Time   V(typ)   V(min)   V(max)
0s        2.276V     1.933V     2.581V
802.3ps   2.276V     1.933V     2.534V
834.9ps   2.274V     1.933V     2.141V
888.5ps   2.258V     1.933V     239.5mV
930.1ps   2.219V     1.933V     8.405mV
1.055ns   37.49mV    1.898V     965.1uV
1.132ns   1.958mV    1.676V     564.4uV
1.237ns   946.3uV    85.29mV    306.5uV
1.401ns   412.8uV    1.303mV    132.7uV
333.3ns   1.659uV    2.292uV    6.051uV
[Falling Waveform]
R_fixture = 50
V_fixture = 3.3
V_fixture_min = 3
V_fixture_max = 3.6
| Time   V(typ)   V(min)   V(max)
0s        3.3V       3V         3.6V
815.7ps   3.301V     3V         3.586V
863.3ps   3.302V     3V         3.263V
952.8ps   3.29V      3.001V     1.668V
1.005ns   3.077V     3.002V     1.313V
1.111ns   2.016V     3.006V     1.202V
1.205ns   1.496V     2.842V     1.184V
1.387ns   1.296V     2.042V     1.174V
1.582ns   1.267V     1.67V      1.171V
333.3ns   1.254V     1.491V     1.17V
[Rising Waveform]
R_fixture = 50
V_fixture = 0
V_fixture_min = 0
V_fixture_max = 0
| Time   V(typ)   V(min)   V(max)
0s        1.647uV    2.28uV     6.042uV
794.8ps   -193.3uV   16.1uV     16.33mV
826.1ps   -1.153mV   16.64uV    259.8mV
928.7ps   8.225mV    -321.9uV   2.266V
968.4ps   238mV      -1.192mV   2.445V
1.09ns    1.752V     -1.299mV   2.537V
1.137ns   2.029V     105.5mV    2.549V
1.365ns   2.228V     1.511V     2.572V
1.613ns   2.258V     1.832V     2.577V
333.3ns   2.275V     1.931V     2.581V
[Rising Waveform]
R_fixture = 50
V_fixture = 3.3
V_fixture_min = 3
V_fixture_max = 3.6
| Time   V(typ)   V(min)   V(max)
0s        1.254V     1.491V     1.17V
760.6ps   1.254V     1.491V     1.214V
794.9ps   1.253V     1.491V     1.575V
852.9ps   1.275V     1.491V     3.496V
906ps     1.558V     1.49V      3.596V
975.6ps   3.115V     1.504V     3.598V
1.028ns   3.292V     1.605V     3.598V
1.158ns   3.298V     2.94V      3.599V
1.498ns   3.299V     2.999V     3.6V
333.3ns   3.3V       3V         3.6V
[Add Submodel]
| Submodel Name Mode
M13_PBIDIR_E33_DR_3P30V_T All
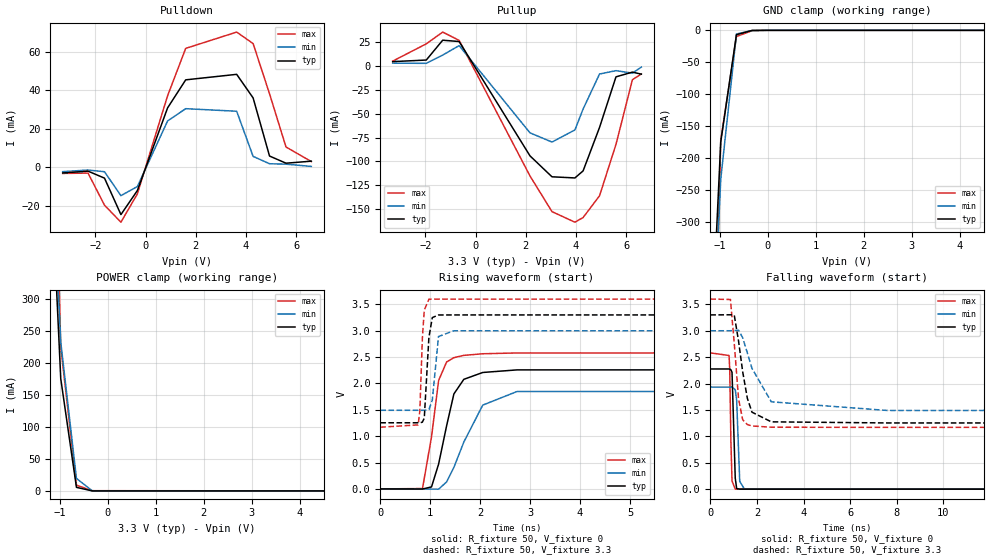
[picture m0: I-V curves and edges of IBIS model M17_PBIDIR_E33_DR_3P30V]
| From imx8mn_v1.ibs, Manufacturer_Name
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[Model] M17_PBIDIR_E33_DR_3P30V
Model_type I/O
Vinl  =  0.54
Vinh  =  1.26
Vmeas =  0.9
| Capacitance   typ   min   max
C_comp   7.43257478797e-13   6.80162949915e-13   7.72418772183e-13
| Variables   typ   min   max
[GND Clamp Reference]   0   0   0
[POWER Clamp Reference]   3.3   3   3.6
[Pulldown Reference]   0   0   0
[Pullup Reference]   3.3   3   3.6
[Temperature Range]   25   125   -40
[Voltage Range]   3.3   3   3.6
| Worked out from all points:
|   slope of the pulldown table from 0 to 0.495 V, typ, clamps not added: 27.6 ohm
|   slope of the pullup table from 0 to 0.495 V, typ, clamps not added: 22.6 ohm
|   falling waveform, R_fixture 50, V_fixture 0: 20-80 % time 72ps typ, 84.8ps min, 61.9ps max; typ from 2.28 V to 0 V
|   falling waveform, R_fixture 50, V_fixture 3.3: 20-80 % time 435ps typ, 786ps min, 255ps max; typ from 3.3 V to 1.25 V
|   rising waveform, R_fixture 50, V_fixture 0: 20-80 % time 318ps typ, 543ps min, 213ps max; typ from 0 V to 2.27 V
|   rising waveform, R_fixture 50, V_fixture 3.3: 20-80 % time 62.9ps typ, 74.9ps min, 56ps max; typ from 1.25 V to 3.3 V
[GND Clamp]
| Voltage   I(typ)   I(min)   I(max)
-3.3V     -7.887A    -7.417A    -8.531A
-1.309V   -700.1mA   -755mA     -1.16A
-981.8mV  -175.2mA   -233.5mA   -172.1mA
-654.5mV  -6.799mA   -5.773mA   -9.66mA
-327.3mV  -189uA     -156uA     -585.6uA
0V        -136.9nA   -148nA     -612.9nA
6.6V      0A         0A         0A
[POWER Clamp]
| Voltage   I(typ)   I(min)   I(max)
-3.3V     7.896A     7.466A     8.506A
-1.309V   700.9mA    749.4mA    1.174A
-981.8mV  175.4mA    232.7mA    224.9mA
-654.5mV  5.603mA    19.51mA    9.05mA
-327.3mV  73.82uA    354.9uA    410.8uA
-300mV    34.66uA    61.21uA    374.3uA
6.6V      0A         0A         0A
[Pulldown]
| Voltage   I(typ)   I(min)   I(max)
-3.3V     -2.968mA   -2.297mA   -3.218mA
-2.291V   -2.034mA   -1.45mA    -3.049mA
-1.636V   -5.663mA   -2.344mA   -19.7mA
-981.8mV  -24.59mA   -14.76mA   -28.54mA
-327.3mV  -12.11mA   -10.03mA   -13.85mA
876.6mV   30.82mA    24.04mA    37.12mA
1.598V    45.38mA    30.41mA    61.72mA
3.627V    48.24mA    29.08mA    70.18mA
4.282V    36mA       5.638mA    64.22mA
4.936V    5.814mA    1.814mA    38.14mA
5.591V    2.1mA      1.594mA    10.52mA
6.6V      3.142mA    418.6uA    2.946mA
[Pullup]
| Voltage   I(typ)   I(min)   I(max)
-3.3V     4.668mA    3.056mA    5.184mA
-1.964V   6.316mA    2.848mA    23.29mA
-1.309V   27.12mA    11.52mA    35.63mA
-654.5mV  25.73mA    21.43mA    26.93mA
2.166V    -94.13mA   -70mA      -115.2mA
3.042V    -116.1mA   -79.68mA   -152.6mA
3.955V    -117.3mA   -66.98mA   -163.7mA
4.282V    -109.9mA   -45.03mA   -158.8mA
4.936V    -64.36mA   -8.337mA   -136mA
5.591V    -11.3mA    -4.808mA   -82.14mA
6.245V    -6.357mA   -7.431mA   -14.34mA
6.6V      -8.472mA   -1.107mA   -8.283mA
[Ramp]
dV/dt_r   1.36518/0.318232n  1.15843/0.542874n  1.54885/0.212828n
dV/dt_f   1.22777/0.435116n  0.905451/0.78554n  1.45798/0.255478n
R_load = 50
[Falling Waveform]
R_fixture = 50
V_fixture = 0
V_fixture_min = 0
V_fixture_max = 0
| Time   V(typ)   V(min)   V(max)
0s        2.276V     1.933V     2.581V
805.8ps   2.276V     1.933V     2.531V
834.1ps   2.274V     1.933V     2.27V
885ps     2.26V      1.933V     889.8mV
932.6ps   2.213V     1.933V     156.5mV
1.071ns   207.9mV    1.884V     1.306mV
1.132ns   10.9mV     1.681V     1.021mV
1.263ns   1.218mV    147.8mV    699uV
1.466ns   693.4uV    1.346mV    421.9uV
333.3ns   1.652uV    2.283uV    6.045uV
[Falling Waveform]
R_fixture = 50
V_fixture = 3.3
V_fixture_min = 3
V_fixture_max = 3.6
| Time   V(typ)   V(min)   V(max)
0s        3.3V       3V         3.6V
864.2ps   3.302V     3V         3.592V
1.029ns   3.295V     3.003V     2.757V
1.213ns   2.803V     3.012V     1.71V
1.389ns   2.226V     2.868V     1.315V
1.589ns   1.722V     2.581V     1.224V
1.788ns   1.458V     2.288V     1.197V
2.617ns   1.275V     1.654V     1.173V
7.579ns   1.254V     1.491V     1.17V
333.3ns   1.254V     1.491V     1.17V
[Rising Waveform]
R_fixture = 50
V_fixture = 0
V_fixture_min = 0
V_fixture_max = 0
| Time   V(typ)   V(min)   V(max)
0s        1.647uV    2.28uV     6.042uV
845.3ps   -2.067mV   -13.24uV   6.831mV
1.026ns   37.77mV    -3.437mV   986.7mV
1.168ns   470.7mV    -4.823mV   2.056V
1.328ns   1.196V     132.6mV    2.407V
1.474ns   1.801V     408.3mV    2.489V
1.673ns   2.078V     888.2mV    2.532V
2.052ns   2.208V     1.589V     2.563V
2.738ns   2.257V     1.847V     2.578V
333.3ns   2.275V     1.931V     2.581V
[Rising Waveform]
R_fixture = 50
V_fixture = 3.3
V_fixture_min = 3
V_fixture_max = 3.6
| Time   V(typ)   V(min)   V(max)
0s        1.254V     1.491V     1.17V
759.6ps   1.254V     1.491V     1.214V
792.9ps   1.253V     1.491V     1.491V
842.7ps   1.266V     1.491V     2.857V
881.1ps   1.342V     1.491V     3.392V
973.9ps   2.876V     1.503V     3.597V
1.042ns   3.249V     1.685V     3.598V
1.166ns   3.298V     2.889V     3.599V
1.468ns   3.299V     2.998V     3.599V
333.3ns   3.3V       3V         3.6V
[Add Submodel]
| Submodel Name Mode
M17_PBIDIR_E33_DR_3P30V_T All
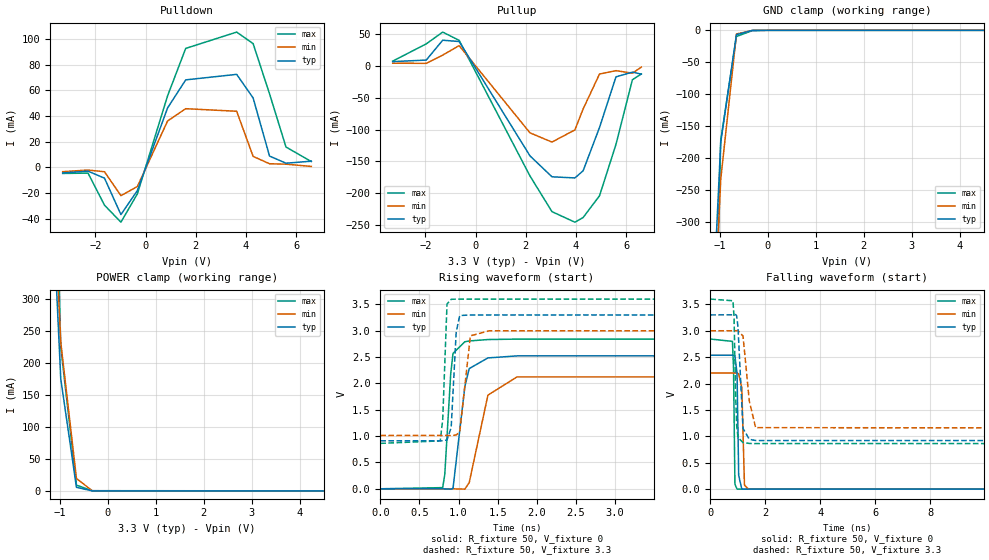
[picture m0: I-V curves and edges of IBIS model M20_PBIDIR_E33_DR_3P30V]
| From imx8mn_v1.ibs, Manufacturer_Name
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[Model] M20_PBIDIR_E33_DR_3P30V
Model_type I/O
Vinl  =  0.54
Vinh  =  1.26
Vmeas =  0.9
| Capacitance   typ   min   max
C_comp   7.43257478797e-13   6.80162949915e-13   7.72418772183e-13
| Variables   typ   min   max
[GND Clamp Reference]   0   0   0
[POWER Clamp Reference]   3.3   3   3.6
[Pulldown Reference]   0   0   0
[Pullup Reference]   3.3   3   3.6
[Temperature Range]   25   125   -40
[Voltage Range]   3.3   3   3.6
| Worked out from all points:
|   slope of the pulldown table from 0 to 0.495 V, typ, clamps not added: 18.4 ohm
|   slope of the pullup table from 0 to 0.495 V, typ, clamps not added: 15.1 ohm
|   falling waveform, R_fixture 50, V_fixture 0: 20-80 % time 42.8ps typ, 58.4ps min, 34.3ps max; typ from 2.54 V to 0 V
|   falling waveform, R_fixture 50, V_fixture 3.3: 20-80 % time 121ps typ, 260ps min, 70ps max; typ from 3.3 V to 0.91 V
|   rising waveform, R_fixture 50, V_fixture 0: 20-80 % time 103ps typ, 184ps min, 66.6ps max; typ from 0 V to 2.54 V
|   rising waveform, R_fixture 50, V_fixture 3.3: 20-80 % time 45.5ps typ, 61ps min, 34.2ps max; typ from 0.91 V to 3.3 V
[GND Clamp]
| Voltage   I(typ)   I(min)   I(max)
-3.3V     -7.887A    -7.417A    -8.531A
-1.309V   -700.1mA   -755mA     -1.16A
-981.8mV  -175.2mA   -233.5mA   -172.1mA
-654.5mV  -6.799mA   -5.773mA   -9.66mA
-327.3mV  -189uA     -156uA     -585.6uA
0V        -136.9nA   -148nA     -612.9nA
6.6V      0A         0A         0A
[POWER Clamp]
| Voltage   I(typ)   I(min)   I(max)
-3.3V     7.896A     7.466A     8.506A
-1.309V   700.9mA    749.4mA    1.174A
-981.8mV  175.4mA    232.7mA    224.9mA
-654.5mV  5.603mA    19.51mA    9.05mA
-327.3mV  73.82uA    354.9uA    410.8uA
-300mV    34.66uA    61.21uA    374.3uA
6.6V      0A         0A         0A
[Pulldown]
| Voltage   I(typ)   I(min)   I(max)
-3.3V     -4.452mA   -3.445mA   -4.828mA
-2.291V   -3.051mA   -2.175mA   -4.573mA
-1.636V   -8.495mA   -3.516mA   -29.55mA
-981.8mV  -36.88mA   -22.15mA   -42.81mA
-327.3mV  -18.17mA   -15.04mA   -20.77mA
876.6mV   46.23mA    36.06mA    55.68mA
1.598V    68.07mA    45.61mA    92.58mA
3.627V    72.36mA    43.62mA    105.3mA
4.282V    53.99mA    8.457mA    96.33mA
4.936V    8.721mA    2.722mA    57.21mA
5.591V    3.15mA     2.391mA    15.77mA
6.6V      4.713mA    628.3uA    4.419mA
[Pullup]
| Voltage   I(typ)   I(min)   I(max)
-3.3V     7.002mA    4.581mA    7.781mA
-1.964V   9.469mA    4.269mA    34.93mA
-1.309V   40.68mA    17.26mA    53.45mA
-654.5mV  38.61mA    32.14mA    40.44mA
2.166V    -141.2mA   -105mA     -172.8mA
3.042V    -174.1mA   -119.5mA   -228.9mA
3.955V    -175.9mA   -100.4mA   -245.5mA
4.282V    -164.7mA   -67.49mA   -238.2mA
4.936V    -96.48mA   -12.49mA   -203.9mA
5.591V    -16.92mA   -7.208mA   -123.1mA
6.245V    -9.532mA   -11.14mA   -21.48mA
6.6V      -12.7mA    -1.66mA    -12.42mA
[Ramp]
dV/dt_r   1.52205/0.103279n  1.3187/0.184096n  1.70609/66.6017p
dV/dt_f   1.43393/0.121019n  1.19351/0.259932n  1.643/70.0007p
R_load = 50
[Falling Waveform]
R_fixture = 50
V_fixture = 0
V_fixture_min = 0
V_fixture_max = 0
| Time   V(typ)   V(min)   V(max)
0s        2.537V     2.2V       2.843V
806.1ps   2.537V     2.199V     2.799V
845.2ps   2.535V     2.199V     2.296V
896.5ps   2.521V     2.199V     92.67mV
973.5ps   2.187V     2.198V     2.008mV
1.033ns   259.8mV    2.184V     1.25mV
1.146ns   1.784mV    1.921V     655.2uV
1.243ns   1.046mV    76.47mV    412.9uV
1.392ns   553.5uV    1.474mV    187.5uV
333.3ns   966.1nV    1.518uV    3.107uV
[Falling Waveform]
R_fixture = 50
V_fixture = 3.3
V_fixture_min = 3
V_fixture_max = 3.6
| Time   V(typ)   V(min)   V(max)
0s        3.3V       3V         3.6V
825.2ps   3.301V     3V         3.568V
864.4ps   3.303V     3V         3.254V
923.8ps   3.306V     3V         1.756V
960.1ps   3.282V     3.001V     1.205V
1.007ns   3.071V     3.002V     976.7mV
1.191ns   1.15V      2.899V     881mV
1.419ns   944.3mV    1.669V     866.6mV
1.649ns   921.5mV    1.165V     863.2mV
333.3ns   910.1mV    1.011V     861.6mV
[Rising Waveform]
R_fixture = 50
V_fixture = 0
V_fixture_min = 0
V_fixture_max = 0
| Time   V(typ)   V(min)   V(max)
0s        952.4nV    1.498uV    3.094uV
797.8ps   -481.6uV   9.658uV    21.86mV
824.7ps   -1.513mV   9.933uV    273.1mV
900.4ps   -7.317mV   10.71uV    2.18V
929.8ps   7.536mV    -532.8uV   2.569V
1.081ns   1.937V     -7.092mV   2.79V
1.137ns   2.281V     117.4mV    2.805V
1.376ns   2.483V     1.777V     2.832V
1.748ns   2.522V     2.123V     2.84V
333.3ns   2.537V     2.198V     2.843V
[Rising Waveform]
R_fixture = 50
V_fixture = 3.3
V_fixture_min = 3
V_fixture_max = 3.6
| Time   V(typ)   V(min)   V(max)
0s        910.1mV    1.011V     861.6mV
766.2ps   910mV      1.011V     908.6mV
798ps     909.7mV    1.011V     1.308V
853.2ps   926.9mV    1.011V     3.506V
906.4ps   1.165V     1.01V      3.596V
970.6ps   2.976V     1.021V     3.598V
1.016ns   3.288V     1.076V     3.598V
1.152ns   3.298V     2.902V     3.599V
1.393ns   3.299V     2.998V     3.599V
333.3ns   3.3V       3V         3.6V
[Add Submodel]
| Submodel Name Mode
M20_PBIDIR_E33_DR_3P30V_T All
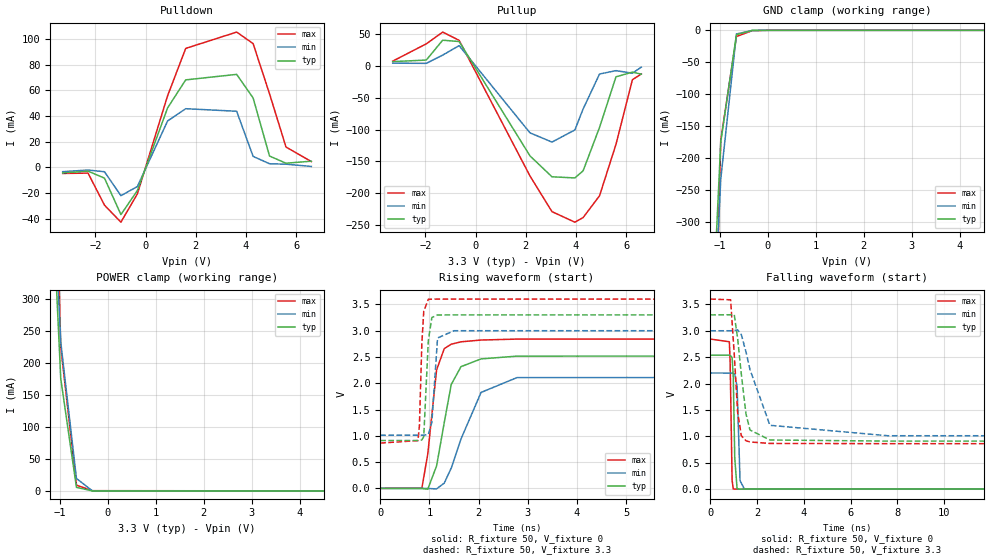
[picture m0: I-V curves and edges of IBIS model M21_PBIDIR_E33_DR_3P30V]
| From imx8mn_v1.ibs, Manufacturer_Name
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[Model] M21_PBIDIR_E33_DR_3P30V
Model_type I/O
Vinl  =  0.54
Vinh  =  1.26
Vmeas =  0.9
| Capacitance   typ   min   max
C_comp   7.43257478797e-13   6.80162949915e-13   7.72418772183e-13
| Variables   typ   min   max
[GND Clamp Reference]   0   0   0
[POWER Clamp Reference]   3.3   3   3.6
[Pulldown Reference]   0   0   0
[Pullup Reference]   3.3   3   3.6
[Temperature Range]   25   125   -40
[Voltage Range]   3.3   3   3.6
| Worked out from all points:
|   slope of the pulldown table from 0 to 0.495 V, typ, clamps not added: 18.4 ohm
|   slope of the pullup table from 0 to 0.495 V, typ, clamps not added: 15.1 ohm
|   falling waveform, R_fixture 50, V_fixture 0: 20-80 % time 63.6ps typ, 75.7ps min, 53.7ps max; typ from 2.54 V to 0 V
|   falling waveform, R_fixture 50, V_fixture 3.3: 20-80 % time 362ps typ, 741ps min, 219ps max; typ from 3.3 V to 0.91 V
|   rising waveform, R_fixture 50, V_fixture 0: 20-80 % time 299ps typ, 525ps min, 194ps max; typ from 0 V to 2.54 V
|   rising waveform, R_fixture 50, V_fixture 3.3: 20-80 % time 58.9ps typ, 67.4ps min, 55.2ps max; typ from 0.91 V to 3.3 V
[GND Clamp]
| Voltage   I(typ)   I(min)   I(max)
-3.3V     -7.887A    -7.417A    -8.531A
-1.309V   -700.1mA   -755mA     -1.16A
-981.8mV  -175.2mA   -233.5mA   -172.1mA
-654.5mV  -6.799mA   -5.773mA   -9.66mA
-327.3mV  -189uA     -156uA     -585.6uA
0V        -136.9nA   -148nA     -612.9nA
6.6V      0A         0A         0A
[POWER Clamp]
| Voltage   I(typ)   I(min)   I(max)
-3.3V     7.896A     7.466A     8.506A
-1.309V   700.9mA    749.4mA    1.174A
-981.8mV  175.4mA    232.7mA    224.9mA
-654.5mV  5.603mA    19.51mA    9.05mA
-327.3mV  73.82uA    354.9uA    410.8uA
-300mV    34.66uA    61.21uA    374.3uA
6.6V      0A         0A         0A
[Pulldown]
| Voltage   I(typ)   I(min)   I(max)
-3.3V     -4.452mA   -3.445mA   -4.828mA
-2.291V   -3.051mA   -2.175mA   -4.573mA
-1.636V   -8.495mA   -3.516mA   -29.55mA
-981.8mV  -36.88mA   -22.15mA   -42.81mA
-327.3mV  -18.17mA   -15.04mA   -20.77mA
876.6mV   46.23mA    36.06mA    55.68mA
1.598V    68.07mA    45.61mA    92.58mA
3.627V    72.36mA    43.62mA    105.3mA
4.282V    53.99mA    8.457mA    96.33mA
4.936V    8.721mA    2.722mA    57.21mA
5.591V    3.15mA     2.391mA    15.77mA
6.6V      4.713mA    628.3uA    4.419mA
[Pullup]
| Voltage   I(typ)   I(min)   I(max)
-3.3V     7.002mA    4.581mA    7.781mA
-1.964V   9.469mA    4.269mA    34.93mA
-1.309V   40.68mA    17.26mA    53.45mA
-654.5mV  38.61mA    32.14mA    40.44mA
2.166V    -141.2mA   -105mA     -172.8mA
3.042V    -174.1mA   -119.5mA   -228.9mA
3.955V    -175.9mA   -100.4mA   -245.5mA
4.282V    -164.7mA   -67.49mA   -238.2mA
4.936V    -96.48mA   -12.49mA   -203.9mA
5.591V    -16.92mA   -7.208mA   -123.1mA
6.245V    -9.532mA   -11.14mA   -21.48mA
6.6V      -12.7mA    -1.66mA    -12.42mA
[Ramp]
dV/dt_r   1.52205/0.299014n  1.3187/0.525139n  1.70609/0.194401n
dV/dt_f   1.43393/0.362213n  1.19351/0.741307n  1.643/0.218817n
R_load = 50
[Falling Waveform]
R_fixture = 50
V_fixture = 0
V_fixture_min = 0
V_fixture_max = 0
| Time   V(typ)   V(min)   V(max)
0s        2.537V     2.2V       2.843V
815.1ps   2.537V     2.199V     2.791V
848.7ps   2.535V     2.199V     2.415V
933.3ps   2.493V     2.2V       166.2mV
982.8ps   2.131V     2.197V     4.255mV
1.046ns   593.1mV    2.179V     1.574mV
1.146ns   5.51mV     1.941V     1.047mV
1.273ns   1.282mV    160mV      758uV
1.461ns   767.7uV    1.584mV    481.2uV
333.3ns   960.6nV    1.504uV    3.097uV
[Falling Waveform]
R_fixture = 50
V_fixture = 3.3
V_fixture_min = 3
V_fixture_max = 3.6
| Time   V(typ)   V(min)   V(max)
0s        3.3V       3V         3.6V
868.6ps   3.303V     3V         3.586V
1.025ns   3.306V     3.003V     2.549V
1.17ns    2.851V     3.016V     1.456V
1.327ns   2.177V     2.927V     1.012V
1.524ns   1.431V     2.603V     918mV
1.696ns   1.12V      2.266V     893.6mV
2.55ns    931.3mV    1.209V     866mV
7.585ns   910.1mV    1.012V     861.6mV
333.3ns   910.1mV    1.011V     861.6mV
[Rising Waveform]
R_fixture = 50
V_fixture = 0
V_fixture_min = 0
V_fixture_max = 0
| Time   V(typ)   V(min)   V(max)
0s        952.4nV    1.498uV    3.094uV
846.3ps   -2.814mV   42.44uV    7.261mV
965.8ps   -14.65mV   -1.621mV   652.9mV
1.145ns   426.1mV    -9.656mV   2.252V
1.301ns   1.251V     100.8mV    2.657V
1.443ns   1.975V     385.7mV    2.742V
1.642ns   2.315V     940.5mV    2.787V
2.05ns    2.462V     1.825V     2.821V
2.781ns   2.515V     2.107V     2.839V
333.3ns   2.537V     2.198V     2.843V
[Rising Waveform]
R_fixture = 50
V_fixture = 3.3
V_fixture_min = 3
V_fixture_max = 3.6
| Time   V(typ)   V(min)   V(max)
0s        910.1mV    1.011V     861.6mV
766.2ps   910mV      1.011V     908.9mV
795.8ps   909.5mV    1.011V     1.187V
845.3ps   921.3mV    1.011V     2.751V
884.1ps   983.1mV    1.011V     3.367V
977.1ps   2.811V     1.024V     3.596V
1.049ns   3.249V     1.257V     3.598V
1.165ns   3.297V     2.86V      3.599V
1.499ns   3.299V     2.998V     3.599V
333.3ns   3.3V       3V         3.6V
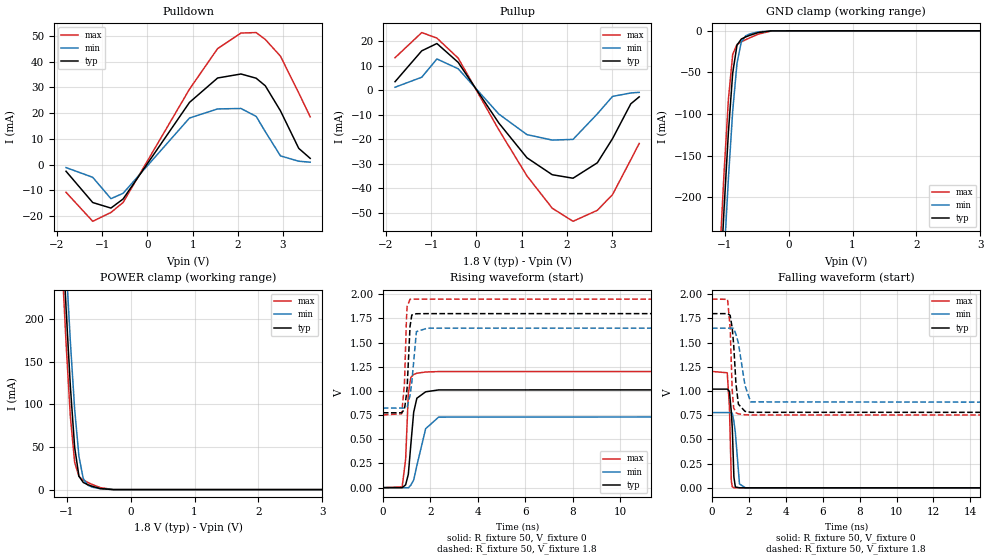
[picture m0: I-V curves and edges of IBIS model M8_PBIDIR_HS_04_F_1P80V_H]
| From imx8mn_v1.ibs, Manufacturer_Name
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[Model] M8_PBIDIR_HS_04_F_1P80V_H
Model_type I/O
Vinl  =  0.54
Vinh  =  1.26
Vmeas =  0.9
| Capacitance   typ   min   max
C_comp   1.4062710684e-12   1.31845087786e-12   1.45127599534e-12
| Variables   typ   min   max
[GND Clamp Reference]   0   0   0
[POWER Clamp Reference]   1.8   1.65   1.95
[Pulldown Reference]   0   0   0
[Pullup Reference]   1.8   1.65   1.95
[Temperature Range]   25   125   -40
[Voltage Range]   1.8   1.65   1.95
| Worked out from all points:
|   slope of the pulldown table from 0 to 0.27 V, typ, clamps not added: 36.4 ohm
|   slope of the pullup table from 0 to 0.27 V, typ, clamps not added: 36.3 ohm
|   GND clamp passes 1 mA (typ) near -0.41 V on its own axis
|   POWER clamp passes 1 mA (typ) near -0.45 V on its own axis
|   falling waveform, R_fixture 50, V_fixture 0: 20-80 % time 133ps typ, 199ps min, 104ps max; typ from 1.02 V to 0 V
|   falling waveform, R_fixture 50, V_fixture 1.8: 20-80 % time 210ps typ, 429ps min, 135ps max; typ from 1.8 V to 0.775 V
|   rising waveform, R_fixture 50, V_fixture 0: 20-80 % time 207ps typ, 444ps min, 128ps max; typ from 0 V to 1.02 V
|   rising waveform, R_fixture 50, V_fixture 1.8: 20-80 % time 127ps typ, 175ps min, 103ps max; typ from 0.775 V to 1.8 V
[GND Clamp]
| Voltage   I(typ)   I(min)   I(max)
-1.8V     -1.55A     -1.599A    -1.507A
-1.076V   -314.9mA   -373.7mA   -269.5mA
-1.009V   -213.2mA   -272mA     -169.8mA
-941.4mV  -121.7mA   -177.5mA   -82.37mA
-874.1mV  -50.6mA    -96.19mA   -28.29mA
-806.9mV  -17.14mA   -38.88mA   -16.37mA
-739.7mV  -9.899mA   -13.25mA   -13.3mA
-672.4mV  -7.363mA   -6.1mA     -10.74mA
-605.2mV  -5.351mA   -3.675mA   -8.301mA
-470.7mV  -2.028mA   -1.167mA   -3.928mA
-269mV    -32.97uA   -24.73uA   -158.8uA
3.6V      0A         0A         0A
[POWER Clamp]
| Voltage   I(typ)   I(min)   I(max)
-1.8V     1.551A     1.591A     1.512A
-1.076V   314.9mA    367.7mA    272mA
-1.009V   213mA      266.5mA    172.2mA
-941.4mV  120.9mA    173.2mA    85.48mA
-874.1mV  49.37mA    93.93mA    31.94mA
-806.9mV  15.67mA    38.77mA    15.36mA
-739.7mV  8.383mA    12.98mA    11.23mA
-672.4mV  5.889mA    5.395mA    8.598mA
-605.2mV  4.004mA    3.004mA    6.202mA
-470.7mV  1.209mA    899.6uA    2.273mA
-269mV    8.867uA    21.52uA    34.39uA
3.6V      0A         0A         0A
[Pulldown]
| Voltage   I(typ)   I(min)   I(max)
-1.8V     -2.576mA   -1.141mA   -10.75mA
-1.21V    -14.71mA   -4.919mA   -22mA
-806.9mV  -16.87mA   -13.22mA   -18.57mA
-537.9mV  -13.34mA   -11.13mA   -14.69mA
931mV     24.17mA    18.1mA     29.31mA
1.552V    33.63mA    21.62mA    45.03mA
2.069V    35.19mA    21.8mA     51.08mA
2.405V    33.55mA    18.73mA    51.27mA
2.607V    30.61mA    12.8mA     48.59mA
2.943V    20.87mA    3.393mA    42.1mA
3.347V    6.308mA    1.325mA    27.82mA
3.6V      2.439mA    944.2uA    18.58mA
[Pullup]
| Voltage   I(typ)   I(min)   I(max)
-1.8V     3.474mA    1.216mA    13.25mA
-1.21V    16.05mA    5.294mA    23.5mA
-874.1mV  19.04mA    12.74mA    21.24mA
-403.4mV  11.34mA    8.744mA    13.07mA
496.6mV   -13.41mA   -9.745mA   -16.2mA
1.117V    -27.54mA   -18.1mA    -34.92mA
1.676V    -34.45mA   -20.33mA   -48.1mA
2.136V    -35.88mA   -20.06mA   -53.44mA
2.674V    -29.59mA   -9.639mA   -48.96mA
3.01V     -19.74mA   -2.532mA   -42.55mA
3.414V    -5.551mA   -1.114mA   -28.33mA
3.6V      -2.708mA   -877.7uA   -21.71mA
[Ramp]
dV/dt_r   0.611763/0.206834n  0.46648/0.443666n  0.721577/0.127803n
dV/dt_f   0.615244/0.209661n  0.49599/0.429079n  0.718726/0.134916n
R_load = 50
[Falling Waveform]
R_fixture = 50
V_fixture = 0
V_fixture_min = 0
V_fixture_max = 0
| Time   V(typ)   V(min)   V(max)
0s        1.02V      777.5mV    1.203V
833.1ps   1.02V      777.5mV    1.189V
950.6ps   997.1mV    777.5mV    839.7mV
1.054ns   786.3mV    777.6mV    68.95mV
1.108ns   608.1mV    769.7mV    10.01mV
1.193ns   112.5mV    685.1mV    1.428mV
1.272ns   9.033mV    571mV      663.1uV
1.496ns   600.6uV    40.23mV    309.7uV
1.818ns   269uV      576.6uV    153.2uV
333.3ns   106.8nV    518.6nV    83.92nV
[Falling Waveform]
R_fixture = 50
V_fixture = 1.8
V_fixture_min = 1.65
V_fixture_max = 1.95
| Time   V(typ)   V(min)   V(max)
0s        1.8V       1.65V      1.95V
850ps     1.8V       1.65V      1.948V
989.6ps   1.783V     1.65V      1.658V
1.101ns   1.652V     1.651V     1.012V
1.18ns    1.483V     1.648V     825.7mV
1.305ns   1.074V     1.586V     777.1mV
1.437ns   864.3mV    1.495V     764.3mV
1.794ns   790.4mV    1.057V     754.8mV
2.101ns   780.6mV    888.3mV    752.9mV
333.3ns   774.6mV    823.3mV    752.1mV
[Rising Waveform]
R_fixture = 50
V_fixture = 0
V_fixture_min = 0
V_fixture_max = 0
| Time   V(typ)   V(min)   V(max)
0s        78.82nV    517.8nV    73.76nV
814.7ps   -180.5uV   15.3uV     8.484mV
961.4ps   29.74mV    -268.7uV   293.7mV
1.075ns   138.6mV    -1.968mV   973.5mV
1.179ns   440.7mV    25.71mV    1.139V
1.301ns   780.3mV    79.2mV     1.171V
1.435ns   925.4mV    228.6mV    1.184V
1.806ns   991.5mV    610.3mV    1.196V
2.353ns   1.011V     729.8mV    1.201V
333.3ns   1.02V      777.5mV    1.203V
[Rising Waveform]
R_fixture = 50
V_fixture = 1.8
V_fixture_min = 1.65
V_fixture_max = 1.95
| Time   V(typ)   V(min)   V(max)
0s        774.6mV    823.3mV    752.1mV
796.6ps   774.5mV    823.3mV    764.3mV
912.7ps   812.5mV    823.2mV    1.08V
991.6ps   954.8mV    825.1mV    1.715V
1.024ns   1.032V     830.2mV    1.873V
1.147ns   1.668V     955mV      1.948V
1.221ns   1.786V     1.088V     1.949V
1.416ns   1.799V     1.614V     1.95V
1.877ns   1.8V       1.65V      1.95V
333.3ns   1.8V       1.65V      1.95V
[Add Submodel]
| Submodel Name Mode
M8_PBIDIR_HS_04_F_1P80V_T_H All
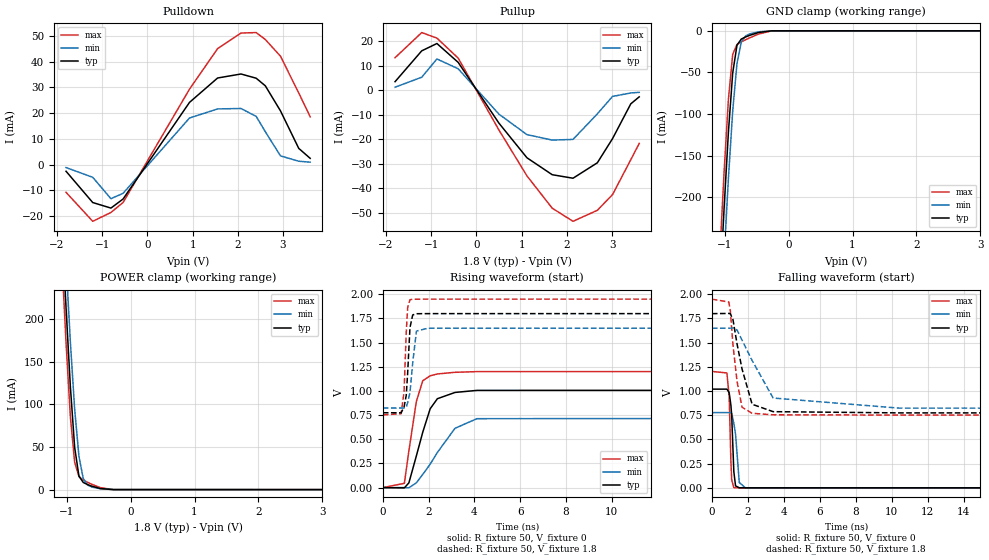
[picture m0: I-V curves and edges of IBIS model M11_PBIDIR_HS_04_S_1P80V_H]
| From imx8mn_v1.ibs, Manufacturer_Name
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[Model] M11_PBIDIR_HS_04_S_1P80V_H
Model_type I/O
Vinl  =  0.54
Vinh  =  1.26
Vmeas =  0.9
| Capacitance   typ   min   max
C_comp   1.4062710684e-12   1.31845087786e-12   1.45127599534e-12
| Variables   typ   min   max
[GND Clamp Reference]   0   0   0
[POWER Clamp Reference]   1.8   1.65   1.95
[Pulldown Reference]   0   0   0
[Pullup Reference]   1.8   1.65   1.95
[Temperature Range]   25   125   -40
[Voltage Range]   1.8   1.65   1.95
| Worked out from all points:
|   slope of the pulldown table from 0 to 0.27 V, typ, clamps not added: 36.4 ohm
|   slope of the pullup table from 0 to 0.27 V, typ, clamps not added: 36.3 ohm
|   GND clamp passes 1 mA (typ) near -0.41 V on its own axis
|   POWER clamp passes 1 mA (typ) near -0.45 V on its own axis
|   falling waveform, R_fixture 50, V_fixture 0: 20-80 % time 133ps typ, 196ps min, 105ps max; typ from 1.02 V to 0 V
|   falling waveform, R_fixture 50, V_fixture 1.8: 20-80 % time 686ps typ, 1.33ns min, 409ps max; typ from 1.8 V to 0.775 V
|   rising waveform, R_fixture 50, V_fixture 0: 20-80 % time 748ps typ, 1.39ns min, 453ps max; typ from 0 V to 1.02 V
|   rising waveform, R_fixture 50, V_fixture 1.8: 20-80 % time 134ps typ, 178ps min, 115ps max; typ from 0.775 V to 1.8 V
[GND Clamp]
| Voltage   I(typ)   I(min)   I(max)
-1.8V     -1.55A     -1.599A    -1.507A
-1.076V   -314.9mA   -373.7mA   -269.5mA
-1.009V   -213.2mA   -272mA     -169.8mA
-941.4mV  -121.7mA   -177.5mA   -82.37mA
-874.1mV  -50.6mA    -96.19mA   -28.29mA
-806.9mV  -17.14mA   -38.88mA   -16.37mA
-739.7mV  -9.899mA   -13.25mA   -13.3mA
-672.4mV  -7.363mA   -6.1mA     -10.74mA
-605.2mV  -5.351mA   -3.675mA   -8.301mA
-470.7mV  -2.028mA   -1.167mA   -3.928mA
-269mV    -32.97uA   -24.73uA   -158.8uA
3.6V      0A         0A         0A
[POWER Clamp]
| Voltage   I(typ)   I(min)   I(max)
-1.8V     1.551A     1.591A     1.512A
-1.076V   314.9mA    367.7mA    272mA
-1.009V   213mA      266.5mA    172.2mA
-941.4mV  120.9mA    173.2mA    85.48mA
-874.1mV  49.37mA    93.93mA    31.94mA
-806.9mV  15.67mA    38.77mA    15.36mA
-739.7mV  8.383mA    12.98mA    11.23mA
-672.4mV  5.889mA    5.395mA    8.598mA
-605.2mV  4.004mA    3.004mA    6.202mA
-470.7mV  1.209mA    899.6uA    2.273mA
-269mV    8.867uA    21.52uA    34.39uA
3.6V      0A         0A         0A
[Pulldown]
| Voltage   I(typ)   I(min)   I(max)
-1.8V     -2.576mA   -1.141mA   -10.75mA
-1.21V    -14.71mA   -4.919mA   -22mA
-806.9mV  -16.87mA   -13.22mA   -18.57mA
-537.9mV  -13.34mA   -11.13mA   -14.69mA
931mV     24.17mA    18.1mA     29.31mA
1.552V    33.63mA    21.62mA    45.03mA
2.069V    35.19mA    21.8mA     51.08mA
2.405V    33.55mA    18.73mA    51.27mA
2.607V    30.61mA    12.8mA     48.59mA
2.943V    20.87mA    3.393mA    42.1mA
3.347V    6.308mA    1.325mA    27.82mA
3.6V      2.439mA    944.2uA    18.58mA
[Pullup]
| Voltage   I(typ)   I(min)   I(max)
-1.8V     3.474mA    1.216mA    13.25mA
-1.21V    16.05mA    5.294mA    23.5mA
-874.1mV  19.04mA    12.74mA    21.24mA
-403.4mV  11.34mA    8.744mA    13.07mA
496.6mV   -13.41mA   -9.745mA   -16.2mA
1.117V    -27.54mA   -18.1mA    -34.92mA
1.676V    -34.45mA   -20.33mA   -48.1mA
2.136V    -35.88mA   -20.06mA   -53.44mA
2.674V    -29.59mA   -9.639mA   -48.96mA
3.01V     -19.74mA   -2.532mA   -42.55mA
3.414V    -5.551mA   -1.114mA   -28.33mA
3.6V      -2.708mA   -877.7uA   -21.71mA
[Ramp]
dV/dt_r   0.611763/0.747994n  0.46648/1.38958n  0.721577/0.452821n
dV/dt_f   0.615244/0.685601n  0.49599/1.33428n  0.718726/0.408541n
R_load = 50
[Falling Waveform]
R_fixture = 50
V_fixture = 0
V_fixture_min = 0
V_fixture_max = 0
| Time   V(typ)   V(min)   V(max)
0s        1.02V      777.5mV    1.203V
836.2ps   1.02V      777.5mV    1.187V
962.4ps   983mV      777.5mV    945.1mV
1.057ns   856.5mV    777.5mV    279.7mV
1.102ns   747.9mV    771mV      82.28mV
1.22ns    170mV      667.9mV    3.04mV
1.316ns   20.63mV    555mV      815.3uV
1.523ns   791.2uV    55.33mV    449.1uV
1.866ns   367.8uV    739.1uV    280uV
333.3ns   106.8nV    518.6nV    84.21nV
[Falling Waveform]
R_fixture = 50
V_fixture = 1.8
V_fixture_min = 1.65
V_fixture_max = 1.95
| Time   V(typ)   V(min)   V(max)
0s        1.8V       1.65V      1.95V
942.9ps   1.802V     1.65V      1.92V
1.025ns   1.8V       1.65V      1.831V
1.174ns   1.737V     1.652V     1.475V
1.401ns   1.486V     1.63V      1.099V
1.678ns   1.228V     1.526V     833.1mV
2.236ns   864mV      1.316V     770.5mV
3.405ns   787.3mV    928.1mV    754.7mV
10.42ns   774.6mV    823.8mV    752.1mV
333.3ns   774.6mV    823.4mV    752.1mV
[Rising Waveform]
R_fixture = 50
V_fixture = 0
V_fixture_min = 0
V_fixture_max = 0
| Time   V(typ)   V(min)   V(max)
0s        78.82nV    517.8nV    73.76nV
940.1ps   -2.446mV   -110.9uV   44.65mV
1.138ns   49.35mV    -1.59mV    380.1mV
1.462ns   325.8mV    49.38mV    888.6mV
1.745ns   574.3mV    136.8mV    1.106V
2.068ns   815.8mV    242.4mV    1.157V
2.383ns   919.8mV    363.9mV    1.176V
3.154ns   984.6mV    613.9mV    1.193V
4.11ns    1.006V     713.2mV    1.2V
333.3ns   1.02V      777.5mV    1.203V
[Rising Waveform]
R_fixture = 50
V_fixture = 1.8
V_fixture_min = 1.65
V_fixture_max = 1.95
| Time   V(typ)   V(min)   V(max)
0s        774.6mV    823.3mV    752.1mV
798.8ps   774.4mV    823.3mV    765.1mV
927.5ps   834.5mV    823.1mV    991.6mV
1.022ns   953.7mV    830.2mV    1.603V
1.085ns   1.189V     881.1mV    1.863V
1.185ns   1.655V     983.4mV    1.944V
1.304ns   1.786V     1.289V     1.949V
1.467ns   1.799V     1.619V     1.949V
1.971ns   1.8V       1.649V     1.95V
333.3ns   1.8V       1.65V      1.95V
[Add Submodel]
| Submodel Name Mode
M11_PBIDIR_HS_04_S_1P80V_T_H All
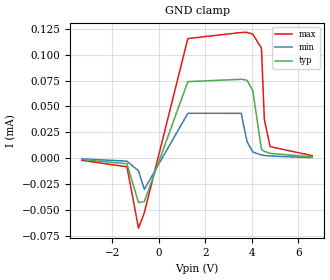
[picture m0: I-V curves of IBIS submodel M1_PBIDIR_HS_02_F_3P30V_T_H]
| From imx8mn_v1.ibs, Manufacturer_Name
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| Submodel
[Submodel]  M1_PBIDIR_HS_02_F_3P30V_T_H
Submodel_type Dynamic_clamp
[GND Clamp]
| Voltage   I(typ)   I(min)   I(max)
-3.3V     -1.152uA   -476.8nA   -1.907uA
-1.366V   -5.186uA   -2.682uA   -8.106uA
-869mV    -42.61uA   -11.97uA   -67.23uA
-620.7mV  -41.79uA   -29.91uA   -52.57uA
1.252V    73.92uA    43.44uA    115.4uA
3.548V    76.22uA    43.4uA     121.3uA
3.797V    75.29uA    16.12uA    121.4uA
4.045V    65.2uA     6.109uA    119.6uA
4.417V    8.672uA    3.219uA    106.2uA
4.541V    6.735uA    2.742uA    37.52uA
4.79V     4.768uA    2.265uA    11.27uA
6.6V      1.431uA    675.5nA    2.583uA
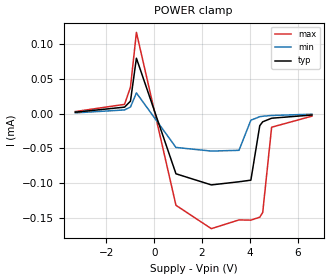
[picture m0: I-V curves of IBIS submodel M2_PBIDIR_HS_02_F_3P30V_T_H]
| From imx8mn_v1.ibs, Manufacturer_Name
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| Submodel
[Submodel]  M2_PBIDIR_HS_02_F_3P30V_T_H
Submodel_type Dynamic_clamp
[POWER Clamp]
| Voltage   I(typ)   I(min)   I(max)
-3.3V     1.907uA    953.7nA    2.861uA
-1.241V   9.179uA    5.181uA    13.12uA
-993.1mV  17.73uA    9.307uA    37.74uA
-744.8mV  79.18uA    29.5uA     116.1uA
910.3mV   -86.19uA   -48.48uA   -131.3uA
2.39V     -102.1uA   -53.71uA   -164.7uA
3.548V    -97.62uA   -52.62uA   -152.2uA
4.045V    -95.31uA   -9.526uA   -152.5uA
4.417V    -17.37uA   -4.47uA    -148.3uA
4.541V    -11.8uA    -3.854uA   -141.5uA
4.914V    -6.676uA   -2.762uA   -19.55uA
6.6V      -2.106uA   -953.7nA   -3.735uA
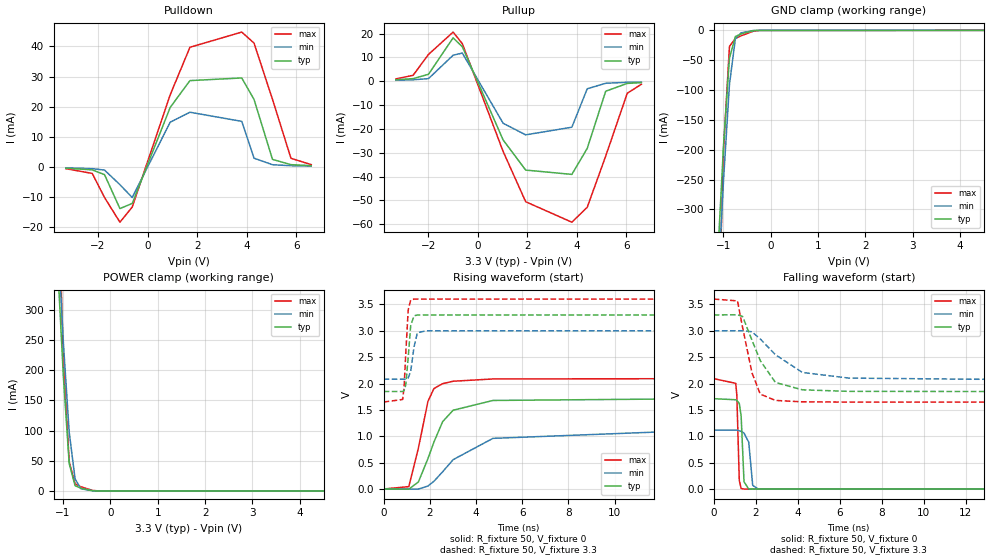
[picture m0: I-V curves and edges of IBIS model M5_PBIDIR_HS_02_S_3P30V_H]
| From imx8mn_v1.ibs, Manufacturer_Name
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[Model] M5_PBIDIR_HS_02_S_3P30V_H
Model_type I/O
Vinl  =  0.99
Vinh  =  2.31
Vmeas =  1.65
| Capacitance   typ   min   max
C_comp   1.08818991111e-12   1.03117834871e-12   1.10439570077e-12
| Variables   typ   min   max
[GND Clamp Reference]   0   0   0
[POWER Clamp Reference]   3.3   3   3.6
[Pulldown Reference]   0   0   0
[Pullup Reference]   3.3   3   3.6
[Temperature Range]   25   125   -40
[Voltage Range]   3.3   3   3.6
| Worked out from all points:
|   slope of the pulldown table from 0 to 0.495 V, typ, clamps not added: 44.3 ohm
|   slope of the pullup table from 0 to 0.495 V, typ, clamps not added: 39.7 ohm
|   GND clamp passes 1 mA (typ) near -0.39 V on its own axis
|   POWER clamp passes 1 mA (typ) near -0.44 V on its own axis
|   falling waveform, R_fixture 50, V_fixture 0: 20-80 % time 96.9ps typ, 136ps min, 76.4ps max; typ from 1.71 V to 0.002 V
|   falling waveform, R_fixture 50, V_fixture 3.3: 20-80 % time 994ps typ, 1.58ns min, 632ps max; typ from 3.3 V to 1.85 V
|   rising waveform, R_fixture 50, V_fixture 0: 20-80 % time 990ps typ, 1.87ns min, 591ps max; typ from 0.002 V to 1.71 V
|   rising waveform, R_fixture 50, V_fixture 3.3: 20-80 % time 147ps typ, 172ps min, 127ps max; typ from 1.85 V to 3.3 V
[GND Clamp]
| Voltage   I(typ)   I(min)   I(max)
-3.3V     -7.236A    -6.565A    -8.004A
-1.117V   -380.4mA   -438.7mA   -546.7mA
-993.1mV  -191mA     -249.4mA   -198.9mA
-869mV    -46.61mA   -90.79mA   -26.93mA
-744.8mV  -10.31mA   -14.37mA   -13.71mA
-620.7mV  -5.945mA   -4.193mA   -9.059mA
-372.4mV  -659.7uA   -360.2uA   -1.673mA
-248.3mV  -143.8uA   -94.2uA    -265.5uA
6.6V      0A         0A         0A
[POWER Clamp]
| Voltage   I(typ)   I(min)   I(max)
-3.3V     7.237A     6.564A     8.009A
-1.117V   380.7mA    433.6mA    553.5mA
-993.1mV  190.7mA    247mA      219.9mA
-869mV    45.33mA    97.36mA    48.38mA
-744.8mV  8.677mA    19.82mA    11.82mA
-620.7mV  4.425mA    3.499mA    6.828mA
-372.4mV  215.5uA    293.3uA    764.6uA
-248.3mV  4.273uA    22.4uA     51.08uA
6.6V      0A         0A         0A
[Pulldown]
| Voltage   I(typ)   I(min)   I(max)
-3.3V     -420.3uA   -290.8uA   -582.9uA
-2.234V   -980.9uA   -580.5uA   -2.153mA
-1.738V   -2.557mA   -1.042mA   -10.15mA
-1.117V   -13.82mA   -5.885mA   -18.35mA
-620.7mV  -12.13mA   -10.16mA   -13.33mA
910.3mV   19.75mA    14.85mA    23.92mA
1.707V    28.66mA    18.16mA    39.73mA
3.797V    29.54mA    15.13mA    44.77mA
4.293V    22.41mA    2.904mA    41.11mA
5.038V    2.501mA    726.2uA    22.43mA
5.783V    752.4uA    404.4uA    2.861mA
6.6V      427uA      270.6uA    764uA
[Pullup]
| Voltage   I(typ)   I(min)   I(max)
-3.3V     645.5uA    406.2uA    979.4uA
-2.607V   1.09mA     612.5uA    2.488mA
-1.986V   2.917mA    1.098mA    11.25mA
-993.1mV  18.2mA     10.91mA    20.62mA
-620.7mV  14.46mA    11.81mA    15.74mA
1.024V    -24.64mA   -17.64mA   -29.45mA
1.934V    -37.27mA   -22.49mA   -50.56mA
3.797V    -39.09mA   -19.29mA   -59.14mA
4.417V    -28.17mA   -3.165mA   -52.88mA
5.162V    -4.194mA   -851.2uA   -31.41mA
6.031V    -907.4uA   -453.2uA   -5.045mA
6.6V      -609.8uA   -346.2uA   -1.277mA
[Ramp]
dV/dt_r   1.02723/0.989649n  0.671424/1.8745n  1.25375/0.591423n
dV/dt_f   0.870139/0.993668n  0.55069/1.58447n  1.16985/0.632394n
R_load = 50
[Falling Waveform]
R_fixture = 50
V_fixture = 0
V_fixture_min = 0
V_fixture_max = 0
| Time   V(typ)   V(min)   V(max)
0s        1.714V     1.121V     2.093V
1.045ns   1.694V     1.121V     2.005V
1.097ns   1.681V     1.119V     1.782V
1.214ns   1.624V     1.107V     165.7mV
1.302ns   1.388V     1.094V     14.34mV
1.439ns   142.1mV    1.064V     4.361mV
1.663ns   3.706mV    891.1mV    3.933mV
1.853ns   3.207mV    73.32mV    3.735mV
2.127ns   2.833mV    2.558mV    3.63mV
333.3ns   2.315mV    1.543mV    3.247mV
[Falling Waveform]
R_fixture = 50
V_fixture = 3.3
V_fixture_min = 3
V_fixture_max = 3.6
| Time   V(typ)   V(min)   V(max)
0s        3.3V       3V         3.6V
1.129ns   3.301V     3V         3.565V
1.37ns    3.272V     3.001V     3.066V
1.816ns   2.824V     2.981V     2.207V
2.214ns   2.434V     2.844V     1.8V
2.935ns   2.021V     2.546V     1.681V
4.216ns   1.882V     2.211V     1.655V
6.424ns   1.853V     2.104V     1.65V
12.46ns   1.85V      2.082V     1.65V
333.3ns   1.85V      2.082V     1.65V
[Rising Waveform]
R_fixture = 50
V_fixture = 0
V_fixture_min = 0
V_fixture_max = 0
| Time   V(typ)   V(min)   V(max)
0s        2.315mV    1.543mV    3.247mV
1.089ns   116.7uV    581.1uV    48.34mV
1.503ns   135.4mV    1.865mV    775.9mV
1.918ns   578.6mV    59.68mV    1.663V
2.177ns   892.4mV    149.8mV    1.906V
2.555ns   1.279V     329.9mV    1.998V
3.007ns   1.495V     558.7mV    2.044V
4.73ns    1.68V      962.1mV    2.087V
14.07ns   1.714V     1.12V      2.093V
333.3ns   1.714V     1.121V     2.093V
[Rising Waveform]
R_fixture = 50
V_fixture = 3.3
V_fixture_min = 3
V_fixture_max = 3.6
| Time   V(typ)   V(min)   V(max)
0s        1.85V      2.082V     1.65V
824.1ps   1.85V      2.082V     1.699V
883.6ps   1.867V     2.082V     1.921V
956.6ps   1.971V     2.082V     2.567V
1.063ns   2.496V     2.105V     3.394V
1.172ns   3.105V     2.237V     3.583V
1.318ns   3.283V     2.702V     3.599V
1.461ns   3.298V     2.964V     3.599V
1.847ns   3.299V     2.999V     3.6V
333.3ns   3.3V       3V         3.6V
[Add Submodel]
| Submodel Name Mode
M5_PBIDIR_HS_02_S_3P30V_T_H All
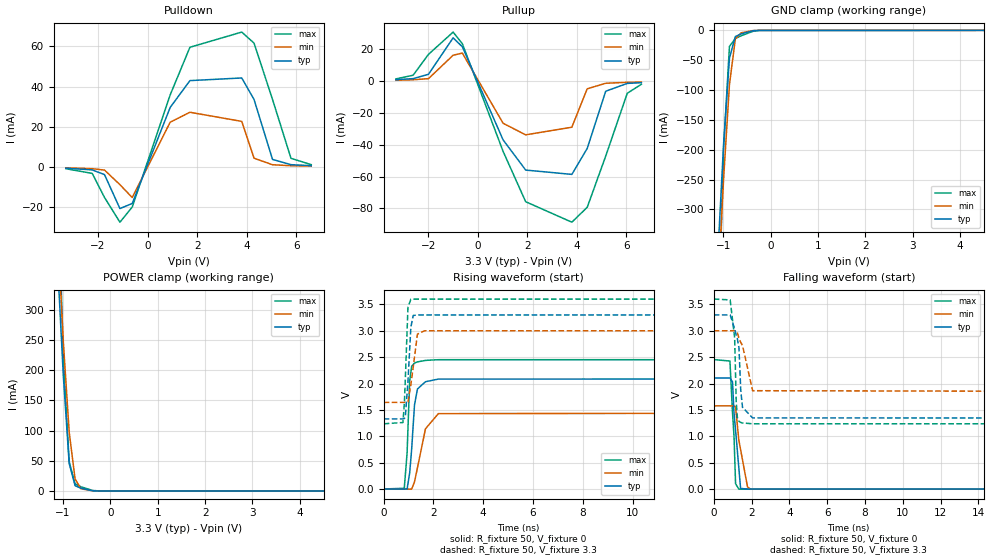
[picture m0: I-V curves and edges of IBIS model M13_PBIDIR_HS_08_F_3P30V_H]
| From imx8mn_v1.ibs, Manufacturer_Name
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[Model] M13_PBIDIR_HS_08_F_3P30V_H
Model_type I/O
Vinl  =  0.99
Vinh  =  2.31
Vmeas =  1.65
| Capacitance   typ   min   max
C_comp   1.08818991111e-12   1.03117834871e-12   1.10439570077e-12
| Variables   typ   min   max
[GND Clamp Reference]   0   0   0
[POWER Clamp Reference]   3.3   3   3.6
[Pulldown Reference]   0   0   0
[Pullup Reference]   3.3   3   3.6
[Temperature Range]   25   125   -40
[Voltage Range]   3.3   3   3.6
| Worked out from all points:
|   slope of the pulldown table from 0 to 0.495 V, typ, clamps not added: 29.5 ohm
|   slope of the pullup table from 0 to 0.495 V, typ, clamps not added: 26.5 ohm
|   GND clamp passes 1 mA (typ) near -0.39 V on its own axis
|   POWER clamp passes 1 mA (typ) near -0.44 V on its own axis
|   falling waveform, R_fixture 50, V_fixture 0: 20-80 % time 289ps typ, 442ps min, 208ps max; typ from 2.11 V to 0.002 V
|   falling waveform, R_fixture 50, V_fixture 3.3: 20-80 % time 260ps typ, 485ps min, 185ps max; typ from 3.3 V to 1.33 V
|   rising waveform, R_fixture 50, V_fixture 0: 20-80 % time 185ps typ, 477ps min, 119ps max; typ from 0.002 V to 2.11 V
|   rising waveform, R_fixture 50, V_fixture 3.3: 20-80 % time 143ps typ, 206ps min, 99.3ps max; typ from 1.33 V to 3.3 V
[GND Clamp]
| Voltage   I(typ)   I(min)   I(max)
-3.3V     -7.236A    -6.565A    -8.004A
-1.117V   -380.4mA   -438.7mA   -546.7mA
-993.1mV  -191mA     -249.4mA   -198.9mA
-869mV    -46.61mA   -90.79mA   -26.93mA
-744.8mV  -10.31mA   -14.37mA   -13.71mA
-620.7mV  -5.945mA   -4.193mA   -9.059mA
-372.4mV  -659.7uA   -360.2uA   -1.673mA
-248.3mV  -143.8uA   -94.2uA    -265.5uA
6.6V      0A         0A         0A
[POWER Clamp]
| Voltage   I(typ)   I(min)   I(max)
-3.3V     7.237A     6.564A     8.009A
-1.117V   380.7mA    433.6mA    553.5mA
-993.1mV  190.7mA    247mA      219.9mA
-869mV    45.33mA    97.36mA    48.38mA
-744.8mV  8.677mA    19.82mA    11.82mA
-620.7mV  4.425mA    3.499mA    6.828mA
-372.4mV  215.5uA    293.3uA    764.6uA
-248.3mV  4.273uA    22.4uA     51.08uA
6.6V      0A         0A         0A
[Pulldown]
| Voltage   I(typ)   I(min)   I(max)
-3.3V     -630.6uA   -436.3uA   -874.4uA
-2.234V   -1.472mA   -870.7uA   -3.23mA
-1.738V   -3.836mA   -1.563mA   -15.22mA
-1.117V   -20.73mA   -8.828mA   -27.52mA
-620.7mV  -18.2mA    -15.24mA   -19.99mA
910.3mV   29.63mA    22.28mA    35.87mA
1.707V    42.99mA    27.23mA    59.6mA
3.797V    44.31mA    22.69mA    67.16mA
4.293V    33.61mA    4.356mA    61.66mA
5.038V    3.752mA    1.089mA    33.65mA
5.783V    1.129mA    606.5uA    4.292mA
6.6V      640.6uA    405.9uA    1.146mA
[Pullup]
| Voltage   I(typ)   I(min)   I(max)
-3.3V     969.2uA    609.2uA    1.477mA
-2.607V   1.637mA    918.8uA    3.769mA
-1.986V   4.383mA    1.648mA    16.93mA
-993.1mV  27.31mA    16.37mA    30.94mA
-620.7mV  21.69mA    17.71mA    23.62mA
1.024V    -36.96mA   -26.46mA   -44.17mA
1.934V    -55.91mA   -33.74mA   -75.84mA
3.797V    -58.63mA   -28.93mA   -88.72mA
4.417V    -42.26mA   -4.748mA   -79.33mA
5.162V    -6.292mA   -1.277mA   -47.13mA
6.031V    -1.361mA   -679.7uA   -7.57mA
6.6V      -914.7uA   -518.8uA   -1.915mA
[Ramp]
dV/dt_r   1.26224/0.18512n  0.945764/0.477164n  1.4711/0.119076n
dV/dt_f   1.18172/0.259609n  0.814588/0.485068n  1.41756/0.18475n
R_load = 50
[Falling Waveform]
R_fixture = 50
V_fixture = 0
V_fixture_min = 0
V_fixture_max = 0
| Time   V(typ)   V(min)   V(max)
0s        2.106V     1.578V     2.454V
853.6ps   2.106V     1.578V     2.427V
990.6ps   2.031V     1.577V     1.451V
1.07ns    1.442V     1.577V     1.008V
1.153ns   1.116V     1.557V     104.5mV
1.324ns   410.1mV    931.6mV    3.107mV
1.417ns   15.79mV    753.3mV    2.968mV
1.785ns   2.197mV    43.63mV    2.702mV
1.942ns   2.13mV     1.975mV    2.702mV
333.3ns   1.826mV    1.245mV    2.522mV
[Falling Waveform]
R_fixture = 50
V_fixture = 3.3
V_fixture_min = 3
V_fixture_max = 3.6
| Time   V(typ)   V(min)   V(max)
0s        3.3V       3V         3.6V
866.9ps   3.3V       3V         3.584V
1.103ns   3.037V     3.001V     2.87V
1.186ns   2.92V      2.995V     1.665V
1.247ns   2.852V     2.963V     1.358V
1.332ns   2.676V     2.859V     1.286V
1.428ns   1.868V     2.778V     1.264V
1.52ns    1.551V     2.721V     1.254V
2.055ns   1.35V      1.865V     1.239V
333.3ns   1.33V      1.642V     1.237V
[Rising Waveform]
R_fixture = 50
V_fixture = 0
V_fixture_min = 0
V_fixture_max = 0
| Time   V(typ)   V(min)   V(max)
0s        1.826mV    1.245mV    2.522mV
829ps     963uV      1.24mV     14.58mV
942.2ps   2.318mV    949.4uV    688.4mV
1.045ns   302.2mV    -1.641mV   2.044V
1.125ns   753.3mV    227.7uV    2.327V
1.239ns   1.593V     136mV      2.388V
1.358ns   1.896V     402.4mV    2.41V
1.68ns    2.034V     1.142V     2.438V
2.199ns   2.084V     1.43V      2.451V
333.3ns   2.106V     1.578V     2.454V
[Rising Waveform]
R_fixture = 50
V_fixture = 3.3
V_fixture_min = 3
V_fixture_max = 3.6
| Time   V(typ)   V(min)   V(max)
0s        1.33V      1.642V     1.237V
774.9ps   1.33V      1.642V     1.261V
834.7ps   1.335V     1.642V     1.643V
874.1ps   1.385V     1.642V     2.129V
976.7ps   2.038V     1.648V     3.444V
1.093ns   3.067V     1.982V     3.597V
1.188ns   3.289V     2.309V     3.599V
1.356ns   3.299V     2.936V     3.599V
1.641ns   3.299V     2.999V     3.599V
333.3ns   3.3V       3V         3.6V
[Add Submodel]
| Submodel Name Mode
M13_PBIDIR_HS_08_F_3P30V_T_H All
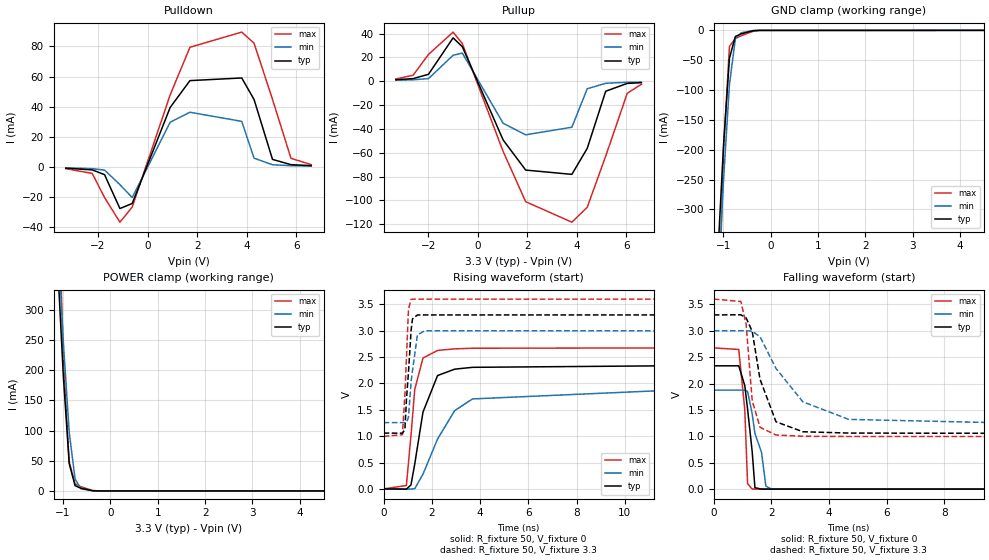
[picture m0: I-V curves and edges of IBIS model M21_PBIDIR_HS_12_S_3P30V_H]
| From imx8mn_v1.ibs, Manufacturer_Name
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[Model] M21_PBIDIR_HS_12_S_3P30V_H
Model_type I/O
Vinl  =  0.99
Vinh  =  2.31
Vmeas =  1.65
| Capacitance   typ   min   max
C_comp   1.08818991111e-12   1.03117834871e-12   1.10439570077e-12
| Variables   typ   min   max
[GND Clamp Reference]   0   0   0
[POWER Clamp Reference]   3.3   3   3.6
[Pulldown Reference]   0   0   0
[Pullup Reference]   3.3   3   3.6
[Temperature Range]   25   125   -40
[Voltage Range]   3.3   3   3.6
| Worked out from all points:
|   slope of the pulldown table from 0 to 0.495 V, typ, clamps not added: 22.1 ohm
|   slope of the pullup table from 0 to 0.495 V, typ, clamps not added: 19.9 ohm
|   GND clamp passes 1 mA (typ) near -0.39 V on its own axis
|   POWER clamp passes 1 mA (typ) near -0.44 V on its own axis
|   falling waveform, R_fixture 50, V_fixture 0: 20-80 % time 265ps typ, 420ps min, 189ps max; typ from 2.34 V to 0.002 V
|   falling waveform, R_fixture 50, V_fixture 3.3: 20-80 % time 548ps typ, 1.38ns min, 255ps max; typ from 3.3 V to 1.06 V
|   rising waveform, R_fixture 50, V_fixture 0: 20-80 % time 570ps typ, 1.26ns min, 319ps max; typ from 0.002 V to 2.34 V
|   rising waveform, R_fixture 50, V_fixture 3.3: 20-80 % time 190ps typ, 240ps min, 155ps max; typ from 1.06 V to 3.3 V
[GND Clamp]
| Voltage   I(typ)   I(min)   I(max)
-3.3V     -7.236A    -6.565A    -8.004A
-1.117V   -380.4mA   -438.7mA   -546.7mA
-993.1mV  -191mA     -249.4mA   -198.9mA
-869mV    -46.61mA   -90.79mA   -26.93mA
-744.8mV  -10.31mA   -14.37mA   -13.71mA
-620.7mV  -5.945mA   -4.193mA   -9.059mA
-372.4mV  -659.7uA   -360.2uA   -1.673mA
-248.3mV  -143.8uA   -94.2uA    -265.5uA
6.6V      0A         0A         0A
[POWER Clamp]
| Voltage   I(typ)   I(min)   I(max)
-3.3V     7.237A     6.564A     8.009A
-1.117V   380.7mA    433.6mA    553.5mA
-993.1mV  190.7mA    247mA      219.9mA
-869mV    45.33mA    97.36mA    48.38mA
-744.8mV  8.677mA    19.82mA    11.82mA
-620.7mV  4.425mA    3.499mA    6.828mA
-372.4mV  215.5uA    293.3uA    764.6uA
-248.3mV  4.273uA    22.4uA     51.08uA
6.6V      0A         0A         0A
[Pulldown]
| Voltage   I(typ)   I(min)   I(max)
-3.3V     -840.9uA   -581.7uA   -1.166mA
-2.234V   -1.962mA   -1.161mA   -4.306mA
-1.738V   -5.114mA   -2.084mA   -20.29mA
-1.117V   -27.64mA   -11.77mA   -36.7mA
-620.7mV  -24.27mA   -20.33mA   -26.65mA
910.3mV   39.51mA    29.7mA     47.83mA
1.707V    57.32mA    36.31mA    79.47mA
3.797V    59.08mA    30.26mA    89.55mA
4.293V    44.81mA    5.808mA    82.22mA
5.038V    5.003mA    1.452mA    44.86mA
5.783V    1.505mA    808.7uA    5.722mA
6.6V      854.3uA    541.3uA    1.528mA
[Pullup]
| Voltage   I(typ)   I(min)   I(max)
-3.3V     1.291mA    812.3uA    1.964mA
-2.607V   2.181mA    1.225mA    4.997mA
-1.986V   5.838mA    2.197mA    22.53mA
-993.1mV  36.41mA    21.83mA    41.25mA
-620.7mV  28.92mA    23.62mA    31.49mA
1.024V    -49.28mA   -35.28mA   -58.89mA
1.934V    -74.55mA   -44.98mA   -101.1mA
3.797V    -78.17mA   -38.58mA   -118.3mA
4.417V    -56.34mA   -6.331mA   -105.8mA
5.162V    -8.389mA   -1.702mA   -62.83mA
6.031V    -1.815mA   -906.2uA   -10.09mA
6.6V      -1.22mA    -691.9uA   -2.553mA
[Ramp]
dV/dt_r   1.4006/0.570203n  1.1252/1.26465n  1.60346/0.318825n
dV/dt_f   1.34487/0.54835n  1.04489/1.3814n  1.56141/0.254869n
R_load = 50
[Falling Waveform]
R_fixture = 50
V_fixture = 0
V_fixture_min = 0
V_fixture_max = 0
| Time   V(typ)   V(min)   V(max)
0s        2.336V     1.876V     2.675V
866.1ps   2.336V     1.876V     2.646V
1.075ns   1.963V     1.875V     1.508V
1.172ns   1.518V     1.852V     104.8mV
1.332ns   710.5mV    1.427V     3.19mV
1.427ns   28.93mV    1.056V     3.021mV
1.655ns   2.435mV    700.3mV    2.616mV
1.805ns   2.234mV    61.65mV    2.44mV
1.993ns   2.147mV    2.23mV     2.44mV
333.3ns   1.508mV    1.043mV    2.062mV
[Falling Waveform]
R_fixture = 50
V_fixture = 3.3
V_fixture_min = 3
V_fixture_max = 3.6
| Time   V(typ)   V(min)   V(max)
0s        3.3V       3V         3.6V
938.8ps   3.302V     3V         3.554V
1.121ns   3.245V     3.002V     3.128V
1.333ns   2.988V     2.992V     1.673V
1.604ns   2.081V     2.886V     1.173V
2.158ns   1.277V     2.286V     1.026V
3.09ns    1.088V     1.654V     1.003V
4.681ns   1.063V     1.322V     998.1mV
9.786ns   1.059V     1.26V      997.7mV
333.3ns   1.059V     1.259V     997.7mV
[Rising Waveform]
R_fixture = 50
V_fixture = 0
V_fixture_min = 0
V_fixture_max = 0
| Time   V(typ)   V(min)   V(max)
0s        1.508mV    1.043mV    2.062mV
941.2ps   -3.655mV   658.9uV    65.75mV
1.132ns   76.39mV    -1.729mV   1.006V
1.289ns   472.6mV    5.469mV    1.886V
1.63ns    1.457V     280.9mV    2.482V
2.235ns   2.15V      946.8mV    2.626V
2.942ns   2.271V     1.484V     2.656V
3.681ns   2.306V     1.707V     2.668V
12.02ns   2.336V     1.875V     2.674V
333.3ns   2.336V     1.876V     2.675V
[Rising Waveform]
R_fixture = 50
V_fixture = 3.3
V_fixture_min = 3
V_fixture_max = 3.6
| Time   V(typ)   V(min)   V(max)
0s        1.059V     1.259V     997.7mV
779.4ps   1.058V     1.258V     1.029V
880.5ps   1.132V     1.258V     1.8V
948.3ps   1.714V     1.259V     2.513V
1.029ns   2.216V     1.362V     3.406V
1.139ns   3.011V     2.044V     3.595V
1.196ns   3.225V     2.241V     3.598V
1.399ns   3.298V     2.919V     3.599V
1.7ns     3.299V     2.999V     3.599V
333.3ns   3.3V       3V         3.6V
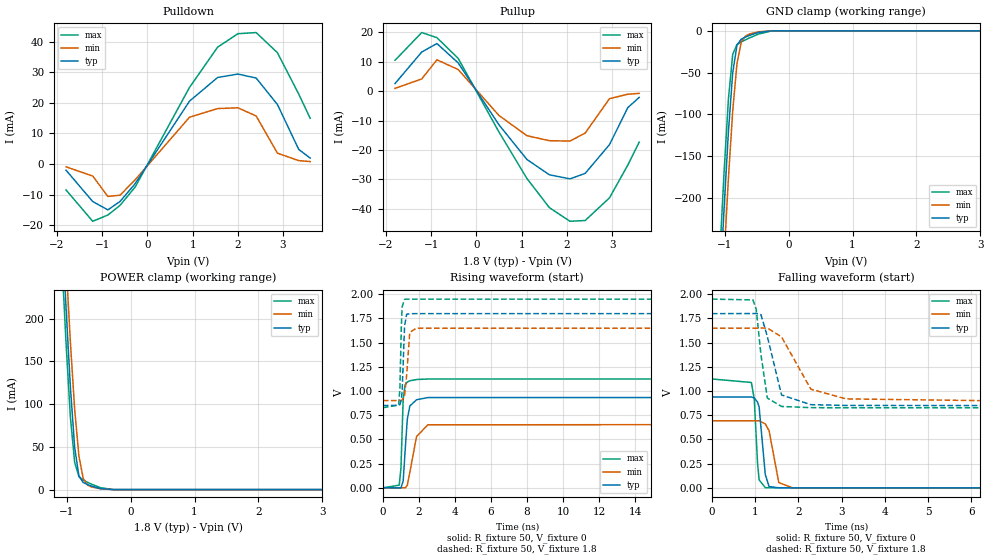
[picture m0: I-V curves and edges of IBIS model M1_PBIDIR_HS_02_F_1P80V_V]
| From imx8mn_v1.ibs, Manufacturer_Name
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[Model] M1_PBIDIR_HS_02_F_1P80V_V
Model_type I/O
Vinl  =  0.54
Vinh  =  1.26
Vmeas =  0.9
| Capacitance   typ   min   max
C_comp   1.53539775078e-12   1.44877555415e-12   1.57947525197e-12
| Variables   typ   min   max
[GND Clamp Reference]   0   0   0
[POWER Clamp Reference]   1.8   1.65   1.95
[Pulldown Reference]   0   0   0
[Pullup Reference]   1.8   1.65   1.95
[Temperature Range]   25   125   -40
[Voltage Range]   1.8   1.65   1.95
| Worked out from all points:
|   slope of the pulldown table from 0 to 0.27 V, typ, clamps not added: 42.7 ohm
|   slope of the pullup table from 0 to 0.27 V, typ, clamps not added: 42.8 ohm
|   GND clamp passes 1 mA (typ) near -0.41 V on its own axis
|   POWER clamp passes 1 mA (typ) near -0.45 V on its own axis
|   falling waveform, R_fixture 50, V_fixture 0: 20-80 % time 100ps typ, 152ps min, 77ps max; typ from 0.94 V to 0 V
|   falling waveform, R_fixture 50, V_fixture 1.8: 20-80 % time 276ps typ, 537ps min, 165ps max; typ from 1.8 V to 0.85 V
|   rising waveform, R_fixture 50, V_fixture 0: 20-80 % time 198ps typ, 444ps min, 114ps max; typ from 0 V to 0.94 V
|   rising waveform, R_fixture 50, V_fixture 1.8: 20-80 % time 105ps typ, 152ps min, 85.7ps max; typ from 0.85 V to 1.8 V
[GND Clamp]
| Voltage   I(typ)   I(min)   I(max)
-1.8V     -1.548A    -1.596A    -1.505A
-1.076V   -314.3mA   -373.2mA   -268.8mA
-1.009V   -212.8mA   -271.6mA   -169.3mA
-941.4mV  -121.4mA   -177.3mA   -82.2mA
-874.1mV  -50.48mA   -96.08mA   -28.29mA
-806.9mV  -17.11mA   -38.85mA   -16.39mA
-739.7mV  -9.89mA    -13.23mA   -13.32mA
-672.4mV  -7.354mA   -6.086mA   -10.75mA
-605.2mV  -5.342mA   -3.664mA   -8.302mA
-470.7mV  -2.022mA   -1.163mA   -3.923mA
-269mV    -32.89uA   -24.7uA    -158uA
3.6V      0A         0A         0A
[POWER Clamp]
| Voltage   I(typ)   I(min)   I(max)
-1.8V     1.548A     1.589A     1.509A
-1.076V   314.3mA    367.1mA    271.2mA
-1.009V   212.5mA    266.1mA    171.6mA
-941.4mV  120.5mA    172.9mA    85.18mA
-874.1mV  49.19mA    93.78mA    31.83mA
-806.9mV  15.58mA    38.69mA    15.29mA
-739.7mV  8.318mA    12.92mA    11.18mA
-672.4mV  5.835mA    5.348mA    8.546mA
-605.2mV  3.963mA    2.968mA    6.156mA
-470.7mV  1.193mA    886.9uA    2.247mA
-269mV    8.729uA    21.24uA    33.73uA
3.6V      0A         0A         0A
[Pulldown]
| Voltage   I(typ)   I(min)   I(max)
-1.8V     -2.035mA   -940.8uA   -8.51mA
-1.21V    -12.3mA    -3.961mA   -18.77mA
-874.1mV  -15.03mA   -10.63mA   -16.71mA
-605.2mV  -12.27mA   -10.22mA   -13.54mA
-269mV    -6.411mA   -5.145mA   -7.502mA
931mV     20.56mA    15.3mA     25.06mA
1.552V    28.3mA     18.13mA    38.22mA
2.002V    29.43mA    18.38mA    42.64mA
2.405V    28.12mA    15.71mA    43.01mA
2.876V    19.44mA    3.53mA     36.41mA
3.347V    4.751mA    1.093mA    22.87mA
3.6V      1.93mA     781.8uA    14.94mA
[Pullup]
| Voltage   I(typ)   I(min)   I(max)
-1.8V     2.627mA    987.4uA    10.55mA
-1.21V    13.35mA    4.198mA    19.97mA
-874.1mV  16.24mA    10.7mA     18.24mA
-403.4mV  9.647mA    7.393mA    11.18mA
496.6mV   -11.37mA   -8.202mA   -13.82mA
1.117V    -23.21mA   -15.12mA   -29.68mA
1.614V    -28.41mA   -16.81mA   -39.59mA
2.069V    -29.8mA    -16.94mA   -44.23mA
2.405V    -27.94mA   -14.22mA   -43.96mA
2.943V    -18.14mA   -2.509mA   -36.25mA
3.347V    -5.583mA   -1.004mA   -25.13mA
3.6V      -2.082mA   -719uA     -17.29mA
[Ramp]
dV/dt_r   0.563797/0.197984n  0.415926/0.444122n  0.675041/0.114154n
dV/dt_f   0.569826/0.275865n  0.448983/0.537084n  0.673428/0.16511n
R_load = 50
[Falling Waveform]
R_fixture = 50
V_fixture = 0
V_fixture_min = 0
V_fixture_max = 0
| Time   V(typ)   V(min)   V(max)
0s        939.7mV    693.2mV    1.125V
913.2ps   939.5mV    693.2mV    1.089V
979.9ps   928.5mV    693.2mV    920mV
1.055ns   886.9mV    693.2mV    263.1mV
1.092ns   837.1mV    693.3mV    83.54mV
1.235ns   138.5mV    660.9mV    1.754mV
1.322ns   13.6mV     591.2mV    731.5uV
1.548ns   676.9uV    54.25mV    345.6uV
1.864ns   325.1uV    691.7uV    140.2uV
333.3ns   120.1nV    573.4nV    96.49nV
[Falling Waveform]
R_fixture = 50
V_fixture = 1.8
V_fixture_min = 1.65
V_fixture_max = 1.95
| Time   V(typ)   V(min)   V(max)
0s        1.8V       1.65V      1.95V
949.4ps   1.801V     1.65V      1.942V
1.026ns   1.802V     1.65V      1.845V
1.135ns   1.79V      1.651V     1.375V
1.283ns   1.564V     1.651V     927.6mV
1.611ns   959.8mV    1.56V      841mV
2.289ns   859.4mV    1.019V     828.8mV
3.105ns   851.6mV    919.2mV    827.7mV
6.157ns   850.3mV    901.8mV    827.6mV
333.3ns   850.3mV    901.7mV    827.6mV
[Rising Waveform]
R_fixture = 50
V_fixture = 0
V_fixture_min = 0
V_fixture_max = 0
| Time   V(typ)   V(min)   V(max)
0s        88.78nV    572.5nV    84.57nV
908.9ps   -671.8uV   189.1nV    26.39mV
1.004ns   -1.033mV   -180.2uV   200mV
1.129ns   70.87mV    -884.9uV   918.3mV
1.238ns   387.6mV    -844uV     1.064V
1.357ns   709mV      23.74mV    1.093V
1.499ns   845.5mV    161.2mV    1.106V
1.87ns    910mV      529.3mV    1.119V
2.499ns   932.3mV    650.6mV    1.124V
333.3ns   939.7mV    693.2mV    1.125V
[Rising Waveform]
R_fixture = 50
V_fixture = 1.8
V_fixture_min = 1.65
V_fixture_max = 1.95
| Time   V(typ)   V(min)   V(max)
0s        850.3mV    901.7mV    827.6mV
875ps     851.2mV    901.7mV    855.7mV
945.2ps   860.1mV    901.6mV    1.023V
1.028ns   908.5mV    902.9mV    1.676V
1.072ns   999.9mV    906.6mV    1.872V
1.206ns   1.675V     954.4mV    1.948V
1.322ns   1.794V     1.164V     1.95V
1.493ns   1.799V     1.607V     1.95V
1.863ns   1.8V       1.649V     1.95V
333.3ns   1.8V       1.65V      1.95V
[Add Submodel]
| Submodel Name Mode
M1_PBIDIR_HS_02_F_1P80V_T_V All
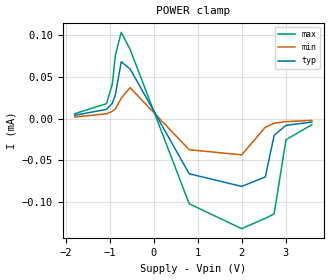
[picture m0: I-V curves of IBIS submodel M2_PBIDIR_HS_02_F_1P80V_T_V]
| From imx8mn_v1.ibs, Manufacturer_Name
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| Submodel
[Submodel]  M2_PBIDIR_HS_02_F_1P80V_T_V
Submodel_type Dynamic_clamp
[POWER Clamp]
| Voltage   I(typ)   I(min)   I(max)
-1.8V     4.108uA    2.082uA    5.96uA
-1.076V   11.15uA    5.91uA     18.05uA
-941.4mV  18.71uA    8.836uA    41.65uA
-874.1mV  28.31uA    11.68uA    75.83uA
-739.7mV  68.3uA     24.61uA    103.6uA
-537.9mV  59.82uA    37.24uA    83.28uA
806.9mV   -66.08uA   -37.26uA   -102.1uA
2.002V    -81.28uA   -43.4uA    -132uA
2.54V     -69.95uA   -10.29uA   -119.6uA
2.741V    -19.88uA   -5.484uA   -114.3uA
3.01V     -7.987uA   -3.507uA   -25.26uA
3.6V      -4.108uA   -2.027uA   -7.198uA
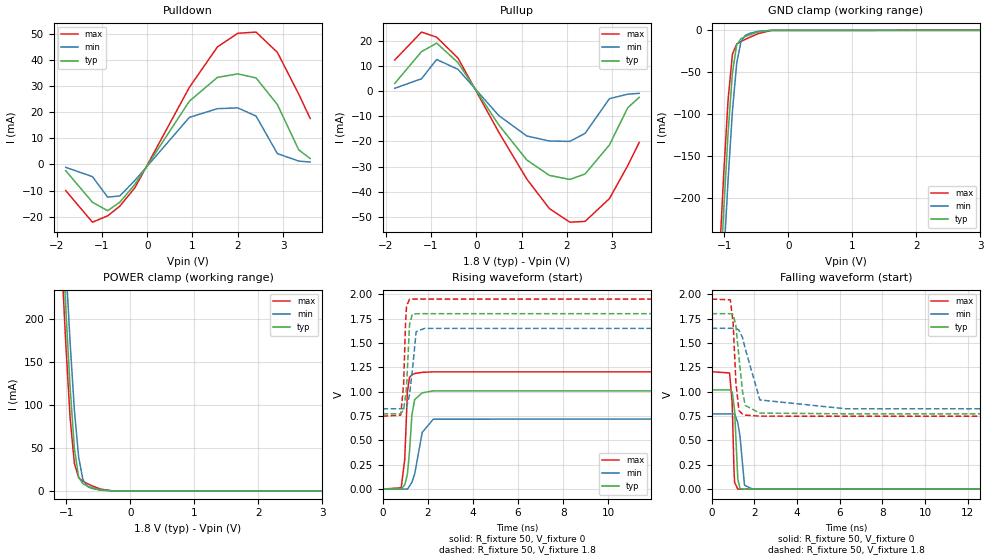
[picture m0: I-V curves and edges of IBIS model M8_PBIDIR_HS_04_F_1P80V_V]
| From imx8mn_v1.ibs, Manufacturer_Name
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[Model] M8_PBIDIR_HS_04_F_1P80V_V
Model_type I/O
Vinl  =  0.54
Vinh  =  1.26
Vmeas =  0.9
| Capacitance   typ   min   max
C_comp   1.53539775078e-12   1.44877555415e-12   1.57947525197e-12
| Variables   typ   min   max
[GND Clamp Reference]   0   0   0
[POWER Clamp Reference]   1.8   1.65   1.95
[Pulldown Reference]   0   0   0
[Pullup Reference]   1.8   1.65   1.95
[Temperature Range]   25   125   -40
[Voltage Range]   1.8   1.65   1.95
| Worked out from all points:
|   slope of the pulldown table from 0 to 0.27 V, typ, clamps not added: 36.2 ohm
|   slope of the pullup table from 0 to 0.27 V, typ, clamps not added: 36.3 ohm
|   GND clamp passes 1 mA (typ) near -0.41 V on its own axis
|   POWER clamp passes 1 mA (typ) near -0.45 V on its own axis
|   falling waveform, R_fixture 50, V_fixture 0: 20-80 % time 131ps typ, 195ps min, 99.1ps max; typ from 1.02 V to 0 V
|   falling waveform, R_fixture 50, V_fixture 1.8: 20-80 % time 273ps typ, 567ps min, 160ps max; typ from 1.8 V to 0.773 V
|   rising waveform, R_fixture 50, V_fixture 0: 20-80 % time 192ps typ, 395ps min, 134ps max; typ from 0 V to 1.02 V
|   rising waveform, R_fixture 50, V_fixture 1.8: 20-80 % time 139ps typ, 198ps min, 113ps max; typ from 0.773 V to 1.8 V
[GND Clamp]
| Voltage   I(typ)   I(min)   I(max)
-1.8V     -1.548A    -1.596A    -1.505A
-1.076V   -314.3mA   -373.2mA   -268.8mA
-1.009V   -212.8mA   -271.6mA   -169.3mA
-941.4mV  -121.4mA   -177.3mA   -82.2mA
-874.1mV  -50.48mA   -96.08mA   -28.29mA
-806.9mV  -17.11mA   -38.85mA   -16.39mA
-739.7mV  -9.89mA    -13.23mA   -13.32mA
-672.4mV  -7.354mA   -6.086mA   -10.75mA
-605.2mV  -5.342mA   -3.664mA   -8.302mA
-470.7mV  -2.022mA   -1.163mA   -3.923mA
-269mV    -32.89uA   -24.7uA    -158uA
3.6V      0A         0A         0A
[POWER Clamp]
| Voltage   I(typ)   I(min)   I(max)
-1.8V     1.548A     1.589A     1.509A
-1.076V   314.3mA    367.1mA    271.2mA
-1.009V   212.5mA    266.1mA    171.6mA
-941.4mV  120.5mA    172.9mA    85.18mA
-874.1mV  49.19mA    93.78mA    31.83mA
-806.9mV  15.58mA    38.69mA    15.29mA
-739.7mV  8.318mA    12.92mA    11.18mA
-672.4mV  5.835mA    5.348mA    8.546mA
-605.2mV  3.963mA    2.968mA    6.156mA
-470.7mV  1.193mA    886.9uA    2.247mA
-269mV    8.729uA    21.24uA    33.73uA
3.6V      0A         0A         0A
[Pulldown]
| Voltage   I(typ)   I(min)   I(max)
-1.8V     -2.399mA   -1.109mA   -10.03mA
-1.21V    -14.49mA   -4.669mA   -22.12mA
-874.1mV  -17.71mA   -12.53mA   -19.69mA
-605.2mV  -14.46mA   -12.05mA   -15.96mA
-269mV    -7.556mA   -6.063mA   -8.842mA
931mV     24.23mA    18.03mA    29.53mA
1.552V    33.35mA    21.37mA    45.05mA
2.002V    34.69mA    21.66mA    50.25mA
2.405V    33.14mA    18.51mA    50.7mA
2.876V    22.92mA    4.16mA     42.91mA
3.347V    5.6mA      1.288mA    26.95mA
3.6V      2.274mA    921.5uA    17.61mA
[Pullup]
| Voltage   I(typ)   I(min)   I(max)
-1.8V     3.096mA    1.164mA    12.43mA
-1.21V    15.74mA    4.948mA    23.53mA
-874.1mV  19.14mA    12.62mA    21.49mA
-403.4mV  11.37mA    8.713mA    13.18mA
496.6mV   -13.4mA    -9.667mA   -16.29mA
1.117V    -27.36mA   -17.82mA   -34.98mA
1.614V    -33.49mA   -19.82mA   -46.67mA
2.069V    -35.12mA   -19.97mA   -52.13mA
2.405V    -32.93mA   -16.76mA   -51.81mA
2.943V    -21.38mA   -2.957mA   -42.73mA
3.347V    -6.58mA    -1.183mA   -29.62mA
3.6V      -2.454mA   -847.3uA   -20.38mA
[Ramp]
dV/dt_r   0.611031/0.191582n  0.463047/0.395198n  0.72283/0.13439n
dV/dt_f   0.616303/0.273186n  0.495304/0.567366n  0.721158/0.160278n
R_load = 50
[Falling Waveform]
R_fixture = 50
V_fixture = 0
V_fixture_min = 0
V_fixture_max = 0
| Time   V(typ)   V(min)   V(max)
0s        1.018V     771.7mV    1.205V
843.2ps   1.018V     771.8mV    1.192V
966.1ps   996.5mV    771.8mV    883.4mV
1.049ns   863.7mV    771.8mV    204.5mV
1.081ns   799.4mV    772mV      67.06mV
1.228ns   106mV      683.5mV    1.224mV
1.33ns    5.721mV    544.9mV    594.8uV
1.543ns   603.6uV    40.41mV    307.9uV
1.918ns   268.6uV    541.3uV    183.3uV
333.3ns   104.8nV    513.6nV    82.33nV
[Falling Waveform]
R_fixture = 50
V_fixture = 1.8
V_fixture_min = 1.65
V_fixture_max = 1.95
| Time   V(typ)   V(min)   V(max)
0s        1.8V       1.65V      1.95V
877.8ps   1.8V       1.65V      1.942V
1.011ns   1.792V     1.65V      1.702V
1.14ns    1.675V     1.651V     1.092V
1.282ns   1.355V     1.63V      807.6mV
1.453ns   996.9mV    1.553V     768.2mV
1.578ns   858.2mV    1.441V     759.7mV
2.262ns   780.4mV    915.3mV    749.1mV
6.298ns   772.8mV    824.5mV    748mV
333.3ns   772.8mV    824.5mV    748.1mV
[Rising Waveform]
R_fixture = 50
V_fixture = 0
V_fixture_min = 0
V_fixture_max = 0
| Time   V(typ)   V(min)   V(max)
0s        77.47nV    512.8nV    72.19nV
825.1ps   -82.25uV   -20.18uV   13.35mV
982.4ps   44.09mV    -165.1uV   302.4mV
1.1ns     150.8mV    -702.9uV   993.7mV
1.192ns   378.8mV    29.76mV    1.144V
1.302ns   762.8mV    70.81mV    1.174V
1.424ns   918.6mV    155.2mV    1.186V
1.758ns   987.8mV    581.9mV    1.198V
2.248ns   1.008V     717.3mV    1.203V
333.3ns   1.018V     771.7mV    1.205V
[Rising Waveform]
R_fixture = 50
V_fixture = 1.8
V_fixture_min = 1.65
V_fixture_max = 1.95
| Time   V(typ)   V(min)   V(max)
0s        772.8mV    824.5mV    748.1mV
805.9ps   772.8mV    824.5mV    759.1mV
933.4ps   815.3mV    824.4mV    1.076V
1.018ns   952.7mV    825.9mV    1.691V
1.063ns   1.05V      833.4mV    1.879V
1.197ns   1.69V      971.8mV    1.949V
1.324ns   1.797V     1.223V     1.95V
1.489ns   1.799V     1.615V     1.95V
1.854ns   1.8V       1.649V     1.95V
333.3ns   1.8V       1.65V      1.95V
[Add Submodel]
| Submodel Name Mode
M8_PBIDIR_HS_04_F_1P80V_T_V All
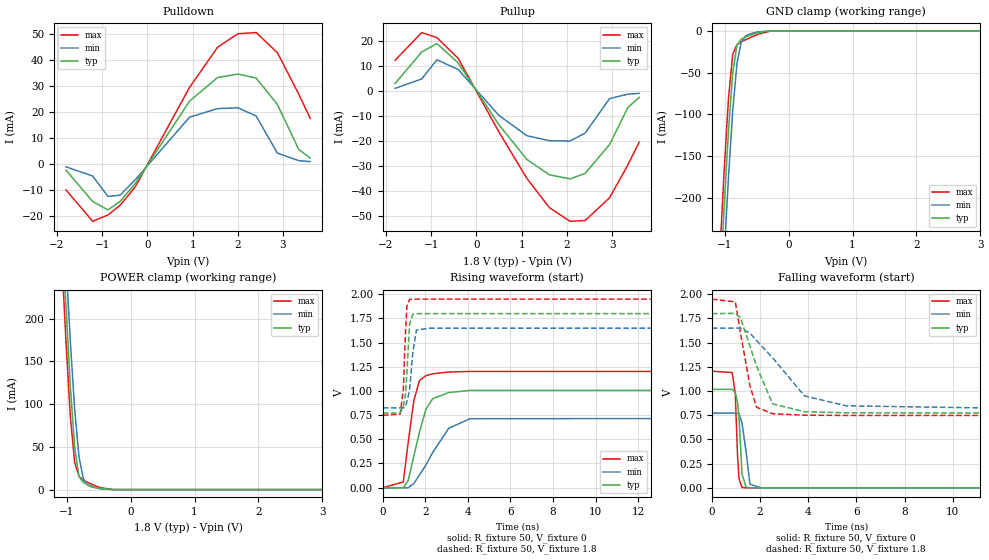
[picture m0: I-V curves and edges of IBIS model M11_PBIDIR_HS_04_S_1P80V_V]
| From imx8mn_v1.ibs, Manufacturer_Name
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[Model] M11_PBIDIR_HS_04_S_1P80V_V
Model_type I/O
Vinl  =  0.54
Vinh  =  1.26
Vmeas =  0.9
| Capacitance   typ   min   max
C_comp   1.53539775078e-12   1.44877555415e-12   1.57947525197e-12
| Variables   typ   min   max
[GND Clamp Reference]   0   0   0
[POWER Clamp Reference]   1.8   1.65   1.95
[Pulldown Reference]   0   0   0
[Pullup Reference]   1.8   1.65   1.95
[Temperature Range]   25   125   -40
[Voltage Range]   1.8   1.65   1.95
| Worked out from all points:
|   slope of the pulldown table from 0 to 0.27 V, typ, clamps not added: 36.2 ohm
|   slope of the pullup table from 0 to 0.27 V, typ, clamps not added: 36.3 ohm
|   GND clamp passes 1 mA (typ) near -0.41 V on its own axis
|   POWER clamp passes 1 mA (typ) near -0.45 V on its own axis
|   falling waveform, R_fixture 50, V_fixture 0: 20-80 % time 132ps typ, 190ps min, 111ps max; typ from 1.02 V to 0 V
|   falling waveform, R_fixture 50, V_fixture 1.8: 20-80 % time 854ps typ, 1.63ns min, 514ps max; typ from 1.8 V to 0.773 V
|   rising waveform, R_fixture 50, V_fixture 0: 20-80 % time 709ps typ, 1.32ns min, 420ps max; typ from 0 V to 1.02 V
|   rising waveform, R_fixture 50, V_fixture 1.8: 20-80 % time 152ps typ, 202ps min, 126ps max; typ from 0.773 V to 1.8 V
[GND Clamp]
| Voltage   I(typ)   I(min)   I(max)
-1.8V     -1.548A    -1.596A    -1.505A
-1.076V   -314.3mA   -373.2mA   -268.8mA
-1.009V   -212.8mA   -271.6mA   -169.3mA
-941.4mV  -121.4mA   -177.3mA   -82.2mA
-874.1mV  -50.48mA   -96.08mA   -28.29mA
-806.9mV  -17.11mA   -38.85mA   -16.39mA
-739.7mV  -9.89mA    -13.23mA   -13.32mA
-672.4mV  -7.354mA   -6.086mA   -10.75mA
-605.2mV  -5.342mA   -3.664mA   -8.302mA
-470.7mV  -2.022mA   -1.163mA   -3.923mA
-269mV    -32.89uA   -24.7uA    -158uA
3.6V      0A         0A         0A
[POWER Clamp]
| Voltage   I(typ)   I(min)   I(max)
-1.8V     1.548A     1.589A     1.509A
-1.076V   314.3mA    367.1mA    271.2mA
-1.009V   212.5mA    266.1mA    171.6mA
-941.4mV  120.5mA    172.9mA    85.18mA
-874.1mV  49.19mA    93.78mA    31.83mA
-806.9mV  15.58mA    38.69mA    15.29mA
-739.7mV  8.318mA    12.92mA    11.18mA
-672.4mV  5.835mA    5.348mA    8.546mA
-605.2mV  3.963mA    2.968mA    6.156mA
-470.7mV  1.193mA    886.9uA    2.247mA
-269mV    8.729uA    21.24uA    33.73uA
3.6V      0A         0A         0A
[Pulldown]
| Voltage   I(typ)   I(min)   I(max)
-1.8V     -2.399mA   -1.109mA   -10.03mA
-1.21V    -14.49mA   -4.669mA   -22.12mA
-874.1mV  -17.71mA   -12.53mA   -19.69mA
-605.2mV  -14.46mA   -12.05mA   -15.96mA
-269mV    -7.556mA   -6.063mA   -8.842mA
931mV     24.23mA    18.03mA    29.53mA
1.552V    33.35mA    21.37mA    45.05mA
2.002V    34.69mA    21.66mA    50.25mA
2.405V    33.14mA    18.51mA    50.7mA
2.876V    22.92mA    4.16mA     42.91mA
3.347V    5.6mA      1.288mA    26.95mA
3.6V      2.274mA    921.5uA    17.61mA
[Pullup]
| Voltage   I(typ)   I(min)   I(max)
-1.8V     3.096mA    1.164mA    12.43mA
-1.21V    15.74mA    4.947mA    23.53mA
-874.1mV  19.14mA    12.62mA    21.49mA
-403.4mV  11.37mA    8.713mA    13.18mA
496.6mV   -13.4mA    -9.667mA   -16.29mA
1.117V    -27.36mA   -17.82mA   -34.98mA
1.614V    -33.49mA   -19.82mA   -46.67mA
2.069V    -35.12mA   -19.97mA   -52.13mA
2.405V    -32.93mA   -16.76mA   -51.81mA
2.943V    -21.38mA   -2.957mA   -42.73mA
3.347V    -6.58mA    -1.183mA   -29.62mA
3.6V      -2.454mA   -847.3uA   -20.38mA
[Ramp]
dV/dt_r   0.611031/0.709314n  0.463047/1.3203n  0.72283/0.41953n
dV/dt_f   0.616303/0.853755n  0.495304/1.63047n  0.721158/0.513898n
R_load = 50
[Falling Waveform]
R_fixture = 50
V_fixture = 0
V_fixture_min = 0
V_fixture_max = 0
| Time   V(typ)   V(min)   V(max)
0s        1.018V     771.7mV    1.205V
842.5ps   1.018V     771.7mV    1.192V
970.9ps   990.1mV    771.7mV    976.4mV
1.068ns   877mV      771.9mV    325.2mV
1.131ns   715.5mV    765.8mV    88.66mV
1.253ns   144mV      665.5mV    3.962mV
1.418ns   6.765mV    380.2mV    603.8uV
1.58ns    873uV      37.94mV    460.4uV
2.036ns   335.8uV    574.9uV    276.7uV
333.3ns   104.9nV    513.6nV    82.2nV
[Falling Waveform]
R_fixture = 50
V_fixture = 1.8
V_fixture_min = 1.65
V_fixture_max = 1.95
| Time   V(typ)   V(min)   V(max)
0s        1.8V       1.65V      1.95V
974.6ps   1.803V     1.65V      1.921V
1.187ns   1.759V     1.652V     1.602V
1.58ns    1.466V     1.599V     1.056V
1.856ns   1.258V     1.522V     832.7mV
2.521ns   868.3mV    1.344V     766.3mV
3.846ns   786.5mV    950.2mV    750.7mV
5.576ns   775.4mV    847.8mV    748.4mV
11.48ns   772.8mV    825.2mV    748mV
333.3ns   772.8mV    824.5mV    748.1mV
[Rising Waveform]
R_fixture = 50
V_fixture = 0
V_fixture_min = 0
V_fixture_max = 0
| Time   V(typ)   V(min)   V(max)
0s        77.47nV    512.8nV    72.19nV
960.2ps   -2.115mV   -49.74uV   58.39mV
1.189ns   73.46mV    -849.6uV   463.4mV
1.456ns   325.6mV    41.85mV    900.9mV
1.725ns   575.5mV    133.2mV    1.109V
2.026ns   812mV      234.8mV    1.158V
2.343ns   919.9mV    364.3mV    1.178V
3.099ns   983.9mV    614.4mV    1.196V
4.099ns   1.006V     713mV      1.202V
333.3ns   1.018V     771.7mV    1.205V
[Rising Waveform]
R_fixture = 50
V_fixture = 1.8
V_fixture_min = 1.65
V_fixture_max = 1.95
| Time   V(typ)   V(min)   V(max)
0s        772.8mV    824.5mV    748.1mV
814.2ps   772.7mV    824.5mV    761.4mV
961.6ps   841.2mV    824.2mV    1.008V
1.06ns    955.4mV    833mV      1.584V
1.129ns   1.186V     888.6mV    1.874V
1.255ns   1.687V     1.008V     1.947V
1.411ns   1.795V     1.402V     1.949V
1.578ns   1.799V     1.63V      1.95V
2.163ns   1.8V       1.649V     1.95V
333.3ns   1.8V       1.65V      1.95V
[Add Submodel]
| Submodel Name Mode
M11_PBIDIR_HS_04_S_1P80V_T_V All
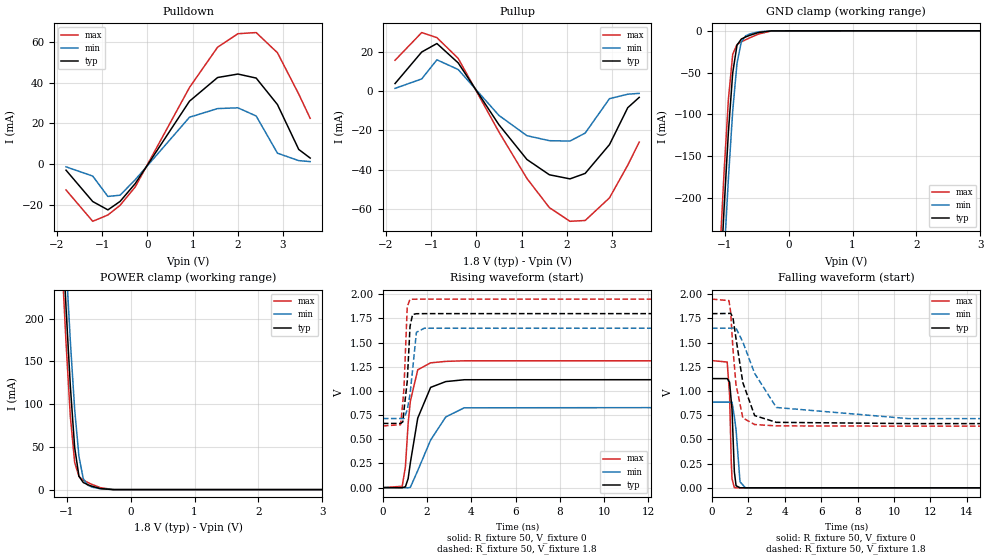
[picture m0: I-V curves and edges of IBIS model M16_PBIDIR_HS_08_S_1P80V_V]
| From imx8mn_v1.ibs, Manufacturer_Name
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[Model] M16_PBIDIR_HS_08_S_1P80V_V
Model_type I/O
Vinl  =  0.54
Vinh  =  1.26
Vmeas =  0.9
| Capacitance   typ   min   max
C_comp   1.53539775078e-12   1.44877555415e-12   1.57947525197e-12
| Variables   typ   min   max
[GND Clamp Reference]   0   0   0
[POWER Clamp Reference]   1.8   1.65   1.95
[Pulldown Reference]   0   0   0
[Pullup Reference]   1.8   1.65   1.95
[Temperature Range]   25   125   -40
[Voltage Range]   1.8   1.65   1.95
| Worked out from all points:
|   slope of the pulldown table from 0 to 0.27 V, typ, clamps not added: 28.4 ohm
|   slope of the pullup table from 0 to 0.27 V, typ, clamps not added: 28.5 ohm
|   GND clamp passes 1 mA (typ) near -0.41 V on its own axis
|   POWER clamp passes 1 mA (typ) near -0.45 V on its own axis
|   falling waveform, R_fixture 50, V_fixture 0: 20-80 % time 159ps typ, 234ps min, 120ps max; typ from 1.13 V to 0 V
|   falling waveform, R_fixture 50, V_fixture 1.8: 20-80 % time 690ps typ, 1.43ns min, 386ps max; typ from 1.8 V to 0.664 V
|   rising waveform, R_fixture 50, V_fixture 0: 20-80 % time 583ps typ, 1.17ns min, 317ps max; typ from 0 V to 1.13 V
|   rising waveform, R_fixture 50, V_fixture 1.8: 20-80 % time 181ps typ, 262ps min, 149ps max; typ from 0.664 V to 1.8 V
[GND Clamp]
| Voltage   I(typ)   I(min)   I(max)
-1.8V     -1.548A    -1.596A    -1.505A
-1.076V   -314.3mA   -373.2mA   -268.8mA
-1.009V   -212.8mA   -271.6mA   -169.3mA
-941.4mV  -121.4mA   -177.3mA   -82.2mA
-874.1mV  -50.48mA   -96.08mA   -28.29mA
-806.9mV  -17.11mA   -38.85mA   -16.39mA
-739.7mV  -9.89mA    -13.23mA   -13.32mA
-672.4mV  -7.354mA   -6.086mA   -10.75mA
-605.2mV  -5.342mA   -3.664mA   -8.302mA
-470.7mV  -2.022mA   -1.163mA   -3.923mA
-269mV    -32.89uA   -24.7uA    -158uA
3.6V      0A         0A         0A
[POWER Clamp]
| Voltage   I(typ)   I(min)   I(max)
-1.8V     1.548A     1.589A     1.509A
-1.076V   314.3mA    367.1mA    271.2mA
-1.009V   212.5mA    266.1mA    171.6mA
-941.4mV  120.5mA    172.9mA    85.18mA
-874.1mV  49.19mA    93.78mA    31.83mA
-806.9mV  15.58mA    38.69mA    15.29mA
-739.7mV  8.318mA    12.92mA    11.18mA
-672.4mV  5.835mA    5.348mA    8.546mA
-605.2mV  3.963mA    2.968mA    6.156mA
-470.7mV  1.193mA    886.9uA    2.247mA
-269mV    8.729uA    21.24uA    33.73uA
3.6V      0A         0A         0A
[Pulldown]
| Voltage   I(typ)   I(min)   I(max)
-1.8V     -3.053mA   -1.411mA   -12.77mA
-1.21V    -18.44mA   -5.942mA   -28.15mA
-874.1mV  -22.54mA   -15.95mA   -25.06mA
-605.2mV  -18.4mA    -15.34mA   -20.31mA
-269mV    -9.617mA   -7.717mA   -11.25mA
931mV     30.84mA    22.95mA    37.58mA
1.552V    42.45mA    27.2mA     57.33mA
2.002V    44.15mA    27.57mA    63.96mA
2.405V    42.18mA    23.56mA    64.52mA
2.876V    29.17mA    5.294mA    54.61mA
3.347V    7.127mA    1.639mA    34.3mA
3.6V      2.894mA    1.173mA    22.41mA
[Pullup]
| Voltage   I(typ)   I(min)   I(max)
-1.8V     3.94mA     1.481mA    15.82mA
-1.21V    20.03mA    6.297mA    29.95mA
-874.1mV  24.36mA    16.06mA    27.36mA
-403.4mV  14.47mA    11.09mA    16.77mA
496.6mV   -17.05mA   -12.3mA    -20.73mA
1.117V    -34.82mA   -22.67mA   -44.51mA
1.614V    -42.62mA   -25.22mA   -59.39mA
2.069V    -44.7mA    -25.41mA   -66.35mA
2.405V    -41.91mA   -21.33mA   -65.94mA
2.943V    -27.21mA   -3.764mA   -54.38mA
3.347V    -8.374mA   -1.506mA   -37.7mA
3.6V      -3.123mA   -1.078mA   -25.94mA
[Ramp]
dV/dt_r   0.677502/0.582826n  0.531648/1.17076n  0.78912/0.317325n
dV/dt_f   0.681601/0.69014n  0.561111/1.42821n  0.787398/0.386209n
R_load = 50
[Falling Waveform]
R_fixture = 50
V_fixture = 0
V_fixture_min = 0
V_fixture_max = 0
| Time   V(typ)   V(min)   V(max)
0s        1.129V     886.1mV    1.315V
842.6ps   1.129V     886.1mV    1.3V
973.3ps   1.092V     886.1mV    959.7mV
1.063ns   901.7mV    886.3mV    283.2mV
1.107ns   807.8mV    884.9mV    93.07mV
1.235ns   166.9mV    735.6mV    2.435mV
1.33ns    21.45mV    597.2mV    826uV
1.546ns   964.3uV    62.37mV    462.6uV
1.844ns   475.4uV    924.8uV    296.7uV
333.3ns   83.19nV    426.9nV    62.74nV
[Falling Waveform]
R_fixture = 50
V_fixture = 1.8
V_fixture_min = 1.65
V_fixture_max = 1.95
| Time   V(typ)   V(min)   V(max)
0s        1.8V       1.65V      1.95V
939.2ps   1.802V     1.65V      1.935V
1.032ns   1.804V     1.65V      1.817V
1.157ns   1.761V     1.652V     1.439V
1.321ns   1.549V     1.651V     1.073V
1.702ns   1.087V     1.507V     721.9mV
2.349ns   747mV      1.183V     654.4mV
3.542ns   677mV      830.5mV    640.3mV
10.8ns    664mV      715.5mV    637.7mV
333.3ns   664mV      714.8mV    637.7mV
[Rising Waveform]
R_fixture = 50
V_fixture = 0
V_fixture_min = 0
V_fixture_max = 0
| Time   V(typ)   V(min)   V(max)
0s        61.46nV    426.2nV    54.95nV
874.5ps   -1.498mV   -15.89uV   13.68mV
1.021ns   9.428mV    -1.01mV    219.2mV
1.143ns   93.25mV    -2.529mV   664mV
1.244ns   257.8mV    3.811mV    895.3mV
1.577ns   719mV      176.1mV    1.219V
2.159ns   1.037V     492.4mV    1.291V
2.845ns   1.097V     731.6mV    1.306V
3.678ns   1.116V     825.7mV    1.312V
333.3ns   1.129V     886.1mV    1.315V
[Rising Waveform]
R_fixture = 50
V_fixture = 1.8
V_fixture_min = 1.65
V_fixture_max = 1.95
| Time   V(typ)   V(min)   V(max)
0s        664mV      714.8mV    637.7mV
802.6ps   663.9mV    714.8mV    651.3mV
902.6ps   680.1mV    714.8mV    885.6mV
954.5ps   800.7mV    714.5mV    1.029V
1.103ns   1.101V     804.5mV    1.874V
1.229ns   1.669V     966.2mV    1.948V
1.344ns   1.791V     1.217V     1.949V
1.517ns   1.799V     1.607V     1.949V
1.878ns   1.8V       1.649V     1.95V
333.3ns   1.8V       1.65V      1.95V
[Add Submodel]
| Submodel Name Mode
M16_PBIDIR_HS_08_S_1P80V_T_V All
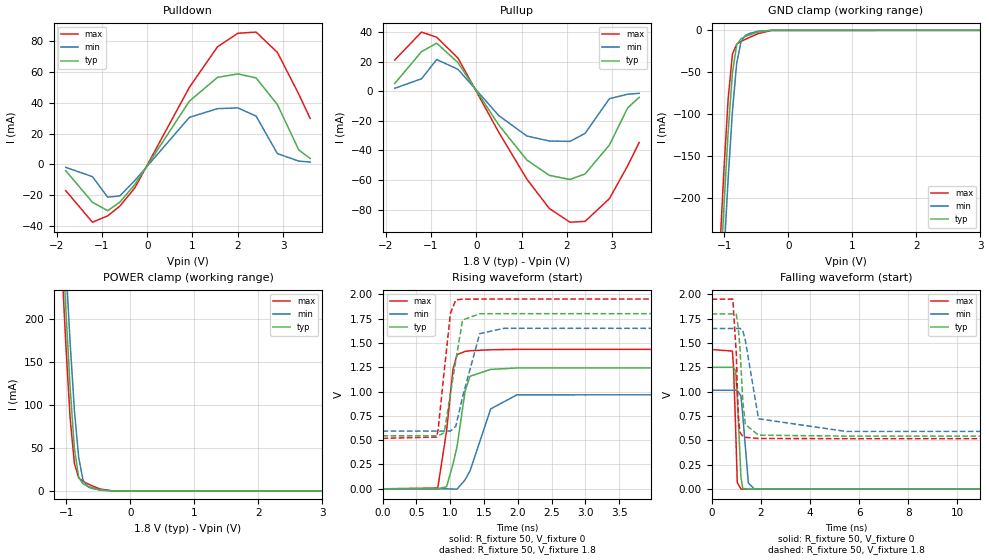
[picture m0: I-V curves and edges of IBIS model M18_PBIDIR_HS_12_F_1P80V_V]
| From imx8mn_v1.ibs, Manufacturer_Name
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[Model] M18_PBIDIR_HS_12_F_1P80V_V
Model_type I/O
Vinl  =  0.54
Vinh  =  1.26
Vmeas =  0.9
| Capacitance   typ   min   max
C_comp   1.53539775078e-12   1.44877555415e-12   1.57947525197e-12
| Variables   typ   min   max
[GND Clamp Reference]   0   0   0
[POWER Clamp Reference]   1.8   1.65   1.95
[Pulldown Reference]   0   0   0
[Pullup Reference]   1.8   1.65   1.95
[Temperature Range]   25   125   -40
[Voltage Range]   1.8   1.65   1.95
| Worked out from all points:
|   slope of the pulldown table from 0 to 0.27 V, typ, clamps not added: 21.3 ohm
|   slope of the pullup table from 0 to 0.27 V, typ, clamps not added: 21.4 ohm
|   GND clamp passes 1 mA (typ) near -0.41 V on its own axis
|   POWER clamp passes 1 mA (typ) near -0.45 V on its own axis
|   falling waveform, R_fixture 50, V_fixture 0: 20-80 % time 135ps typ, 188ps min, 105ps max; typ from 1.25 V to 0 V
|   falling waveform, R_fixture 50, V_fixture 1.8: 20-80 % time 182ps typ, 368ps min, 122ps max; typ from 1.8 V to 0.545 V
|   rising waveform, R_fixture 50, V_fixture 0: 20-80 % time 179ps typ, 285ps min, 145ps max; typ from 0 V to 1.25 V
|   rising waveform, R_fixture 50, V_fixture 1.8: 20-80 % time 165ps typ, 225ps min, 130ps max; typ from 0.545 V to 1.8 V
[GND Clamp]
| Voltage   I(typ)   I(min)   I(max)
-1.8V     -1.548A    -1.596A    -1.505A
-1.076V   -314.3mA   -373.2mA   -268.8mA
-1.009V   -212.8mA   -271.6mA   -169.3mA
-941.4mV  -121.4mA   -177.3mA   -82.2mA
-874.1mV  -50.48mA   -96.08mA   -28.29mA
-806.9mV  -17.11mA   -38.85mA   -16.39mA
-739.7mV  -9.89mA    -13.23mA   -13.32mA
-672.4mV  -7.354mA   -6.086mA   -10.75mA
-605.2mV  -5.342mA   -3.664mA   -8.302mA
-470.7mV  -2.022mA   -1.163mA   -3.923mA
-269mV    -32.89uA   -24.7uA    -158uA
3.6V      0A         0A         0A
[POWER Clamp]
| Voltage   I(typ)   I(min)   I(max)
-1.8V     1.548A     1.589A     1.509A
-1.076V   314.3mA    367.1mA    271.2mA
-1.009V   212.5mA    266.1mA    171.6mA
-941.4mV  120.5mA    172.9mA    85.18mA
-874.1mV  49.19mA    93.78mA    31.83mA
-806.9mV  15.58mA    38.69mA    15.29mA
-739.7mV  8.318mA    12.92mA    11.18mA
-672.4mV  5.835mA    5.348mA    8.546mA
-605.2mV  3.963mA    2.968mA    6.156mA
-470.7mV  1.193mA    886.9uA    2.247mA
-269mV    8.729uA    21.24uA    33.73uA
3.6V      0A         0A         0A
[Pulldown]
| Voltage   I(typ)   I(min)   I(max)
-1.8V     -4.07mA    -1.882mA   -17.02mA
-1.21V    -24.59mA   -7.922mA   -37.53mA
-874.1mV  -30.05mA   -21.26mA   -33.42mA
-605.2mV  -24.53mA   -20.45mA   -27.09mA
-269mV    -12.82mA   -10.29mA   -15mA
931mV     41.12mA    30.6mA     50.11mA
1.552V    56.59mA    36.27mA    76.44mA
2.002V    58.87mA    36.76mA    85.28mA
2.405V    56.24mA    31.42mA    86.03mA
2.876V    38.89mA    7.059mA    72.82mA
3.347V    9.502mA    2.185mA    45.74mA
3.6V      3.859mA    1.564mA    29.89mA
[Pullup]
| Voltage   I(typ)   I(min)   I(max)
-1.8V     5.253mA    1.975mA    21.1mA
-1.21V    26.7mA     8.395mA    39.94mA
-874.1mV  32.48mA    21.41mA    36.47mA
-403.4mV  19.29mA    14.79mA    22.37mA
496.6mV   -22.74mA   -16.4mA    -27.64mA
1.117V    -46.43mA   -30.23mA   -59.35mA
1.614V    -56.83mA   -33.63mA   -79.19mA
2.069V    -59.6mA    -33.89mA   -88.46mA
2.405V    -55.88mA   -28.44mA   -87.92mA
2.943V    -36.28mA   -5.018mA   -72.51mA
3.347V    -11.17mA   -2.008mA   -50.26mA
3.6V      -4.164mA   -1.438mA   -34.59mA
[Ramp]
dV/dt_r   0.750384/0.178824n  0.609482/0.284575n  0.860548/0.144545n
dV/dt_f   0.753164/0.181738n  0.634351/0.367645n  0.858826/0.121637n
R_load = 50
[Falling Waveform]
R_fixture = 50
V_fixture = 0
V_fixture_min = 0
V_fixture_max = 0
| Time   V(typ)   V(min)   V(max)
0s        1.251V     1.016V     1.434V
846.9ps   1.251V     1.016V     1.418V
892.4ps   1.251V     1.016V     1.255V
974ps     1.219V     1.016V     671.4mV
1.045ns   955.1mV    1.016V     68.44mV
1.194ns   124.6mV    957.3mV    1.086mV
1.268ns   7.229mV    760.5mV    668.3uV
1.495ns   748.9uV    64.87mV    426.5uV
1.741ns   360.4uV    884.1uV    163.9uV
333.3ns   59.13nV    328.3nV    41.44nV
[Falling Waveform]
R_fixture = 50
V_fixture = 1.8
V_fixture_min = 1.65
V_fixture_max = 1.95
| Time   V(typ)   V(min)   V(max)
0s        1.8V       1.65V      1.95V
864.4ps   1.8V       1.65V      1.952V
1.005ns   1.796V     1.65V      1.39V
1.083ns   1.661V     1.65V      766.1mV
1.151ns   1.465V     1.652V     585.6mV
1.271ns   903mV      1.629V     542.8mV
1.375ns   663.5mV    1.526V     532.3mV
1.909ns   554.4mV    722.7mV    520.1mV
5.467ns   544.7mV    592.9mV    518.7mV
333.3ns   544.7mV    592.7mV    518.6mV
[Rising Waveform]
R_fixture = 50
V_fixture = 0
V_fixture_min = 0
V_fixture_max = 0
| Time   V(typ)   V(min)   V(max)
0s        43.75nV    327.8nV    36.24nV
816.3ps   -209.3uV   24.73uV    7.94mV
947.1ps   21.22mV    -105.7uV   597.2mV
1.042ns   254.4mV    -2.244mV   1.229V
1.102ns   434.1mV    -3.653mV   1.379V
1.221ns   1.007V     92.16mV    1.412V
1.293ns   1.156V     184.1mV    1.419V
1.599ns   1.227V     821.1mV    1.429V
1.988ns   1.242V     965.9mV    1.433V
333.3ns   1.251V     1.016V     1.434V
[Rising Waveform]
R_fixture = 50
V_fixture = 1.8
V_fixture_min = 1.65
V_fixture_max = 1.95
| Time   V(typ)   V(min)   V(max)
0s        544.7mV    592.7mV    518.6mV
800.1ps   544.7mV    592.7mV    531.7mV
822.9ps   544.5mV    592.7mV    613mV
912.1ps   576.3mV    592.7mV    1.211V
1.004ns   980.5mV    594.3mV    1.805V
1.083ns   1.316V     642.4mV    1.941V
1.183ns   1.735V     944.1mV    1.949V
1.437ns   1.799V     1.595V     1.95V
1.794ns   1.8V       1.649V     1.95V
333.3ns   1.8V       1.65V      1.95V
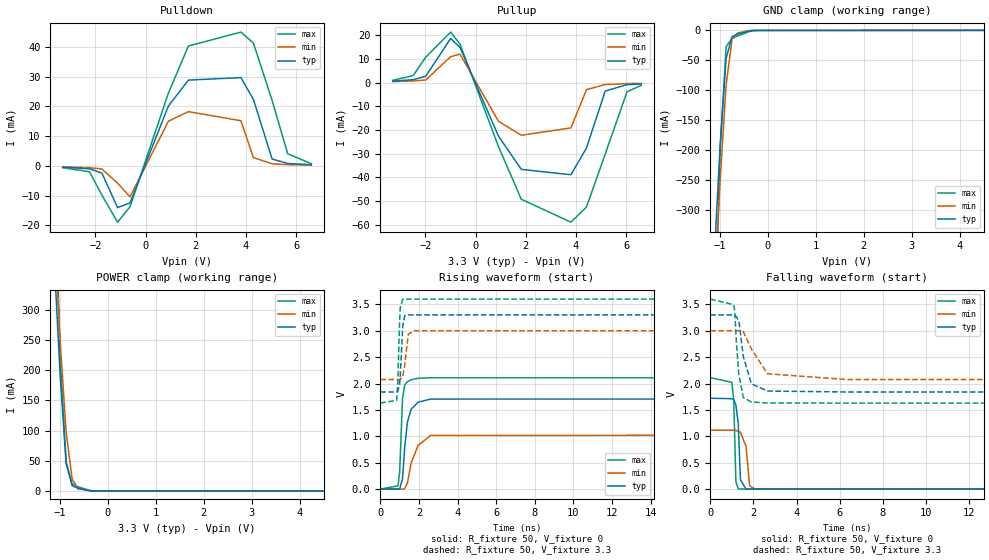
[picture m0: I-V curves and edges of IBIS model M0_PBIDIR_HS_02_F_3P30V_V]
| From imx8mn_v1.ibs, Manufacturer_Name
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|[Package Model]   There is an optional, fairly complex Package Modeling
|   section here in the file if you want it.  You will have
|   to add it yourself, because SiliconSmart has no
|   notion of packaging.  Please see the IBIS Specification
|   for details.
[Model] M0_PBIDIR_HS_02_F_3P30V_V
Model_type I/O
Vinl  =  0.99
Vinh  =  2.31
Vmeas =  1.65
| Capacitance   typ   min   max
C_comp   1.22244310993e-12   1.16607071583e-12   1.23815957393e-12
| Variables   typ   min   max
[GND Clamp Reference]   0   0   0
[POWER Clamp Reference]   3.3   3   3.6
[Pulldown Reference]   0   0   0
[Pullup Reference]   3.3   3   3.6
[Temperature Range]   25   125   -40
[Voltage Range]   3.3   3   3.6
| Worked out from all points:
|   slope of the pulldown table from 0 to 0.495 V, typ, clamps not added: 43.3 ohm
|   slope of the pullup table from 0 to 0.495 V, typ, clamps not added: 38.9 ohm
|   GND clamp passes 1 mA (typ) near -0.39 V on its own axis
|   POWER clamp passes 1 mA (typ) near -0.44 V on its own axis
|   falling waveform, R_fixture 50, V_fixture 0: 20-80 % time 104ps typ, 163ps min, 71ps max; typ from 1.72 V to 0.002 V
|   falling waveform, R_fixture 50, V_fixture 3.3: 20-80 % time 360ps typ, 619ps min, 209ps max; typ from 3.3 V to 1.84 V
|   rising waveform, R_fixture 50, V_fixture 0: 20-80 % time 279ps typ, 644ps min, 132ps max; typ from 0.002 V to 1.72 V
|   rising waveform, R_fixture 50, V_fixture 3.3: 20-80 % time 118ps typ, 160ps min, 92.7ps max; typ from 1.84 V to 3.3 V
[GND Clamp]
| Voltage   I(typ)   I(min)   I(max)
-3.3V     -7.219A    -6.55A     -7.983A
-1.117V   -379.7mA   -438.1mA   -545mA
-993.1mV  -190.6mA   -249mA     -198.3mA
-869mV    -46.5mA    -90.69mA   -26.94mA
-744.8mV  -10.3mA    -14.35mA   -13.73mA
-620.7mV  -5.936mA   -4.181mA   -9.061mA
-372.4mV  -657.8uA   -359.5uA   -1.669mA
-248.3mV  -143.8uA   -94.2uA    -265.2uA
6.6V      0A         0A         0A
[POWER Clamp]
| Voltage   I(typ)   I(min)   I(max)
-3.3V     7.219A     6.549A     7.988A
-1.117V   380mA      433mA      551.8mA
-993.1mV  190.2mA    246.7mA    219.2mA
-869mV    45.16mA    97.2mA     48.21mA
-744.8mV  8.611mA    19.76mA    11.76mA
-620.7mV  4.381mA    3.461mA    6.782mA
-372.4mV  212.2uA    289.1uA    754.3uA
-248.3mV  4.207uA    22.11uA    50.1uA
6.6V      0A         0A         0A
[Pulldown]
| Voltage   I(typ)   I(min)   I(max)
-3.3V     -418uA     -290.4uA   -573.6uA
-2.234V   -960.8uA   -577.2uA   -1.964mA
-1.738V   -2.4mA     -1.029mA   -9.794mA
-1.117V   -14mA      -5.754mA   -18.91mA
-620.7mV  -12.45mA   -10.38mA   -13.75mA
910.3mV   20.17mA    15.07mA    24.54mA
1.707V    28.88mA    18.27mA    40.34mA
3.797V    29.71mA    15.21mA    45.02mA
4.293V    22.41mA    2.817mA    41.31mA
5.038V    2.344mA    722.2uA    22.08mA
5.659V    836.8uA    436.3uA    4.124mA
6.6V      424.7uA    271.1uA    744.9uA
[Pullup]
| Voltage   I(typ)   I(min)   I(max)
-3.3V     630.6uA    400.5uA    937.9uA
-2.483V   1.193mA    660.5uA    2.943mA
-1.986V   2.645mA    1.07mA     10.71mA
-993.1mV  18.6mA     10.91mA    21.3mA
-620.7mV  14.82mA    12.02mA    16.23mA
910.3mV   -22.59mA   -16.33mA   -26.98mA
1.821V    -36.65mA   -22.25mA   -49.27mA
3.797V    -38.92mA   -19.13mA   -58.94mA
4.417V    -27.59mA   -2.983mA   -52.53mA
5.162V    -3.593mA   -834.9uA   -30.2mA
6.031V    -880.2uA   -447.6uA   -3.862mA
6.6V      -597uA     -342.4uA   -1.197mA
[Ramp]
dV/dt_r   1.03216/0.279036n  0.669826/0.644223n  1.26547/0.13154n
dV/dt_f   0.875645/0.359576n  0.553973/0.618615n  1.1814/0.208667n
R_load = 50
[Falling Waveform]
R_fixture = 50
V_fixture = 0
V_fixture_min = 0
V_fixture_max = 0
| Time   V(typ)   V(min)   V(max)
0s        1.723V     1.118V     2.112V
995.9ps   1.714V     1.118V     2.025V
1.085ns   1.697V     1.118V     1.696V
1.187ns   1.593V     1.112V     145.2mV
1.297ns   1.241V     1.098V     7.032mV
1.397ns   181.4mV    1.078V     3.927mV
1.656ns   2.984mV    808.8mV    3.523mV
1.824ns   2.759mV    63.93mV    3.469mV
2.076ns   2.544mV    2.15mV     3.388mV
333.3ns   2.285mV    1.529mV    3.196mV
[Falling Waveform]
R_fixture = 50
V_fixture = 3.3
V_fixture_min = 3
V_fixture_max = 3.6
| Time   V(typ)   V(min)   V(max)
0s        3.3V       3V         3.6V
1.087ns   3.301V     3V         3.493V
1.134ns   3.292V     3V         3.374V
1.218ns   3.26V      3.001V     2.715V
1.324ns   3.185V     3.001V     2.166V
1.528ns   2.516V     2.983V     1.738V
1.9ns     1.997V     2.659V     1.651V
2.646ns   1.859V     2.186V     1.633V
6.334ns   1.841V     2.077V     1.631V
333.3ns   1.841V     2.077V     1.631V
[Rising Waveform]
R_fixture = 50
V_fixture = 0
V_fixture_min = 0
V_fixture_max = 0
| Time   V(typ)   V(min)   V(max)
0s        2.285mV    1.529mV    3.196mV
917ps     1.541mV    1.551mV    61.91mV
1.004ns   3.99mV     1.279mV    324.6mV
1.152ns   197.4mV    638.5uV    1.714V
1.264ns   784.2mV    12.26mV    1.97V
1.404ns   1.268V     111.5mV    2.035V
1.596ns   1.514V     493.9mV    2.072V
1.957ns   1.647V     827.6mV    2.1V
2.6ns     1.706V     1.017V     2.11V
333.3ns   1.723V     1.118V     2.112V
[Rising Waveform]
R_fixture = 50
V_fixture = 3.3
V_fixture_min = 3
V_fixture_max = 3.6
| Time   V(typ)   V(min)   V(max)
0s        1.841V     2.077V     1.631V
848.1ps   1.841V     2.077V     1.682V
907.4ps   1.856V     2.077V     2.005V
997.1ps   1.982V     2.077V     3.153V
1.034ns   2.144V     2.08V      3.432V
1.165ns   3.091V     2.143V     3.597V
1.265ns   3.286V     2.348V     3.599V
1.454ns   3.299V     2.938V     3.599V
1.77ns    3.3V       2.999V     3.6V
333.3ns   3.3V       3V         3.6V
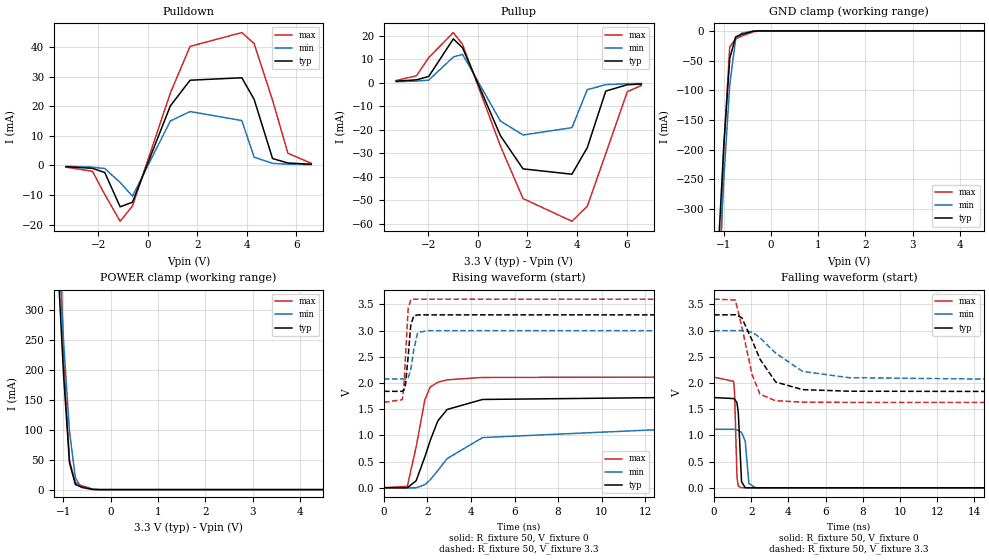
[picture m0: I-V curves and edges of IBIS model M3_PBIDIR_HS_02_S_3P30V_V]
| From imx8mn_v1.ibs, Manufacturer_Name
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[Model] M3_PBIDIR_HS_02_S_3P30V_V
Model_type I/O
Vinl  =  0.99
Vinh  =  2.31
Vmeas =  1.65
| Capacitance   typ   min   max
C_comp   1.22244310993e-12   1.16607071583e-12   1.23815957393e-12
| Variables   typ   min   max
[GND Clamp Reference]   0   0   0
[POWER Clamp Reference]   3.3   3   3.6
[Pulldown Reference]   0   0   0
[Pullup Reference]   3.3   3   3.6
[Temperature Range]   25   125   -40
[Voltage Range]   3.3   3   3.6
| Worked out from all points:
|   slope of the pulldown table from 0 to 0.495 V, typ, clamps not added: 43.3 ohm
|   slope of the pullup table from 0 to 0.495 V, typ, clamps not added: 38.9 ohm
|   GND clamp passes 1 mA (typ) near -0.39 V on its own axis
|   POWER clamp passes 1 mA (typ) near -0.44 V on its own axis
|   falling waveform, R_fixture 50, V_fixture 0: 20-80 % time 106ps typ, 137ps min, 87.7ps max; typ from 1.72 V to 0.002 V
|   falling waveform, R_fixture 50, V_fixture 3.3: 20-80 % time 1.16ns typ, 1.87ns min, 743ps max; typ from 3.3 V to 1.84 V
|   rising waveform, R_fixture 50, V_fixture 0: 20-80 % time 951ps typ, 1.78ns min, 569ps max; typ from 0.002 V to 1.72 V
|   rising waveform, R_fixture 50, V_fixture 3.3: 20-80 % time 168ps typ, 199ps min, 140ps max; typ from 1.84 V to 3.3 V
[GND Clamp]
| Voltage   I(typ)   I(min)   I(max)
-3.3V     -7.219A    -6.55A     -7.983A
-1.117V   -379.7mA   -438.1mA   -545mA
-993.1mV  -190.6mA   -249mA     -198.3mA
-869mV    -46.5mA    -90.69mA   -26.94mA
-744.8mV  -10.3mA    -14.35mA   -13.73mA
-620.7mV  -5.936mA   -4.181mA   -9.061mA
-372.4mV  -657.8uA   -359.5uA   -1.669mA
-248.3mV  -143.8uA   -94.2uA    -265.2uA
6.6V      0A         0A         0A
[POWER Clamp]
| Voltage   I(typ)   I(min)   I(max)
-3.3V     7.219A     6.549A     7.988A
-1.117V   380mA      433mA      551.8mA
-993.1mV  190.2mA    246.7mA    219.2mA
-869mV    45.16mA    97.2mA     48.21mA
-744.8mV  8.611mA    19.76mA    11.76mA
-620.7mV  4.381mA    3.461mA    6.782mA
-372.4mV  212.2uA    289.1uA    754.3uA
-248.3mV  4.207uA    22.11uA    50.1uA
6.6V      0A         0A         0A
[Pulldown]
| Voltage   I(typ)   I(min)   I(max)
-3.3V     -418uA     -290.4uA   -573.6uA
-2.234V   -960.8uA   -577.2uA   -1.964mA
-1.738V   -2.4mA     -1.029mA   -9.794mA
-1.117V   -14mA      -5.754mA   -18.91mA
-620.7mV  -12.45mA   -10.38mA   -13.75mA
910.3mV   20.17mA    15.07mA    24.54mA
1.707V    28.88mA    18.27mA    40.34mA
3.797V    29.71mA    15.21mA    45.02mA
4.293V    22.41mA    2.817mA    41.31mA
5.038V    2.344mA    722.2uA    22.08mA
5.659V    836.8uA    436.3uA    4.124mA
6.6V      424.7uA    271.1uA    744.9uA
[Pullup]
| Voltage   I(typ)   I(min)   I(max)
-3.3V     629.9uA    400.5uA    934.6uA
-2.483V   1.192mA    660.3uA    2.92mA
-1.986V   2.641mA    1.07mA     10.68mA
-993.1mV  18.59mA    10.91mA    21.29mA
-620.7mV  14.82mA    12.02mA    16.23mA
910.3mV   -22.59mA   -16.33mA   -26.98mA
1.821V    -36.65mA   -22.25mA   -49.27mA
3.797V    -38.92mA   -19.13mA   -58.94mA
4.417V    -27.59mA   -2.983mA   -52.53mA
5.162V    -3.593mA   -834.9uA   -30.19mA
6.031V    -880.2uA   -447.6uA   -3.861mA
6.6V      -597uA     -342.4uA   -1.197mA
[Ramp]
dV/dt_r   1.03215/0.951387n  0.669825/1.77605n  1.26544/0.568528n
dV/dt_f   0.875645/1.16354n  0.553973/1.86778n  1.1814/0.74318n
R_load = 50
[Falling Waveform]
R_fixture = 50
V_fixture = 0
V_fixture_min = 0
V_fixture_max = 0
| Time   V(typ)   V(min)   V(max)
0s        1.723V     1.118V     2.112V
1.053ns   1.704V     1.118V     2.032V
1.102ns   1.692V     1.118V     1.817V
1.232ns   1.624V     1.107V     208.2mV
1.304ns   1.435V     1.096V     32.84mV
1.478ns   120mV      1.057V     4.456mV
1.676ns   4.657mV    893.6mV    4.042mV
1.872ns   3.223mV    87.44mV    3.757mV
2.236ns   2.981mV    2.681mV    3.614mV
333.3ns   2.285mV    1.529mV    3.196mV
[Falling Waveform]
R_fixture = 50
V_fixture = 3.3
V_fixture_min = 3
V_fixture_max = 3.6
| Time   V(typ)   V(min)   V(max)
0s        3.3V       3V         3.6V
1.148ns   3.301V     3V         3.583V
1.491ns   3.247V     3.001V     3.076V
2.049ns   2.812V     2.973V     2.157V
2.47ns    2.455V     2.865V     1.788V
3.315ns   2.02V      2.57V      1.662V
4.759ns   1.875V     2.223V     1.636V
7.255ns   1.844V     2.102V     1.631V
14.17ns   1.84V      2.077V     1.631V
333.3ns   1.841V     2.077V     1.631V
[Rising Waveform]
R_fixture = 50
V_fixture = 0
V_fixture_min = 0
V_fixture_max = 0
| Time   V(typ)   V(min)   V(max)
0s        2.285mV    1.529mV    3.196mV
1.073ns   714uV      956.1uV    29.2mV
1.48ns    136.2mV    -137.5uV   781.4mV
1.881ns   591.5mV    60.99mV    1.682V
2.129ns   906.9mV    153.9mV    1.923V
2.473ns   1.275V     328.1mV    2.014V
2.903ns   1.495V     558.2mV    2.061V
4.529ns   1.686V     959mV      2.106V
12.94ns   1.723V     1.117V     2.112V
333.3ns   1.723V     1.118V     2.112V
[Rising Waveform]
R_fixture = 50
V_fixture = 3.3
V_fixture_min = 3
V_fixture_max = 3.6
| Time   V(typ)   V(min)   V(max)
0s        1.841V     2.077V     1.631V
846.3ps   1.841V     2.077V     1.682V
916.4ps   1.863V     2.077V     1.929V
992.8ps   1.973V     2.077V     2.539V
1.114ns   2.512V     2.106V     3.422V
1.231ns   3.098V     2.247V     3.59V
1.371ns   3.282V     2.638V     3.599V
1.549ns   3.299V     2.962V     3.599V
2.002ns   3.3V       2.999V     3.6V
333.3ns   3.3V       3V         3.6V
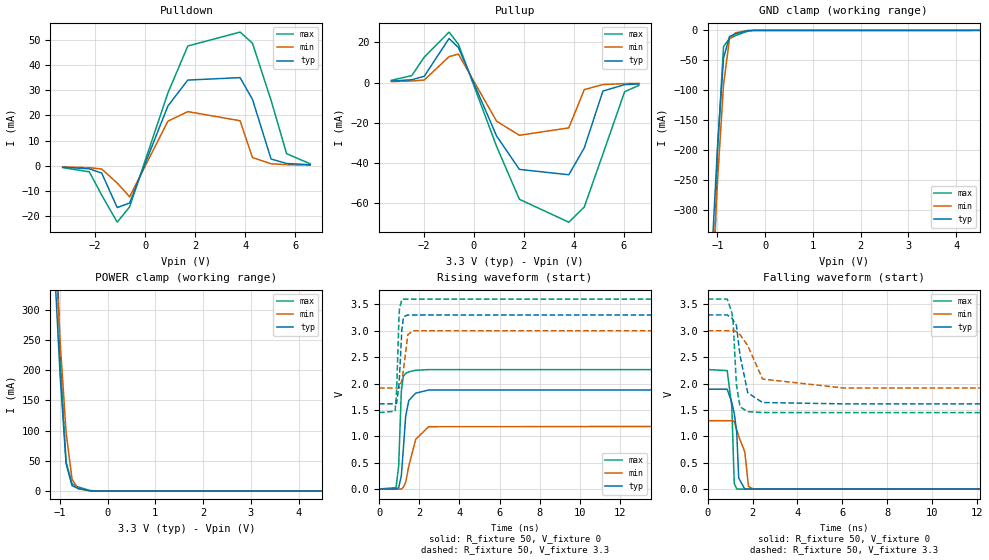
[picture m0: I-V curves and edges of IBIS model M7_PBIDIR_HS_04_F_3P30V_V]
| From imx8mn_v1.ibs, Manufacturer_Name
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[Model] M7_PBIDIR_HS_04_F_3P30V_V
Model_type I/O
Vinl  =  0.99
Vinh  =  2.31
Vmeas =  1.65
| Capacitance   typ   min   max
C_comp   1.22244310993e-12   1.16607071583e-12   1.23815957393e-12
| Variables   typ   min   max
[GND Clamp Reference]   0   0   0
[POWER Clamp Reference]   3.3   3   3.6
[Pulldown Reference]   0   0   0
[Pullup Reference]   3.3   3   3.6
[Temperature Range]   25   125   -40
[Voltage Range]   3.3   3   3.6
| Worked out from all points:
|   slope of the pulldown table from 0 to 0.495 V, typ, clamps not added: 36.7 ohm
|   slope of the pullup table from 0 to 0.495 V, typ, clamps not added: 33 ohm
|   GND clamp passes 1 mA (typ) near -0.39 V on its own axis
|   POWER clamp passes 1 mA (typ) near -0.44 V on its own axis
|   falling waveform, R_fixture 50, V_fixture 0: 20-80 % time 222ps typ, 409ps min, 133ps max; typ from 1.89 V to 0.002 V
|   falling waveform, R_fixture 50, V_fixture 3.3: 20-80 % time 319ps typ, 586ps min, 167ps max; typ from 3.3 V to 1.62 V
|   rising waveform, R_fixture 50, V_fixture 0: 20-80 % time 225ps typ, 565ps min, 124ps max; typ from 0.002 V to 1.89 V
|   rising waveform, R_fixture 50, V_fixture 3.3: 20-80 % time 142ps typ, 199ps min, 107ps max; typ from 1.62 V to 3.3 V
[GND Clamp]
| Voltage   I(typ)   I(min)   I(max)
-3.3V     -7.219A    -6.55A     -7.983A
-1.117V   -379.7mA   -438.1mA   -545mA
-993.1mV  -190.6mA   -249mA     -198.3mA
-869mV    -46.5mA    -90.69mA   -26.94mA
-744.8mV  -10.3mA    -14.35mA   -13.73mA
-620.7mV  -5.936mA   -4.181mA   -9.061mA
-372.4mV  -657.8uA   -359.5uA   -1.669mA
-248.3mV  -143.8uA   -94.2uA    -265.2uA
6.6V      0A         0A         0A
[POWER Clamp]
| Voltage   I(typ)   I(min)   I(max)
-3.3V     7.219A     6.549A     7.988A
-1.117V   380mA      433mA      551.8mA
-993.1mV  190.2mA    246.7mA    219.2mA
-869mV    45.16mA    97.2mA     48.21mA
-744.8mV  8.611mA    19.76mA    11.76mA
-620.7mV  4.381mA    3.461mA    6.782mA
-372.4mV  212.2uA    289.1uA    754.3uA
-248.3mV  4.207uA    22.11uA    50.1uA
6.6V      0A         0A         0A
[Pulldown]
| Voltage   I(typ)   I(min)   I(max)
-3.3V     -492.5uA   -342.1uA   -675.4uA
-2.234V   -1.132mA   -680.4uA   -2.314mA
-1.738V   -2.828mA   -1.213mA   -11.54mA
-1.117V   -16.5mA    -6.781mA   -22.29mA
-620.7mV  -14.68mA   -12.23mA   -16.2mA
910.3mV   23.77mA    17.76mA    28.92mA
1.707V    34.04mA    21.53mA    47.54mA
3.797V    35.01mA    17.93mA    53.06mA
4.293V    26.42mA    3.32mA     48.68mA
5.038V    2.762mA    851.2uA    26.02mA
5.659V    986.3uA    514uA      4.861mA
6.6V      500.3uA    319.6uA    877.9uA
[Pullup]
| Voltage   I(typ)   I(min)   I(max)
-3.3V     743.2uA    471.8uA    1.106mA
-2.483V   1.406mA    778.4uA    3.472mA
-1.986V   3.117mA    1.261mA    12.63mA
-993.1mV  21.92mA    12.86mA    25.1mA
-620.7mV  17.47mA    14.17mA    19.13mA
910.3mV   -26.62mA   -19.25mA   -31.8mA
1.821V    -43.19mA   -26.23mA   -58.07mA
3.797V    -45.87mA   -22.54mA   -69.46mA
4.417V    -32.52mA   -3.516mA   -61.91mA
5.162V    -4.235mA   -984uA     -35.59mA
6.031V    -1.038mA   -527.7uA   -4.552mA
6.6V      -703.7uA   -403.4uA   -1.411mA
[Ramp]
dV/dt_r   1.13523/0.224811n  0.777647/0.565069n  1.35782/0.123692n
dV/dt_f   1.01044/0.318934n  0.650336/0.58651n  1.29021/0.166674n
R_load = 50
[Falling Waveform]
R_fixture = 50
V_fixture = 0
V_fixture_min = 0
V_fixture_max = 0
| Time   V(typ)   V(min)   V(max)
0s        1.894V     1.297V     2.266V
865.8ps   1.894V     1.297V     2.246V
1.072ns   1.645V     1.298V     1.565V
1.181ns   1.438V     1.285V     109.8mV
1.292ns   1.075V     1.119V     5.091mV
1.38ns    211.4mV    1.004V     3.534mV
1.652ns   2.695mV    703.4mV    3.362mV
1.816ns   2.536mV    51.75mV    3.259mV
2.047ns   2.446mV    2.002mV    3.114mV
333.3ns   2.084mV    1.407mV    2.895mV
[Falling Waveform]
R_fixture = 50
V_fixture = 3.3
V_fixture_min = 3
V_fixture_max = 3.6
| Time   V(typ)   V(min)   V(max)
0s        3.3V       3V         3.6V
870.2ps   3.3V       3V         3.6V
1.08ns    3.238V     3V         3.333V
1.129ns   3.2V       3.001V     3.191V
1.277ns   3.103V     2.985V     1.981V
1.438ns   2.535V     2.927V     1.56V
1.783ns   1.826V     2.718V     1.469V
2.441ns   1.641V     2.086V     1.452V
6.066ns   1.616V     1.916V     1.45V
333.3ns   1.616V     1.916V     1.45V
[Rising Waveform]
R_fixture = 50
V_fixture = 0
V_fixture_min = 0
V_fixture_max = 0
| Time   V(typ)   V(min)   V(max)
0s        2.084mV    1.407mV    2.895mV
846.4ps   1.753mV    1.438mV    28.44mV
978.8ps   29.03mV    1.266mV    441.3mV
1.109ns   251.3mV    -301.5uV   1.845V
1.206ns   738mV      34.52mV    2.133V
1.324ns   1.373V     126.2mV    2.191V
1.48ns    1.679V     432.4mV    2.222V
1.826ns   1.818V     944.6mV    2.252V
2.472ns   1.878V     1.183V     2.264V
333.3ns   1.894V     1.297V     2.266V
[Rising Waveform]
R_fixture = 50
V_fixture = 3.3
V_fixture_min = 3
V_fixture_max = 3.6
| Time   V(typ)   V(min)   V(max)
0s        1.616V     1.916V     1.45V
801.8ps   1.616V     1.916V     1.476V
875.7ps   1.626V     1.916V     1.858V
985.9ps   1.949V     1.916V     3.175V
1.018ns   2.136V     1.92V      3.419V
1.139ns   3.027V     2.066V     3.597V
1.219ns   3.265V     2.258V     3.599V
1.432ns   3.299V     2.925V     3.599V
1.693ns   3.299V     2.999V     3.599V
333.3ns   3.3V       3V         3.6V
[Add Submodel]
| Submodel Name Mode
M7_PBIDIR_HS_04_F_3P30V_T_V All
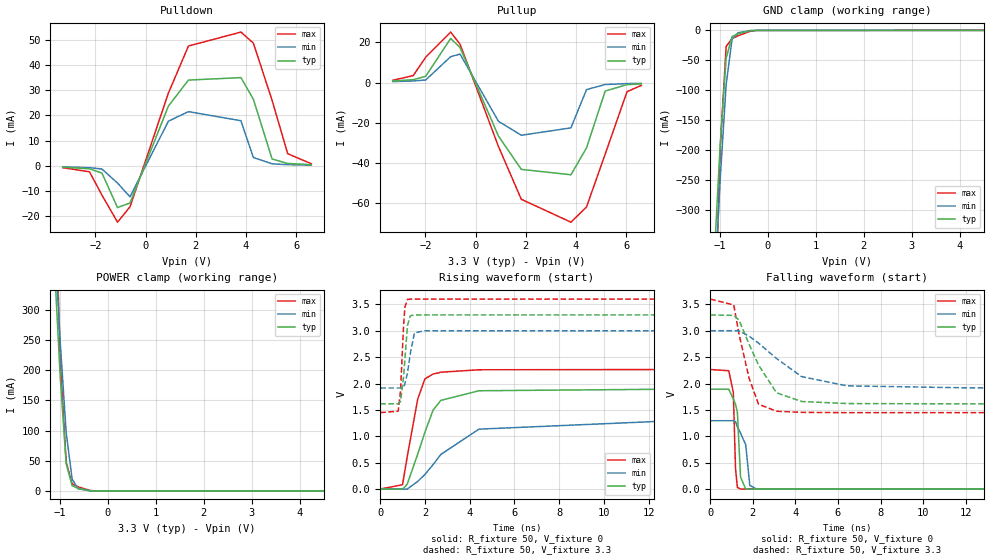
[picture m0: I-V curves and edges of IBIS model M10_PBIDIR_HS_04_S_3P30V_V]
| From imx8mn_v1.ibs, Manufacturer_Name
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[Model] M10_PBIDIR_HS_04_S_3P30V_V
Model_type I/O
Vinl  =  0.99
Vinh  =  2.31
Vmeas =  1.65
| Capacitance   typ   min   max
C_comp   1.22244310993e-12   1.16607071583e-12   1.23815957393e-12
| Variables   typ   min   max
[GND Clamp Reference]   0   0   0
[POWER Clamp Reference]   3.3   3   3.6
[Pulldown Reference]   0   0   0
[Pullup Reference]   3.3   3   3.6
[Temperature Range]   25   125   -40
[Voltage Range]   3.3   3   3.6
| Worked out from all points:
|   slope of the pulldown table from 0 to 0.495 V, typ, clamps not added: 36.7 ohm
|   slope of the pullup table from 0 to 0.495 V, typ, clamps not added: 33 ohm
|   GND clamp passes 1 mA (typ) near -0.39 V on its own axis
|   POWER clamp passes 1 mA (typ) near -0.44 V on its own axis
|   falling waveform, R_fixture 50, V_fixture 0: 20-80 % time 147ps typ, 323ps min, 93.2ps max; typ from 1.89 V to 0.002 V
|   falling waveform, R_fixture 50, V_fixture 3.3: 20-80 % time 1.25ns typ, 2.08ns min, 739ps max; typ from 3.3 V to 1.62 V
|   rising waveform, R_fixture 50, V_fixture 0: 20-80 % time 945ps typ, 1.81ns min, 585ps max; typ from 0.002 V to 1.89 V
|   rising waveform, R_fixture 50, V_fixture 3.3: 20-80 % time 183ps typ, 236ps min, 142ps max; typ from 1.62 V to 3.3 V
[GND Clamp]
| Voltage   I(typ)   I(min)   I(max)
-3.3V     -7.219A    -6.55A     -7.983A
-1.117V   -379.7mA   -438.1mA   -545mA
-993.1mV  -190.6mA   -249mA     -198.3mA
-869mV    -46.5mA    -90.69mA   -26.94mA
-744.8mV  -10.3mA    -14.35mA   -13.73mA
-620.7mV  -5.936mA   -4.181mA   -9.061mA
-372.4mV  -657.8uA   -359.5uA   -1.669mA
-248.3mV  -143.8uA   -94.2uA    -265.2uA
6.6V      0A         0A         0A
[POWER Clamp]
| Voltage   I(typ)   I(min)   I(max)
-3.3V     7.219A     6.549A     7.988A
-1.117V   380mA      433mA      551.8mA
-993.1mV  190.2mA    246.7mA    219.2mA
-869mV    45.16mA    97.2mA     48.21mA
-744.8mV  8.611mA    19.76mA    11.76mA
-620.7mV  4.381mA    3.461mA    6.782mA
-372.4mV  212.2uA    289.1uA    754.3uA
-248.3mV  4.207uA    22.11uA    50.1uA
6.6V      0A         0A         0A
[Pulldown]
| Voltage   I(typ)   I(min)   I(max)
-3.3V     -492.5uA   -342.1uA   -675.4uA
-2.234V   -1.132mA   -680.4uA   -2.314mA
-1.738V   -2.828mA   -1.213mA   -11.54mA
-1.117V   -16.5mA    -6.781mA   -22.29mA
-620.7mV  -14.68mA   -12.23mA   -16.2mA
910.3mV   23.77mA    17.76mA    28.92mA
1.707V    34.04mA    21.53mA    47.54mA
3.797V    35.01mA    17.93mA    53.06mA
4.293V    26.42mA    3.32mA     48.68mA
5.038V    2.762mA    851.2uA    26.02mA
5.659V    986.3uA    514uA      4.861mA
6.6V      500.3uA    319.6uA    877.9uA
[Pullup]
| Voltage   I(typ)   I(min)   I(max)
-3.3V     742.7uA    471.8uA    1.102mA
-2.483V   1.405mA    778.3uA    3.449mA
-1.986V   3.114mA    1.261mA    12.6mA
-993.1mV  21.91mA    12.86mA    25.09mA
-620.7mV  17.47mA    14.17mA    19.12mA
910.3mV   -26.62mA   -19.25mA   -31.79mA
1.821V    -43.19mA   -26.23mA   -58.07mA
3.797V    -45.87mA   -22.54mA   -69.46mA
4.417V    -32.52mA   -3.516mA   -61.91mA
5.162V    -4.235mA   -984uA     -35.58mA
6.031V    -1.038mA   -527.7uA   -4.55mA
6.6V      -703.7uA   -403.4uA   -1.41mA
[Ramp]
dV/dt_r   1.13522/0.94513n  0.777645/1.81227n  1.3578/0.585123n
dV/dt_f   1.01044/1.25251n  0.650336/2.08028n  1.29021/0.739474n
R_load = 50
[Falling Waveform]
R_fixture = 50
V_fixture = 0
V_fixture_min = 0
V_fixture_max = 0
| Time   V(typ)   V(min)   V(max)
0s        1.894V     1.297V     2.266V
868.2ps   1.894V     1.297V     2.244V
1.082ns   1.709V     1.298V     1.837V
1.185ns   1.609V     1.284V     398mV
1.274ns   1.457V     1.181V     33.39mV
1.421ns   233.8mV    1.062V     4.232mV
1.664ns   3.781mV    844.6mV    3.658mV
1.857ns   3.074mV    74.05mV    3.426mV
2.183ns   2.689mV    2.541mV    3.228mV
333.3ns   2.084mV    1.407mV    2.895mV
[Falling Waveform]
R_fixture = 50
V_fixture = 3.3
V_fixture_min = 3
V_fixture_max = 3.6
| Time   V(typ)   V(min)   V(max)
0s        3.3V       3V         3.6V
1.104ns   3.291V     3.001V     3.488V
1.352ns   3.202V     2.998V     2.933V
1.828ns   2.741V     2.897V     2.097V
2.268ns   2.352V     2.766V     1.609V
3.111ns   1.826V     2.475V     1.477V
4.294ns   1.661V     2.132V     1.455V
6.425ns   1.622V     1.957V     1.45V
12.45ns   1.616V     1.917V     1.45V
333.3ns   1.616V     1.916V     1.45V
[Rising Waveform]
R_fixture = 50
V_fixture = 0
V_fixture_min = 0
V_fixture_max = 0
| Time   V(typ)   V(min)   V(max)
0s        2.084mV    1.407mV    2.895mV
994.4ps   692.9uV    1.138mV    83.81mV
1.201ns   90.96mV    292.6uV    602.7mV
1.673ns   661.6mV    146.1mV    1.703V
1.996ns   1.079V     278.7mV    2.089V
2.364ns   1.499V     466.2mV    2.18V
2.71ns    1.682V     657.9mV    2.215V
4.414ns   1.864V     1.137V     2.261V
13.17ns   1.894V     1.297V     2.266V
333.3ns   1.894V     1.297V     2.266V
[Rising Waveform]
R_fixture = 50
V_fixture = 3.3
V_fixture_min = 3
V_fixture_max = 3.6
| Time   V(typ)   V(min)   V(max)
0s        1.616V     1.916V     1.45V
801.3ps   1.616V     1.916V     1.477V
906.1ps   1.663V     1.916V     1.864V
1.041ns   2.126V     1.928V     3.093V
1.099ns   2.445V     1.993V     3.444V
1.217ns   3.101V     2.202V     3.593V
1.347ns   3.284V     2.575V     3.599V
1.529ns   3.299V     2.96V      3.599V
1.968ns   3.3V       2.999V     3.6V
333.3ns   3.3V       3V         3.6V
[Add Submodel]
| Submodel Name Mode
M10_PBIDIR_HS_04_S_3P30V_T_V All
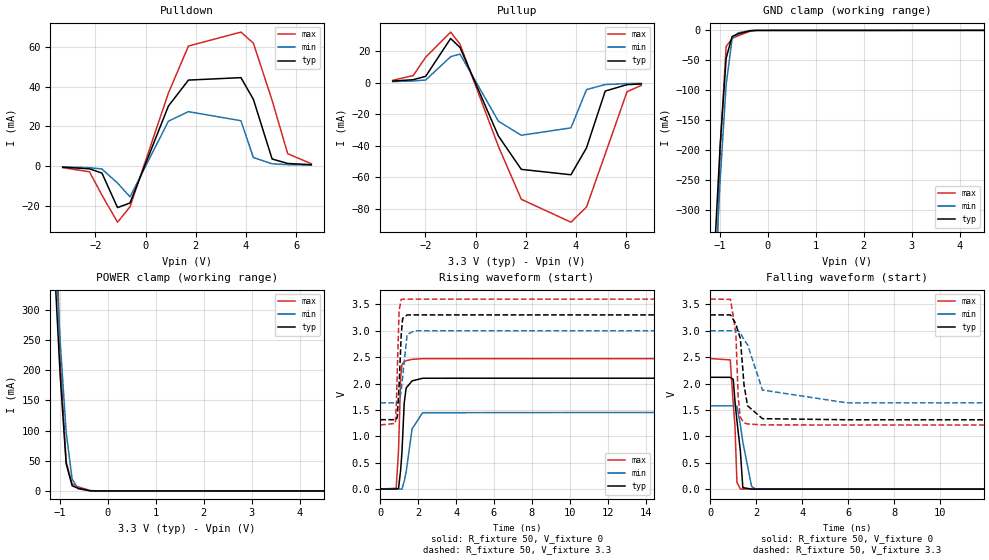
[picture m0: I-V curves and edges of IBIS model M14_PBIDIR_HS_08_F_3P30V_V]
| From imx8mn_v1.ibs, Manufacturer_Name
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[Model] M14_PBIDIR_HS_08_F_3P30V_V
Model_type I/O
Vinl  =  0.99
Vinh  =  2.31
Vmeas =  1.65
| Capacitance   typ   min   max
C_comp   1.22244310993e-12   1.16607071583e-12   1.23815957393e-12
| Variables   typ   min   max
[GND Clamp Reference]   0   0   0
[POWER Clamp Reference]   3.3   3   3.6
[Pulldown Reference]   0   0   0
[Pullup Reference]   3.3   3   3.6
[Temperature Range]   25   125   -40
[Voltage Range]   3.3   3   3.6
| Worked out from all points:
|   slope of the pulldown table from 0 to 0.495 V, typ, clamps not added: 28.8 ohm
|   slope of the pullup table from 0 to 0.495 V, typ, clamps not added: 25.9 ohm
|   GND clamp passes 1 mA (typ) near -0.39 V on its own axis
|   POWER clamp passes 1 mA (typ) near -0.44 V on its own axis
|   falling waveform, R_fixture 50, V_fixture 0: 20-80 % time 274ps typ, 427ps min, 194ps max; typ from 2.12 V to 0.002 V
|   falling waveform, R_fixture 50, V_fixture 3.3: 20-80 % time 278ps typ, 586ps min, 170ps max; typ from 3.3 V to 1.31 V
|   rising waveform, R_fixture 50, V_fixture 0: 20-80 % time 182ps typ, 436ps min, 129ps max; typ from 0.002 V to 2.12 V
|   rising waveform, R_fixture 50, V_fixture 3.3: 20-80 % time 148ps typ, 219ps min, 107ps max; typ from 1.31 V to 3.3 V
[GND Clamp]
| Voltage   I(typ)   I(min)   I(max)
-3.3V     -7.219A    -6.55A     -7.983A
-1.117V   -379.7mA   -438.1mA   -545mA
-993.1mV  -190.6mA   -249mA     -198.3mA
-869mV    -46.5mA    -90.69mA   -26.94mA
-744.8mV  -10.3mA    -14.35mA   -13.73mA
-620.7mV  -5.936mA   -4.181mA   -9.061mA
-372.4mV  -657.8uA   -359.5uA   -1.669mA
-248.3mV  -143.8uA   -94.2uA    -265.2uA
6.6V      0A         0A         0A
[POWER Clamp]
| Voltage   I(typ)   I(min)   I(max)
-3.3V     7.219A     6.549A     7.988A
-1.117V   380mA      433mA      551.8mA
-993.1mV  190.2mA    246.7mA    219.2mA
-869mV    45.16mA    97.2mA     48.21mA
-744.8mV  8.611mA    19.76mA    11.76mA
-620.7mV  4.381mA    3.461mA    6.782mA
-372.4mV  212.2uA    289.1uA    754.3uA
-248.3mV  4.207uA    22.11uA    50.1uA
6.6V      0A         0A         0A
[Pulldown]
| Voltage   I(typ)   I(min)   I(max)
-3.3V     -626.9uA   -435.6uA   -859.9uA
-2.234V   -1.441mA   -865.9uA   -2.945mA
-1.738V   -3.6mA     -1.544mA   -14.69mA
-1.117V   -21mA      -8.631mA   -28.37mA
-620.7mV  -18.68mA   -15.57mA   -20.62mA
910.3mV   30.25mA    22.6mA     36.81mA
1.707V    43.32mA    27.4mA     60.5mA
3.797V    44.56mA    22.82mA    67.54mA
4.293V    33.62mA    4.226mA    61.96mA
5.038V    3.515mA    1.083mA    33.12mA
5.659V    1.255mA    654.7uA    6.186mA
6.6V      636.9uA    406.4uA    1.117mA
[Pullup]
| Voltage   I(typ)   I(min)   I(max)
-3.3V     946uA      600.7uA    1.408mA
-2.483V   1.79mA     990.6uA    4.426mA
-1.986V   3.968mA    1.605mA    16.08mA
-993.1mV  27.89mA    16.37mA    31.95mA
-620.7mV  22.23mA    18.04mA    24.34mA
910.3mV   -33.88mA   -24.5mA    -40.47mA
1.821V    -54.97mA   -33.38mA   -73.91mA
3.797V    -58.38mA   -28.69mA   -88.41mA
4.417V    -41.38mA   -4.474mA   -78.8mA
5.162V    -5.39mA    -1.252mA   -45.29mA
6.031V    -1.32mA    -671.5uA   -5.794mA
6.6V      -895.7uA   -513.6uA   -1.796mA
[Ramp]
dV/dt_r   1.27003/0.182061n  0.946285/0.435832n  1.48263/0.129342n
dV/dt_f   1.19096/0.277827n  0.819502/0.586061n  1.43017/0.169741n
R_load = 50
[Falling Waveform]
R_fixture = 50
V_fixture = 0
V_fixture_min = 0
V_fixture_max = 0
| Time   V(typ)   V(min)   V(max)
0s        2.119V     1.578V     2.474V
867.9ps   2.118V     1.578V     2.448V
1ns       2.078V     1.578V     1.606V
1.072ns   1.67V      1.579V     1.211V
1.159ns   1.296V     1.568V     129.4mV
1.308ns   723.5mV    1.219V     3.292mV
1.415ns   30.71mV    891.5mV    3.161mV
1.796ns   2.175mV    53.43mV    2.693mV
1.959ns   2.061mV    2.067mV    2.572mV
333.3ns   1.799mV    1.231mV    2.476mV
[Falling Waveform]
R_fixture = 50
V_fixture = 3.3
V_fixture_min = 3
V_fixture_max = 3.6
| Time   V(typ)   V(min)   V(max)
0s        3.3V       3V         3.6V
879.6ps   3.3V       3V         3.594V
1.112ns   3.129V     3.001V     2.952V
1.212ns   2.979V     3.001V     1.754V
1.305ns   2.861V     2.962V     1.362V
1.469ns   1.968V     2.828V     1.256V
1.622ns   1.579V     2.735V     1.236V
2.267ns   1.336V     1.878V     1.218V
5.944ns   1.315V     1.635V     1.216V
333.3ns   1.315V     1.634V     1.216V
[Rising Waveform]
R_fixture = 50
V_fixture = 0
V_fixture_min = 0
V_fixture_max = 0
| Time   V(typ)   V(min)   V(max)
0s        1.799mV    1.231mV    2.476mV
837.8ps   1.264mV    1.185mV    14.98mV
963.6ps   13.93mV    1.065mV    730.3mV
1.076ns   360.1mV    -1.324mV   2.132V
1.147ns   717.5mV    3.534mV    2.361V
1.263ns   1.634V     144.8mV    2.414V
1.367ns   1.916V     328.2mV    2.432V
1.679ns   2.05V      1.144V     2.458V
2.237ns   2.1V       1.447V     2.471V
333.3ns   2.119V     1.578V     2.474V
[Rising Waveform]
R_fixture = 50
V_fixture = 3.3
V_fixture_min = 3
V_fixture_max = 3.6
| Time   V(typ)   V(min)   V(max)
0s        1.315V     1.634V     1.216V
793.2ps   1.315V     1.634V     1.244V
852ps     1.318V     1.634V     1.642V
898.5ps   1.375V     1.634V     2.248V
994.9ps   1.988V     1.637V     3.388V
1.107ns   2.935V     1.876V     3.594V
1.18ns    3.233V     2.127V     3.599V
1.418ns   3.299V     2.93V      3.599V
1.804ns   3.3V       2.999V     3.599V
333.3ns   3.3V       3V         3.6V
[Add Submodel]
| Submodel Name Mode
M14_PBIDIR_HS_08_F_3P30V_T_V All
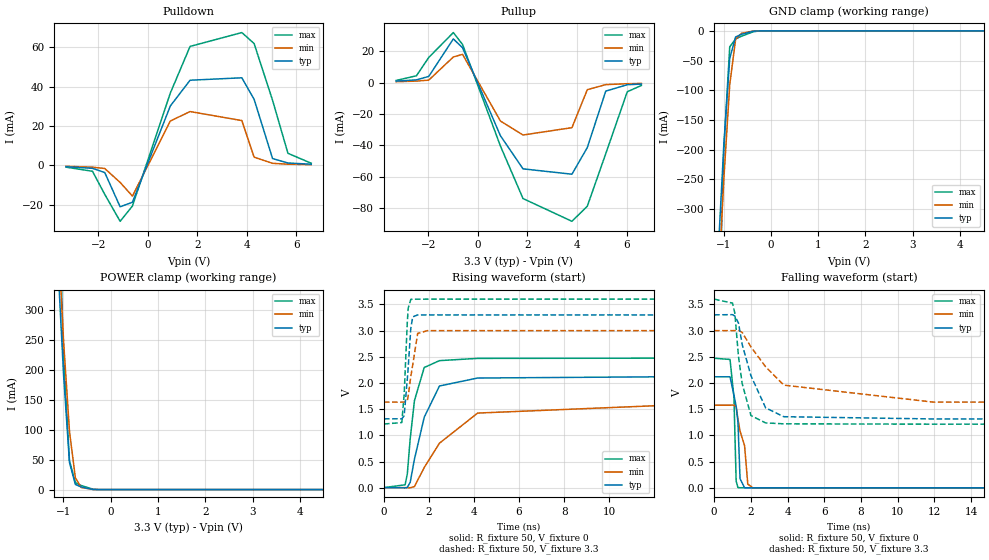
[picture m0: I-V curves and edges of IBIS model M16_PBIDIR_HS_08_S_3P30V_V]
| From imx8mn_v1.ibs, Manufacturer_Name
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[Model] M16_PBIDIR_HS_08_S_3P30V_V
Model_type I/O
Vinl  =  0.99
Vinh  =  2.31
Vmeas =  1.65
| Capacitance   typ   min   max
C_comp   1.22244310993e-12   1.16607071583e-12   1.23815957393e-12
| Variables   typ   min   max
[GND Clamp Reference]   0   0   0
[POWER Clamp Reference]   3.3   3   3.6
[Pulldown Reference]   0   0   0
[Pullup Reference]   3.3   3   3.6
[Temperature Range]   25   125   -40
[Voltage Range]   3.3   3   3.6
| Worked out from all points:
|   slope of the pulldown table from 0 to 0.495 V, typ, clamps not added: 28.8 ohm
|   slope of the pullup table from 0 to 0.495 V, typ, clamps not added: 25.9 ohm
|   GND clamp passes 1 mA (typ) near -0.39 V on its own axis
|   POWER clamp passes 1 mA (typ) near -0.44 V on its own axis
|   falling waveform, R_fixture 50, V_fixture 0: 20-80 % time 262ps typ, 451ps min, 152ps max; typ from 2.12 V to 0.002 V
|   falling waveform, R_fixture 50, V_fixture 3.3: 20-80 % time 1.05ns typ, 2.05ns min, 527ps max; typ from 3.3 V to 1.31 V
|   rising waveform, R_fixture 50, V_fixture 0: 20-80 % time 767ps typ, 1.61ns min, 429ps max; typ from 0.002 V to 2.12 V
|   rising waveform, R_fixture 50, V_fixture 3.3: 20-80 % time 212ps typ, 279ps min, 152ps max; typ from 1.31 V to 3.3 V
[GND Clamp]
| Voltage   I(typ)   I(min)   I(max)
-3.3V     -7.219A    -6.55A     -7.983A
-1.117V   -379.7mA   -438.1mA   -545mA
-993.1mV  -190.6mA   -249mA     -198.3mA
-869mV    -46.5mA    -90.69mA   -26.94mA
-744.8mV  -10.3mA    -14.35mA   -13.73mA
-620.7mV  -5.936mA   -4.181mA   -9.061mA
-372.4mV  -657.8uA   -359.5uA   -1.669mA
-248.3mV  -143.8uA   -94.2uA    -265.2uA
6.6V      0A         0A         0A
[POWER Clamp]
| Voltage   I(typ)   I(min)   I(max)
-3.3V     7.219A     6.549A     7.988A
-1.117V   380mA      433mA      551.8mA
-993.1mV  190.2mA    246.7mA    219.2mA
-869mV    45.16mA    97.2mA     48.21mA
-744.8mV  8.611mA    19.76mA    11.76mA
-620.7mV  4.381mA    3.461mA    6.782mA
-372.4mV  212.2uA    289.1uA    754.3uA
-248.3mV  4.207uA    22.11uA    50.1uA
6.6V      0A         0A         0A
[Pulldown]
| Voltage   I(typ)   I(min)   I(max)
-3.3V     -626.9uA   -435.6uA   -859.9uA
-2.234V   -1.441mA   -865.9uA   -2.945mA
-1.738V   -3.6mA     -1.544mA   -14.69mA
-1.117V   -21mA      -8.631mA   -28.37mA
-620.7mV  -18.68mA   -15.57mA   -20.62mA
910.3mV   30.25mA    22.6mA     36.81mA
1.707V    43.32mA    27.4mA     60.5mA
3.797V    44.56mA    22.82mA    67.54mA
4.293V    33.62mA    4.226mA    61.96mA
5.038V    3.515mA    1.083mA    33.12mA
5.659V    1.255mA    654.7uA    6.186mA
6.6V      636.9uA    406.4uA    1.117mA
[Pullup]
| Voltage   I(typ)   I(min)   I(max)
-3.3V     945.3uA    600.7uA    1.404mA
-2.483V   1.788mA    990.6uA    4.397mA
-1.986V   3.964mA    1.605mA    16.05mA
-993.1mV  27.89mA    16.37mA    31.94mA
-620.7mV  22.23mA    18.04mA    24.34mA
910.3mV   -33.88mA   -24.5mA    -40.47mA
1.821V    -54.97mA   -33.38mA   -73.91mA
3.797V    -58.38mA   -28.69mA   -88.41mA
4.417V    -41.38mA   -4.474mA   -78.79mA
5.162V    -5.39mA    -1.252mA   -45.29mA
6.031V    -1.32mA    -671.5uA   -5.792mA
6.6V      -895.7uA   -513.6uA   -1.795mA
[Ramp]
dV/dt_r   1.27003/0.767044n  0.946283/1.60685n  1.48261/0.428636n
dV/dt_f   1.19096/1.05275n  0.819502/2.04907n  1.43017/0.526553n
R_load = 50
[Falling Waveform]
R_fixture = 50
V_fixture = 0
V_fixture_min = 0
V_fixture_max = 0
| Time   V(typ)   V(min)   V(max)
0s        2.119V     1.578V     2.473V
868.2ps   2.119V     1.578V     2.45V
1.081ns   1.771V     1.579V     1.736V
1.203ns   1.556V     1.551V     129.8mV
1.3ns     1.26V      1.315V     7.193mV
1.414ns   175.9mV    1.083V     3.539mV
1.661ns   3.058mV    807mV      3.057mV
1.836ns   2.602mV    71.73mV    2.976mV
2.116ns   2.385mV    2.402mV    2.908mV
333.3ns   1.799mV    1.231mV    2.476mV
[Falling Waveform]
R_fixture = 50
V_fixture = 3.3
V_fixture_min = 3
V_fixture_max = 3.6
| Time   V(typ)   V(min)   V(max)
0s        3.3V       3V         3.6V
1.005ns   3.304V     3V         3.524V
1.13ns    3.278V     3.001V     3.336V
1.33ns    3.145V     3.002V     2.503V
1.532ns   2.734V     2.965V     1.988V
2.007ns   2.141V     2.689V     1.38V
2.807ns   1.527V     2.311V     1.24V
3.797ns   1.358V     1.96V      1.222V
11.95ns   1.315V     1.636V     1.216V
333.3ns   1.315V     1.634V     1.216V
[Rising Waveform]
R_fixture = 50
V_fixture = 0
V_fixture_min = 0
V_fixture_max = 0
| Time   V(typ)   V(min)   V(max)
0s        1.799mV    1.231mV    2.476mV
939.5ps   -2.567mV   1.267mV    55.5mV
1.038ns   6.377mV    -159.5uV   264.8mV
1.166ns   104.2mV    -292.6uV   935.4mV
1.355ns   546.1mV    21.91mV    1.664V
1.789ns   1.346V     386.1mV    2.295V
2.465ns   1.942V     849.9mV    2.426V
4.161ns   2.094V     1.425V     2.469V
12.77ns   2.119V     1.578V     2.473V
333.3ns   2.119V     1.578V     2.473V
[Rising Waveform]
R_fixture = 50
V_fixture = 3.3
V_fixture_min = 3
V_fixture_max = 3.6
| Time   V(typ)   V(min)   V(max)
0s        1.315V     1.634V     1.216V
792.6ps   1.315V     1.634V     1.244V
897.8ps   1.374V     1.634V     1.783V
1.034ns   2.059V     1.656V     3.131V
1.077ns   2.294V     1.753V     3.429V
1.193ns   3.046V     2.123V     3.595V
1.279ns   3.261V     2.348V     3.599V
1.497ns   3.299V     2.945V     3.599V
1.936ns   3.299V     2.999V     3.6V
333.3ns   3.3V       3V         3.6V
[Add Submodel]
| Submodel Name Mode
M16_PBIDIR_HS_08_S_3P30V_T_V All
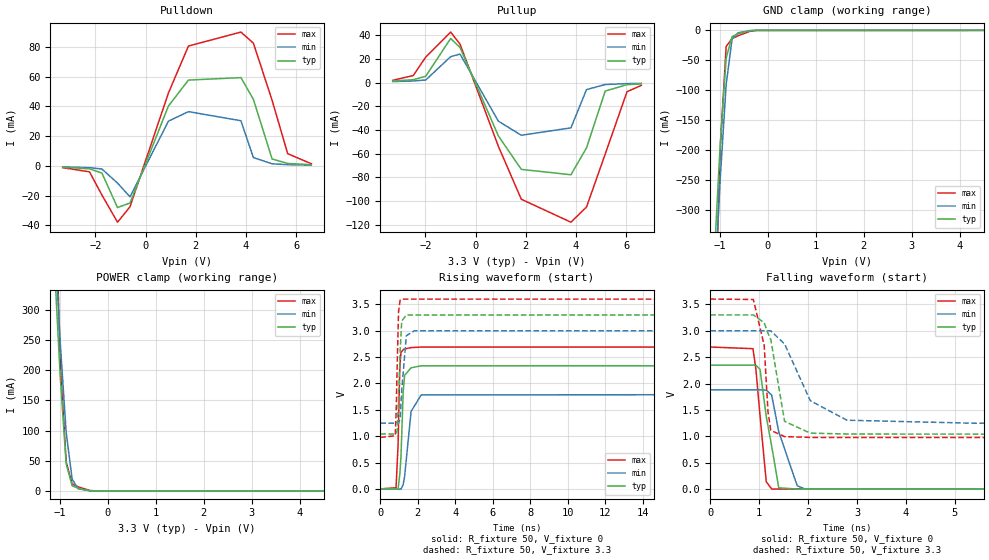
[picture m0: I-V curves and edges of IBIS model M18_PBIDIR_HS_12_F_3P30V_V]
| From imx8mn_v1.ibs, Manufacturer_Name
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[Model] M18_PBIDIR_HS_12_F_3P30V_V
Model_type I/O
Vinl  =  0.99
Vinh  =  2.31
Vmeas =  1.65
| Capacitance   typ   min   max
C_comp   1.22244310993e-12   1.16607071583e-12   1.23815957393e-12
| Variables   typ   min   max
[GND Clamp Reference]   0   0   0
[POWER Clamp Reference]   3.3   3   3.6
[Pulldown Reference]   0   0   0
[Pullup Reference]   3.3   3   3.6
[Temperature Range]   25   125   -40
[Voltage Range]   3.3   3   3.6
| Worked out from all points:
|   slope of the pulldown table from 0 to 0.495 V, typ, clamps not added: 21.6 ohm
|   slope of the pullup table from 0 to 0.495 V, typ, clamps not added: 19.5 ohm
|   GND clamp passes 1 mA (typ) near -0.39 V on its own axis
|   POWER clamp passes 1 mA (typ) near -0.44 V on its own axis
|   falling waveform, R_fixture 50, V_fixture 0: 20-80 % time 230ps typ, 364ps min, 166ps max; typ from 2.35 V to 0.001 V
|   falling waveform, R_fixture 50, V_fixture 3.3: 20-80 % time 227ps typ, 493ps min, 160ps max; typ from 3.3 V to 1.04 V
|   rising waveform, R_fixture 50, V_fixture 0: 20-80 % time 146ps typ, 314ps min, 109ps max; typ from 0.001 V to 2.35 V
|   rising waveform, R_fixture 50, V_fixture 3.3: 20-80 % time 134ps typ, 201ps min, 95.8ps max; typ from 1.04 V to 3.3 V
[GND Clamp]
| Voltage   I(typ)   I(min)   I(max)
-3.3V     -7.219A    -6.55A     -7.983A
-1.117V   -379.7mA   -438.1mA   -545mA
-993.1mV  -190.6mA   -249mA     -198.3mA
-869mV    -46.5mA    -90.69mA   -26.94mA
-744.8mV  -10.3mA    -14.35mA   -13.73mA
-620.7mV  -5.936mA   -4.181mA   -9.061mA
-372.4mV  -657.8uA   -359.5uA   -1.669mA
-248.3mV  -143.8uA   -94.2uA    -265.2uA
6.6V      0A         0A         0A
[POWER Clamp]
| Voltage   I(typ)   I(min)   I(max)
-3.3V     7.219A     6.549A     7.988A
-1.117V   380mA      433mA      551.8mA
-993.1mV  190.2mA    246.7mA    219.2mA
-869mV    45.16mA    97.2mA     48.21mA
-744.8mV  8.611mA    19.76mA    11.76mA
-620.7mV  4.381mA    3.461mA    6.782mA
-372.4mV  212.2uA    289.1uA    754.3uA
-248.3mV  4.207uA    22.11uA    50.1uA
6.6V      0A         0A         0A
[Pulldown]
| Voltage   I(typ)   I(min)   I(max)
-3.3V     -835.8uA   -580.8uA   -1.146mA
-2.234V   -1.922mA   -1.154mA   -3.927mA
-1.738V   -4.8mA     -2.058mA   -19.59mA
-1.117V   -28mA      -11.51mA   -37.83mA
-620.7mV  -24.91mA   -20.76mA   -27.49mA
910.3mV   40.33mA    30.14mA    49.08mA
1.707V    57.77mA    36.54mA    80.67mA
3.797V    59.42mA    30.42mA    90.05mA
4.293V    44.83mA    5.635mA    82.62mA
5.038V    4.687mA    1.444mA    44.15mA
5.659V    1.674mA    872.6uA    8.249mA
6.6V      849.3uA    542.2uA    1.49mA
[Pullup]
| Voltage   I(typ)   I(min)   I(max)
-3.3V     1.261mA    801uA      1.878mA
-2.483V   2.386mA    1.321mA    5.903mA
-1.986V   5.291mA    2.14mA     21.45mA
-993.1mV  37.19mA    21.83mA    42.6mA
-620.7mV  29.64mA    24.05mA    32.46mA
910.3mV   -45.17mA   -32.66mA   -53.96mA
1.821V    -73.3mA    -44.5mA    -98.54mA
3.797V    -77.84mA   -38.25mA   -117.9mA
4.417V    -55.18mA   -5.966mA   -105.1mA
5.162V    -7.187mA   -1.67mA    -60.39mA
6.031V    -1.76mA    -895.2uA   -7.725mA
6.6V      -1.194mA   -684.7uA   -2.394mA
[Ramp]
dV/dt_r   1.40839/0.145714n  1.12833/0.313565n  1.61394/0.109504n
dV/dt_f   1.35439/0.22678n  1.0514/0.492554n  1.573/0.159748n
R_load = 50
[Falling Waveform]
R_fixture = 50
V_fixture = 0
V_fixture_min = 0
V_fixture_max = 0
| Time   V(typ)   V(min)   V(max)
0s        2.349V     1.882V     2.692V
872.9ps   2.349V     1.882V     2.661V
931.5ps   2.347V     1.882V     2.28V
1.017ns   2.27V      1.882V     1.394V
1.144ns   1.379V     1.876V     142.4mV
1.256ns   809.8mV    1.78V      3.193mV
1.4ns     26.62mV    1.087V     2.581mV
1.777ns   1.99mV     64.26mV    2.414mV
1.943ns   1.913mV    1.838mV    2.414mV
333.3ns   1.483mV    1.03mV     2.021mV
[Falling Waveform]
R_fixture = 50
V_fixture = 3.3
V_fixture_min = 3
V_fixture_max = 3.6
| Time   V(typ)   V(min)   V(max)
0s        3.3V       3V         3.6V
880.8ps   3.3V       3V         3.592V
1.102ns   3.152V     3.001V     2.724V
1.179ns   2.954V     3.002V     1.473V
1.237ns   2.834V     2.998V     1.114V
1.519ns   1.284V     2.749V     996mV
2.044ns   1.062V     1.676V     980.6mV
2.795ns   1.045V     1.306V     978.5mV
5.417ns   1.043V     1.249V     978.5mV
333.3ns   1.043V     1.248V     978.3mV
[Rising Waveform]
R_fixture = 50
V_fixture = 0
V_fixture_min = 0
V_fixture_max = 0
| Time   V(typ)   V(min)   V(max)
0s        1.483mV    1.03mV     2.021mV
841.8ps   454uV      1.077mV    22.97mV
949.7ps   773.2uV    848.3uV    836.3mV
1.044ns   284.6mV    -1.176mV   2.333V
1.104ns   604.4mV    -3.691mV   2.586V
1.222ns   1.842V     80.45mV    2.641V
1.299ns   2.155V     238.1mV    2.654V
1.643ns   2.297V     1.469V     2.68V
2.181ns   2.335V     1.783V     2.69V
333.3ns   2.349V     1.882V     2.692V
[Rising Waveform]
R_fixture = 50
V_fixture = 3.3
V_fixture_min = 3
V_fixture_max = 3.6
| Time   V(typ)   V(min)   V(max)
0s        1.043V     1.248V     978.3mV
796.1ps   1.042V     1.248V     1.008V
849.2ps   1.046V     1.248V     1.473V
901.5ps   1.107V     1.248V     2.334V
975.1ps   1.725V     1.248V     3.357V
1.061ns   2.62V      1.339V     3.582V
1.144ns   3.181V     1.868V     3.599V
1.39ns    3.299V     2.907V     3.599V
1.824ns   3.299V     2.999V     3.599V
333.3ns   3.3V       3V         3.6V
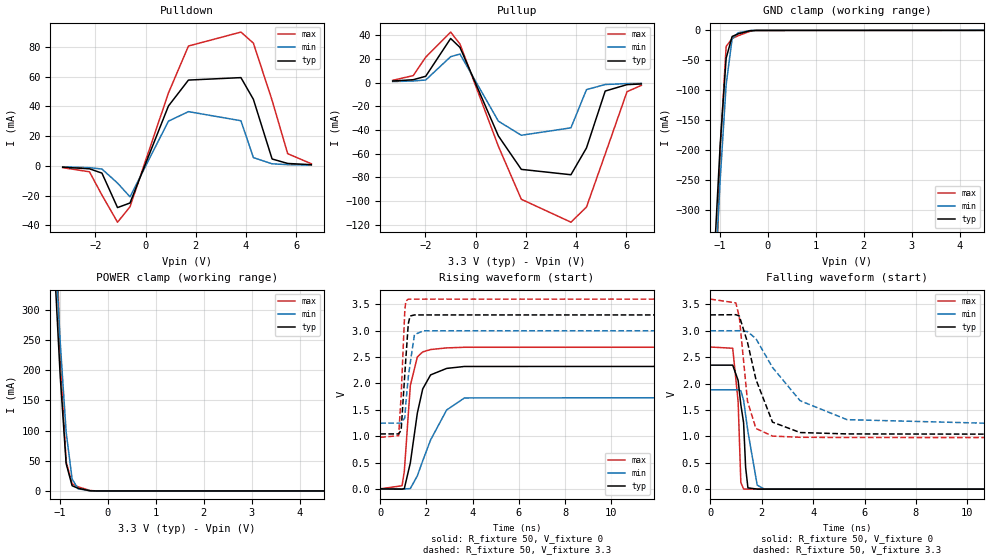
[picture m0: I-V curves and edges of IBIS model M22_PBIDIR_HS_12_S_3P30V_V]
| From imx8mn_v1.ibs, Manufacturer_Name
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[Model] M22_PBIDIR_HS_12_S_3P30V_V
Model_type I/O
Vinl  =  0.99
Vinh  =  2.31
Vmeas =  1.65
| Capacitance   typ   min   max
C_comp   1.22244310993e-12   1.16607071583e-12   1.23815957393e-12
| Variables   typ   min   max
[GND Clamp Reference]   0   0   0
[POWER Clamp Reference]   3.3   3   3.6
[Pulldown Reference]   0   0   0
[Pullup Reference]   3.3   3   3.6
[Temperature Range]   25   125   -40
[Voltage Range]   3.3   3   3.6
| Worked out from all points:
|   slope of the pulldown table from 0 to 0.495 V, typ, clamps not added: 21.6 ohm
|   slope of the pullup table from 0 to 0.495 V, typ, clamps not added: 19.5 ohm
|   GND clamp passes 1 mA (typ) near -0.39 V on its own axis
|   POWER clamp passes 1 mA (typ) near -0.44 V on its own axis
|   falling waveform, R_fixture 50, V_fixture 0: 20-80 % time 258ps typ, 401ps min, 182ps max; typ from 2.35 V to 0.001 V
|   falling waveform, R_fixture 50, V_fixture 3.3: 20-80 % time 727ps typ, 1.72ns min, 353ps max; typ from 3.3 V to 1.04 V
|   rising waveform, R_fixture 50, V_fixture 0: 20-80 % time 530ps typ, 1.18ns min, 290ps max; typ from 0.001 V to 2.35 V
|   rising waveform, R_fixture 50, V_fixture 3.3: 20-80 % time 208ps typ, 267ps min, 165ps max; typ from 1.04 V to 3.3 V
[GND Clamp]
| Voltage   I(typ)   I(min)   I(max)
-3.3V     -7.219A    -6.55A     -7.983A
-1.117V   -379.7mA   -438.1mA   -545mA
-993.1mV  -190.6mA   -249mA     -198.3mA
-869mV    -46.5mA    -90.69mA   -26.94mA
-744.8mV  -10.3mA    -14.35mA   -13.73mA
-620.7mV  -5.936mA   -4.181mA   -9.061mA
-372.4mV  -657.8uA   -359.5uA   -1.669mA
-248.3mV  -143.8uA   -94.2uA    -265.2uA
6.6V      0A         0A         0A
[POWER Clamp]
| Voltage   I(typ)   I(min)   I(max)
-3.3V     7.219A     6.549A     7.988A
-1.117V   380mA      433mA      551.8mA
-993.1mV  190.2mA    246.7mA    219.2mA
-869mV    45.16mA    97.2mA     48.21mA
-744.8mV  8.611mA    19.76mA    11.76mA
-620.7mV  4.381mA    3.461mA    6.782mA
-372.4mV  212.2uA    289.1uA    754.3uA
-248.3mV  4.207uA    22.11uA    50.1uA
6.6V      0A         0A         0A
[Pulldown]
| Voltage   I(typ)   I(min)   I(max)
-3.3V     -835.8uA   -580.8uA   -1.146mA
-2.234V   -1.922mA   -1.154mA   -3.927mA
-1.738V   -4.8mA     -2.058mA   -19.59mA
-1.117V   -28mA      -11.51mA   -37.83mA
-620.7mV  -24.91mA   -20.76mA   -27.49mA
910.3mV   40.33mA    30.14mA    49.08mA
1.707V    57.77mA    36.54mA    80.67mA
3.797V    59.42mA    30.42mA    90.05mA
4.293V    44.83mA    5.635mA    82.62mA
5.038V    4.687mA    1.444mA    44.15mA
5.659V    1.674mA    872.6uA    8.249mA
6.6V      849.3uA    542.2uA    1.49mA
[Pullup]
| Voltage   I(typ)   I(min)   I(max)
-3.3V     1.26mA     801uA      1.872mA
-2.483V   2.385mA    1.321mA    5.866mA
-1.986V   5.286mA    2.14mA     21.4mA
-993.1mV  37.19mA    21.83mA    42.59mA
-620.7mV  29.64mA    24.05mA    32.45mA
910.3mV   -45.17mA   -32.66mA   -53.95mA
1.821V    -73.3mA    -44.5mA    -98.54mA
3.797V    -77.84mA   -38.25mA   -117.9mA
4.417V    -55.18mA   -5.966mA   -105.1mA
5.162V    -7.187mA   -1.67mA    -60.39mA
6.031V    -1.76mA    -895.2uA   -7.723mA
6.6V      -1.194mA   -684.7uA   -2.394mA
[Ramp]
dV/dt_r   1.40839/0.52981n  1.12833/1.17925n  1.61392/0.289645n
dV/dt_f   1.35439/0.726941n  1.0514/1.71809n  1.573/0.35304n
R_load = 50
[Falling Waveform]
R_fixture = 50
V_fixture = 0
V_fixture_min = 0
V_fixture_max = 0
| Time   V(typ)   V(min)   V(max)
0s        2.349V     1.882V     2.692V
872.4ps   2.349V     1.882V     2.669V
1.083ns   2.06V      1.882V     1.663V
1.189ns   1.6V       1.864V     127.2mV
1.296ns   1.26V      1.686V     4.439mV
1.375ns   413.5mV    1.403V     3.139mV
1.465ns   25.65mV    1.089V     2.971mV
1.826ns   2.485mV    76.95mV    2.492mV
2.107ns   2.221mV    2.191mV    2.413mV
333.3ns   1.483mV    1.03mV     2.021mV
[Falling Waveform]
R_fixture = 50
V_fixture = 3.3
V_fixture_min = 3
V_fixture_max = 3.6
| Time   V(typ)   V(min)   V(max)
0s        3.3V       3V         3.6V
994.3ps   3.304V     3V         3.527V
1.129ns   3.28V      3.001V     3.262V
1.448ns   2.781V     2.985V     1.665V
1.775ns   2.079V     2.85V      1.15V
2.421ns   1.27V      2.305V     1.006V
3.496ns   1.073V     1.675V     983.1mV
5.319ns   1.047V     1.317V     978.8mV
10.69ns   1.043V     1.25V      978.3mV
333.3ns   1.043V     1.248V     978.3mV
[Rising Waveform]
R_fixture = 50
V_fixture = 0
V_fixture_min = 0
V_fixture_max = 0
| Time   V(typ)   V(min)   V(max)
0s        1.483mV    1.03mV     2.021mV
942.2ps   -4.328mV   1.004mV    60.49mV
1.041ns   6.947mV    -1.032mV   333.5mV
1.301ns   493.3mV    7.567mV    1.961V
1.605ns   1.439V     248.5mV    2.503V
1.836ns   1.895V     531.8mV    2.598V
2.178ns   2.162V     928.4mV    2.643V
2.872ns   2.285V     1.496V     2.674V
3.642ns   2.322V     1.725V     2.686V
333.3ns   2.349V     1.882V     2.692V
[Rising Waveform]
R_fixture = 50
V_fixture = 3.3
V_fixture_min = 3
V_fixture_max = 3.6
| Time   V(typ)   V(min)   V(max)
0s        1.043V     1.248V     978.3mV
796.5ps   1.043V     1.248V     1.01V
903.8ps   1.116V     1.248V     1.774V
1.064ns   2.191V     1.35V      3.403V
1.11ns    2.491V     1.645V     3.563V
1.213ns   3.132V     2.122V     3.598V
1.291ns   3.279V     2.372V     3.599V
1.48ns    3.299V     2.926V     3.599V
1.874ns   3.299V     2.999V     3.599V
333.3ns   3.3V       3V         3.6V
[Add Submodel]
| Submodel Name Mode
M22_PBIDIR_HS_12_S_3P30V_T_V All
